VERSION 5.8 ;
BUSBITCHARS "[]" ;
DIVIDERCHAR "/" ;
UNITS
    DATABASE MICRONS 1000 ;
END UNITS

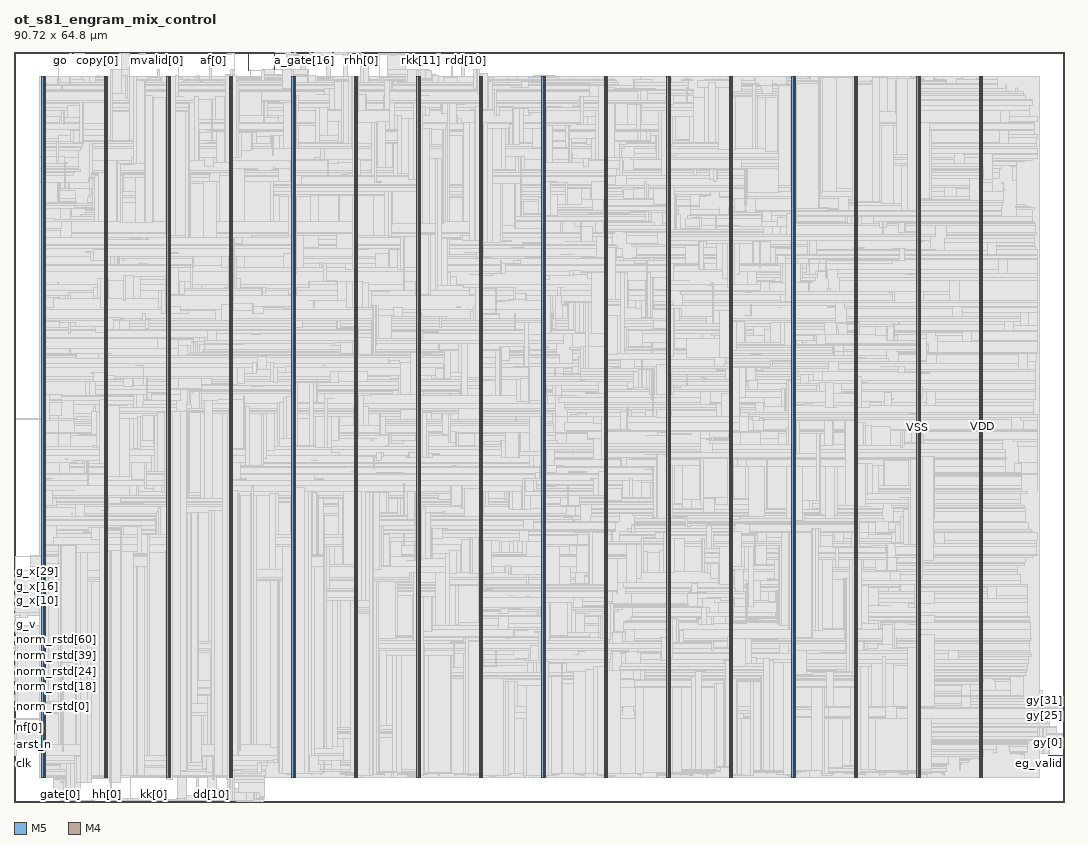
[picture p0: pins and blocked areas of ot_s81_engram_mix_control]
MACRO ot_s81_engram_mix_control
  FOREIGN ot_s81_engram_mix_control 0 0 ;
  CLASS BLOCK ;
  SIZE 90.72 BY 64.8 ;
  PIN a_gate[0]
    DIRECTION OUTPUT ;
    USE SIGNAL ;
    PORT
      LAYER M5 ;
        RECT  23.52 64.716 23.544 64.8 ;
    END
  END a_gate[0]
  PIN a_gate[10]
    DIRECTION OUTPUT ;
    USE SIGNAL ;
    PORT
      LAYER M5 ;
        RECT  24.48 64.716 24.504 64.8 ;
    END
  END a_gate[10]
  PIN a_gate[11]
    DIRECTION OUTPUT ;
    USE SIGNAL ;
    PORT
      LAYER M5 ;
        RECT  24.576 64.716 24.6 64.8 ;
    END
  END a_gate[11]
  PIN a_gate[12]
    DIRECTION OUTPUT ;
    USE SIGNAL ;
    PORT
      LAYER M5 ;
        RECT  24.672 64.716 24.696 64.8 ;
    END
  END a_gate[12]
  PIN a_gate[13]
    DIRECTION OUTPUT ;
    USE SIGNAL ;
    PORT
      LAYER M5 ;
        RECT  24.768 64.716 24.792 64.8 ;
    END
  END a_gate[13]
  PIN a_gate[14]
    DIRECTION OUTPUT ;
    USE SIGNAL ;
    PORT
      LAYER M5 ;
        RECT  24.864 64.716 24.888 64.8 ;
    END
  END a_gate[14]
  PIN a_gate[15]
    DIRECTION OUTPUT ;
    USE SIGNAL ;
    PORT
      LAYER M5 ;
        RECT  24.96 64.716 24.984 64.8 ;
    END
  END a_gate[15]
  PIN a_gate[16]
    DIRECTION OUTPUT ;
    USE SIGNAL ;
    PORT
      LAYER M5 ;
        RECT  25.056 64.716 25.08 64.8 ;
    END
  END a_gate[16]
  PIN a_gate[17]
    DIRECTION OUTPUT ;
    USE SIGNAL ;
    PORT
      LAYER M5 ;
        RECT  25.152 64.716 25.176 64.8 ;
    END
  END a_gate[17]
  PIN a_gate[18]
    DIRECTION OUTPUT ;
    USE SIGNAL ;
    PORT
      LAYER M5 ;
        RECT  25.248 64.716 25.272 64.8 ;
    END
  END a_gate[18]
  PIN a_gate[19]
    DIRECTION OUTPUT ;
    USE SIGNAL ;
    PORT
      LAYER M5 ;
        RECT  25.344 64.716 25.368 64.8 ;
    END
  END a_gate[19]
  PIN a_gate[1]
    DIRECTION OUTPUT ;
    USE SIGNAL ;
    PORT
      LAYER M5 ;
        RECT  23.616 64.716 23.64 64.8 ;
    END
  END a_gate[1]
  PIN a_gate[20]
    DIRECTION OUTPUT ;
    USE SIGNAL ;
    PORT
      LAYER M5 ;
        RECT  25.44 64.716 25.464 64.8 ;
    END
  END a_gate[20]
  PIN a_gate[21]
    DIRECTION OUTPUT ;
    USE SIGNAL ;
    PORT
      LAYER M5 ;
        RECT  25.536 64.716 25.56 64.8 ;
    END
  END a_gate[21]
  PIN a_gate[22]
    DIRECTION OUTPUT ;
    USE SIGNAL ;
    PORT
      LAYER M5 ;
        RECT  25.632 64.716 25.656 64.8 ;
    END
  END a_gate[22]
  PIN a_gate[23]
    DIRECTION OUTPUT ;
    USE SIGNAL ;
    PORT
      LAYER M5 ;
        RECT  25.728 64.716 25.752 64.8 ;
    END
  END a_gate[23]
  PIN a_gate[24]
    DIRECTION OUTPUT ;
    USE SIGNAL ;
    PORT
      LAYER M5 ;
        RECT  25.824 64.716 25.848 64.8 ;
    END
  END a_gate[24]
  PIN a_gate[25]
    DIRECTION OUTPUT ;
    USE SIGNAL ;
    PORT
      LAYER M5 ;
        RECT  25.92 64.716 25.944 64.8 ;
    END
  END a_gate[25]
  PIN a_gate[26]
    DIRECTION OUTPUT ;
    USE SIGNAL ;
    PORT
      LAYER M5 ;
        RECT  26.016 64.716 26.04 64.8 ;
    END
  END a_gate[26]
  PIN a_gate[27]
    DIRECTION OUTPUT ;
    USE SIGNAL ;
    PORT
      LAYER M5 ;
        RECT  26.112 64.716 26.136 64.8 ;
    END
  END a_gate[27]
  PIN a_gate[28]
    DIRECTION OUTPUT ;
    USE SIGNAL ;
    PORT
      LAYER M5 ;
        RECT  26.208 64.716 26.232 64.8 ;
    END
  END a_gate[28]
  PIN a_gate[29]
    DIRECTION OUTPUT ;
    USE SIGNAL ;
    PORT
      LAYER M5 ;
        RECT  26.304 64.716 26.328 64.8 ;
    END
  END a_gate[29]
  PIN a_gate[2]
    DIRECTION OUTPUT ;
    USE SIGNAL ;
    PORT
      LAYER M5 ;
        RECT  23.712 64.716 23.736 64.8 ;
    END
  END a_gate[2]
  PIN a_gate[30]
    DIRECTION OUTPUT ;
    USE SIGNAL ;
    PORT
      LAYER M5 ;
        RECT  26.4 64.716 26.424 64.8 ;
    END
  END a_gate[30]
  PIN a_gate[31]
    DIRECTION OUTPUT ;
    USE SIGNAL ;
    PORT
      LAYER M5 ;
        RECT  26.496 64.716 26.52 64.8 ;
    END
  END a_gate[31]
  PIN a_gate[3]
    DIRECTION OUTPUT ;
    USE SIGNAL ;
    PORT
      LAYER M5 ;
        RECT  23.808 64.716 23.832 64.8 ;
    END
  END a_gate[3]
  PIN a_gate[4]
    DIRECTION OUTPUT ;
    USE SIGNAL ;
    PORT
      LAYER M5 ;
        RECT  23.904 64.716 23.928 64.8 ;
    END
  END a_gate[4]
  PIN a_gate[5]
    DIRECTION OUTPUT ;
    USE SIGNAL ;
    PORT
      LAYER M5 ;
        RECT  24 64.716 24.024 64.8 ;
    END
  END a_gate[5]
  PIN a_gate[6]
    DIRECTION OUTPUT ;
    USE SIGNAL ;
    PORT
      LAYER M5 ;
        RECT  24.096 64.716 24.12 64.8 ;
    END
  END a_gate[6]
  PIN a_gate[7]
    DIRECTION OUTPUT ;
    USE SIGNAL ;
    PORT
      LAYER M5 ;
        RECT  24.192 64.716 24.216 64.8 ;
    END
  END a_gate[7]
  PIN a_gate[8]
    DIRECTION OUTPUT ;
    USE SIGNAL ;
    PORT
      LAYER M5 ;
        RECT  24.288 64.716 24.312 64.8 ;
    END
  END a_gate[8]
  PIN a_gate[9]
    DIRECTION OUTPUT ;
    USE SIGNAL ;
    PORT
      LAYER M5 ;
        RECT  24.384 64.716 24.408 64.8 ;
    END
  END a_gate[9]
  PIN add_copy[0]
    DIRECTION INPUT ;
    USE SIGNAL ;
    PORT
      LAYER M5 ;
        RECT  18.528 64.716 18.552 64.8 ;
    END
  END add_copy[0]
  PIN add_copy[1]
    DIRECTION INPUT ;
    USE SIGNAL ;
    PORT
      LAYER M5 ;
        RECT  18.624 64.716 18.648 64.8 ;
    END
  END add_copy[1]
  PIN add_copy[2]
    DIRECTION INPUT ;
    USE SIGNAL ;
    PORT
      LAYER M5 ;
        RECT  18.72 64.716 18.744 64.8 ;
    END
  END add_copy[2]
  PIN add_copy[3]
    DIRECTION INPUT ;
    USE SIGNAL ;
    PORT
      LAYER M5 ;
        RECT  18.816 64.716 18.84 64.8 ;
    END
  END add_copy[3]
  PIN add_copy[4]
    DIRECTION INPUT ;
    USE SIGNAL ;
    PORT
      LAYER M5 ;
        RECT  18.912 64.716 18.936 64.8 ;
    END
  END add_copy[4]
  PIN add_copy[5]
    DIRECTION INPUT ;
    USE SIGNAL ;
    PORT
      LAYER M5 ;
        RECT  19.008 64.716 19.032 64.8 ;
    END
  END add_copy[5]
  PIN add_copy[6]
    DIRECTION INPUT ;
    USE SIGNAL ;
    PORT
      LAYER M5 ;
        RECT  19.104 64.716 19.128 64.8 ;
    END
  END add_copy[6]
  PIN add_copy[7]
    DIRECTION INPUT ;
    USE SIGNAL ;
    PORT
      LAYER M5 ;
        RECT  19.2 64.716 19.224 64.8 ;
    END
  END add_copy[7]
  PIN af[0]
    DIRECTION INPUT ;
    USE SIGNAL ;
    PORT
      LAYER M5 ;
        RECT  17.184 64.716 17.208 64.8 ;
    END
  END af[0]
  PIN af[1]
    DIRECTION INPUT ;
    USE SIGNAL ;
    PORT
      LAYER M5 ;
        RECT  17.28 64.716 17.304 64.8 ;
    END
  END af[1]
  PIN af[2]
    DIRECTION INPUT ;
    USE SIGNAL ;
    PORT
      LAYER M5 ;
        RECT  17.376 64.716 17.4 64.8 ;
    END
  END af[2]
  PIN af[3]
    DIRECTION INPUT ;
    USE SIGNAL ;
    PORT
      LAYER M5 ;
        RECT  17.472 64.716 17.496 64.8 ;
    END
  END af[3]
  PIN arst_n
    DIRECTION INPUT ;
    USE SIGNAL ;
    PORT
      LAYER M4 ;
        RECT  0 4.992 0.084 5.016 ;
    END
  END arst_n
  PIN avalid[0]
    DIRECTION INPUT ;
    USE SIGNAL ;
    PORT
      LAYER M5 ;
        RECT  15.84 64.716 15.864 64.8 ;
    END
  END avalid[0]
  PIN avalid[1]
    DIRECTION INPUT ;
    USE SIGNAL ;
    PORT
      LAYER M5 ;
        RECT  15.936 64.716 15.96 64.8 ;
    END
  END avalid[1]
  PIN avalid[2]
    DIRECTION INPUT ;
    USE SIGNAL ;
    PORT
      LAYER M5 ;
        RECT  16.032 64.716 16.056 64.8 ;
    END
  END avalid[2]
  PIN avalid[3]
    DIRECTION INPUT ;
    USE SIGNAL ;
    PORT
      LAYER M5 ;
        RECT  16.128 64.716 16.152 64.8 ;
    END
  END avalid[3]
  PIN clk
    DIRECTION INPUT ;
    USE SIGNAL ;
    PORT
      LAYER M4 ;
        RECT  0 4.032 0.084 4.056 ;
    END
  END clk
  PIN copy[0]
    DIRECTION INPUT ;
    USE SIGNAL ;
    PORT
      LAYER M5 ;
        RECT  7.2 64.716 7.224 64.8 ;
    END
  END copy[0]
  PIN copy[1]
    DIRECTION INPUT ;
    USE SIGNAL ;
    PORT
      LAYER M5 ;
        RECT  7.296 64.716 7.32 64.8 ;
    END
  END copy[1]
  PIN dd[0]
    DIRECTION OUTPUT ;
    USE SIGNAL ;
    PORT
      LAYER M5 ;
        RECT  16.128 0 16.152 0.084 ;
    END
  END dd[0]
  PIN dd[10]
    DIRECTION OUTPUT ;
    USE SIGNAL ;
    PORT
      LAYER M5 ;
        RECT  17.088 0 17.112 0.084 ;
    END
  END dd[10]
  PIN dd[11]
    DIRECTION OUTPUT ;
    USE SIGNAL ;
    PORT
      LAYER M5 ;
        RECT  17.184 0 17.208 0.084 ;
    END
  END dd[11]
  PIN dd[12]
    DIRECTION OUTPUT ;
    USE SIGNAL ;
    PORT
      LAYER M5 ;
        RECT  17.28 0 17.304 0.084 ;
    END
  END dd[12]
  PIN dd[13]
    DIRECTION OUTPUT ;
    USE SIGNAL ;
    PORT
      LAYER M5 ;
        RECT  17.376 0 17.4 0.084 ;
    END
  END dd[13]
  PIN dd[14]
    DIRECTION OUTPUT ;
    USE SIGNAL ;
    PORT
      LAYER M5 ;
        RECT  17.472 0 17.496 0.084 ;
    END
  END dd[14]
  PIN dd[15]
    DIRECTION OUTPUT ;
    USE SIGNAL ;
    PORT
      LAYER M5 ;
        RECT  17.568 0 17.592 0.084 ;
    END
  END dd[15]
  PIN dd[16]
    DIRECTION OUTPUT ;
    USE SIGNAL ;
    PORT
      LAYER M5 ;
        RECT  17.664 0 17.688 0.084 ;
    END
  END dd[16]
  PIN dd[17]
    DIRECTION OUTPUT ;
    USE SIGNAL ;
    PORT
      LAYER M5 ;
        RECT  17.76 0 17.784 0.084 ;
    END
  END dd[17]
  PIN dd[18]
    DIRECTION OUTPUT ;
    USE SIGNAL ;
    PORT
      LAYER M5 ;
        RECT  17.856 0 17.88 0.084 ;
    END
  END dd[18]
  PIN dd[19]
    DIRECTION OUTPUT ;
    USE SIGNAL ;
    PORT
      LAYER M5 ;
        RECT  17.952 0 17.976 0.084 ;
    END
  END dd[19]
  PIN dd[1]
    DIRECTION OUTPUT ;
    USE SIGNAL ;
    PORT
      LAYER M5 ;
        RECT  16.224 0 16.248 0.084 ;
    END
  END dd[1]
  PIN dd[20]
    DIRECTION OUTPUT ;
    USE SIGNAL ;
    PORT
      LAYER M5 ;
        RECT  18.048 0 18.072 0.084 ;
    END
  END dd[20]
  PIN dd[21]
    DIRECTION OUTPUT ;
    USE SIGNAL ;
    PORT
      LAYER M5 ;
        RECT  18.144 0 18.168 0.084 ;
    END
  END dd[21]
  PIN dd[22]
    DIRECTION OUTPUT ;
    USE SIGNAL ;
    PORT
      LAYER M5 ;
        RECT  18.24 0 18.264 0.084 ;
    END
  END dd[22]
  PIN dd[23]
    DIRECTION OUTPUT ;
    USE SIGNAL ;
    PORT
      LAYER M5 ;
        RECT  18.336 0 18.36 0.084 ;
    END
  END dd[23]
  PIN dd[24]
    DIRECTION OUTPUT ;
    USE SIGNAL ;
    PORT
      LAYER M5 ;
        RECT  18.432 0 18.456 0.084 ;
    END
  END dd[24]
  PIN dd[25]
    DIRECTION OUTPUT ;
    USE SIGNAL ;
    PORT
      LAYER M5 ;
        RECT  18.528 0 18.552 0.084 ;
    END
  END dd[25]
  PIN dd[26]
    DIRECTION OUTPUT ;
    USE SIGNAL ;
    PORT
      LAYER M5 ;
        RECT  18.624 0 18.648 0.084 ;
    END
  END dd[26]
  PIN dd[27]
    DIRECTION OUTPUT ;
    USE SIGNAL ;
    PORT
      LAYER M5 ;
        RECT  18.72 0 18.744 0.084 ;
    END
  END dd[27]
  PIN dd[28]
    DIRECTION OUTPUT ;
    USE SIGNAL ;
    PORT
      LAYER M5 ;
        RECT  18.816 0 18.84 0.084 ;
    END
  END dd[28]
  PIN dd[29]
    DIRECTION OUTPUT ;
    USE SIGNAL ;
    PORT
      LAYER M5 ;
        RECT  18.912 0 18.936 0.084 ;
    END
  END dd[29]
  PIN dd[2]
    DIRECTION OUTPUT ;
    USE SIGNAL ;
    PORT
      LAYER M5 ;
        RECT  16.32 0 16.344 0.084 ;
    END
  END dd[2]
  PIN dd[30]
    DIRECTION OUTPUT ;
    USE SIGNAL ;
    PORT
      LAYER M5 ;
        RECT  19.008 0 19.032 0.084 ;
    END
  END dd[30]
  PIN dd[31]
    DIRECTION OUTPUT ;
    USE SIGNAL ;
    PORT
      LAYER M5 ;
        RECT  19.104 0 19.128 0.084 ;
    END
  END dd[31]
  PIN dd[3]
    DIRECTION OUTPUT ;
    USE SIGNAL ;
    PORT
      LAYER M5 ;
        RECT  16.416 0 16.44 0.084 ;
    END
  END dd[3]
  PIN dd[4]
    DIRECTION OUTPUT ;
    USE SIGNAL ;
    PORT
      LAYER M5 ;
        RECT  16.512 0 16.536 0.084 ;
    END
  END dd[4]
  PIN dd[5]
    DIRECTION OUTPUT ;
    USE SIGNAL ;
    PORT
      LAYER M5 ;
        RECT  16.608 0 16.632 0.084 ;
    END
  END dd[5]
  PIN dd[6]
    DIRECTION OUTPUT ;
    USE SIGNAL ;
    PORT
      LAYER M5 ;
        RECT  16.704 0 16.728 0.084 ;
    END
  END dd[6]
  PIN dd[7]
    DIRECTION OUTPUT ;
    USE SIGNAL ;
    PORT
      LAYER M5 ;
        RECT  16.8 0 16.824 0.084 ;
    END
  END dd[7]
  PIN dd[8]
    DIRECTION OUTPUT ;
    USE SIGNAL ;
    PORT
      LAYER M5 ;
        RECT  16.896 0 16.92 0.084 ;
    END
  END dd[8]
  PIN dd[9]
    DIRECTION OUTPUT ;
    USE SIGNAL ;
    PORT
      LAYER M5 ;
        RECT  16.992 0 17.016 0.084 ;
    END
  END dd[9]
  PIN eg_valid
    DIRECTION INPUT ;
    USE SIGNAL ;
    PORT
      LAYER M4 ;
        RECT  90.636 4.032 90.72 4.056 ;
    END
    PORT
      LAYER M4 ;
        RECT  89.413 4.032 90.684 4.056 ;
    END
  END eg_valid
  PIN fault
    DIRECTION OUTPUT ;
    USE SIGNAL ;
    PORT
      LAYER M5 ;
        RECT  22.464 64.716 22.488 64.8 ;
    END
    PORT
      LAYER M5 ;
        RECT  22.464 63.301 22.488 64.784 ;
    END
  END fault
  PIN g_fault[0]
    DIRECTION INPUT ;
    USE SIGNAL ;
    PORT
      LAYER M4 ;
        RECT  90.636 9.12 90.72 9.144 ;
    END
  END g_fault[0]
  PIN g_fault[1]
    DIRECTION INPUT ;
    USE SIGNAL ;
    PORT
      LAYER M4 ;
        RECT  90.636 9.216 90.72 9.24 ;
    END
  END g_fault[1]
  PIN g_v
    DIRECTION OUTPUT ;
    USE SIGNAL ;
    PORT
      LAYER M4 ;
        RECT  0 15.36 0.084 15.384 ;
    END
    PORT
      LAYER M4 ;
        RECT  0.06 15.36 0.137 15.384 ;
    END
  END g_v
  PIN g_x[0]
    DIRECTION OUTPUT ;
    USE SIGNAL ;
    PORT
      LAYER M4 ;
        RECT  0 16.416 0.084 16.44 ;
    END
  END g_x[0]
  PIN g_x[10]
    DIRECTION OUTPUT ;
    USE SIGNAL ;
    PORT
      LAYER M4 ;
        RECT  0 17.376 0.084 17.4 ;
    END
  END g_x[10]
  PIN g_x[11]
    DIRECTION OUTPUT ;
    USE SIGNAL ;
    PORT
      LAYER M4 ;
        RECT  0 17.472 0.084 17.496 ;
    END
  END g_x[11]
  PIN g_x[12]
    DIRECTION OUTPUT ;
    USE SIGNAL ;
    PORT
      LAYER M4 ;
        RECT  0 17.568 0.084 17.592 ;
    END
  END g_x[12]
  PIN g_x[13]
    DIRECTION OUTPUT ;
    USE SIGNAL ;
    PORT
      LAYER M4 ;
        RECT  0 17.664 0.084 17.688 ;
    END
  END g_x[13]
  PIN g_x[14]
    DIRECTION OUTPUT ;
    USE SIGNAL ;
    PORT
      LAYER M4 ;
        RECT  0 17.76 0.084 17.784 ;
    END
  END g_x[14]
  PIN g_x[15]
    DIRECTION OUTPUT ;
    USE SIGNAL ;
    PORT
      LAYER M4 ;
        RECT  0 17.856 0.084 17.88 ;
    END
  END g_x[15]
  PIN g_x[16]
    DIRECTION OUTPUT ;
    USE SIGNAL ;
    PORT
      LAYER M4 ;
        RECT  0 17.952 0.084 17.976 ;
    END
  END g_x[16]
  PIN g_x[17]
    DIRECTION OUTPUT ;
    USE SIGNAL ;
    PORT
      LAYER M4 ;
        RECT  0 18.048 0.084 18.072 ;
    END
  END g_x[17]
  PIN g_x[18]
    DIRECTION OUTPUT ;
    USE SIGNAL ;
    PORT
      LAYER M4 ;
        RECT  0 18.144 0.084 18.168 ;
    END
  END g_x[18]
  PIN g_x[19]
    DIRECTION OUTPUT ;
    USE SIGNAL ;
    PORT
      LAYER M4 ;
        RECT  0 18.24 0.084 18.264 ;
    END
  END g_x[19]
  PIN g_x[1]
    DIRECTION OUTPUT ;
    USE SIGNAL ;
    PORT
      LAYER M4 ;
        RECT  0 16.512 0.084 16.536 ;
    END
  END g_x[1]
  PIN g_x[20]
    DIRECTION OUTPUT ;
    USE SIGNAL ;
    PORT
      LAYER M4 ;
        RECT  0 18.336 0.084 18.36 ;
    END
  END g_x[20]
  PIN g_x[21]
    DIRECTION OUTPUT ;
    USE SIGNAL ;
    PORT
      LAYER M4 ;
        RECT  0 18.432 0.084 18.456 ;
    END
  END g_x[21]
  PIN g_x[22]
    DIRECTION OUTPUT ;
    USE SIGNAL ;
    PORT
      LAYER M4 ;
        RECT  0 18.528 0.084 18.552 ;
    END
  END g_x[22]
  PIN g_x[23]
    DIRECTION OUTPUT ;
    USE SIGNAL ;
    PORT
      LAYER M4 ;
        RECT  0 18.624 0.084 18.648 ;
    END
  END g_x[23]
  PIN g_x[24]
    DIRECTION OUTPUT ;
    USE SIGNAL ;
    PORT
      LAYER M4 ;
        RECT  0 18.72 0.084 18.744 ;
    END
  END g_x[24]
  PIN g_x[25]
    DIRECTION OUTPUT ;
    USE SIGNAL ;
    PORT
      LAYER M4 ;
        RECT  0 18.816 0.084 18.84 ;
    END
  END g_x[25]
  PIN g_x[26]
    DIRECTION OUTPUT ;
    USE SIGNAL ;
    PORT
      LAYER M4 ;
        RECT  0 18.912 0.084 18.936 ;
    END
  END g_x[26]
  PIN g_x[27]
    DIRECTION OUTPUT ;
    USE SIGNAL ;
    PORT
      LAYER M4 ;
        RECT  0 19.008 0.084 19.032 ;
    END
  END g_x[27]
  PIN g_x[28]
    DIRECTION OUTPUT ;
    USE SIGNAL ;
    PORT
      LAYER M4 ;
        RECT  0 19.104 0.084 19.128 ;
    END
  END g_x[28]
  PIN g_x[29]
    DIRECTION OUTPUT ;
    USE SIGNAL ;
    PORT
      LAYER M4 ;
        RECT  0 19.2 0.084 19.224 ;
    END
  END g_x[29]
  PIN g_x[2]
    DIRECTION OUTPUT ;
    USE SIGNAL ;
    PORT
      LAYER M4 ;
        RECT  0 16.608 0.084 16.632 ;
    END
  END g_x[2]
  PIN g_x[30]
    DIRECTION OUTPUT ;
    USE SIGNAL ;
    PORT
      LAYER M4 ;
        RECT  0 19.296 0.084 19.32 ;
    END
  END g_x[30]
  PIN g_x[31]
    DIRECTION OUTPUT ;
    USE SIGNAL ;
    PORT
      LAYER M4 ;
        RECT  0 19.392 0.084 19.416 ;
    END
  END g_x[31]
  PIN g_x[3]
    DIRECTION OUTPUT ;
    USE SIGNAL ;
    PORT
      LAYER M4 ;
        RECT  0 16.704 0.084 16.728 ;
    END
  END g_x[3]
  PIN g_x[4]
    DIRECTION OUTPUT ;
    USE SIGNAL ;
    PORT
      LAYER M4 ;
        RECT  0 16.8 0.084 16.824 ;
    END
  END g_x[4]
  PIN g_x[5]
    DIRECTION OUTPUT ;
    USE SIGNAL ;
    PORT
      LAYER M4 ;
        RECT  0 16.896 0.084 16.92 ;
    END
  END g_x[5]
  PIN g_x[6]
    DIRECTION OUTPUT ;
    USE SIGNAL ;
    PORT
      LAYER M4 ;
        RECT  0 16.992 0.084 17.016 ;
    END
  END g_x[6]
  PIN g_x[7]
    DIRECTION OUTPUT ;
    USE SIGNAL ;
    PORT
      LAYER M4 ;
        RECT  0 17.088 0.084 17.112 ;
    END
  END g_x[7]
  PIN g_x[8]
    DIRECTION OUTPUT ;
    USE SIGNAL ;
    PORT
      LAYER M4 ;
        RECT  0 17.184 0.084 17.208 ;
    END
  END g_x[8]
  PIN g_x[9]
    DIRECTION OUTPUT ;
    USE SIGNAL ;
    PORT
      LAYER M4 ;
        RECT  0 17.28 0.084 17.304 ;
    END
  END g_x[9]
  PIN gate[0]
    DIRECTION OUTPUT ;
    USE SIGNAL ;
    PORT
      LAYER M5 ;
        RECT  4.032 0 4.056 0.084 ;
    END
  END gate[0]
  PIN gate[10]
    DIRECTION OUTPUT ;
    USE SIGNAL ;
    PORT
      LAYER M5 ;
        RECT  4.992 0 5.016 0.084 ;
    END
  END gate[10]
  PIN gate[11]
    DIRECTION OUTPUT ;
    USE SIGNAL ;
    PORT
      LAYER M5 ;
        RECT  5.088 0 5.112 0.084 ;
    END
  END gate[11]
  PIN gate[12]
    DIRECTION OUTPUT ;
    USE SIGNAL ;
    PORT
      LAYER M5 ;
        RECT  5.184 0 5.208 0.084 ;
    END
  END gate[12]
  PIN gate[13]
    DIRECTION OUTPUT ;
    USE SIGNAL ;
    PORT
      LAYER M5 ;
        RECT  5.28 0 5.304 0.084 ;
    END
  END gate[13]
  PIN gate[14]
    DIRECTION OUTPUT ;
    USE SIGNAL ;
    PORT
      LAYER M5 ;
        RECT  5.376 0 5.4 0.084 ;
    END
  END gate[14]
  PIN gate[15]
    DIRECTION OUTPUT ;
    USE SIGNAL ;
    PORT
      LAYER M5 ;
        RECT  5.472 0 5.496 0.084 ;
    END
  END gate[15]
  PIN gate[16]
    DIRECTION OUTPUT ;
    USE SIGNAL ;
    PORT
      LAYER M5 ;
        RECT  5.568 0 5.592 0.084 ;
    END
  END gate[16]
  PIN gate[17]
    DIRECTION OUTPUT ;
    USE SIGNAL ;
    PORT
      LAYER M5 ;
        RECT  5.664 0 5.688 0.084 ;
    END
  END gate[17]
  PIN gate[18]
    DIRECTION OUTPUT ;
    USE SIGNAL ;
    PORT
      LAYER M5 ;
        RECT  5.76 0 5.784 0.084 ;
    END
  END gate[18]
  PIN gate[19]
    DIRECTION OUTPUT ;
    USE SIGNAL ;
    PORT
      LAYER M5 ;
        RECT  5.856 0 5.88 0.084 ;
    END
  END gate[19]
  PIN gate[1]
    DIRECTION OUTPUT ;
    USE SIGNAL ;
    PORT
      LAYER M5 ;
        RECT  4.128 0 4.152 0.084 ;
    END
  END gate[1]
  PIN gate[20]
    DIRECTION OUTPUT ;
    USE SIGNAL ;
    PORT
      LAYER M5 ;
        RECT  5.952 0 5.976 0.084 ;
    END
  END gate[20]
  PIN gate[21]
    DIRECTION OUTPUT ;
    USE SIGNAL ;
    PORT
      LAYER M5 ;
        RECT  6.048 0 6.072 0.084 ;
    END
  END gate[21]
  PIN gate[22]
    DIRECTION OUTPUT ;
    USE SIGNAL ;
    PORT
      LAYER M5 ;
        RECT  6.144 0 6.168 0.084 ;
    END
  END gate[22]
  PIN gate[23]
    DIRECTION OUTPUT ;
    USE SIGNAL ;
    PORT
      LAYER M5 ;
        RECT  6.24 0 6.264 0.084 ;
    END
  END gate[23]
  PIN gate[24]
    DIRECTION OUTPUT ;
    USE SIGNAL ;
    PORT
      LAYER M5 ;
        RECT  6.336 0 6.36 0.084 ;
    END
  END gate[24]
  PIN gate[25]
    DIRECTION OUTPUT ;
    USE SIGNAL ;
    PORT
      LAYER M5 ;
        RECT  6.432 0 6.456 0.084 ;
    END
  END gate[25]
  PIN gate[26]
    DIRECTION OUTPUT ;
    USE SIGNAL ;
    PORT
      LAYER M5 ;
        RECT  6.528 0 6.552 0.084 ;
    END
  END gate[26]
  PIN gate[27]
    DIRECTION OUTPUT ;
    USE SIGNAL ;
    PORT
      LAYER M5 ;
        RECT  6.624 0 6.648 0.084 ;
    END
  END gate[27]
  PIN gate[28]
    DIRECTION OUTPUT ;
    USE SIGNAL ;
    PORT
      LAYER M5 ;
        RECT  6.72 0 6.744 0.084 ;
    END
  END gate[28]
  PIN gate[29]
    DIRECTION OUTPUT ;
    USE SIGNAL ;
    PORT
      LAYER M5 ;
        RECT  6.816 0 6.84 0.084 ;
    END
  END gate[29]
  PIN gate[2]
    DIRECTION OUTPUT ;
    USE SIGNAL ;
    PORT
      LAYER M5 ;
        RECT  4.224 0 4.248 0.084 ;
    END
  END gate[2]
  PIN gate[30]
    DIRECTION OUTPUT ;
    USE SIGNAL ;
    PORT
      LAYER M5 ;
        RECT  6.912 0 6.936 0.084 ;
    END
  END gate[30]
  PIN gate[31]
    DIRECTION OUTPUT ;
    USE SIGNAL ;
    PORT
      LAYER M5 ;
        RECT  7.008 0 7.032 0.084 ;
    END
  END gate[31]
  PIN gate[3]
    DIRECTION OUTPUT ;
    USE SIGNAL ;
    PORT
      LAYER M5 ;
        RECT  4.32 0 4.344 0.084 ;
    END
  END gate[3]
  PIN gate[4]
    DIRECTION OUTPUT ;
    USE SIGNAL ;
    PORT
      LAYER M5 ;
        RECT  4.416 0 4.44 0.084 ;
    END
  END gate[4]
  PIN gate[5]
    DIRECTION OUTPUT ;
    USE SIGNAL ;
    PORT
      LAYER M5 ;
        RECT  4.512 0 4.536 0.084 ;
    END
  END gate[5]
  PIN gate[6]
    DIRECTION OUTPUT ;
    USE SIGNAL ;
    PORT
      LAYER M5 ;
        RECT  4.608 0 4.632 0.084 ;
    END
  END gate[6]
  PIN gate[7]
    DIRECTION OUTPUT ;
    USE SIGNAL ;
    PORT
      LAYER M5 ;
        RECT  4.704 0 4.728 0.084 ;
    END
  END gate[7]
  PIN gate[8]
    DIRECTION OUTPUT ;
    USE SIGNAL ;
    PORT
      LAYER M5 ;
        RECT  4.8 0 4.824 0.084 ;
    END
  END gate[8]
  PIN gate[9]
    DIRECTION OUTPUT ;
    USE SIGNAL ;
    PORT
      LAYER M5 ;
        RECT  4.896 0 4.92 0.084 ;
    END
  END gate[9]
  PIN gate_copy[0]
    DIRECTION OUTPUT ;
    USE SIGNAL ;
    PORT
      LAYER M5 ;
        RECT  21.312 64.716 21.336 64.8 ;
    END
  END gate_copy[0]
  PIN gate_copy[1]
    DIRECTION OUTPUT ;
    USE SIGNAL ;
    PORT
      LAYER M5 ;
        RECT  21.408 64.716 21.432 64.8 ;
    END
  END gate_copy[1]
  PIN gate_v
    DIRECTION OUTPUT ;
    USE SIGNAL ;
    PORT
      LAYER M5 ;
        RECT  20.256 64.716 20.28 64.8 ;
    END
    PORT
      LAYER M5 ;
        RECT  20.256 63.205 20.28 64.784 ;
    END
  END gate_v
  PIN go
    DIRECTION INPUT ;
    USE SIGNAL ;
    PORT
      LAYER M5 ;
        RECT  4.032 64.716 4.056 64.8 ;
    END
    PORT
      LAYER M5 ;
        RECT  4.032 64.691 4.056 64.784 ;
    END
  END go
  PIN gy[0]
    DIRECTION INPUT ;
    USE SIGNAL ;
    PORT
      LAYER M4 ;
        RECT  90.636 5.088 90.72 5.112 ;
    END
  END gy[0]
  PIN gy[10]
    DIRECTION INPUT ;
    USE SIGNAL ;
    PORT
      LAYER M4 ;
        RECT  90.636 6.048 90.72 6.072 ;
    END
  END gy[10]
  PIN gy[11]
    DIRECTION INPUT ;
    USE SIGNAL ;
    PORT
      LAYER M4 ;
        RECT  90.636 6.144 90.72 6.168 ;
    END
  END gy[11]
  PIN gy[12]
    DIRECTION INPUT ;
    USE SIGNAL ;
    PORT
      LAYER M4 ;
        RECT  90.636 6.24 90.72 6.264 ;
    END
  END gy[12]
  PIN gy[13]
    DIRECTION INPUT ;
    USE SIGNAL ;
    PORT
      LAYER M4 ;
        RECT  90.636 6.336 90.72 6.36 ;
    END
  END gy[13]
  PIN gy[14]
    DIRECTION INPUT ;
    USE SIGNAL ;
    PORT
      LAYER M4 ;
        RECT  90.636 6.432 90.72 6.456 ;
    END
  END gy[14]
  PIN gy[15]
    DIRECTION INPUT ;
    USE SIGNAL ;
    PORT
      LAYER M4 ;
        RECT  90.636 6.528 90.72 6.552 ;
    END
  END gy[15]
  PIN gy[16]
    DIRECTION INPUT ;
    USE SIGNAL ;
    PORT
      LAYER M4 ;
        RECT  90.636 6.624 90.72 6.648 ;
    END
  END gy[16]
  PIN gy[17]
    DIRECTION INPUT ;
    USE SIGNAL ;
    PORT
      LAYER M4 ;
        RECT  90.636 6.72 90.72 6.744 ;
    END
  END gy[17]
  PIN gy[18]
    DIRECTION INPUT ;
    USE SIGNAL ;
    PORT
      LAYER M4 ;
        RECT  90.636 6.816 90.72 6.84 ;
    END
  END gy[18]
  PIN gy[19]
    DIRECTION INPUT ;
    USE SIGNAL ;
    PORT
      LAYER M4 ;
        RECT  90.636 6.912 90.72 6.936 ;
    END
  END gy[19]
  PIN gy[1]
    DIRECTION INPUT ;
    USE SIGNAL ;
    PORT
      LAYER M4 ;
        RECT  90.636 5.184 90.72 5.208 ;
    END
  END gy[1]
  PIN gy[20]
    DIRECTION INPUT ;
    USE SIGNAL ;
    PORT
      LAYER M4 ;
        RECT  90.636 7.008 90.72 7.032 ;
    END
  END gy[20]
  PIN gy[21]
    DIRECTION INPUT ;
    USE SIGNAL ;
    PORT
      LAYER M4 ;
        RECT  90.636 7.104 90.72 7.128 ;
    END
  END gy[21]
  PIN gy[22]
    DIRECTION INPUT ;
    USE SIGNAL ;
    PORT
      LAYER M4 ;
        RECT  90.636 7.2 90.72 7.224 ;
    END
  END gy[22]
  PIN gy[23]
    DIRECTION INPUT ;
    USE SIGNAL ;
    PORT
      LAYER M4 ;
        RECT  90.636 7.296 90.72 7.32 ;
    END
  END gy[23]
  PIN gy[24]
    DIRECTION INPUT ;
    USE SIGNAL ;
    PORT
      LAYER M4 ;
        RECT  90.636 7.392 90.72 7.416 ;
    END
  END gy[24]
  PIN gy[25]
    DIRECTION INPUT ;
    USE SIGNAL ;
    PORT
      LAYER M4 ;
        RECT  90.636 7.488 90.72 7.512 ;
    END
  END gy[25]
  PIN gy[26]
    DIRECTION INPUT ;
    USE SIGNAL ;
    PORT
      LAYER M4 ;
        RECT  90.636 7.584 90.72 7.608 ;
    END
  END gy[26]
  PIN gy[27]
    DIRECTION INPUT ;
    USE SIGNAL ;
    PORT
      LAYER M4 ;
        RECT  90.636 7.68 90.72 7.704 ;
    END
  END gy[27]
  PIN gy[28]
    DIRECTION INPUT ;
    USE SIGNAL ;
    PORT
      LAYER M4 ;
        RECT  90.636 7.776 90.72 7.8 ;
    END
  END gy[28]
  PIN gy[29]
    DIRECTION INPUT ;
    USE SIGNAL ;
    PORT
      LAYER M4 ;
        RECT  90.636 7.872 90.72 7.896 ;
    END
  END gy[29]
  PIN gy[2]
    DIRECTION INPUT ;
    USE SIGNAL ;
    PORT
      LAYER M4 ;
        RECT  90.636 5.28 90.72 5.304 ;
    END
  END gy[2]
  PIN gy[30]
    DIRECTION INPUT ;
    USE SIGNAL ;
    PORT
      LAYER M4 ;
        RECT  90.636 7.968 90.72 7.992 ;
    END
  END gy[30]
  PIN gy[31]
    DIRECTION INPUT ;
    USE SIGNAL ;
    PORT
      LAYER M4 ;
        RECT  90.636 8.064 90.72 8.088 ;
    END
  END gy[31]
  PIN gy[3]
    DIRECTION INPUT ;
    USE SIGNAL ;
    PORT
      LAYER M4 ;
        RECT  90.636 5.376 90.72 5.4 ;
    END
  END gy[3]
  PIN gy[4]
    DIRECTION INPUT ;
    USE SIGNAL ;
    PORT
      LAYER M4 ;
        RECT  90.636 5.472 90.72 5.496 ;
    END
  END gy[4]
  PIN gy[5]
    DIRECTION INPUT ;
    USE SIGNAL ;
    PORT
      LAYER M4 ;
        RECT  90.636 5.568 90.72 5.592 ;
    END
  END gy[5]
  PIN gy[6]
    DIRECTION INPUT ;
    USE SIGNAL ;
    PORT
      LAYER M4 ;
        RECT  90.636 5.664 90.72 5.688 ;
    END
  END gy[6]
  PIN gy[7]
    DIRECTION INPUT ;
    USE SIGNAL ;
    PORT
      LAYER M4 ;
        RECT  90.636 5.76 90.72 5.784 ;
    END
  END gy[7]
  PIN gy[8]
    DIRECTION INPUT ;
    USE SIGNAL ;
    PORT
      LAYER M4 ;
        RECT  90.636 5.856 90.72 5.88 ;
    END
  END gy[8]
  PIN gy[9]
    DIRECTION INPUT ;
    USE SIGNAL ;
    PORT
      LAYER M4 ;
        RECT  90.636 5.952 90.72 5.976 ;
    END
  END gy[9]
  PIN hh[0]
    DIRECTION OUTPUT ;
    USE SIGNAL ;
    PORT
      LAYER M5 ;
        RECT  8.064 0 8.088 0.084 ;
    END
  END hh[0]
  PIN hh[10]
    DIRECTION OUTPUT ;
    USE SIGNAL ;
    PORT
      LAYER M5 ;
        RECT  9.024 0 9.048 0.084 ;
    END
  END hh[10]
  PIN hh[11]
    DIRECTION OUTPUT ;
    USE SIGNAL ;
    PORT
      LAYER M5 ;
        RECT  9.12 0 9.144 0.084 ;
    END
  END hh[11]
  PIN hh[12]
    DIRECTION OUTPUT ;
    USE SIGNAL ;
    PORT
      LAYER M5 ;
        RECT  9.216 0 9.24 0.084 ;
    END
  END hh[12]
  PIN hh[13]
    DIRECTION OUTPUT ;
    USE SIGNAL ;
    PORT
      LAYER M5 ;
        RECT  9.312 0 9.336 0.084 ;
    END
  END hh[13]
  PIN hh[14]
    DIRECTION OUTPUT ;
    USE SIGNAL ;
    PORT
      LAYER M5 ;
        RECT  9.408 0 9.432 0.084 ;
    END
  END hh[14]
  PIN hh[15]
    DIRECTION OUTPUT ;
    USE SIGNAL ;
    PORT
      LAYER M5 ;
        RECT  9.504 0 9.528 0.084 ;
    END
  END hh[15]
  PIN hh[16]
    DIRECTION OUTPUT ;
    USE SIGNAL ;
    PORT
      LAYER M5 ;
        RECT  9.6 0 9.624 0.084 ;
    END
  END hh[16]
  PIN hh[17]
    DIRECTION OUTPUT ;
    USE SIGNAL ;
    PORT
      LAYER M5 ;
        RECT  9.696 0 9.72 0.084 ;
    END
  END hh[17]
  PIN hh[18]
    DIRECTION OUTPUT ;
    USE SIGNAL ;
    PORT
      LAYER M5 ;
        RECT  9.792 0 9.816 0.084 ;
    END
  END hh[18]
  PIN hh[19]
    DIRECTION OUTPUT ;
    USE SIGNAL ;
    PORT
      LAYER M5 ;
        RECT  9.888 0 9.912 0.084 ;
    END
  END hh[19]
  PIN hh[1]
    DIRECTION OUTPUT ;
    USE SIGNAL ;
    PORT
      LAYER M5 ;
        RECT  8.16 0 8.184 0.084 ;
    END
  END hh[1]
  PIN hh[20]
    DIRECTION OUTPUT ;
    USE SIGNAL ;
    PORT
      LAYER M5 ;
        RECT  9.984 0 10.008 0.084 ;
    END
  END hh[20]
  PIN hh[21]
    DIRECTION OUTPUT ;
    USE SIGNAL ;
    PORT
      LAYER M5 ;
        RECT  10.08 0 10.104 0.084 ;
    END
  END hh[21]
  PIN hh[22]
    DIRECTION OUTPUT ;
    USE SIGNAL ;
    PORT
      LAYER M5 ;
        RECT  10.176 0 10.2 0.084 ;
    END
  END hh[22]
  PIN hh[23]
    DIRECTION OUTPUT ;
    USE SIGNAL ;
    PORT
      LAYER M5 ;
        RECT  10.272 0 10.296 0.084 ;
    END
  END hh[23]
  PIN hh[24]
    DIRECTION OUTPUT ;
    USE SIGNAL ;
    PORT
      LAYER M5 ;
        RECT  10.368 0 10.392 0.084 ;
    END
  END hh[24]
  PIN hh[25]
    DIRECTION OUTPUT ;
    USE SIGNAL ;
    PORT
      LAYER M5 ;
        RECT  10.464 0 10.488 0.084 ;
    END
  END hh[25]
  PIN hh[26]
    DIRECTION OUTPUT ;
    USE SIGNAL ;
    PORT
      LAYER M5 ;
        RECT  10.56 0 10.584 0.084 ;
    END
  END hh[26]
  PIN hh[27]
    DIRECTION OUTPUT ;
    USE SIGNAL ;
    PORT
      LAYER M5 ;
        RECT  10.656 0 10.68 0.084 ;
    END
  END hh[27]
  PIN hh[28]
    DIRECTION OUTPUT ;
    USE SIGNAL ;
    PORT
      LAYER M5 ;
        RECT  10.752 0 10.776 0.084 ;
    END
  END hh[28]
  PIN hh[29]
    DIRECTION OUTPUT ;
    USE SIGNAL ;
    PORT
      LAYER M5 ;
        RECT  10.848 0 10.872 0.084 ;
    END
  END hh[29]
  PIN hh[2]
    DIRECTION OUTPUT ;
    USE SIGNAL ;
    PORT
      LAYER M5 ;
        RECT  8.256 0 8.28 0.084 ;
    END
  END hh[2]
  PIN hh[30]
    DIRECTION OUTPUT ;
    USE SIGNAL ;
    PORT
      LAYER M5 ;
        RECT  10.944 0 10.968 0.084 ;
    END
  END hh[30]
  PIN hh[31]
    DIRECTION OUTPUT ;
    USE SIGNAL ;
    PORT
      LAYER M5 ;
        RECT  11.04 0 11.064 0.084 ;
    END
  END hh[31]
  PIN hh[3]
    DIRECTION OUTPUT ;
    USE SIGNAL ;
    PORT
      LAYER M5 ;
        RECT  8.352 0 8.376 0.084 ;
    END
  END hh[3]
  PIN hh[4]
    DIRECTION OUTPUT ;
    USE SIGNAL ;
    PORT
      LAYER M5 ;
        RECT  8.448 0 8.472 0.084 ;
    END
  END hh[4]
  PIN hh[5]
    DIRECTION OUTPUT ;
    USE SIGNAL ;
    PORT
      LAYER M5 ;
        RECT  8.544 0 8.568 0.084 ;
    END
  END hh[5]
  PIN hh[6]
    DIRECTION OUTPUT ;
    USE SIGNAL ;
    PORT
      LAYER M5 ;
        RECT  8.64 0 8.664 0.084 ;
    END
  END hh[6]
  PIN hh[7]
    DIRECTION OUTPUT ;
    USE SIGNAL ;
    PORT
      LAYER M5 ;
        RECT  8.736 0 8.76 0.084 ;
    END
  END hh[7]
  PIN hh[8]
    DIRECTION OUTPUT ;
    USE SIGNAL ;
    PORT
      LAYER M5 ;
        RECT  8.832 0 8.856 0.084 ;
    END
  END hh[8]
  PIN hh[9]
    DIRECTION OUTPUT ;
    USE SIGNAL ;
    PORT
      LAYER M5 ;
        RECT  8.928 0 8.952 0.084 ;
    END
  END hh[9]
  PIN in_v
    DIRECTION INPUT ;
    USE SIGNAL ;
    PORT
      LAYER M5 ;
        RECT  6.144 64.716 6.168 64.8 ;
    END
    PORT
      LAYER M5 ;
        RECT  6.144 64.691 6.168 64.784 ;
    END
  END in_v
  PIN kk[0]
    DIRECTION OUTPUT ;
    USE SIGNAL ;
    PORT
      LAYER M5 ;
        RECT  12.096 0 12.12 0.084 ;
    END
  END kk[0]
  PIN kk[10]
    DIRECTION OUTPUT ;
    USE SIGNAL ;
    PORT
      LAYER M5 ;
        RECT  13.056 0 13.08 0.084 ;
    END
  END kk[10]
  PIN kk[11]
    DIRECTION OUTPUT ;
    USE SIGNAL ;
    PORT
      LAYER M5 ;
        RECT  13.152 0 13.176 0.084 ;
    END
  END kk[11]
  PIN kk[12]
    DIRECTION OUTPUT ;
    USE SIGNAL ;
    PORT
      LAYER M5 ;
        RECT  13.248 0 13.272 0.084 ;
    END
  END kk[12]
  PIN kk[13]
    DIRECTION OUTPUT ;
    USE SIGNAL ;
    PORT
      LAYER M5 ;
        RECT  13.344 0 13.368 0.084 ;
    END
  END kk[13]
  PIN kk[14]
    DIRECTION OUTPUT ;
    USE SIGNAL ;
    PORT
      LAYER M5 ;
        RECT  13.44 0 13.464 0.084 ;
    END
  END kk[14]
  PIN kk[15]
    DIRECTION OUTPUT ;
    USE SIGNAL ;
    PORT
      LAYER M5 ;
        RECT  13.536 0 13.56 0.084 ;
    END
  END kk[15]
  PIN kk[16]
    DIRECTION OUTPUT ;
    USE SIGNAL ;
    PORT
      LAYER M5 ;
        RECT  13.632 0 13.656 0.084 ;
    END
  END kk[16]
  PIN kk[17]
    DIRECTION OUTPUT ;
    USE SIGNAL ;
    PORT
      LAYER M5 ;
        RECT  13.728 0 13.752 0.084 ;
    END
  END kk[17]
  PIN kk[18]
    DIRECTION OUTPUT ;
    USE SIGNAL ;
    PORT
      LAYER M5 ;
        RECT  13.824 0 13.848 0.084 ;
    END
  END kk[18]
  PIN kk[19]
    DIRECTION OUTPUT ;
    USE SIGNAL ;
    PORT
      LAYER M5 ;
        RECT  13.92 0 13.944 0.084 ;
    END
  END kk[19]
  PIN kk[1]
    DIRECTION OUTPUT ;
    USE SIGNAL ;
    PORT
      LAYER M5 ;
        RECT  12.192 0 12.216 0.084 ;
    END
  END kk[1]
  PIN kk[20]
    DIRECTION OUTPUT ;
    USE SIGNAL ;
    PORT
      LAYER M5 ;
        RECT  14.016 0 14.04 0.084 ;
    END
  END kk[20]
  PIN kk[21]
    DIRECTION OUTPUT ;
    USE SIGNAL ;
    PORT
      LAYER M5 ;
        RECT  14.112 0 14.136 0.084 ;
    END
  END kk[21]
  PIN kk[22]
    DIRECTION OUTPUT ;
    USE SIGNAL ;
    PORT
      LAYER M5 ;
        RECT  14.208 0 14.232 0.084 ;
    END
  END kk[22]
  PIN kk[23]
    DIRECTION OUTPUT ;
    USE SIGNAL ;
    PORT
      LAYER M5 ;
        RECT  14.304 0 14.328 0.084 ;
    END
  END kk[23]
  PIN kk[24]
    DIRECTION OUTPUT ;
    USE SIGNAL ;
    PORT
      LAYER M5 ;
        RECT  14.4 0 14.424 0.084 ;
    END
  END kk[24]
  PIN kk[25]
    DIRECTION OUTPUT ;
    USE SIGNAL ;
    PORT
      LAYER M5 ;
        RECT  14.496 0 14.52 0.084 ;
    END
  END kk[25]
  PIN kk[26]
    DIRECTION OUTPUT ;
    USE SIGNAL ;
    PORT
      LAYER M5 ;
        RECT  14.592 0 14.616 0.084 ;
    END
  END kk[26]
  PIN kk[27]
    DIRECTION OUTPUT ;
    USE SIGNAL ;
    PORT
      LAYER M5 ;
        RECT  14.688 0 14.712 0.084 ;
    END
  END kk[27]
  PIN kk[28]
    DIRECTION OUTPUT ;
    USE SIGNAL ;
    PORT
      LAYER M5 ;
        RECT  14.784 0 14.808 0.084 ;
    END
  END kk[28]
  PIN kk[29]
    DIRECTION OUTPUT ;
    USE SIGNAL ;
    PORT
      LAYER M5 ;
        RECT  14.88 0 14.904 0.084 ;
    END
  END kk[29]
  PIN kk[2]
    DIRECTION OUTPUT ;
    USE SIGNAL ;
    PORT
      LAYER M5 ;
        RECT  12.288 0 12.312 0.084 ;
    END
  END kk[2]
  PIN kk[30]
    DIRECTION OUTPUT ;
    USE SIGNAL ;
    PORT
      LAYER M5 ;
        RECT  14.976 0 15 0.084 ;
    END
  END kk[30]
  PIN kk[31]
    DIRECTION OUTPUT ;
    USE SIGNAL ;
    PORT
      LAYER M5 ;
        RECT  15.072 0 15.096 0.084 ;
    END
  END kk[31]
  PIN kk[3]
    DIRECTION OUTPUT ;
    USE SIGNAL ;
    PORT
      LAYER M5 ;
        RECT  12.384 0 12.408 0.084 ;
    END
  END kk[3]
  PIN kk[4]
    DIRECTION OUTPUT ;
    USE SIGNAL ;
    PORT
      LAYER M5 ;
        RECT  12.48 0 12.504 0.084 ;
    END
  END kk[4]
  PIN kk[5]
    DIRECTION OUTPUT ;
    USE SIGNAL ;
    PORT
      LAYER M5 ;
        RECT  12.576 0 12.6 0.084 ;
    END
  END kk[5]
  PIN kk[6]
    DIRECTION OUTPUT ;
    USE SIGNAL ;
    PORT
      LAYER M5 ;
        RECT  12.672 0 12.696 0.084 ;
    END
  END kk[6]
  PIN kk[7]
    DIRECTION OUTPUT ;
    USE SIGNAL ;
    PORT
      LAYER M5 ;
        RECT  12.768 0 12.792 0.084 ;
    END
  END kk[7]
  PIN kk[8]
    DIRECTION OUTPUT ;
    USE SIGNAL ;
    PORT
      LAYER M5 ;
        RECT  12.864 0 12.888 0.084 ;
    END
  END kk[8]
  PIN kk[9]
    DIRECTION OUTPUT ;
    USE SIGNAL ;
    PORT
      LAYER M5 ;
        RECT  12.96 0 12.984 0.084 ;
    END
  END kk[9]
  PIN mfault[0]
    DIRECTION INPUT ;
    USE SIGNAL ;
    PORT
      LAYER M5 ;
        RECT  14.112 64.716 14.136 64.8 ;
    END
  END mfault[0]
  PIN mfault[1]
    DIRECTION INPUT ;
    USE SIGNAL ;
    PORT
      LAYER M5 ;
        RECT  14.208 64.716 14.232 64.8 ;
    END
  END mfault[1]
  PIN mfault[2]
    DIRECTION INPUT ;
    USE SIGNAL ;
    PORT
      LAYER M5 ;
        RECT  14.304 64.716 14.328 64.8 ;
    END
  END mfault[2]
  PIN mfault[3]
    DIRECTION INPUT ;
    USE SIGNAL ;
    PORT
      LAYER M5 ;
        RECT  14.4 64.716 14.424 64.8 ;
    END
  END mfault[3]
  PIN mfault[4]
    DIRECTION INPUT ;
    USE SIGNAL ;
    PORT
      LAYER M5 ;
        RECT  14.496 64.716 14.52 64.8 ;
    END
  END mfault[4]
  PIN mfault[5]
    DIRECTION INPUT ;
    USE SIGNAL ;
    PORT
      LAYER M5 ;
        RECT  14.592 64.716 14.616 64.8 ;
    END
  END mfault[5]
  PIN mfault[6]
    DIRECTION INPUT ;
    USE SIGNAL ;
    PORT
      LAYER M5 ;
        RECT  14.688 64.716 14.712 64.8 ;
    END
  END mfault[6]
  PIN mfault[7]
    DIRECTION INPUT ;
    USE SIGNAL ;
    PORT
      LAYER M5 ;
        RECT  14.784 64.716 14.808 64.8 ;
    END
  END mfault[7]
  PIN mvalid[0]
    DIRECTION INPUT ;
    USE SIGNAL ;
    PORT
      LAYER M5 ;
        RECT  12.384 64.716 12.408 64.8 ;
    END
  END mvalid[0]
  PIN mvalid[1]
    DIRECTION INPUT ;
    USE SIGNAL ;
    PORT
      LAYER M5 ;
        RECT  12.48 64.716 12.504 64.8 ;
    END
  END mvalid[1]
  PIN mvalid[2]
    DIRECTION INPUT ;
    USE SIGNAL ;
    PORT
      LAYER M5 ;
        RECT  12.576 64.716 12.6 64.8 ;
    END
  END mvalid[2]
  PIN mvalid[3]
    DIRECTION INPUT ;
    USE SIGNAL ;
    PORT
      LAYER M5 ;
        RECT  12.672 64.716 12.696 64.8 ;
    END
  END mvalid[3]
  PIN mvalid[4]
    DIRECTION INPUT ;
    USE SIGNAL ;
    PORT
      LAYER M5 ;
        RECT  12.768 64.716 12.792 64.8 ;
    END
  END mvalid[4]
  PIN mvalid[5]
    DIRECTION INPUT ;
    USE SIGNAL ;
    PORT
      LAYER M5 ;
        RECT  12.864 64.716 12.888 64.8 ;
    END
  END mvalid[5]
  PIN mvalid[6]
    DIRECTION INPUT ;
    USE SIGNAL ;
    PORT
      LAYER M5 ;
        RECT  12.96 64.716 12.984 64.8 ;
    END
  END mvalid[6]
  PIN mvalid[7]
    DIRECTION INPUT ;
    USE SIGNAL ;
    PORT
      LAYER M5 ;
        RECT  13.056 64.716 13.08 64.8 ;
    END
  END mvalid[7]
  PIN nf[0]
    DIRECTION INPUT ;
    USE SIGNAL ;
    PORT
      LAYER M4 ;
        RECT  0 7.104 0.084 7.128 ;
    END
  END nf[0]
  PIN nf[1]
    DIRECTION INPUT ;
    USE SIGNAL ;
    PORT
      LAYER M4 ;
        RECT  0 7.2 0.084 7.224 ;
    END
  END nf[1]
  PIN norm_rstd[0]
    DIRECTION INPUT ;
    USE SIGNAL ;
    PORT
      LAYER M4 ;
        RECT  0 8.256 0.084 8.28 ;
    END
  END norm_rstd[0]
  PIN norm_rstd[10]
    DIRECTION INPUT ;
    USE SIGNAL ;
    PORT
      LAYER M4 ;
        RECT  0 9.216 0.084 9.24 ;
    END
  END norm_rstd[10]
  PIN norm_rstd[11]
    DIRECTION INPUT ;
    USE SIGNAL ;
    PORT
      LAYER M4 ;
        RECT  0 9.312 0.084 9.336 ;
    END
  END norm_rstd[11]
  PIN norm_rstd[12]
    DIRECTION INPUT ;
    USE SIGNAL ;
    PORT
      LAYER M4 ;
        RECT  0 9.408 0.084 9.432 ;
    END
  END norm_rstd[12]
  PIN norm_rstd[13]
    DIRECTION INPUT ;
    USE SIGNAL ;
    PORT
      LAYER M4 ;
        RECT  0 9.504 0.084 9.528 ;
    END
  END norm_rstd[13]
  PIN norm_rstd[14]
    DIRECTION INPUT ;
    USE SIGNAL ;
    PORT
      LAYER M4 ;
        RECT  0 9.6 0.084 9.624 ;
    END
  END norm_rstd[14]
  PIN norm_rstd[15]
    DIRECTION INPUT ;
    USE SIGNAL ;
    PORT
      LAYER M4 ;
        RECT  0 9.696 0.084 9.72 ;
    END
  END norm_rstd[15]
  PIN norm_rstd[16]
    DIRECTION INPUT ;
    USE SIGNAL ;
    PORT
      LAYER M4 ;
        RECT  0 9.792 0.084 9.816 ;
    END
  END norm_rstd[16]
  PIN norm_rstd[17]
    DIRECTION INPUT ;
    USE SIGNAL ;
    PORT
      LAYER M4 ;
        RECT  0 9.888 0.084 9.912 ;
    END
  END norm_rstd[17]
  PIN norm_rstd[18]
    DIRECTION INPUT ;
    USE SIGNAL ;
    PORT
      LAYER M4 ;
        RECT  0 9.984 0.084 10.008 ;
    END
  END norm_rstd[18]
  PIN norm_rstd[19]
    DIRECTION INPUT ;
    USE SIGNAL ;
    PORT
      LAYER M4 ;
        RECT  0 10.08 0.084 10.104 ;
    END
  END norm_rstd[19]
  PIN norm_rstd[1]
    DIRECTION INPUT ;
    USE SIGNAL ;
    PORT
      LAYER M4 ;
        RECT  0 8.352 0.084 8.376 ;
    END
  END norm_rstd[1]
  PIN norm_rstd[20]
    DIRECTION INPUT ;
    USE SIGNAL ;
    PORT
      LAYER M4 ;
        RECT  0 10.176 0.084 10.2 ;
    END
  END norm_rstd[20]
  PIN norm_rstd[21]
    DIRECTION INPUT ;
    USE SIGNAL ;
    PORT
      LAYER M4 ;
        RECT  0 10.272 0.084 10.296 ;
    END
  END norm_rstd[21]
  PIN norm_rstd[22]
    DIRECTION INPUT ;
    USE SIGNAL ;
    PORT
      LAYER M4 ;
        RECT  0 10.368 0.084 10.392 ;
    END
  END norm_rstd[22]
  PIN norm_rstd[23]
    DIRECTION INPUT ;
    USE SIGNAL ;
    PORT
      LAYER M4 ;
        RECT  0 10.464 0.084 10.488 ;
    END
  END norm_rstd[23]
  PIN norm_rstd[24]
    DIRECTION INPUT ;
    USE SIGNAL ;
    PORT
      LAYER M4 ;
        RECT  0 10.56 0.084 10.584 ;
    END
  END norm_rstd[24]
  PIN norm_rstd[25]
    DIRECTION INPUT ;
    USE SIGNAL ;
    PORT
      LAYER M4 ;
        RECT  0 10.656 0.084 10.68 ;
    END
  END norm_rstd[25]
  PIN norm_rstd[26]
    DIRECTION INPUT ;
    USE SIGNAL ;
    PORT
      LAYER M4 ;
        RECT  0 10.752 0.084 10.776 ;
    END
  END norm_rstd[26]
  PIN norm_rstd[27]
    DIRECTION INPUT ;
    USE SIGNAL ;
    PORT
      LAYER M4 ;
        RECT  0 10.848 0.084 10.872 ;
    END
  END norm_rstd[27]
  PIN norm_rstd[28]
    DIRECTION INPUT ;
    USE SIGNAL ;
    PORT
      LAYER M4 ;
        RECT  0 10.944 0.084 10.968 ;
    END
  END norm_rstd[28]
  PIN norm_rstd[29]
    DIRECTION INPUT ;
    USE SIGNAL ;
    PORT
      LAYER M4 ;
        RECT  0 11.04 0.084 11.064 ;
    END
  END norm_rstd[29]
  PIN norm_rstd[2]
    DIRECTION INPUT ;
    USE SIGNAL ;
    PORT
      LAYER M4 ;
        RECT  0 8.448 0.084 8.472 ;
    END
  END norm_rstd[2]
  PIN norm_rstd[30]
    DIRECTION INPUT ;
    USE SIGNAL ;
    PORT
      LAYER M4 ;
        RECT  0 11.136 0.084 11.16 ;
    END
  END norm_rstd[30]
  PIN norm_rstd[31]
    DIRECTION INPUT ;
    USE SIGNAL ;
    PORT
      LAYER M4 ;
        RECT  0 11.232 0.084 11.256 ;
    END
  END norm_rstd[31]
  PIN norm_rstd[32]
    DIRECTION INPUT ;
    USE SIGNAL ;
    PORT
      LAYER M4 ;
        RECT  0 11.328 0.084 11.352 ;
    END
  END norm_rstd[32]
  PIN norm_rstd[33]
    DIRECTION INPUT ;
    USE SIGNAL ;
    PORT
      LAYER M4 ;
        RECT  0 11.424 0.084 11.448 ;
    END
  END norm_rstd[33]
  PIN norm_rstd[34]
    DIRECTION INPUT ;
    USE SIGNAL ;
    PORT
      LAYER M4 ;
        RECT  0 11.52 0.084 11.544 ;
    END
  END norm_rstd[34]
  PIN norm_rstd[35]
    DIRECTION INPUT ;
    USE SIGNAL ;
    PORT
      LAYER M4 ;
        RECT  0 11.616 0.084 11.64 ;
    END
  END norm_rstd[35]
  PIN norm_rstd[36]
    DIRECTION INPUT ;
    USE SIGNAL ;
    PORT
      LAYER M4 ;
        RECT  0 11.712 0.084 11.736 ;
    END
  END norm_rstd[36]
  PIN norm_rstd[37]
    DIRECTION INPUT ;
    USE SIGNAL ;
    PORT
      LAYER M4 ;
        RECT  0 11.808 0.084 11.832 ;
    END
  END norm_rstd[37]
  PIN norm_rstd[38]
    DIRECTION INPUT ;
    USE SIGNAL ;
    PORT
      LAYER M4 ;
        RECT  0 11.904 0.084 11.928 ;
    END
  END norm_rstd[38]
  PIN norm_rstd[39]
    DIRECTION INPUT ;
    USE SIGNAL ;
    PORT
      LAYER M4 ;
        RECT  0 12 0.084 12.024 ;
    END
  END norm_rstd[39]
  PIN norm_rstd[3]
    DIRECTION INPUT ;
    USE SIGNAL ;
    PORT
      LAYER M4 ;
        RECT  0 8.544 0.084 8.568 ;
    END
  END norm_rstd[3]
  PIN norm_rstd[40]
    DIRECTION INPUT ;
    USE SIGNAL ;
    PORT
      LAYER M4 ;
        RECT  0 12.096 0.084 12.12 ;
    END
  END norm_rstd[40]
  PIN norm_rstd[41]
    DIRECTION INPUT ;
    USE SIGNAL ;
    PORT
      LAYER M4 ;
        RECT  0 12.192 0.084 12.216 ;
    END
  END norm_rstd[41]
  PIN norm_rstd[42]
    DIRECTION INPUT ;
    USE SIGNAL ;
    PORT
      LAYER M4 ;
        RECT  0 12.288 0.084 12.312 ;
    END
  END norm_rstd[42]
  PIN norm_rstd[43]
    DIRECTION INPUT ;
    USE SIGNAL ;
    PORT
      LAYER M4 ;
        RECT  0 12.384 0.084 12.408 ;
    END
  END norm_rstd[43]
  PIN norm_rstd[44]
    DIRECTION INPUT ;
    USE SIGNAL ;
    PORT
      LAYER M4 ;
        RECT  0 12.48 0.084 12.504 ;
    END
  END norm_rstd[44]
  PIN norm_rstd[45]
    DIRECTION INPUT ;
    USE SIGNAL ;
    PORT
      LAYER M4 ;
        RECT  0 12.576 0.084 12.6 ;
    END
  END norm_rstd[45]
  PIN norm_rstd[46]
    DIRECTION INPUT ;
    USE SIGNAL ;
    PORT
      LAYER M4 ;
        RECT  0 12.672 0.084 12.696 ;
    END
  END norm_rstd[46]
  PIN norm_rstd[47]
    DIRECTION INPUT ;
    USE SIGNAL ;
    PORT
      LAYER M4 ;
        RECT  0 12.768 0.084 12.792 ;
    END
  END norm_rstd[47]
  PIN norm_rstd[48]
    DIRECTION INPUT ;
    USE SIGNAL ;
    PORT
      LAYER M4 ;
        RECT  0 12.864 0.084 12.888 ;
    END
  END norm_rstd[48]
  PIN norm_rstd[49]
    DIRECTION INPUT ;
    USE SIGNAL ;
    PORT
      LAYER M4 ;
        RECT  0 12.96 0.084 12.984 ;
    END
  END norm_rstd[49]
  PIN norm_rstd[4]
    DIRECTION INPUT ;
    USE SIGNAL ;
    PORT
      LAYER M4 ;
        RECT  0 8.64 0.084 8.664 ;
    END
  END norm_rstd[4]
  PIN norm_rstd[50]
    DIRECTION INPUT ;
    USE SIGNAL ;
    PORT
      LAYER M4 ;
        RECT  0 13.056 0.084 13.08 ;
    END
  END norm_rstd[50]
  PIN norm_rstd[51]
    DIRECTION INPUT ;
    USE SIGNAL ;
    PORT
      LAYER M4 ;
        RECT  0 13.152 0.084 13.176 ;
    END
  END norm_rstd[51]
  PIN norm_rstd[52]
    DIRECTION INPUT ;
    USE SIGNAL ;
    PORT
      LAYER M4 ;
        RECT  0 13.248 0.084 13.272 ;
    END
  END norm_rstd[52]
  PIN norm_rstd[53]
    DIRECTION INPUT ;
    USE SIGNAL ;
    PORT
      LAYER M4 ;
        RECT  0 13.344 0.084 13.368 ;
    END
  END norm_rstd[53]
  PIN norm_rstd[54]
    DIRECTION INPUT ;
    USE SIGNAL ;
    PORT
      LAYER M4 ;
        RECT  0 13.44 0.084 13.464 ;
    END
  END norm_rstd[54]
  PIN norm_rstd[55]
    DIRECTION INPUT ;
    USE SIGNAL ;
    PORT
      LAYER M4 ;
        RECT  0 13.536 0.084 13.56 ;
    END
  END norm_rstd[55]
  PIN norm_rstd[56]
    DIRECTION INPUT ;
    USE SIGNAL ;
    PORT
      LAYER M4 ;
        RECT  0 13.632 0.084 13.656 ;
    END
  END norm_rstd[56]
  PIN norm_rstd[57]
    DIRECTION INPUT ;
    USE SIGNAL ;
    PORT
      LAYER M4 ;
        RECT  0 13.728 0.084 13.752 ;
    END
  END norm_rstd[57]
  PIN norm_rstd[58]
    DIRECTION INPUT ;
    USE SIGNAL ;
    PORT
      LAYER M4 ;
        RECT  0 13.824 0.084 13.848 ;
    END
  END norm_rstd[58]
  PIN norm_rstd[59]
    DIRECTION INPUT ;
    USE SIGNAL ;
    PORT
      LAYER M4 ;
        RECT  0 13.92 0.084 13.944 ;
    END
  END norm_rstd[59]
  PIN norm_rstd[5]
    DIRECTION INPUT ;
    USE SIGNAL ;
    PORT
      LAYER M4 ;
        RECT  0 8.736 0.084 8.76 ;
    END
  END norm_rstd[5]
  PIN norm_rstd[60]
    DIRECTION INPUT ;
    USE SIGNAL ;
    PORT
      LAYER M4 ;
        RECT  0 14.016 0.084 14.04 ;
    END
  END norm_rstd[60]
  PIN norm_rstd[61]
    DIRECTION INPUT ;
    USE SIGNAL ;
    PORT
      LAYER M4 ;
        RECT  0 14.112 0.084 14.136 ;
    END
  END norm_rstd[61]
  PIN norm_rstd[62]
    DIRECTION INPUT ;
    USE SIGNAL ;
    PORT
      LAYER M4 ;
        RECT  0 14.208 0.084 14.232 ;
    END
  END norm_rstd[62]
  PIN norm_rstd[63]
    DIRECTION INPUT ;
    USE SIGNAL ;
    PORT
      LAYER M4 ;
        RECT  0 14.304 0.084 14.328 ;
    END
  END norm_rstd[63]
  PIN norm_rstd[6]
    DIRECTION INPUT ;
    USE SIGNAL ;
    PORT
      LAYER M4 ;
        RECT  0 8.832 0.084 8.856 ;
    END
  END norm_rstd[6]
  PIN norm_rstd[7]
    DIRECTION INPUT ;
    USE SIGNAL ;
    PORT
      LAYER M4 ;
        RECT  0 8.928 0.084 8.952 ;
    END
  END norm_rstd[7]
  PIN norm_rstd[8]
    DIRECTION INPUT ;
    USE SIGNAL ;
    PORT
      LAYER M4 ;
        RECT  0 9.024 0.084 9.048 ;
    END
  END norm_rstd[8]
  PIN norm_rstd[9]
    DIRECTION INPUT ;
    USE SIGNAL ;
    PORT
      LAYER M4 ;
        RECT  0 9.12 0.084 9.144 ;
    END
  END norm_rstd[9]
  PIN nv[0]
    DIRECTION INPUT ;
    USE SIGNAL ;
    PORT
      LAYER M4 ;
        RECT  0 5.952 0.084 5.976 ;
    END
  END nv[0]
  PIN nv[1]
    DIRECTION INPUT ;
    USE SIGNAL ;
    PORT
      LAYER M4 ;
        RECT  0 6.048 0.084 6.072 ;
    END
  END nv[1]
  PIN phase
    DIRECTION INPUT ;
    USE SIGNAL ;
    PORT
      LAYER M5 ;
        RECT  5.088 64.716 5.112 64.8 ;
    END
    PORT
      LAYER M5 ;
        RECT  5.088 64.691 5.112 64.784 ;
    END
  END phase
  PIN rdd[0]
    DIRECTION INPUT ;
    USE SIGNAL ;
    PORT
      LAYER M5 ;
        RECT  38.112 64.716 38.136 64.8 ;
    END
  END rdd[0]
  PIN rdd[10]
    DIRECTION INPUT ;
    USE SIGNAL ;
    PORT
      LAYER M5 ;
        RECT  39.072 64.716 39.096 64.8 ;
    END
  END rdd[10]
  PIN rdd[11]
    DIRECTION INPUT ;
    USE SIGNAL ;
    PORT
      LAYER M5 ;
        RECT  39.168 64.716 39.192 64.8 ;
    END
  END rdd[11]
  PIN rdd[12]
    DIRECTION INPUT ;
    USE SIGNAL ;
    PORT
      LAYER M5 ;
        RECT  39.264 64.716 39.288 64.8 ;
    END
  END rdd[12]
  PIN rdd[13]
    DIRECTION INPUT ;
    USE SIGNAL ;
    PORT
      LAYER M5 ;
        RECT  39.36 64.716 39.384 64.8 ;
    END
  END rdd[13]
  PIN rdd[14]
    DIRECTION INPUT ;
    USE SIGNAL ;
    PORT
      LAYER M5 ;
        RECT  39.456 64.716 39.48 64.8 ;
    END
  END rdd[14]
  PIN rdd[15]
    DIRECTION INPUT ;
    USE SIGNAL ;
    PORT
      LAYER M5 ;
        RECT  39.552 64.716 39.576 64.8 ;
    END
  END rdd[15]
  PIN rdd[16]
    DIRECTION INPUT ;
    USE SIGNAL ;
    PORT
      LAYER M5 ;
        RECT  39.648 64.716 39.672 64.8 ;
    END
  END rdd[16]
  PIN rdd[17]
    DIRECTION INPUT ;
    USE SIGNAL ;
    PORT
      LAYER M5 ;
        RECT  39.744 64.716 39.768 64.8 ;
    END
  END rdd[17]
  PIN rdd[18]
    DIRECTION INPUT ;
    USE SIGNAL ;
    PORT
      LAYER M5 ;
        RECT  39.84 64.716 39.864 64.8 ;
    END
  END rdd[18]
  PIN rdd[19]
    DIRECTION INPUT ;
    USE SIGNAL ;
    PORT
      LAYER M5 ;
        RECT  39.936 64.716 39.96 64.8 ;
    END
  END rdd[19]
  PIN rdd[1]
    DIRECTION INPUT ;
    USE SIGNAL ;
    PORT
      LAYER M5 ;
        RECT  38.208 64.716 38.232 64.8 ;
    END
  END rdd[1]
  PIN rdd[20]
    DIRECTION INPUT ;
    USE SIGNAL ;
    PORT
      LAYER M5 ;
        RECT  40.032 64.716 40.056 64.8 ;
    END
  END rdd[20]
  PIN rdd[21]
    DIRECTION INPUT ;
    USE SIGNAL ;
    PORT
      LAYER M5 ;
        RECT  40.128 64.716 40.152 64.8 ;
    END
  END rdd[21]
  PIN rdd[22]
    DIRECTION INPUT ;
    USE SIGNAL ;
    PORT
      LAYER M5 ;
        RECT  40.224 64.716 40.248 64.8 ;
    END
  END rdd[22]
  PIN rdd[23]
    DIRECTION INPUT ;
    USE SIGNAL ;
    PORT
      LAYER M5 ;
        RECT  40.32 64.716 40.344 64.8 ;
    END
  END rdd[23]
  PIN rdd[24]
    DIRECTION INPUT ;
    USE SIGNAL ;
    PORT
      LAYER M5 ;
        RECT  40.416 64.716 40.44 64.8 ;
    END
  END rdd[24]
  PIN rdd[25]
    DIRECTION INPUT ;
    USE SIGNAL ;
    PORT
      LAYER M5 ;
        RECT  40.512 64.716 40.536 64.8 ;
    END
  END rdd[25]
  PIN rdd[26]
    DIRECTION INPUT ;
    USE SIGNAL ;
    PORT
      LAYER M5 ;
        RECT  40.608 64.716 40.632 64.8 ;
    END
  END rdd[26]
  PIN rdd[27]
    DIRECTION INPUT ;
    USE SIGNAL ;
    PORT
      LAYER M5 ;
        RECT  40.704 64.716 40.728 64.8 ;
    END
  END rdd[27]
  PIN rdd[28]
    DIRECTION INPUT ;
    USE SIGNAL ;
    PORT
      LAYER M5 ;
        RECT  40.8 64.716 40.824 64.8 ;
    END
  END rdd[28]
  PIN rdd[29]
    DIRECTION INPUT ;
    USE SIGNAL ;
    PORT
      LAYER M5 ;
        RECT  40.896 64.716 40.92 64.8 ;
    END
  END rdd[29]
  PIN rdd[2]
    DIRECTION INPUT ;
    USE SIGNAL ;
    PORT
      LAYER M5 ;
        RECT  38.304 64.716 38.328 64.8 ;
    END
  END rdd[2]
  PIN rdd[30]
    DIRECTION INPUT ;
    USE SIGNAL ;
    PORT
      LAYER M5 ;
        RECT  40.992 64.716 41.016 64.8 ;
    END
  END rdd[30]
  PIN rdd[31]
    DIRECTION INPUT ;
    USE SIGNAL ;
    PORT
      LAYER M5 ;
        RECT  41.088 64.716 41.112 64.8 ;
    END
  END rdd[31]
  PIN rdd[3]
    DIRECTION INPUT ;
    USE SIGNAL ;
    PORT
      LAYER M5 ;
        RECT  38.4 64.716 38.424 64.8 ;
    END
  END rdd[3]
  PIN rdd[4]
    DIRECTION INPUT ;
    USE SIGNAL ;
    PORT
      LAYER M5 ;
        RECT  38.496 64.716 38.52 64.8 ;
    END
  END rdd[4]
  PIN rdd[5]
    DIRECTION INPUT ;
    USE SIGNAL ;
    PORT
      LAYER M5 ;
        RECT  38.592 64.716 38.616 64.8 ;
    END
  END rdd[5]
  PIN rdd[6]
    DIRECTION INPUT ;
    USE SIGNAL ;
    PORT
      LAYER M5 ;
        RECT  38.688 64.716 38.712 64.8 ;
    END
  END rdd[6]
  PIN rdd[7]
    DIRECTION INPUT ;
    USE SIGNAL ;
    PORT
      LAYER M5 ;
        RECT  38.784 64.716 38.808 64.8 ;
    END
  END rdd[7]
  PIN rdd[8]
    DIRECTION INPUT ;
    USE SIGNAL ;
    PORT
      LAYER M5 ;
        RECT  38.88 64.716 38.904 64.8 ;
    END
  END rdd[8]
  PIN rdd[9]
    DIRECTION INPUT ;
    USE SIGNAL ;
    PORT
      LAYER M5 ;
        RECT  38.976 64.716 39 64.8 ;
    END
  END rdd[9]
  PIN rf[0]
    DIRECTION INPUT ;
    USE SIGNAL ;
    PORT
      LAYER M5 ;
        RECT  28.8 64.716 28.824 64.8 ;
    END
  END rf[0]
  PIN rf[1]
    DIRECTION INPUT ;
    USE SIGNAL ;
    PORT
      LAYER M5 ;
        RECT  28.896 64.716 28.92 64.8 ;
    END
  END rf[1]
  PIN rf[2]
    DIRECTION INPUT ;
    USE SIGNAL ;
    PORT
      LAYER M5 ;
        RECT  28.992 64.716 29.016 64.8 ;
    END
  END rf[2]
  PIN rhh[0]
    DIRECTION INPUT ;
    USE SIGNAL ;
    PORT
      LAYER M5 ;
        RECT  30.048 64.716 30.072 64.8 ;
    END
  END rhh[0]
  PIN rhh[10]
    DIRECTION INPUT ;
    USE SIGNAL ;
    PORT
      LAYER M5 ;
        RECT  31.008 64.716 31.032 64.8 ;
    END
  END rhh[10]
  PIN rhh[11]
    DIRECTION INPUT ;
    USE SIGNAL ;
    PORT
      LAYER M5 ;
        RECT  31.104 64.716 31.128 64.8 ;
    END
  END rhh[11]
  PIN rhh[12]
    DIRECTION INPUT ;
    USE SIGNAL ;
    PORT
      LAYER M5 ;
        RECT  31.2 64.716 31.224 64.8 ;
    END
  END rhh[12]
  PIN rhh[13]
    DIRECTION INPUT ;
    USE SIGNAL ;
    PORT
      LAYER M5 ;
        RECT  31.296 64.716 31.32 64.8 ;
    END
  END rhh[13]
  PIN rhh[14]
    DIRECTION INPUT ;
    USE SIGNAL ;
    PORT
      LAYER M5 ;
        RECT  31.392 64.716 31.416 64.8 ;
    END
  END rhh[14]
  PIN rhh[15]
    DIRECTION INPUT ;
    USE SIGNAL ;
    PORT
      LAYER M5 ;
        RECT  31.488 64.716 31.512 64.8 ;
    END
  END rhh[15]
  PIN rhh[16]
    DIRECTION INPUT ;
    USE SIGNAL ;
    PORT
      LAYER M5 ;
        RECT  31.584 64.716 31.608 64.8 ;
    END
  END rhh[16]
  PIN rhh[17]
    DIRECTION INPUT ;
    USE SIGNAL ;
    PORT
      LAYER M5 ;
        RECT  31.68 64.716 31.704 64.8 ;
    END
  END rhh[17]
  PIN rhh[18]
    DIRECTION INPUT ;
    USE SIGNAL ;
    PORT
      LAYER M5 ;
        RECT  31.776 64.716 31.8 64.8 ;
    END
  END rhh[18]
  PIN rhh[19]
    DIRECTION INPUT ;
    USE SIGNAL ;
    PORT
      LAYER M5 ;
        RECT  31.872 64.716 31.896 64.8 ;
    END
  END rhh[19]
  PIN rhh[1]
    DIRECTION INPUT ;
    USE SIGNAL ;
    PORT
      LAYER M5 ;
        RECT  30.144 64.716 30.168 64.8 ;
    END
  END rhh[1]
  PIN rhh[20]
    DIRECTION INPUT ;
    USE SIGNAL ;
    PORT
      LAYER M5 ;
        RECT  31.968 64.716 31.992 64.8 ;
    END
  END rhh[20]
  PIN rhh[21]
    DIRECTION INPUT ;
    USE SIGNAL ;
    PORT
      LAYER M5 ;
        RECT  32.064 64.716 32.088 64.8 ;
    END
  END rhh[21]
  PIN rhh[22]
    DIRECTION INPUT ;
    USE SIGNAL ;
    PORT
      LAYER M5 ;
        RECT  32.16 64.716 32.184 64.8 ;
    END
  END rhh[22]
  PIN rhh[23]
    DIRECTION INPUT ;
    USE SIGNAL ;
    PORT
      LAYER M5 ;
        RECT  32.256 64.716 32.28 64.8 ;
    END
  END rhh[23]
  PIN rhh[24]
    DIRECTION INPUT ;
    USE SIGNAL ;
    PORT
      LAYER M5 ;
        RECT  32.352 64.716 32.376 64.8 ;
    END
  END rhh[24]
  PIN rhh[25]
    DIRECTION INPUT ;
    USE SIGNAL ;
    PORT
      LAYER M5 ;
        RECT  32.448 64.716 32.472 64.8 ;
    END
  END rhh[25]
  PIN rhh[26]
    DIRECTION INPUT ;
    USE SIGNAL ;
    PORT
      LAYER M5 ;
        RECT  32.544 64.716 32.568 64.8 ;
    END
  END rhh[26]
  PIN rhh[27]
    DIRECTION INPUT ;
    USE SIGNAL ;
    PORT
      LAYER M5 ;
        RECT  32.64 64.716 32.664 64.8 ;
    END
  END rhh[27]
  PIN rhh[28]
    DIRECTION INPUT ;
    USE SIGNAL ;
    PORT
      LAYER M5 ;
        RECT  32.736 64.716 32.76 64.8 ;
    END
  END rhh[28]
  PIN rhh[29]
    DIRECTION INPUT ;
    USE SIGNAL ;
    PORT
      LAYER M5 ;
        RECT  32.832 64.716 32.856 64.8 ;
    END
  END rhh[29]
  PIN rhh[2]
    DIRECTION INPUT ;
    USE SIGNAL ;
    PORT
      LAYER M5 ;
        RECT  30.24 64.716 30.264 64.8 ;
    END
  END rhh[2]
  PIN rhh[30]
    DIRECTION INPUT ;
    USE SIGNAL ;
    PORT
      LAYER M5 ;
        RECT  32.928 64.716 32.952 64.8 ;
    END
  END rhh[30]
  PIN rhh[31]
    DIRECTION INPUT ;
    USE SIGNAL ;
    PORT
      LAYER M5 ;
        RECT  33.024 64.716 33.048 64.8 ;
    END
  END rhh[31]
  PIN rhh[3]
    DIRECTION INPUT ;
    USE SIGNAL ;
    PORT
      LAYER M5 ;
        RECT  30.336 64.716 30.36 64.8 ;
    END
  END rhh[3]
  PIN rhh[4]
    DIRECTION INPUT ;
    USE SIGNAL ;
    PORT
      LAYER M5 ;
        RECT  30.432 64.716 30.456 64.8 ;
    END
  END rhh[4]
  PIN rhh[5]
    DIRECTION INPUT ;
    USE SIGNAL ;
    PORT
      LAYER M5 ;
        RECT  30.528 64.716 30.552 64.8 ;
    END
  END rhh[5]
  PIN rhh[6]
    DIRECTION INPUT ;
    USE SIGNAL ;
    PORT
      LAYER M5 ;
        RECT  30.624 64.716 30.648 64.8 ;
    END
  END rhh[6]
  PIN rhh[7]
    DIRECTION INPUT ;
    USE SIGNAL ;
    PORT
      LAYER M5 ;
        RECT  30.72 64.716 30.744 64.8 ;
    END
  END rhh[7]
  PIN rhh[8]
    DIRECTION INPUT ;
    USE SIGNAL ;
    PORT
      LAYER M5 ;
        RECT  30.816 64.716 30.84 64.8 ;
    END
  END rhh[8]
  PIN rhh[9]
    DIRECTION INPUT ;
    USE SIGNAL ;
    PORT
      LAYER M5 ;
        RECT  30.912 64.716 30.936 64.8 ;
    END
  END rhh[9]
  PIN rkk[0]
    DIRECTION INPUT ;
    USE SIGNAL ;
    PORT
      LAYER M5 ;
        RECT  34.08 64.716 34.104 64.8 ;
    END
  END rkk[0]
  PIN rkk[10]
    DIRECTION INPUT ;
    USE SIGNAL ;
    PORT
      LAYER M5 ;
        RECT  35.04 64.716 35.064 64.8 ;
    END
  END rkk[10]
  PIN rkk[11]
    DIRECTION INPUT ;
    USE SIGNAL ;
    PORT
      LAYER M5 ;
        RECT  35.136 64.716 35.16 64.8 ;
    END
  END rkk[11]
  PIN rkk[12]
    DIRECTION INPUT ;
    USE SIGNAL ;
    PORT
      LAYER M5 ;
        RECT  35.232 64.716 35.256 64.8 ;
    END
  END rkk[12]
  PIN rkk[13]
    DIRECTION INPUT ;
    USE SIGNAL ;
    PORT
      LAYER M5 ;
        RECT  35.328 64.716 35.352 64.8 ;
    END
  END rkk[13]
  PIN rkk[14]
    DIRECTION INPUT ;
    USE SIGNAL ;
    PORT
      LAYER M5 ;
        RECT  35.424 64.716 35.448 64.8 ;
    END
  END rkk[14]
  PIN rkk[15]
    DIRECTION INPUT ;
    USE SIGNAL ;
    PORT
      LAYER M5 ;
        RECT  35.52 64.716 35.544 64.8 ;
    END
  END rkk[15]
  PIN rkk[16]
    DIRECTION INPUT ;
    USE SIGNAL ;
    PORT
      LAYER M5 ;
        RECT  35.616 64.716 35.64 64.8 ;
    END
  END rkk[16]
  PIN rkk[17]
    DIRECTION INPUT ;
    USE SIGNAL ;
    PORT
      LAYER M5 ;
        RECT  35.712 64.716 35.736 64.8 ;
    END
  END rkk[17]
  PIN rkk[18]
    DIRECTION INPUT ;
    USE SIGNAL ;
    PORT
      LAYER M5 ;
        RECT  35.808 64.716 35.832 64.8 ;
    END
  END rkk[18]
  PIN rkk[19]
    DIRECTION INPUT ;
    USE SIGNAL ;
    PORT
      LAYER M5 ;
        RECT  35.904 64.716 35.928 64.8 ;
    END
  END rkk[19]
  PIN rkk[1]
    DIRECTION INPUT ;
    USE SIGNAL ;
    PORT
      LAYER M5 ;
        RECT  34.176 64.716 34.2 64.8 ;
    END
  END rkk[1]
  PIN rkk[20]
    DIRECTION INPUT ;
    USE SIGNAL ;
    PORT
      LAYER M5 ;
        RECT  36 64.716 36.024 64.8 ;
    END
  END rkk[20]
  PIN rkk[21]
    DIRECTION INPUT ;
    USE SIGNAL ;
    PORT
      LAYER M5 ;
        RECT  36.096 64.716 36.12 64.8 ;
    END
  END rkk[21]
  PIN rkk[22]
    DIRECTION INPUT ;
    USE SIGNAL ;
    PORT
      LAYER M5 ;
        RECT  36.192 64.716 36.216 64.8 ;
    END
  END rkk[22]
  PIN rkk[23]
    DIRECTION INPUT ;
    USE SIGNAL ;
    PORT
      LAYER M5 ;
        RECT  36.288 64.716 36.312 64.8 ;
    END
  END rkk[23]
  PIN rkk[24]
    DIRECTION INPUT ;
    USE SIGNAL ;
    PORT
      LAYER M5 ;
        RECT  36.384 64.716 36.408 64.8 ;
    END
  END rkk[24]
  PIN rkk[25]
    DIRECTION INPUT ;
    USE SIGNAL ;
    PORT
      LAYER M5 ;
        RECT  36.48 64.716 36.504 64.8 ;
    END
  END rkk[25]
  PIN rkk[26]
    DIRECTION INPUT ;
    USE SIGNAL ;
    PORT
      LAYER M5 ;
        RECT  36.576 64.716 36.6 64.8 ;
    END
  END rkk[26]
  PIN rkk[27]
    DIRECTION INPUT ;
    USE SIGNAL ;
    PORT
      LAYER M5 ;
        RECT  36.672 64.716 36.696 64.8 ;
    END
  END rkk[27]
  PIN rkk[28]
    DIRECTION INPUT ;
    USE SIGNAL ;
    PORT
      LAYER M5 ;
        RECT  36.768 64.716 36.792 64.8 ;
    END
  END rkk[28]
  PIN rkk[29]
    DIRECTION INPUT ;
    USE SIGNAL ;
    PORT
      LAYER M5 ;
        RECT  36.864 64.716 36.888 64.8 ;
    END
  END rkk[29]
  PIN rkk[2]
    DIRECTION INPUT ;
    USE SIGNAL ;
    PORT
      LAYER M5 ;
        RECT  34.272 64.716 34.296 64.8 ;
    END
  END rkk[2]
  PIN rkk[30]
    DIRECTION INPUT ;
    USE SIGNAL ;
    PORT
      LAYER M5 ;
        RECT  36.96 64.716 36.984 64.8 ;
    END
  END rkk[30]
  PIN rkk[31]
    DIRECTION INPUT ;
    USE SIGNAL ;
    PORT
      LAYER M5 ;
        RECT  37.056 64.716 37.08 64.8 ;
    END
  END rkk[31]
  PIN rkk[3]
    DIRECTION INPUT ;
    USE SIGNAL ;
    PORT
      LAYER M5 ;
        RECT  34.368 64.716 34.392 64.8 ;
    END
  END rkk[3]
  PIN rkk[4]
    DIRECTION INPUT ;
    USE SIGNAL ;
    PORT
      LAYER M5 ;
        RECT  34.464 64.716 34.488 64.8 ;
    END
  END rkk[4]
  PIN rkk[5]
    DIRECTION INPUT ;
    USE SIGNAL ;
    PORT
      LAYER M5 ;
        RECT  34.56 64.716 34.584 64.8 ;
    END
  END rkk[5]
  PIN rkk[6]
    DIRECTION INPUT ;
    USE SIGNAL ;
    PORT
      LAYER M5 ;
        RECT  34.656 64.716 34.68 64.8 ;
    END
  END rkk[6]
  PIN rkk[7]
    DIRECTION INPUT ;
    USE SIGNAL ;
    PORT
      LAYER M5 ;
        RECT  34.752 64.716 34.776 64.8 ;
    END
  END rkk[7]
  PIN rkk[8]
    DIRECTION INPUT ;
    USE SIGNAL ;
    PORT
      LAYER M5 ;
        RECT  34.848 64.716 34.872 64.8 ;
    END
  END rkk[8]
  PIN rkk[9]
    DIRECTION INPUT ;
    USE SIGNAL ;
    PORT
      LAYER M5 ;
        RECT  34.944 64.716 34.968 64.8 ;
    END
  END rkk[9]
  PIN rv[0]
    DIRECTION INPUT ;
    USE SIGNAL ;
    PORT
      LAYER M5 ;
        RECT  27.552 64.716 27.576 64.8 ;
    END
  END rv[0]
  PIN rv[1]
    DIRECTION INPUT ;
    USE SIGNAL ;
    PORT
      LAYER M5 ;
        RECT  27.648 64.716 27.672 64.8 ;
    END
  END rv[1]
  PIN rv[2]
    DIRECTION INPUT ;
    USE SIGNAL ;
    PORT
      LAYER M5 ;
        RECT  27.744 64.716 27.768 64.8 ;
    END
  END rv[2]
  PIN scale[0]
    DIRECTION INPUT ;
    USE SIGNAL ;
    PORT
      LAYER M5 ;
        RECT  8.352 64.716 8.376 64.8 ;
    END
  END scale[0]
  PIN scale[10]
    DIRECTION INPUT ;
    USE SIGNAL ;
    PORT
      LAYER M5 ;
        RECT  9.312 64.716 9.336 64.8 ;
    END
  END scale[10]
  PIN scale[11]
    DIRECTION INPUT ;
    USE SIGNAL ;
    PORT
      LAYER M5 ;
        RECT  9.408 64.716 9.432 64.8 ;
    END
  END scale[11]
  PIN scale[12]
    DIRECTION INPUT ;
    USE SIGNAL ;
    PORT
      LAYER M5 ;
        RECT  9.504 64.716 9.528 64.8 ;
    END
  END scale[12]
  PIN scale[13]
    DIRECTION INPUT ;
    USE SIGNAL ;
    PORT
      LAYER M5 ;
        RECT  9.6 64.716 9.624 64.8 ;
    END
  END scale[13]
  PIN scale[14]
    DIRECTION INPUT ;
    USE SIGNAL ;
    PORT
      LAYER M5 ;
        RECT  9.696 64.716 9.72 64.8 ;
    END
  END scale[14]
  PIN scale[15]
    DIRECTION INPUT ;
    USE SIGNAL ;
    PORT
      LAYER M5 ;
        RECT  9.792 64.716 9.816 64.8 ;
    END
  END scale[15]
  PIN scale[16]
    DIRECTION INPUT ;
    USE SIGNAL ;
    PORT
      LAYER M5 ;
        RECT  9.888 64.716 9.912 64.8 ;
    END
  END scale[16]
  PIN scale[17]
    DIRECTION INPUT ;
    USE SIGNAL ;
    PORT
      LAYER M5 ;
        RECT  9.984 64.716 10.008 64.8 ;
    END
  END scale[17]
  PIN scale[18]
    DIRECTION INPUT ;
    USE SIGNAL ;
    PORT
      LAYER M5 ;
        RECT  10.08 64.716 10.104 64.8 ;
    END
  END scale[18]
  PIN scale[19]
    DIRECTION INPUT ;
    USE SIGNAL ;
    PORT
      LAYER M5 ;
        RECT  10.176 64.716 10.2 64.8 ;
    END
  END scale[19]
  PIN scale[1]
    DIRECTION INPUT ;
    USE SIGNAL ;
    PORT
      LAYER M5 ;
        RECT  8.448 64.716 8.472 64.8 ;
    END
  END scale[1]
  PIN scale[20]
    DIRECTION INPUT ;
    USE SIGNAL ;
    PORT
      LAYER M5 ;
        RECT  10.272 64.716 10.296 64.8 ;
    END
  END scale[20]
  PIN scale[21]
    DIRECTION INPUT ;
    USE SIGNAL ;
    PORT
      LAYER M5 ;
        RECT  10.368 64.716 10.392 64.8 ;
    END
  END scale[21]
  PIN scale[22]
    DIRECTION INPUT ;
    USE SIGNAL ;
    PORT
      LAYER M5 ;
        RECT  10.464 64.716 10.488 64.8 ;
    END
  END scale[22]
  PIN scale[23]
    DIRECTION INPUT ;
    USE SIGNAL ;
    PORT
      LAYER M5 ;
        RECT  10.56 64.716 10.584 64.8 ;
    END
  END scale[23]
  PIN scale[24]
    DIRECTION INPUT ;
    USE SIGNAL ;
    PORT
      LAYER M5 ;
        RECT  10.656 64.716 10.68 64.8 ;
    END
  END scale[24]
  PIN scale[25]
    DIRECTION INPUT ;
    USE SIGNAL ;
    PORT
      LAYER M5 ;
        RECT  10.752 64.716 10.776 64.8 ;
    END
  END scale[25]
  PIN scale[26]
    DIRECTION INPUT ;
    USE SIGNAL ;
    PORT
      LAYER M5 ;
        RECT  10.848 64.716 10.872 64.8 ;
    END
  END scale[26]
  PIN scale[27]
    DIRECTION INPUT ;
    USE SIGNAL ;
    PORT
      LAYER M5 ;
        RECT  10.944 64.716 10.968 64.8 ;
    END
  END scale[27]
  PIN scale[28]
    DIRECTION INPUT ;
    USE SIGNAL ;
    PORT
      LAYER M5 ;
        RECT  11.04 64.716 11.064 64.8 ;
    END
  END scale[28]
  PIN scale[29]
    DIRECTION INPUT ;
    USE SIGNAL ;
    PORT
      LAYER M5 ;
        RECT  11.136 64.716 11.16 64.8 ;
    END
  END scale[29]
  PIN scale[2]
    DIRECTION INPUT ;
    USE SIGNAL ;
    PORT
      LAYER M5 ;
        RECT  8.544 64.716 8.568 64.8 ;
    END
  END scale[2]
  PIN scale[30]
    DIRECTION INPUT ;
    USE SIGNAL ;
    PORT
      LAYER M5 ;
        RECT  11.232 64.716 11.256 64.8 ;
    END
  END scale[30]
  PIN scale[31]
    DIRECTION INPUT ;
    USE SIGNAL ;
    PORT
      LAYER M5 ;
        RECT  11.328 64.716 11.352 64.8 ;
    END
  END scale[31]
  PIN scale[3]
    DIRECTION INPUT ;
    USE SIGNAL ;
    PORT
      LAYER M5 ;
        RECT  8.64 64.716 8.664 64.8 ;
    END
  END scale[3]
  PIN scale[4]
    DIRECTION INPUT ;
    USE SIGNAL ;
    PORT
      LAYER M5 ;
        RECT  8.736 64.716 8.76 64.8 ;
    END
  END scale[4]
  PIN scale[5]
    DIRECTION INPUT ;
    USE SIGNAL ;
    PORT
      LAYER M5 ;
        RECT  8.832 64.716 8.856 64.8 ;
    END
  END scale[5]
  PIN scale[6]
    DIRECTION INPUT ;
    USE SIGNAL ;
    PORT
      LAYER M5 ;
        RECT  8.928 64.716 8.952 64.8 ;
    END
  END scale[6]
  PIN scale[7]
    DIRECTION INPUT ;
    USE SIGNAL ;
    PORT
      LAYER M5 ;
        RECT  9.024 64.716 9.048 64.8 ;
    END
  END scale[7]
  PIN scale[8]
    DIRECTION INPUT ;
    USE SIGNAL ;
    PORT
      LAYER M5 ;
        RECT  9.12 64.716 9.144 64.8 ;
    END
  END scale[8]
  PIN scale[9]
    DIRECTION INPUT ;
    USE SIGNAL ;
    PORT
      LAYER M5 ;
        RECT  9.216 64.716 9.24 64.8 ;
    END
  END scale[9]
  PIN VDD
    DIRECTION INOUT ;
    USE POWER ;
    PORT
      LAYER M5 ;
        RECT  83.592 2.151 83.712 62.649 ;
        RECT  78.192 2.151 78.312 62.649 ;
        RECT  72.792 2.151 72.912 62.649 ;
        RECT  67.392 2.151 67.512 62.649 ;
        RECT  61.992 2.151 62.112 62.649 ;
        RECT  56.592 2.151 56.712 62.649 ;
        RECT  51.192 2.151 51.312 62.649 ;
        RECT  45.792 2.151 45.912 62.649 ;
        RECT  40.392 2.151 40.512 62.649 ;
        RECT  34.992 2.151 35.112 62.649 ;
        RECT  29.592 2.151 29.712 62.649 ;
        RECT  24.192 2.151 24.312 62.649 ;
        RECT  18.792 2.151 18.912 62.649 ;
        RECT  13.392 2.151 13.512 62.649 ;
        RECT  7.992 2.151 8.112 62.649 ;
        RECT  2.592 2.151 2.712 62.649 ;
    END
  END VDD
  PIN VSS
    DIRECTION INOUT ;
    USE GROUND ;
    PORT
      LAYER M5 ;
        RECT  83.4 2.137 83.52 62.663 ;
        RECT  78 2.137 78.12 62.663 ;
        RECT  72.6 2.137 72.72 62.663 ;
        RECT  67.2 2.137 67.32 62.663 ;
        RECT  61.8 2.137 61.92 62.663 ;
        RECT  56.4 2.137 56.52 62.663 ;
        RECT  51 2.137 51.12 62.663 ;
        RECT  45.6 2.137 45.72 62.663 ;
        RECT  40.2 2.137 40.32 62.663 ;
        RECT  34.8 2.137 34.92 62.663 ;
        RECT  29.4 2.137 29.52 62.663 ;
        RECT  24 2.137 24.12 62.663 ;
        RECT  18.6 2.137 18.72 62.663 ;
        RECT  13.2 2.137 13.32 62.663 ;
        RECT  7.8 2.137 7.92 62.663 ;
        RECT  2.4 2.137 2.52 62.663 ;
    END
  END VSS
  # OT_OBS_CLOSED layer=M5 d_um=1.536 added=391
  OBS
    LAYER RVTN ;
     RECT  2.16 2.16 88.56 2.295 ;
     RECT  2.16 2.565 88.56 2.835 ;
     RECT  2.16 3.105 88.56 3.375 ;
     RECT  2.16 3.645 88.56 3.915 ;
     RECT  2.16 4.185 88.56 4.455 ;
     RECT  2.16 4.725 88.56 4.995 ;
     RECT  2.16 5.265 88.56 5.535 ;
     RECT  2.16 5.805 88.56 6.075 ;
     RECT  2.16 6.345 88.56 6.615 ;
     RECT  2.16 6.885 88.56 7.155 ;
     RECT  2.16 7.425 88.56 7.695 ;
     RECT  2.16 7.965 88.56 8.235 ;
     RECT  2.16 8.505 88.56 8.775 ;
     RECT  2.16 9.045 88.56 9.315 ;
     RECT  2.16 9.585 88.56 9.855 ;
     RECT  2.16 10.125 88.56 10.395 ;
     RECT  2.16 10.665 88.56 10.935 ;
     RECT  2.16 11.205 88.56 11.475 ;
     RECT  2.16 11.745 88.56 12.015 ;
     RECT  2.16 12.285 88.56 12.555 ;
     RECT  2.16 12.825 88.56 13.095 ;
     RECT  2.16 13.365 88.56 13.635 ;
     RECT  2.16 13.905 88.56 14.175 ;
     RECT  2.16 14.445 88.56 14.715 ;
     RECT  2.16 14.985 88.56 15.255 ;
     RECT  2.16 15.525 88.56 15.795 ;
     RECT  2.16 16.065 88.56 16.335 ;
     RECT  2.16 16.605 88.56 16.875 ;
     RECT  2.16 17.145 88.56 17.415 ;
     RECT  2.16 17.685 88.56 17.955 ;
     RECT  2.16 18.225 88.56 18.495 ;
     RECT  2.16 18.765 88.56 19.035 ;
     RECT  2.16 19.305 88.56 19.575 ;
     RECT  2.16 19.845 88.56 20.115 ;
     RECT  2.16 20.385 88.56 20.655 ;
     RECT  2.16 20.925 88.56 21.195 ;
     RECT  2.16 21.465 88.56 21.735 ;
     RECT  2.16 22.005 88.56 22.275 ;
     RECT  2.16 22.545 88.56 22.815 ;
     RECT  2.16 23.085 88.56 23.355 ;
     RECT  2.16 23.625 88.56 23.895 ;
     RECT  2.16 24.165 88.56 24.435 ;
     RECT  2.16 24.705 88.56 24.975 ;
     RECT  2.16 25.245 88.56 25.515 ;
     RECT  2.16 25.785 88.56 26.055 ;
     RECT  2.16 26.325 88.56 26.595 ;
     RECT  2.16 26.865 88.56 27.135 ;
     RECT  2.16 27.405 88.56 27.675 ;
     RECT  2.16 27.945 88.56 28.215 ;
     RECT  2.16 28.485 88.56 28.755 ;
     RECT  2.16 29.025 88.56 29.295 ;
     RECT  2.16 29.565 88.56 29.835 ;
     RECT  2.16 30.105 88.56 30.375 ;
     RECT  2.16 30.645 88.56 30.915 ;
     RECT  2.16 31.185 88.56 31.455 ;
     RECT  2.16 31.725 88.56 31.995 ;
     RECT  2.16 32.265 88.56 32.535 ;
     RECT  2.16 32.805 88.56 33.075 ;
     RECT  2.16 33.345 88.56 33.615 ;
     RECT  2.16 33.885 88.56 34.155 ;
     RECT  2.16 34.425 88.56 34.695 ;
     RECT  2.16 34.965 88.56 35.235 ;
     RECT  2.16 35.505 88.56 35.775 ;
     RECT  2.16 36.045 88.56 36.315 ;
     RECT  2.16 36.585 88.56 36.855 ;
     RECT  2.16 37.125 88.56 37.395 ;
     RECT  2.16 37.665 88.56 37.935 ;
     RECT  2.16 38.205 88.56 38.475 ;
     RECT  2.16 38.745 88.56 39.015 ;
     RECT  2.16 39.285 88.56 39.555 ;
     RECT  2.16 39.825 88.56 40.095 ;
     RECT  2.16 40.365 88.56 40.635 ;
     RECT  2.16 40.905 88.56 41.175 ;
     RECT  2.16 41.445 88.56 41.715 ;
     RECT  2.16 41.985 88.56 42.255 ;
     RECT  2.16 42.525 88.56 42.795 ;
     RECT  2.16 43.065 88.56 43.335 ;
     RECT  2.16 43.605 88.56 43.875 ;
     RECT  2.16 44.145 88.56 44.415 ;
     RECT  2.16 44.685 88.56 44.955 ;
     RECT  2.16 45.225 88.56 45.495 ;
     RECT  2.16 45.765 88.56 46.035 ;
     RECT  2.16 46.305 88.56 46.575 ;
     RECT  2.16 46.845 88.56 47.115 ;
     RECT  2.16 47.385 88.56 47.655 ;
     RECT  2.16 47.925 88.56 48.195 ;
     RECT  2.16 48.465 88.56 48.735 ;
     RECT  2.16 49.005 88.56 49.275 ;
     RECT  2.16 49.545 88.56 49.815 ;
     RECT  2.16 50.085 88.56 50.355 ;
     RECT  2.16 50.625 88.56 50.895 ;
     RECT  2.16 51.165 88.56 51.435 ;
     RECT  2.16 51.705 88.56 51.975 ;
     RECT  2.16 52.245 88.56 52.515 ;
     RECT  2.16 52.785 88.56 53.055 ;
     RECT  2.16 53.325 88.56 53.595 ;
     RECT  2.16 53.865 88.56 54.135 ;
     RECT  2.16 54.405 88.56 54.675 ;
     RECT  2.16 54.945 88.56 55.215 ;
     RECT  2.16 55.485 88.56 55.755 ;
     RECT  2.16 56.025 88.56 56.295 ;
     RECT  2.16 56.565 88.56 56.835 ;
     RECT  2.16 57.105 88.56 57.375 ;
     RECT  2.16 57.645 88.56 57.915 ;
     RECT  2.16 58.185 88.56 58.455 ;
     RECT  2.16 58.725 88.56 58.995 ;
     RECT  2.16 59.265 88.56 59.535 ;
     RECT  2.16 59.805 88.56 60.075 ;
     RECT  2.16 60.345 88.56 60.615 ;
     RECT  2.16 60.885 88.56 61.155 ;
     RECT  2.16 61.425 88.56 61.695 ;
     RECT  2.16 61.965 88.56 62.235 ;
     RECT  2.16 62.505 88.56 62.64 ;
    LAYER RVTP ;
     RECT  2.16 2.295 88.56 2.565 ;
     RECT  2.16 2.835 88.56 3.105 ;
     RECT  2.16 3.375 88.56 3.645 ;
     RECT  2.16 3.915 88.56 4.185 ;
     RECT  2.16 4.455 88.56 4.725 ;
     RECT  2.16 4.995 88.56 5.265 ;
     RECT  2.16 5.535 88.56 5.805 ;
     RECT  2.16 6.075 88.56 6.345 ;
     RECT  2.16 6.615 88.56 6.885 ;
     RECT  2.16 7.155 88.56 7.425 ;
     RECT  2.16 7.695 88.56 7.965 ;
     RECT  2.16 8.235 88.56 8.505 ;
     RECT  2.16 8.775 88.56 9.045 ;
     RECT  2.16 9.315 88.56 9.585 ;
     RECT  2.16 9.855 88.56 10.125 ;
     RECT  2.16 10.395 88.56 10.665 ;
     RECT  2.16 10.935 88.56 11.205 ;
     RECT  2.16 11.475 88.56 11.745 ;
     RECT  2.16 12.015 88.56 12.285 ;
     RECT  2.16 12.555 88.56 12.825 ;
     RECT  2.16 13.095 88.56 13.365 ;
     RECT  2.16 13.635 88.56 13.905 ;
     RECT  2.16 14.175 88.56 14.445 ;
     RECT  2.16 14.715 88.56 14.985 ;
     RECT  2.16 15.255 88.56 15.525 ;
     RECT  2.16 15.795 88.56 16.065 ;
     RECT  2.16 16.335 88.56 16.605 ;
     RECT  2.16 16.875 88.56 17.145 ;
     RECT  2.16 17.415 88.56 17.685 ;
     RECT  2.16 17.955 88.56 18.225 ;
     RECT  2.16 18.495 88.56 18.765 ;
     RECT  2.16 19.035 88.56 19.305 ;
     RECT  2.16 19.575 88.56 19.845 ;
     RECT  2.16 20.115 88.56 20.385 ;
     RECT  2.16 20.655 88.56 20.925 ;
     RECT  2.16 21.195 88.56 21.465 ;
     RECT  2.16 21.735 88.56 22.005 ;
     RECT  2.16 22.275 88.56 22.545 ;
     RECT  2.16 22.815 88.56 23.085 ;
     RECT  2.16 23.355 88.56 23.625 ;
     RECT  2.16 23.895 88.56 24.165 ;
     RECT  2.16 24.435 88.56 24.705 ;
     RECT  2.16 24.975 88.56 25.245 ;
     RECT  2.16 25.515 88.56 25.785 ;
     RECT  2.16 26.055 88.56 26.325 ;
     RECT  2.16 26.595 88.56 26.865 ;
     RECT  2.16 27.135 88.56 27.405 ;
     RECT  2.16 27.675 88.56 27.945 ;
     RECT  2.16 28.215 88.56 28.485 ;
     RECT  2.16 28.755 88.56 29.025 ;
     RECT  2.16 29.295 88.56 29.565 ;
     RECT  2.16 29.835 88.56 30.105 ;
     RECT  2.16 30.375 88.56 30.645 ;
     RECT  2.16 30.915 88.56 31.185 ;
     RECT  2.16 31.455 88.56 31.725 ;
     RECT  2.16 31.995 88.56 32.265 ;
     RECT  2.16 32.535 88.56 32.805 ;
     RECT  2.16 33.075 88.56 33.345 ;
     RECT  2.16 33.615 88.56 33.885 ;
     RECT  2.16 34.155 88.56 34.425 ;
     RECT  2.16 34.695 88.56 34.965 ;
     RECT  2.16 35.235 88.56 35.505 ;
     RECT  2.16 35.775 88.56 36.045 ;
     RECT  2.16 36.315 88.56 36.585 ;
     RECT  2.16 36.855 88.56 37.125 ;
     RECT  2.16 37.395 88.56 37.665 ;
     RECT  2.16 37.935 88.56 38.205 ;
     RECT  2.16 38.475 88.56 38.745 ;
     RECT  2.16 39.015 88.56 39.285 ;
     RECT  2.16 39.555 88.56 39.825 ;
     RECT  2.16 40.095 88.56 40.365 ;
     RECT  2.16 40.635 88.56 40.905 ;
     RECT  2.16 41.175 88.56 41.445 ;
     RECT  2.16 41.715 88.56 41.985 ;
     RECT  2.16 42.255 88.56 42.525 ;
     RECT  2.16 42.795 88.56 43.065 ;
     RECT  2.16 43.335 88.56 43.605 ;
     RECT  2.16 43.875 88.56 44.145 ;
     RECT  2.16 44.415 88.56 44.685 ;
     RECT  2.16 44.955 88.56 45.225 ;
     RECT  2.16 45.495 88.56 45.765 ;
     RECT  2.16 46.035 88.56 46.305 ;
     RECT  2.16 46.575 88.56 46.845 ;
     RECT  2.16 47.115 88.56 47.385 ;
     RECT  2.16 47.655 88.56 47.925 ;
     RECT  2.16 48.195 88.56 48.465 ;
     RECT  2.16 48.735 88.56 49.005 ;
     RECT  2.16 49.275 88.56 49.545 ;
     RECT  2.16 49.815 88.56 50.085 ;
     RECT  2.16 50.355 88.56 50.625 ;
     RECT  2.16 50.895 88.56 51.165 ;
     RECT  2.16 51.435 88.56 51.705 ;
     RECT  2.16 51.975 88.56 52.245 ;
     RECT  2.16 52.515 88.56 52.785 ;
     RECT  2.16 53.055 88.56 53.325 ;
     RECT  2.16 53.595 88.56 53.865 ;
     RECT  2.16 54.135 88.56 54.405 ;
     RECT  2.16 54.675 88.56 54.945 ;
     RECT  2.16 55.215 88.56 55.485 ;
     RECT  2.16 55.755 88.56 56.025 ;
     RECT  2.16 56.295 88.56 56.565 ;
     RECT  2.16 56.835 88.56 57.105 ;
     RECT  2.16 57.375 88.56 57.645 ;
     RECT  2.16 57.915 88.56 58.185 ;
     RECT  2.16 58.455 88.56 58.725 ;
     RECT  2.16 58.995 88.56 59.265 ;
     RECT  2.16 59.535 88.56 59.805 ;
     RECT  2.16 60.075 88.56 60.345 ;
     RECT  2.16 60.615 88.56 60.885 ;
     RECT  2.16 61.155 88.56 61.425 ;
     RECT  2.16 61.695 88.56 61.965 ;
     RECT  2.16 62.235 88.56 62.505 ;
    LAYER M1 ;
     RECT  2.16 2.151 88.56 62.649 ;
    LAYER M2 ;
     RECT  0.031 14.724 0.103 14.742 ;
     RECT  0.031 16.884 0.103 16.902 ;
     RECT  0.103 16.776 0.131 16.902 ;
     RECT  0.103 11.646 0.175 11.664 ;
     RECT  0.103 10.476 0.211 10.494 ;
     RECT  0.131 16.776 0.239 16.794 ;
     RECT  0.211 9.9 0.275 10.494 ;
     RECT  0.175 11.448 0.275 11.664 ;
     RECT  0.103 14.526 0.283 14.742 ;
     RECT  0.275 11.448 0.347 11.619 ;
     RECT  0.283 14.148 0.383 14.742 ;
     RECT  0.103 15.966 0.499 15.984 ;
     RECT  0.499 15.966 1.147 16.362 ;
     RECT  1.147 15.966 1.175 16.902 ;
     RECT  0.103 21.204 1.399 21.222 ;
     RECT  0.535 13.644 1.723 13.662 ;
     RECT  0.383 14.526 1.723 14.742 ;
     RECT  1.399 21.204 1.723 21.258 ;
     RECT  1.723 21.204 1.759 21.294 ;
     RECT  0.535 12.528 2.155 12.546 ;
     RECT  0.175 19.971 2.155 19.989 ;
     RECT  0.103 7.902 2.16 9.072 ;
     RECT  0.275 9.9 2.16 9.918 ;
     RECT  2.155 12.528 2.16 12.618 ;
     RECT  1.723 13.644 2.16 14.742 ;
     RECT  1.175 16.074 2.16 16.902 ;
     RECT  2.155 19.854 2.16 19.989 ;
     RECT  1.759 20.736 2.16 21.294 ;
     RECT  2.16 2.151 3.739 62.649 ;
     RECT  3.739 2.106 3.811 62.649 ;
     RECT  3.811 1.881 6.539 62.649 ;
     RECT  6.539 1.998 7.043 62.649 ;
     RECT  7.043 2.034 7.727 62.649 ;
     RECT  7.727 2.106 8.699 62.649 ;
     RECT  8.699 2.151 8.959 62.649 ;
     RECT  8.959 2.151 9.059 62.694 ;
     RECT  9.059 2.151 10.543 62.649 ;
     RECT  10.543 2.106 12.155 62.649 ;
     RECT  12.155 2.151 14.971 62.649 ;
     RECT  14.971 2.106 16.007 62.649 ;
     RECT  16.007 2.151 18.355 62.649 ;
     RECT  18.247 0.036 18.535 0.054 ;
     RECT  16.735 1.152 18.535 1.17 ;
     RECT  18.535 0.036 19.715 1.17 ;
     RECT  18.355 1.962 20.011 62.649 ;
     RECT  20.011 1.962 21.119 62.694 ;
     RECT  19.715 0.036 21.299 0.549 ;
     RECT  21.299 0.036 21.551 0.054 ;
     RECT  21.119 2.151 24.359 62.694 ;
     RECT  24.359 2.151 29.911 62.649 ;
     RECT  29.911 2.151 30.155 62.694 ;
     RECT  30.155 2.151 32.647 62.649 ;
     RECT  32.647 2.151 32.747 62.694 ;
     RECT  32.747 2.151 34.519 62.649 ;
     RECT  34.519 2.106 41.063 62.649 ;
     RECT  41.063 2.151 42.691 62.649 ;
     RECT  42.691 2.151 44.923 62.694 ;
     RECT  44.923 2.151 46.823 62.766 ;
     RECT  46.823 2.151 50.899 62.649 ;
     RECT  50.899 2.151 51.727 62.694 ;
     RECT  51.727 2.106 54.131 62.694 ;
     RECT  54.131 2.151 68.755 62.649 ;
     RECT  68.755 2.151 83.579 62.694 ;
     RECT  83.579 2.151 88.56 62.649 ;
     RECT  88.56 4.158 88.871 9.648 ;
     RECT  88.871 4.158 88.907 9.306 ;
     RECT  88.907 4.158 89.339 8.838 ;
     RECT  89.339 4.158 89.411 8.532 ;
     RECT  89.411 4.158 89.447 7.416 ;
     RECT  89.447 4.77 89.483 7.254 ;
     RECT  89.411 8.208 89.483 8.532 ;
     RECT  89.483 4.77 90.023 6.444 ;
     RECT  90.023 5.004 90.059 6.444 ;
     RECT  90.059 5.04 90.095 6.444 ;
     RECT  89.483 8.316 90.095 8.532 ;
     RECT  90.095 5.04 90.563 5.868 ;
     RECT  90.563 5.04 90.635 5.058 ;
     RECT  90.563 5.85 90.635 5.868 ;
     RECT  89.483 7.236 90.635 7.254 ;
     RECT  90.095 8.316 90.635 8.334 ;
    LAYER M3 ;
     RECT  4.536 0.091 4.554 0.139 ;
     RECT  14.904 0.091 14.922 0.139 ;
     RECT  15.768 0.091 15.786 0.139 ;
     RECT  16.812 0.091 17.514 0.139 ;
     RECT  18.252 0.031 18.27 0.139 ;
     RECT  20.016 0.091 20.034 0.139 ;
     RECT  20.016 0.139 20.682 0.187 ;
     RECT  20.016 0.187 20.754 0.235 ;
     RECT  21.528 0.031 21.546 0.235 ;
     RECT  6.84 0.091 6.858 0.269 ;
     RECT  16.812 0.139 18.27 0.283 ;
     RECT  16.812 0.283 18.846 0.317 ;
     RECT  4.068 0.139 4.554 0.331 ;
     RECT  18.54 0.317 18.846 0.331 ;
     RECT  20.016 0.235 21.546 0.331 ;
     RECT  18.54 0.331 21.654 0.509 ;
     RECT  18.54 0.509 18.558 0.557 ;
     RECT  3.42 0.331 4.554 0.571 ;
     RECT  5.688 0.091 5.706 0.571 ;
     RECT  16.812 0.317 17.694 1.147 ;
     RECT  16.74 1.147 17.694 1.175 ;
     RECT  8.352 1.099 8.37 1.723 ;
     RECT  18.576 1.675 18.594 1.723 ;
     RECT  19.404 0.509 21.654 1.723 ;
     RECT  6.696 1.723 6.714 1.876 ;
     RECT  3.42 0.571 5.706 1.957 ;
     RECT  6.516 1.876 6.714 1.957 ;
     RECT  18.468 1.723 21.654 1.957 ;
     RECT  3.42 1.957 6.714 1.993 ;
     RECT  3.42 1.993 7.038 2.029 ;
     RECT  8.28 1.723 8.37 2.029 ;
     RECT  3.42 2.029 8.37 2.101 ;
     RECT  10.08 0.091 10.098 2.101 ;
     RECT  14.148 0.139 14.922 2.101 ;
     RECT  15.768 0.139 15.966 2.101 ;
     RECT  13.356 2.011 13.374 2.143 ;
     RECT  34.524 2.101 34.542 2.143 ;
     RECT  51.732 2.101 51.75 2.143 ;
     RECT  2.415 2.143 2.505 2.191 ;
     RECT  3.42 2.101 8.694 2.191 ;
     RECT  10.08 2.101 10.566 2.191 ;
     RECT  12.132 2.101 12.15 2.191 ;
     RECT  13.215 2.143 13.374 2.191 ;
     RECT  14.148 2.101 14.994 2.191 ;
     RECT  15.768 2.101 16.002 2.191 ;
     RECT  16.74 1.175 17.514 2.191 ;
     RECT  18.36 1.957 21.654 2.191 ;
     RECT  34.524 2.143 34.905 2.191 ;
     RECT  41.04 2.101 41.058 2.191 ;
     RECT  51.015 2.143 51.75 2.191 ;
     RECT  67.215 2.143 67.305 2.191 ;
     RECT  45.615 2.143 45.705 2.227 ;
     RECT  78.015 2.143 78.105 2.227 ;
     RECT  2.415 2.191 8.694 2.251 ;
     RECT  10.08 2.191 21.69 2.251 ;
     RECT  49.284 2.227 49.302 2.263 ;
     RECT  51.015 2.191 51.894 2.263 ;
     RECT  33.984 2.191 34.905 2.293 ;
     RECT  44.136 2.191 44.154 2.293 ;
     RECT  28.656 2.191 28.674 2.299 ;
     RECT  29.415 2.143 29.505 2.299 ;
     RECT  30.96 2.293 30.978 2.299 ;
     RECT  39.204 2.191 39.222 2.299 ;
     RECT  40.215 2.143 40.305 2.299 ;
     RECT  42.696 2.191 42.714 2.299 ;
     RECT  44.064 2.293 44.154 2.299 ;
     RECT  45.615 2.227 46.134 2.299 ;
     RECT  55.548 2.191 55.566 2.299 ;
     RECT  56.415 2.143 56.505 2.299 ;
     RECT  58.356 2.263 58.446 2.299 ;
     RECT  59.868 2.227 59.886 2.299 ;
     RECT  61.815 2.143 61.905 2.299 ;
     RECT  62.892 2.293 62.91 2.299 ;
     RECT  66.924 2.191 67.305 2.299 ;
     RECT  70.164 2.263 70.182 2.299 ;
     RECT  28.656 2.299 29.505 2.335 ;
     RECT  33.156 2.299 33.174 2.335 ;
     RECT  33.984 2.293 35.37 2.335 ;
     RECT  38.088 2.299 38.106 2.335 ;
     RECT  39.204 2.299 40.305 2.335 ;
     RECT  42.408 2.299 42.75 2.335 ;
     RECT  48.924 2.263 49.302 2.335 ;
     RECT  54.108 2.101 54.126 2.335 ;
     RECT  55.548 2.299 56.505 2.335 ;
     RECT  57.6 2.299 57.618 2.335 ;
     RECT  58.356 2.299 58.662 2.335 ;
     RECT  59.868 2.299 59.994 2.335 ;
     RECT  66.744 2.299 67.305 2.335 ;
     RECT  72.615 2.143 72.705 2.335 ;
     RECT  73.548 2.299 73.566 2.335 ;
     RECT  77.22 2.299 77.238 2.335 ;
     RECT  77.976 2.227 78.105 2.335 ;
     RECT  78.948 2.191 78.966 2.335 ;
     RECT  65.844 2.335 65.862 2.347 ;
     RECT  66.744 2.335 67.662 2.347 ;
     RECT  48.564 2.335 49.302 2.363 ;
     RECT  24.015 2.143 24.105 2.371 ;
     RECT  26.496 2.335 26.514 2.371 ;
     RECT  30.42 2.299 30.978 2.371 ;
     RECT  33.156 2.335 35.37 2.371 ;
     RECT  45.615 2.299 46.854 2.371 ;
     RECT  48.564 2.363 49.266 2.371 ;
     RECT  53.892 2.335 54.126 2.371 ;
     RECT  59.544 2.335 59.994 2.371 ;
     RECT  74.736 2.299 74.754 2.371 ;
     RECT  80.388 2.263 80.406 2.371 ;
     RECT  28.224 2.335 29.505 2.395 ;
     RECT  30.42 2.371 31.266 2.395 ;
     RECT  32.004 2.299 32.022 2.395 ;
     RECT  23.58 2.371 24.105 2.413 ;
     RECT  38.088 2.335 40.305 2.413 ;
     RECT  41.04 2.191 41.598 2.413 ;
     RECT  83.415 2.143 83.505 2.413 ;
     RECT  23.58 2.413 24.297 2.461 ;
     RECT  28.224 2.395 32.022 2.461 ;
     RECT  36.684 2.299 36.774 2.461 ;
     RECT  38.088 2.413 41.598 2.461 ;
     RECT  42.408 2.335 43.002 2.461 ;
     RECT  44.064 2.299 44.514 2.461 ;
     RECT  45.432 2.371 47.106 2.461 ;
     RECT  48.528 2.371 49.266 2.461 ;
     RECT  50.4 2.263 51.894 2.461 ;
     RECT  59.472 2.371 59.994 2.461 ;
     RECT  72.615 2.335 73.566 2.461 ;
     RECT  76.608 2.335 77.238 2.461 ;
     RECT  77.976 2.335 78.966 2.461 ;
     RECT  80.208 2.371 80.406 2.461 ;
     RECT  25.74 2.371 25.758 2.491 ;
     RECT  26.496 2.371 26.55 2.491 ;
     RECT  36.684 2.461 37.062 2.491 ;
     RECT  38.088 2.461 43.002 2.491 ;
     RECT  44.064 2.461 44.622 2.491 ;
     RECT  48.456 2.461 49.266 2.491 ;
     RECT  50.112 2.461 51.894 2.491 ;
     RECT  53.892 2.371 54.198 2.491 ;
     RECT  33.156 2.371 35.838 2.497 ;
     RECT  36.684 2.491 44.622 2.497 ;
     RECT  45.432 2.461 47.466 2.497 ;
     RECT  48.348 2.491 49.266 2.497 ;
     RECT  53.892 2.491 54.414 2.497 ;
     RECT  55.548 2.335 58.698 2.497 ;
     RECT  59.472 2.461 60.318 2.497 ;
     RECT  69.732 2.299 70.758 2.497 ;
     RECT  76.536 2.461 78.966 2.497 ;
     RECT  45.432 2.497 49.266 2.533 ;
     RECT  50.076 2.491 51.894 2.533 ;
     RECT  52.632 2.335 52.758 2.533 ;
     RECT  53.604 2.497 54.414 2.533 ;
     RECT  55.476 2.497 60.534 2.533 ;
     RECT  65.052 2.461 65.07 2.533 ;
     RECT  65.844 2.347 67.662 2.533 ;
     RECT  74.736 2.371 75.258 2.533 ;
     RECT  76.536 2.497 79.254 2.533 ;
     RECT  55.368 2.533 60.534 2.539 ;
     RECT  25.56 2.491 25.758 2.569 ;
     RECT  28.224 2.461 32.13 2.569 ;
     RECT  33.156 2.497 44.622 2.569 ;
     RECT  50.076 2.533 52.758 2.569 ;
     RECT  53.532 2.533 54.414 2.569 ;
     RECT  61.815 2.299 63.846 2.569 ;
     RECT  65.052 2.533 67.95 2.569 ;
     RECT  69.732 2.497 70.866 2.569 ;
     RECT  71.784 2.461 73.566 2.569 ;
     RECT  74.736 2.533 75.51 2.569 ;
     RECT  76.356 2.533 79.254 2.569 ;
     RECT  80.136 2.461 80.406 2.569 ;
     RECT  26.496 2.491 26.658 2.587 ;
     RECT  28.224 2.569 44.622 2.587 ;
     RECT  45.36 2.533 49.266 2.587 ;
     RECT  55.296 2.539 60.534 2.587 ;
     RECT  23.04 2.461 24.297 2.605 ;
     RECT  55.224 2.587 60.534 2.605 ;
     RECT  2.415 2.251 21.69 2.641 ;
     RECT  26.496 2.587 26.838 2.641 ;
     RECT  28.224 2.587 49.266 2.641 ;
     RECT  61.815 2.569 68.022 2.641 ;
     RECT  69.732 2.569 80.406 2.641 ;
     RECT  25.02 2.569 25.758 2.669 ;
     RECT  22.86 2.605 24.297 2.731 ;
     RECT  25.02 2.669 25.506 2.731 ;
     RECT  50.076 2.569 54.414 2.731 ;
     RECT  55.224 2.605 61.002 2.731 ;
     RECT  61.815 2.641 68.454 2.767 ;
     RECT  26.496 2.641 49.266 2.795 ;
     RECT  2.415 2.641 21.726 2.803 ;
     RECT  69.732 2.641 80.586 2.911 ;
     RECT  50.076 2.731 61.002 3.001 ;
     RECT  61.812 2.767 68.454 3.001 ;
     RECT  50.076 3.001 68.454 3.019 ;
     RECT  50.076 3.019 68.49 3.1 ;
     RECT  22.86 2.731 25.506 3.109 ;
     RECT  50.04 3.1 68.49 3.109 ;
     RECT  69.624 2.911 80.586 3.109 ;
     RECT  28.224 2.795 49.266 3.163 ;
     RECT  50.04 3.109 80.586 3.163 ;
     RECT  2.415 2.803 21.798 3.181 ;
     RECT  28.224 3.163 80.586 3.209 ;
     RECT  26.496 2.795 27.45 3.271 ;
     RECT  65.196 3.209 80.586 3.271 ;
     RECT  81.72 2.731 81.738 3.271 ;
     RECT  65.196 3.271 80.73 3.299 ;
     RECT  81.684 3.271 81.882 3.343 ;
     RECT  28.224 3.209 64.422 3.371 ;
     RECT  22.824 3.109 25.506 3.379 ;
     RECT  22.752 3.379 25.506 3.415 ;
     RECT  22.752 3.415 25.542 3.451 ;
     RECT  81.648 3.343 81.882 3.451 ;
     RECT  81.648 3.451 82.494 3.577 ;
     RECT  2.415 3.181 21.906 3.613 ;
     RECT  22.716 3.451 25.542 3.613 ;
     RECT  26.28 3.271 27.45 3.613 ;
     RECT  28.224 3.371 47.718 3.613 ;
     RECT  81.648 3.577 82.566 3.649 ;
     RECT  81.648 3.649 82.602 3.721 ;
     RECT  83.415 2.413 83.697 3.721 ;
     RECT  48.456 3.371 64.422 3.955 ;
     RECT  65.232 3.299 80.73 3.955 ;
     RECT  81.648 3.721 83.697 3.955 ;
     RECT  2.415 3.613 25.542 3.979 ;
     RECT  26.28 3.613 47.718 3.979 ;
     RECT  2.415 3.979 47.718 3.983 ;
     RECT  87.264 3.547 87.282 4.117 ;
     RECT  65.232 3.955 83.79 4.145 ;
     RECT  25.236 3.983 47.718 4.153 ;
     RECT  48.456 3.955 64.494 4.153 ;
     RECT  86.076 4.081 86.094 4.153 ;
     RECT  86.868 4.117 87.282 4.153 ;
     RECT  89.424 4.027 89.442 4.181 ;
     RECT  25.236 4.153 64.494 4.189 ;
     RECT  65.232 4.145 68.346 4.189 ;
     RECT  84.852 4.219 84.87 4.261 ;
     RECT  86.076 4.153 87.282 4.261 ;
     RECT  86.076 4.261 87.606 4.351 ;
     RECT  69.192 4.145 83.79 4.379 ;
     RECT  69.228 4.379 83.79 4.495 ;
     RECT  84.6 4.261 84.87 4.495 ;
     RECT  85.968 4.351 87.606 4.801 ;
     RECT  69.228 4.495 84.87 4.987 ;
     RECT  85.896 4.801 87.606 4.987 ;
     RECT  90 4.765 90.018 4.999 ;
     RECT  90 4.999 90.054 5.035 ;
     RECT  69.228 4.987 87.606 5.071 ;
     RECT  90 5.035 90.63 5.117 ;
     RECT  2.415 3.983 24.498 5.161 ;
     RECT  25.236 4.189 68.346 5.161 ;
     RECT  69.228 5.071 87.678 5.161 ;
     RECT  2.415 5.161 87.678 5.261 ;
     RECT  88.92 4.963 88.938 5.269 ;
     RECT  88.884 5.269 88.938 5.305 ;
     RECT  70.344 5.261 87.678 5.341 ;
     RECT  88.884 5.305 88.974 5.341 ;
     RECT  70.344 5.341 88.974 5.371 ;
     RECT  90 5.117 90.558 5.371 ;
     RECT  70.344 5.371 90.558 5.693 ;
     RECT  89.244 5.693 90.558 5.845 ;
     RECT  89.244 5.845 90.63 5.885 ;
     RECT  2.415 5.261 69.498 5.947 ;
     RECT  2.304 5.947 69.498 6.035 ;
     RECT  2.34 6.035 69.498 6.043 ;
     RECT  70.344 5.693 88.434 6.043 ;
     RECT  2.34 6.043 88.434 6.107 ;
     RECT  2.34 6.107 64.638 6.305 ;
     RECT  65.628 6.107 88.434 6.413 ;
     RECT  76.176 6.413 88.434 6.427 ;
     RECT  89.244 5.885 90.09 6.427 ;
     RECT  76.176 6.427 90.09 6.557 ;
     RECT  2.376 6.305 64.638 6.683 ;
     RECT  2.376 6.683 62.298 6.719 ;
     RECT  76.176 6.557 89.478 6.749 ;
     RECT  52.776 6.719 62.298 6.809 ;
     RECT  76.176 6.749 88.434 6.809 ;
     RECT  65.628 6.413 75.438 6.893 ;
     RECT  63.036 6.683 64.638 6.907 ;
     RECT  2.376 6.719 51.894 6.989 ;
     RECT  2.376 6.989 48.978 7.087 ;
     RECT  52.956 6.809 62.298 7.151 ;
     RECT  76.176 6.809 88.146 7.187 ;
     RECT  2.34 7.087 48.978 7.195 ;
     RECT  65.628 6.893 75.402 7.223 ;
     RECT  63.036 6.907 64.782 7.321 ;
     RECT  65.628 7.223 75.258 7.321 ;
     RECT  63.036 7.321 75.258 7.421 ;
     RECT  64.656 7.421 75.258 7.427 ;
     RECT  89.28 6.749 89.478 7.483 ;
     RECT  90.612 7.003 90.63 7.483 ;
     RECT  89.28 7.483 90.63 7.579 ;
     RECT  49.752 6.989 51.894 7.591 ;
     RECT  53.64 7.151 62.298 7.663 ;
     RECT  63.036 7.421 63.81 7.663 ;
     RECT  2.304 7.195 48.978 7.763 ;
     RECT  45.504 7.763 48.978 7.897 ;
     RECT  49.752 7.591 52.542 7.897 ;
     RECT  53.64 7.663 63.81 7.897 ;
     RECT  64.656 7.427 69.606 7.997 ;
     RECT  76.212 7.187 88.146 8.107 ;
     RECT  88.884 7.579 90.63 8.107 ;
     RECT  76.212 8.107 90.63 8.159 ;
     RECT  64.836 7.997 69.606 8.167 ;
     RECT  70.344 7.427 75.258 8.167 ;
     RECT  76.212 8.159 88.146 8.195 ;
     RECT  0.108 7.897 0.126 8.203 ;
     RECT  45.504 7.897 52.542 8.203 ;
     RECT  53.532 7.897 63.81 8.303 ;
     RECT  88.884 8.159 90.63 8.303 ;
     RECT  64.836 8.167 75.258 8.311 ;
     RECT  76.212 8.195 81.846 8.311 ;
     RECT  53.532 8.303 57.978 8.339 ;
     RECT  64.836 8.311 81.846 8.339 ;
     RECT  89.316 8.303 90.63 8.339 ;
     RECT  53.532 8.339 57.906 8.401 ;
     RECT  82.62 8.195 88.146 8.429 ;
     RECT  53.46 8.401 57.906 8.465 ;
     RECT  58.86 8.303 63.81 8.465 ;
     RECT  73.836 8.339 81.846 8.477 ;
     RECT  2.304 7.763 44.766 8.491 ;
     RECT  45.504 8.203 52.65 8.491 ;
     RECT  89.316 8.339 90.09 8.501 ;
     RECT  0.108 8.203 0.162 8.509 ;
     RECT  64.836 8.339 73.026 8.537 ;
     RECT  90.072 8.501 90.09 8.537 ;
     RECT  2.304 8.491 52.65 8.635 ;
     RECT  82.62 8.429 87.822 8.699 ;
     RECT  72.216 8.537 73.026 8.771 ;
     RECT  89.316 8.501 89.334 8.843 ;
     RECT  61.344 8.465 63.81 8.851 ;
     RECT  82.62 8.699 87.354 8.969 ;
     RECT  61.344 8.851 63.954 8.977 ;
     RECT  0.108 8.509 0.522 9.013 ;
     RECT  57.816 8.465 57.906 9.085 ;
     RECT  73.872 8.477 81.846 9.121 ;
     RECT  82.62 8.969 87.246 9.121 ;
     RECT  58.86 8.465 60.57 9.211 ;
     RECT  61.344 8.977 64.35 9.211 ;
     RECT  72.396 8.771 73.026 9.211 ;
     RECT  73.872 9.121 87.246 9.211 ;
     RECT  88.884 9.115 88.902 9.211 ;
     RECT  72.396 9.211 87.246 9.239 ;
     RECT  2.268 8.635 52.65 9.298 ;
     RECT  65.196 8.537 71.154 9.307 ;
     RECT  53.46 8.465 56.934 9.311 ;
     RECT  88.848 9.211 88.902 9.311 ;
     RECT  57.816 9.085 57.978 9.319 ;
     RECT  58.86 9.211 64.35 9.319 ;
     RECT  65.196 9.307 71.19 9.319 ;
     RECT  57.816 9.319 64.35 9.346 ;
     RECT  72.396 9.239 81.846 9.383 ;
     RECT  53.532 9.311 56.934 9.391 ;
     RECT  57.816 9.346 64.386 9.391 ;
     RECT  65.196 9.319 71.442 9.391 ;
     RECT  53.532 9.391 71.442 9.419 ;
     RECT  0.108 9.013 0.558 9.437 ;
     RECT  77.544 9.383 81.846 9.509 ;
     RECT  53.64 9.419 71.442 9.553 ;
     RECT  82.656 9.239 86.094 9.653 ;
     RECT  88.848 9.311 88.866 9.653 ;
     RECT  72.396 9.383 76.698 9.661 ;
     RECT  2.268 9.298 52.614 9.779 ;
     RECT  2.268 9.779 52.398 9.887 ;
     RECT  53.64 9.553 71.514 10.021 ;
     RECT  72.36 9.661 76.698 10.021 ;
     RECT  77.58 9.509 81.846 10.057 ;
     RECT  77.58 10.057 81.918 10.165 ;
     RECT  82.656 9.653 83.697 10.165 ;
     RECT  0.108 9.437 0.234 10.267 ;
     RECT  0.108 10.267 0.342 10.397 ;
     RECT  84.816 9.653 86.094 10.399 ;
     RECT  77.58 10.165 83.697 10.435 ;
     RECT  53.64 10.021 76.698 10.471 ;
     RECT  77.58 10.435 83.754 10.471 ;
     RECT  2.304 9.887 52.398 10.561 ;
     RECT  53.64 10.471 83.754 10.561 ;
     RECT  84.744 10.399 86.094 10.561 ;
     RECT  2.304 10.561 83.79 10.625 ;
     RECT  54.504 10.625 83.79 10.633 ;
     RECT  84.564 10.561 86.094 10.633 ;
     RECT  0.108 10.397 0.27 10.685 ;
     RECT  2.304 10.625 53.514 10.697 ;
     RECT  54.504 10.633 86.094 10.831 ;
     RECT  87.228 9.239 87.246 10.831 ;
     RECT  2.304 10.697 51.426 10.843 ;
     RECT  54.504 10.831 87.246 10.903 ;
     RECT  2.268 10.843 51.426 10.931 ;
     RECT  2.304 10.931 51.426 11.201 ;
     RECT  54.504 10.903 87.354 11.209 ;
     RECT  52.272 10.697 53.514 11.371 ;
     RECT  54.504 11.209 87.462 11.371 ;
     RECT  0.216 10.685 0.234 11.419 ;
     RECT  0.18 11.419 0.234 11.443 ;
     RECT  52.272 11.371 87.462 11.479 ;
     RECT  0.18 11.443 0.342 11.611 ;
     RECT  0.108 11.611 0.342 11.669 ;
     RECT  52.272 11.479 87.57 11.669 ;
     RECT  0.252 11.669 0.342 11.789 ;
     RECT  2.304 11.201 44.37 11.803 ;
     RECT  52.524 11.669 87.57 11.939 ;
     RECT  54.108 11.939 87.57 11.947 ;
     RECT  0.324 11.789 0.342 11.981 ;
     RECT  1.728 11.803 44.37 12.019 ;
     RECT  45.108 11.201 51.426 12.019 ;
     RECT  54.108 11.947 87.678 12.317 ;
     RECT  1.728 12.019 51.426 12.325 ;
     RECT  81.576 12.317 87.678 12.595 ;
     RECT  0.54 12.523 0.558 12.701 ;
     RECT  81.576 12.595 87.894 12.749 ;
     RECT  54.108 12.317 80.73 12.821 ;
     RECT  52.524 11.939 52.866 12.865 ;
     RECT  81.576 12.749 87.822 12.893 ;
     RECT  52.38 12.865 52.866 12.901 ;
     RECT  54.108 12.821 66.114 12.901 ;
     RECT  1.728 12.325 51.57 13.063 ;
     RECT  52.38 12.901 53.118 13.063 ;
     RECT  66.888 12.821 80.73 13.099 ;
     RECT  81.576 12.893 87.75 13.099 ;
     RECT  1.728 13.063 53.118 13.261 ;
     RECT  53.892 12.901 66.114 13.261 ;
     RECT  0.144 12.811 0.234 13.639 ;
     RECT  1.728 13.261 66.114 13.703 ;
     RECT  52.56 13.703 66.114 13.711 ;
     RECT  66.888 13.099 87.75 13.711 ;
     RECT  0.144 13.639 0.558 13.757 ;
     RECT  52.56 13.711 87.75 13.829 ;
     RECT  1.728 13.703 51.462 13.937 ;
     RECT  53.604 13.829 87.75 13.981 ;
     RECT  53.604 13.981 87.894 14.135 ;
     RECT  0.144 13.757 0.378 14.237 ;
     RECT  2.268 13.937 51.462 14.243 ;
     RECT  2.268 14.243 49.734 14.279 ;
     RECT  50.472 14.243 51.462 14.611 ;
     RECT  52.56 13.829 52.866 14.611 ;
     RECT  50.472 14.611 52.866 14.717 ;
     RECT  0.108 14.521 0.126 14.719 ;
     RECT  1.152 14.299 1.17 14.765 ;
     RECT  52.668 14.717 52.866 14.881 ;
     RECT  53.604 14.135 87.822 14.881 ;
     RECT  2.304 14.279 49.734 14.909 ;
     RECT  52.668 14.881 87.822 14.945 ;
     RECT  42.624 14.909 49.734 15.089 ;
     RECT  2.304 14.909 41.85 15.215 ;
     RECT  42.696 15.089 49.734 15.421 ;
     RECT  50.472 14.717 51.858 15.421 ;
     RECT  52.668 14.945 87.786 15.521 ;
     RECT  52.668 15.521 87.75 15.593 ;
     RECT  52.92 15.593 87.75 15.719 ;
     RECT  2.34 15.215 41.85 15.871 ;
     RECT  53.28 15.719 87.75 15.899 ;
     RECT  2.34 15.871 41.886 15.997 ;
     RECT  42.696 15.421 51.858 15.997 ;
     RECT  53.316 15.899 87.75 16.025 ;
     RECT  2.34 15.997 51.858 16.075 ;
     RECT  1.152 15.961 1.17 16.097 ;
     RECT  0.036 14.719 0.126 16.141 ;
     RECT  53.424 16.025 87.606 16.331 ;
     RECT  53.424 16.331 87.57 16.403 ;
     RECT  2.232 16.075 51.858 16.501 ;
     RECT  2.232 16.501 52.218 16.645 ;
     RECT  2.232 16.645 52.542 16.835 ;
     RECT  53.424 16.403 60.102 16.835 ;
     RECT  49.14 16.835 52.542 16.843 ;
     RECT  53.424 16.835 59.526 16.843 ;
     RECT  49.14 16.843 59.526 16.871 ;
     RECT  0.036 16.141 0.558 16.879 ;
     RECT  0.036 16.879 1.17 16.907 ;
     RECT  49.14 16.871 58.302 16.943 ;
     RECT  52.776 16.943 58.302 17.069 ;
     RECT  0.108 16.907 1.17 17.117 ;
     RECT  52.776 17.069 58.23 17.117 ;
     RECT  60.876 16.403 87.57 17.221 ;
     RECT  49.14 16.943 51.642 17.339 ;
     RECT  0.108 17.117 0.558 17.405 ;
     RECT  0.108 17.405 0.522 17.501 ;
     RECT  59.04 16.871 59.526 17.581 ;
     RECT  60.552 17.221 87.57 17.581 ;
     RECT  59.04 17.581 87.57 17.609 ;
     RECT  2.232 16.835 48.33 17.653 ;
     RECT  49.14 17.339 51.297 17.653 ;
     RECT  84.852 17.609 87.57 17.879 ;
     RECT  53.316 17.117 58.23 18.031 ;
     RECT  59.04 17.609 84.078 18.031 ;
     RECT  52.848 18.031 84.078 18.149 ;
     RECT  2.232 17.653 51.297 18.157 ;
     RECT  52.092 17.995 52.11 18.157 ;
     RECT  2.232 18.157 52.11 18.269 ;
     RECT  2.232 18.269 51.678 18.419 ;
     RECT  52.848 18.149 62.298 18.455 ;
     RECT  52.848 18.455 62.226 18.499 ;
     RECT  2.232 18.419 51.318 18.523 ;
     RECT  63.036 18.149 84.078 18.571 ;
     RECT  63.036 18.571 84.114 18.661 ;
     RECT  84.924 17.879 87.57 18.661 ;
     RECT  2.16 18.523 51.318 18.725 ;
     RECT  63.036 18.661 87.606 18.797 ;
     RECT  1.404 18.619 1.422 18.811 ;
     RECT  2.16 18.725 48.51 18.811 ;
     RECT  0.108 17.501 0.198 18.907 ;
     RECT  52.668 18.499 62.226 18.959 ;
     RECT  52.74 18.959 62.226 18.995 ;
     RECT  0.108 18.907 0.342 19.099 ;
     RECT  63.036 18.797 86.994 19.103 ;
     RECT  1.404 18.811 48.51 19.243 ;
     RECT  0.108 19.099 0.378 19.325 ;
     RECT  1.152 19.243 48.51 19.373 ;
     RECT  49.284 18.725 51.318 19.483 ;
     RECT  49.284 19.483 51.894 19.571 ;
     RECT  76.608 19.103 86.994 19.643 ;
     RECT  49.5 19.571 51.894 19.921 ;
     RECT  52.812 18.995 62.226 19.921 ;
     RECT  63.036 19.103 75.69 19.921 ;
     RECT  76.608 19.643 86.706 19.921 ;
     RECT  0.108 19.325 0.198 19.994 ;
     RECT  49.5 19.921 62.226 20.039 ;
     RECT  55.728 20.039 62.226 20.047 ;
     RECT  63.036 19.921 86.706 20.047 ;
     RECT  1.404 19.373 48.51 20.317 ;
     RECT  49.5 20.039 54.954 20.317 ;
     RECT  55.728 20.047 86.706 20.461 ;
     RECT  55.728 20.461 87.282 20.579 ;
     RECT  58.212 20.579 87.282 20.731 ;
     RECT  58.212 20.731 87.354 21.119 ;
     RECT  76.176 21.119 87.354 21.127 ;
     RECT  1.404 20.317 54.954 21.199 ;
     RECT  55.728 20.579 57.438 21.199 ;
     RECT  0.108 19.994 0.126 21.227 ;
     RECT  1.404 21.199 57.438 21.263 ;
     RECT  76.176 21.127 88.002 21.271 ;
     RECT  1.728 21.263 57.438 21.299 ;
     RECT  2.415 21.299 57.438 21.389 ;
     RECT  76.176 21.271 88.434 21.389 ;
     RECT  58.212 21.119 75.438 21.469 ;
     RECT  57.924 21.469 75.438 21.581 ;
     RECT  57.924 21.581 75.33 22.073 ;
     RECT  76.176 21.389 88.362 22.081 ;
     RECT  2.415 21.389 56.97 22.205 ;
     RECT  3.42 22.205 56.97 22.235 ;
     RECT  76.104 22.081 88.362 22.307 ;
     RECT  49.608 22.235 56.97 22.351 ;
     RECT  57.924 22.073 68.526 22.351 ;
     RECT  69.372 22.073 75.33 22.351 ;
     RECT  76.104 22.307 79.614 22.351 ;
     RECT  49.608 22.351 68.526 22.469 ;
     RECT  69.372 22.351 79.614 22.469 ;
     RECT  49.608 22.469 64.206 22.505 ;
     RECT  80.352 22.307 88.362 22.621 ;
     RECT  71.676 22.469 79.542 22.775 ;
     RECT  64.98 22.469 68.526 22.843 ;
     RECT  69.372 22.469 70.902 22.843 ;
     RECT  3.42 22.235 43.65 22.847 ;
     RECT  52.344 22.505 64.206 23.009 ;
     RECT  44.46 22.235 48.69 23.017 ;
     RECT  52.344 23.009 62.694 23.069 ;
     RECT  73.8 22.775 79.542 23.081 ;
     RECT  44.424 23.017 48.69 23.089 ;
     RECT  49.608 22.505 51.606 23.089 ;
     RECT  3.672 22.847 43.65 23.161 ;
     RECT  63.468 23.009 64.206 23.189 ;
     RECT  75.276 23.081 79.542 23.279 ;
     RECT  80.352 22.621 88.434 23.279 ;
     RECT  63.576 23.189 64.206 23.287 ;
     RECT  64.98 22.843 70.902 23.287 ;
     RECT  75.564 23.279 79.542 23.323 ;
     RECT  80.352 23.279 88.038 23.323 ;
     RECT  52.344 23.069 62.262 23.351 ;
     RECT  63.576 23.287 70.902 23.359 ;
     RECT  71.676 22.775 72.99 23.359 ;
     RECT  75.564 23.323 88.038 23.387 ;
     RECT  44.424 23.089 51.606 23.395 ;
     RECT  3.672 23.161 43.686 23.431 ;
     RECT  44.424 23.395 52.002 23.431 ;
     RECT  75.564 23.387 87.93 23.549 ;
     RECT  3.672 23.431 52.002 23.585 ;
     RECT  53.028 23.351 62.262 23.657 ;
     RECT  2.415 22.205 2.697 23.827 ;
     RECT  2.376 23.827 2.697 23.863 ;
     RECT  53.388 23.657 62.262 23.863 ;
     RECT  2.376 23.863 2.826 23.899 ;
     RECT  3.672 23.585 44.046 23.899 ;
     RECT  53.388 23.863 62.334 23.933 ;
     RECT  53.604 23.933 62.334 23.971 ;
     RECT  63.576 23.359 72.99 23.971 ;
     RECT  53.604 23.971 62.37 24.061 ;
     RECT  63.144 23.971 72.99 24.061 ;
     RECT  53.604 24.061 72.99 24.091 ;
     RECT  44.892 23.585 52.002 24.133 ;
     RECT  53.604 24.091 73.062 24.133 ;
     RECT  73.8 23.081 74.466 24.133 ;
     RECT  75.564 23.549 87.642 24.161 ;
     RECT  44.892 24.133 52.182 24.205 ;
     RECT  53.604 24.133 74.466 24.205 ;
     RECT  75.564 24.161 87.426 24.205 ;
     RECT  44.892 24.205 52.326 24.233 ;
     RECT  53.604 24.205 87.426 24.269 ;
     RECT  2.376 23.899 44.046 24.359 ;
     RECT  2.415 24.359 44.046 24.403 ;
     RECT  44.892 24.233 48.906 24.403 ;
     RECT  53.604 24.269 75.114 24.503 ;
     RECT  2.415 24.403 48.906 24.629 ;
     RECT  49.788 24.233 52.326 24.629 ;
     RECT  6.084 24.629 48.906 24.773 ;
     RECT  53.604 24.503 75.078 24.781 ;
     RECT  6.084 24.773 47.718 24.899 ;
     RECT  49.86 24.629 52.326 24.943 ;
     RECT  53.424 24.781 75.078 24.943 ;
     RECT  49.86 24.943 75.078 25.043 ;
     RECT  75.96 24.269 87.426 25.079 ;
     RECT  60.48 25.043 75.078 25.277 ;
     RECT  49.86 25.043 59.598 25.313 ;
     RECT  68.976 25.277 75.078 25.321 ;
     RECT  49.86 25.313 59.562 25.349 ;
     RECT  75.96 25.079 87.354 25.349 ;
     RECT  2.415 24.629 5.31 25.411 ;
     RECT  2.34 25.411 5.31 25.439 ;
     RECT  75.96 25.349 87.282 25.447 ;
     RECT  6.12 24.899 47.718 25.519 ;
     RECT  48.492 24.773 48.906 25.519 ;
     RECT  75.852 25.447 87.282 25.619 ;
     RECT  6.12 25.519 48.906 25.681 ;
     RECT  49.86 25.349 57.726 25.681 ;
     RECT  3.636 25.439 5.31 25.717 ;
     RECT  6.12 25.681 57.726 25.717 ;
     RECT  60.48 25.277 68.094 25.745 ;
     RECT  68.976 25.321 75.114 25.825 ;
     RECT  75.852 25.619 86.922 25.825 ;
     RECT  3.636 25.717 57.726 25.859 ;
     RECT  3.636 25.859 57.69 25.979 ;
     RECT  68.976 25.825 86.922 26.093 ;
     RECT  61.668 25.745 68.094 26.095 ;
     RECT  58.572 25.349 59.562 26.123 ;
     RECT  61.668 26.095 68.202 26.131 ;
     RECT  68.976 26.093 69.57 26.131 ;
     RECT  2.34 25.439 2.898 26.221 ;
     RECT  3.636 25.979 57.618 26.221 ;
     RECT  58.608 26.123 59.562 26.221 ;
     RECT  60.48 25.745 60.57 26.221 ;
     RECT  2.34 26.221 57.618 26.285 ;
     RECT  2.34 26.285 53.838 26.519 ;
     RECT  58.608 26.221 60.57 26.635 ;
     RECT  61.668 26.131 69.57 26.635 ;
     RECT  70.308 26.093 86.922 26.671 ;
     RECT  10.764 26.519 53.838 26.789 ;
     RECT  70.308 26.671 87.57 26.789 ;
     RECT  70.308 26.789 87.426 26.861 ;
     RECT  58.608 26.635 69.57 26.869 ;
     RECT  70.308 26.861 87.066 26.869 ;
     RECT  54.648 26.285 57.618 26.875 ;
     RECT  45 26.789 53.838 26.933 ;
     RECT  54.648 26.875 57.87 27.019 ;
     RECT  58.608 26.869 87.066 27.019 ;
     RECT  45.18 26.933 53.838 27.067 ;
     RECT  54.648 27.019 87.066 27.067 ;
     RECT  2.34 26.519 9.954 27.329 ;
     RECT  45.18 27.067 87.066 27.341 ;
     RECT  2.415 27.329 9.954 27.373 ;
     RECT  10.764 26.789 44.19 27.373 ;
     RECT  45.18 27.341 73.854 27.401 ;
     RECT  2.415 27.373 44.19 27.751 ;
     RECT  45.18 27.401 73.674 27.751 ;
     RECT  74.844 27.341 87.066 28.147 ;
     RECT  74.808 28.147 87.066 28.171 ;
     RECT  74.7 28.171 87.066 28.247 ;
     RECT  2.415 27.751 73.674 28.291 ;
     RECT  74.7 28.247 76.446 28.291 ;
     RECT  77.256 28.247 87.066 28.291 ;
     RECT  88.416 26.941 88.434 28.291 ;
     RECT  2.415 28.291 76.446 28.409 ;
     RECT  77.256 28.291 88.434 28.409 ;
     RECT  77.256 28.409 87.066 28.481 ;
     RECT  77.256 28.481 85.698 28.493 ;
     RECT  4.824 28.409 76.446 28.877 ;
     RECT  4.824 28.877 62.514 28.949 ;
     RECT  45.396 28.949 62.514 28.985 ;
     RECT  63.252 28.877 76.446 28.993 ;
     RECT  77.256 28.493 85.662 28.993 ;
     RECT  45.396 28.985 45.99 29.069 ;
     RECT  86.472 28.481 87.066 29.219 ;
     RECT  4.824 28.949 44.55 29.263 ;
     RECT  2.415 28.409 3.906 29.335 ;
     RECT  4.752 29.263 44.55 29.335 ;
     RECT  86.796 29.219 87.066 29.371 ;
     RECT  88.416 28.409 88.434 29.371 ;
     RECT  46.728 28.985 62.514 29.605 ;
     RECT  63.252 28.993 85.662 29.605 ;
     RECT  46.728 29.605 85.662 29.641 ;
     RECT  46.728 29.641 85.77 29.759 ;
     RECT  2.415 29.335 44.55 29.911 ;
     RECT  45.54 29.069 45.99 29.911 ;
     RECT  46.728 29.759 85.698 30.173 ;
     RECT  46.728 30.173 59.418 30.299 ;
     RECT  2.415 29.911 45.99 30.451 ;
     RECT  46.728 30.299 59.31 30.451 ;
     RECT  60.372 30.173 85.698 30.461 ;
     RECT  86.796 29.371 88.434 30.685 ;
     RECT  2.415 30.451 59.31 30.749 ;
     RECT  60.372 30.461 85.446 30.955 ;
     RECT  45.576 30.749 59.31 30.983 ;
     RECT  86.724 30.685 88.434 31.153 ;
     RECT  45.576 30.983 46.962 31.217 ;
     RECT  60.12 30.955 85.446 31.261 ;
     RECT  60.12 31.261 85.482 31.351 ;
     RECT  86.364 31.153 88.434 31.351 ;
     RECT  4.86 30.749 44.838 31.693 ;
     RECT  45.576 31.217 46.782 31.693 ;
     RECT  2.415 30.749 3.834 31.801 ;
     RECT  4.86 31.693 46.782 31.801 ;
     RECT  2.415 31.801 46.782 31.829 ;
     RECT  2.415 31.829 46.638 31.919 ;
     RECT  5.04 31.919 46.638 31.955 ;
     RECT  60.12 31.351 88.434 31.991 ;
     RECT  47.736 30.983 59.31 32.035 ;
     RECT  60.12 31.991 62.658 32.035 ;
     RECT  63.432 31.991 88.434 32.063 ;
     RECT  47.736 32.035 62.658 32.071 ;
     RECT  64.728 32.063 88.434 32.225 ;
     RECT  5.22 31.955 46.638 32.495 ;
     RECT  5.22 32.495 46.602 32.729 ;
     RECT  47.592 32.071 62.658 32.765 ;
     RECT  5.22 32.729 46.53 32.845 ;
     RECT  87.228 32.225 88.434 32.971 ;
     RECT  63.432 32.063 63.918 33.043 ;
     RECT  64.728 32.225 86.166 33.043 ;
     RECT  63.432 33.043 86.166 33.241 ;
     RECT  86.976 32.971 88.434 33.241 ;
     RECT  2.415 31.919 3.87 33.421 ;
     RECT  63.432 33.241 88.434 33.449 ;
     RECT  5.148 32.845 46.53 33.539 ;
     RECT  7.632 33.539 46.53 33.583 ;
     RECT  47.844 32.765 62.658 33.643 ;
     RECT  63.432 33.449 88.074 33.643 ;
     RECT  47.844 33.643 88.074 33.683 ;
     RECT  7.632 33.583 46.818 33.719 ;
     RECT  14.832 33.719 46.818 33.809 ;
     RECT  47.844 33.683 64.026 33.889 ;
     RECT  14.94 33.809 46.818 33.989 ;
     RECT  47.664 33.889 64.026 34.051 ;
     RECT  7.632 33.719 14.058 34.079 ;
     RECT  64.764 33.683 88.074 34.223 ;
     RECT  5.148 33.539 6.858 34.315 ;
     RECT  7.632 34.079 10.314 34.315 ;
     RECT  14.94 33.989 15.354 34.349 ;
     RECT  47.592 34.051 64.026 34.349 ;
     RECT  11.124 34.079 14.058 34.385 ;
     RECT  60.084 34.349 64.026 34.421 ;
     RECT  16.2 33.989 46.818 34.457 ;
     RECT  2.415 33.421 4.122 34.501 ;
     RECT  47.592 34.349 59.31 34.501 ;
     RECT  60.192 34.421 64.026 34.501 ;
     RECT  64.764 34.223 78.858 34.501 ;
     RECT  79.596 34.223 88.074 34.501 ;
     RECT  14.94 34.349 15.21 34.529 ;
     RECT  15.12 34.529 15.21 34.619 ;
     RECT  2.415 34.501 4.158 34.663 ;
     RECT  5.148 34.315 10.314 34.663 ;
     RECT  11.16 34.385 14.058 34.663 ;
     RECT  79.596 34.501 88.11 34.735 ;
     RECT  47.052 34.501 59.31 34.925 ;
     RECT  2.415 34.663 10.314 35.005 ;
     RECT  2.415 35.005 10.35 35.159 ;
     RECT  7.02 35.159 10.35 35.203 ;
     RECT  11.16 34.663 14.346 35.203 ;
     RECT  15.156 34.619 15.21 35.311 ;
     RECT  16.2 34.457 46.062 35.311 ;
     RECT  47.304 34.925 59.31 35.437 ;
     RECT  60.192 34.501 78.858 35.437 ;
     RECT  79.596 34.735 88.29 35.437 ;
     RECT  15.156 35.311 15.426 35.473 ;
     RECT  16.2 35.311 46.494 35.473 ;
     RECT  15.156 35.473 46.494 35.545 ;
     RECT  47.304 35.437 88.29 35.609 ;
     RECT  7.02 35.203 14.346 35.671 ;
     RECT  15.084 35.545 46.494 35.671 ;
     RECT  7.02 35.671 46.494 36.013 ;
     RECT  47.304 35.609 63.486 36.013 ;
     RECT  64.224 35.609 88.29 36.149 ;
     RECT  2.415 35.159 6.138 36.331 ;
     RECT  7.02 36.013 63.486 36.331 ;
     RECT  68.652 36.149 88.29 36.383 ;
     RECT  2.415 36.331 63.486 36.517 ;
     RECT  64.224 36.149 67.914 36.517 ;
     RECT  2.415 36.517 67.914 36.779 ;
     RECT  47.484 36.779 67.914 36.895 ;
     RECT  68.652 36.383 69.102 36.895 ;
     RECT  47.484 36.895 69.102 37.201 ;
     RECT  69.84 36.383 88.29 37.201 ;
     RECT  47.484 37.201 88.29 37.229 ;
     RECT  71.244 37.229 88.29 37.355 ;
     RECT  47.484 37.229 70.398 37.427 ;
     RECT  2.415 36.779 46.71 37.561 ;
     RECT  47.484 37.427 52.398 37.561 ;
     RECT  53.604 37.427 70.398 37.625 ;
     RECT  61.416 37.625 70.398 37.859 ;
     RECT  2.415 37.561 52.398 37.895 ;
     RECT  71.244 37.355 86.814 37.895 ;
     RECT  71.244 37.895 78.858 38.039 ;
     RECT  61.452 37.859 70.398 38.101 ;
     RECT  71.244 38.039 75.546 38.101 ;
     RECT  87.552 37.355 88.29 38.101 ;
     RECT  48.24 37.895 52.398 38.173 ;
     RECT  48.24 38.173 52.434 38.245 ;
     RECT  53.604 37.625 60.498 38.245 ;
     RECT  61.452 38.101 75.546 38.309 ;
     RECT  2.415 37.895 47.142 38.435 ;
     RECT  61.452 38.309 75.366 38.543 ;
     RECT  2.415 38.435 47.106 38.579 ;
     RECT  79.668 37.895 86.814 38.632 ;
     RECT  76.392 38.039 78.858 38.641 ;
     RECT  79.596 38.632 86.814 38.641 ;
     RECT  15.012 38.579 47.106 38.669 ;
     RECT  15.228 38.669 47.034 38.705 ;
     RECT  87.552 38.101 88.326 38.713 ;
     RECT  61.452 38.543 70.902 38.717 ;
     RECT  48.24 38.245 60.498 38.749 ;
     RECT  61.452 38.717 70.758 38.749 ;
     RECT  76.392 38.641 86.814 38.749 ;
     RECT  87.552 38.713 88.434 38.749 ;
     RECT  15.228 38.705 46.854 38.813 ;
     RECT  76.392 38.749 88.434 38.849 ;
     RECT  16.308 38.813 46.854 38.939 ;
     RECT  76.392 38.849 79.002 38.947 ;
     RECT  48.24 38.749 70.758 39.011 ;
     RECT  48.24 39.011 59.562 39.019 ;
     RECT  48.204 39.019 59.562 39.055 ;
     RECT  16.38 38.939 46.854 39.083 ;
     RECT  48.132 39.055 59.562 39.091 ;
     RECT  71.64 38.543 75.366 39.091 ;
     RECT  76.284 38.947 79.002 39.091 ;
     RECT  2.415 38.579 14.238 39.209 ;
     RECT  48.024 39.091 59.562 39.245 ;
     RECT  48.24 39.245 59.49 39.281 ;
     RECT  60.336 39.011 70.758 39.281 ;
     RECT  14.22 39.209 14.238 39.451 ;
     RECT  15.228 38.813 15.534 39.451 ;
     RECT  60.516 39.281 70.758 39.451 ;
     RECT  71.64 39.091 79.002 39.451 ;
     RECT  60.516 39.451 79.002 39.551 ;
     RECT  16.452 39.083 46.854 39.595 ;
     RECT  70.128 39.551 79.002 39.623 ;
     RECT  79.776 38.849 88.434 39.821 ;
     RECT  60.516 39.551 69.354 39.857 ;
     RECT  16.452 39.595 47.502 39.893 ;
     RECT  82.728 39.821 88.434 39.893 ;
     RECT  13.14 39.209 13.497 39.991 ;
     RECT  14.22 39.451 15.534 39.991 ;
     RECT  2.415 39.209 12.402 40.063 ;
     RECT  13.14 39.991 15.534 40.063 ;
     RECT  2.415 40.063 15.534 40.135 ;
     RECT  16.452 39.893 16.722 40.135 ;
     RECT  79.776 39.821 81.954 40.267 ;
     RECT  60.516 39.857 63.918 40.297 ;
     RECT  64.728 39.857 69.354 40.325 ;
     RECT  64.8 40.325 69.354 40.369 ;
     RECT  70.128 39.623 78.858 40.369 ;
     RECT  64.8 40.369 78.858 40.433 ;
     RECT  17.46 39.893 47.502 40.441 ;
     RECT  48.24 39.281 59.454 40.441 ;
     RECT  60.228 40.297 63.918 40.441 ;
     RECT  72 40.433 78.858 40.531 ;
     RECT  79.632 40.267 81.954 40.531 ;
     RECT  72 40.531 81.954 40.675 ;
     RECT  82.764 39.893 88.434 40.675 ;
     RECT  72 40.675 88.434 40.703 ;
     RECT  2.415 40.135 16.722 40.711 ;
     RECT  17.46 40.441 63.918 40.711 ;
     RECT  2.415 40.711 63.918 40.829 ;
     RECT  64.8 40.433 71.226 40.829 ;
     RECT  9.972 40.829 63.918 41.071 ;
     RECT  64.8 40.829 71.118 41.071 ;
     RECT  9.972 41.071 71.118 41.099 ;
     RECT  86.328 40.703 88.434 41.171 ;
     RECT  72 40.703 85.59 41.251 ;
     RECT  9.972 41.099 71.082 41.369 ;
     RECT  71.964 41.251 85.59 41.521 ;
     RECT  86.328 41.171 86.922 41.521 ;
     RECT  2.415 40.829 9.09 41.611 ;
     RECT  9.972 41.369 71.01 41.611 ;
     RECT  71.964 41.521 86.922 41.755 ;
     RECT  2.415 41.611 71.01 41.789 ;
     RECT  71.892 41.755 86.922 41.945 ;
     RECT  81.936 41.945 86.922 42.331 ;
     RECT  87.66 41.171 88.434 42.331 ;
     RECT  2.415 41.789 46.602 42.557 ;
     RECT  71.892 41.945 81.09 42.601 ;
     RECT  81.936 42.331 88.434 42.691 ;
     RECT  71.748 42.601 81.09 42.835 ;
     RECT  81.828 42.691 88.434 42.835 ;
     RECT  47.376 41.789 71.01 42.899 ;
     RECT  47.376 42.899 57.006 42.997 ;
     RECT  57.744 42.899 71.01 43.141 ;
     RECT  71.748 42.835 88.434 43.141 ;
     RECT  47.34 42.997 57.006 43.259 ;
     RECT  57.744 43.141 88.434 43.295 ;
     RECT  81.54 43.295 88.434 43.331 ;
     RECT  2.415 42.557 46.53 43.771 ;
     RECT  47.34 43.259 56.754 43.771 ;
     RECT  57.744 43.295 80.802 43.843 ;
     RECT  57.6 43.843 80.802 44.069 ;
     RECT  57.6 44.069 70.506 44.105 ;
     RECT  57.6 44.105 64.494 44.113 ;
     RECT  69.588 44.105 70.506 44.141 ;
     RECT  2.415 43.771 56.754 44.221 ;
     RECT  57.492 44.113 64.494 44.221 ;
     RECT  70.308 44.141 70.506 44.339 ;
     RECT  70.308 44.339 70.398 44.375 ;
     RECT  2.415 44.221 64.494 44.717 ;
     RECT  65.304 44.105 68.67 44.887 ;
     RECT  64.116 44.717 64.494 44.995 ;
     RECT  65.304 44.887 68.958 44.995 ;
     RECT  71.28 44.069 80.802 45.019 ;
     RECT  81.648 43.331 88.434 45.019 ;
     RECT  64.116 44.995 68.958 45.031 ;
     RECT  70.38 44.375 70.398 45.149 ;
     RECT  64.116 45.031 69.21 45.301 ;
     RECT  71.28 45.019 88.434 45.301 ;
     RECT  64.116 45.301 69.39 45.599 ;
     RECT  71.172 45.301 88.434 45.689 ;
     RECT  64.116 45.599 68.454 45.725 ;
     RECT  2.415 44.717 63.378 45.841 ;
     RECT  64.116 45.725 67.662 45.841 ;
     RECT  69.264 45.599 69.39 45.841 ;
     RECT  70.236 45.265 70.254 45.841 ;
     RECT  69.264 45.841 70.254 45.869 ;
     RECT  69.552 45.869 70.254 46.003 ;
     RECT  71.172 45.689 85.086 46.003 ;
     RECT  68.436 45.725 68.454 46.157 ;
     RECT  2.415 45.841 67.662 46.373 ;
     RECT  2.415 46.373 65.934 46.409 ;
     RECT  68.616 46.381 68.634 46.885 ;
     RECT  69.552 46.003 85.086 46.885 ;
     RECT  85.824 45.689 88.434 46.885 ;
     RECT  66.672 46.373 67.662 46.921 ;
     RECT  68.616 46.885 88.434 46.921 ;
     RECT  9.144 46.409 65.934 46.949 ;
     RECT  53.424 46.949 65.934 47.075 ;
     RECT  2.415 46.409 8.298 47.155 ;
     RECT  9.144 46.949 52.614 47.155 ;
     RECT  53.784 47.075 65.934 47.191 ;
     RECT  66.672 46.921 88.434 47.191 ;
     RECT  53.784 47.191 88.434 47.309 ;
     RECT  69.3 47.309 88.434 47.345 ;
     RECT  69.3 47.345 84.15 47.687 ;
     RECT  69.3 47.687 79.614 47.759 ;
     RECT  84.924 47.345 88.434 47.759 ;
     RECT  2.415 47.155 52.614 47.849 ;
     RECT  84.924 47.759 88.218 47.957 ;
     RECT  53.784 47.309 68.562 48.001 ;
     RECT  84.924 47.957 88.146 48.091 ;
     RECT  2.415 47.849 52.146 48.119 ;
     RECT  2.415 48.119 52.002 48.155 ;
     RECT  53.352 48.001 68.562 48.191 ;
     RECT  53.352 48.191 55.602 48.271 ;
     RECT  80.388 47.687 84.15 48.361 ;
     RECT  84.888 48.091 88.146 48.361 ;
     RECT  56.415 48.191 68.562 48.541 ;
     RECT  69.3 47.759 79.218 48.541 ;
     RECT  80.388 48.361 88.146 48.695 ;
     RECT  2.415 48.155 51.714 48.803 ;
     RECT  56.415 48.541 79.218 48.901 ;
     RECT  80.568 48.695 88.146 48.965 ;
     RECT  52.92 48.271 55.602 48.973 ;
     RECT  56.415 48.901 79.578 49.001 ;
     RECT  80.604 48.965 88.146 49.009 ;
     RECT  65.556 49.001 79.578 49.037 ;
     RECT  4.932 48.803 51.714 49.081 ;
     RECT  52.884 48.973 55.602 49.171 ;
     RECT  56.415 49.001 64.782 49.171 ;
     RECT  80.604 49.009 88.362 49.199 ;
     RECT  4.932 49.081 51.894 49.235 ;
     RECT  52.884 49.171 64.782 49.243 ;
     RECT  51.015 49.235 51.894 49.315 ;
     RECT  52.632 49.243 64.782 49.315 ;
     RECT  2.415 48.803 4.014 49.351 ;
     RECT  51.015 49.315 64.782 49.469 ;
     RECT  57.852 49.469 64.782 49.505 ;
     RECT  2.376 49.351 4.014 49.577 ;
     RECT  2.415 49.577 4.014 49.585 ;
     RECT  58.032 49.505 64.782 49.739 ;
     RECT  65.556 49.037 66.258 49.757 ;
     RECT  51.015 49.469 57.042 49.775 ;
     RECT  67.104 49.037 79.578 49.783 ;
     RECT  80.604 49.199 88.218 49.783 ;
     RECT  65.556 49.757 66.186 49.891 ;
     RECT  65.52 49.891 66.186 49.981 ;
     RECT  56.052 49.775 57.042 50.009 ;
     RECT  67.104 49.783 88.218 50.009 ;
     RECT  67.104 50.009 88.146 50.045 ;
     RECT  51.015 49.775 55.314 50.081 ;
     RECT  67.104 50.045 88.11 50.117 ;
     RECT  2.415 49.585 4.122 50.125 ;
     RECT  4.932 49.235 50.274 50.125 ;
     RECT  67.104 50.117 88.038 50.125 ;
     RECT  2.415 50.125 50.274 50.161 ;
     RECT  51.015 50.081 55.098 50.161 ;
     RECT  67.032 50.125 88.038 50.161 ;
     RECT  2.415 50.161 55.098 50.279 ;
     RECT  58.032 49.739 64.638 50.423 ;
     RECT  4.896 50.279 55.098 50.585 ;
     RECT  66.96 50.161 88.038 50.621 ;
     RECT  58.176 50.423 64.638 50.657 ;
     RECT  65.412 49.981 66.186 50.701 ;
     RECT  66.96 50.621 85.302 50.701 ;
     RECT  5.724 50.585 55.098 50.729 ;
     RECT  58.428 50.657 64.638 50.729 ;
     RECT  61.704 50.729 64.638 50.963 ;
     RECT  56.052 50.009 56.697 50.965 ;
     RECT  57.42 50.731 57.438 50.965 ;
     RECT  6.156 50.729 55.098 50.971 ;
     RECT  56.052 50.965 57.438 50.971 ;
     RECT  61.704 50.963 63.27 50.999 ;
     RECT  64.044 50.963 64.638 51.061 ;
     RECT  65.412 50.701 85.302 51.061 ;
     RECT  6.156 50.971 57.438 51.089 ;
     RECT  63.036 50.999 63.27 51.089 ;
     RECT  64.044 51.061 85.302 51.089 ;
     RECT  58.428 50.729 60.966 51.161 ;
     RECT  6.156 51.089 50.058 51.197 ;
     RECT  86.58 50.621 88.038 51.205 ;
     RECT  59.976 51.161 60.966 51.233 ;
     RECT  2.415 50.279 4.05 51.241 ;
     RECT  4.896 50.585 4.986 51.241 ;
     RECT  59.976 51.233 59.994 51.269 ;
     RECT  2.415 51.241 4.986 51.307 ;
     RECT  6.156 51.197 49.986 51.359 ;
     RECT  60.948 51.233 60.966 51.359 ;
     RECT  61.704 50.999 62.262 51.359 ;
     RECT  86.58 51.205 88.146 51.359 ;
     RECT  86.58 51.359 88.038 51.367 ;
     RECT  86.544 51.367 88.038 51.395 ;
     RECT  58.428 51.161 59.238 51.431 ;
     RECT  86.544 51.395 87.786 51.467 ;
     RECT  50.94 51.089 57.438 51.475 ;
     RECT  58.428 51.431 59.202 51.475 ;
     RECT  50.94 51.475 59.202 51.503 ;
     RECT  2.415 51.307 5.238 51.511 ;
     RECT  6.156 51.359 15.462 51.511 ;
     RECT  72.072 51.089 85.302 51.511 ;
     RECT  63.216 51.089 63.234 51.533 ;
     RECT  86.58 51.467 87.354 51.629 ;
     RECT  86.58 51.629 87.138 51.665 ;
     RECT  2.415 51.511 15.462 51.737 ;
     RECT  6.336 51.737 15.462 51.773 ;
     RECT  72.072 51.511 85.374 51.781 ;
     RECT  2.415 51.737 5.418 51.809 ;
     RECT  3.888 51.809 5.418 51.899 ;
     RECT  15.264 51.773 15.462 51.917 ;
     RECT  72.072 51.781 85.518 52.007 ;
     RECT  16.2 51.359 49.986 52.015 ;
     RECT  50.94 51.503 58.41 52.015 ;
     RECT  72.072 52.007 82.638 52.043 ;
     RECT  64.044 51.089 71.262 52.141 ;
     RECT  3.888 51.899 5.346 52.169 ;
     RECT  6.336 51.773 14.526 52.205 ;
     RECT  61.776 51.359 62.262 52.213 ;
     RECT  63.324 52.141 71.262 52.285 ;
     RECT  72.072 52.043 82.566 52.285 ;
     RECT  63.324 52.285 82.566 52.301 ;
     RECT  81.324 52.301 82.566 52.313 ;
     RECT  15.444 51.917 15.462 52.321 ;
     RECT  16.2 52.015 58.41 52.321 ;
     RECT  59.184 51.503 59.202 52.321 ;
     RECT  60.948 52.213 62.262 52.321 ;
     RECT  63.324 52.301 80.406 52.321 ;
     RECT  81.432 52.313 82.566 52.349 ;
     RECT  59.184 52.321 59.814 52.411 ;
     RECT  6.408 52.205 14.526 52.439 ;
     RECT  15.444 52.321 58.41 52.483 ;
     RECT  59.184 52.411 60.138 52.483 ;
     RECT  83.415 52.007 85.518 52.709 ;
     RECT  83.415 52.709 84.618 52.745 ;
     RECT  6.66 52.439 14.526 52.753 ;
     RECT  15.444 52.483 60.138 52.753 ;
     RECT  60.948 52.321 80.406 52.753 ;
     RECT  3.888 52.169 5.31 52.817 ;
     RECT  85.5 52.709 85.518 52.861 ;
     RECT  3.888 52.817 4.734 52.979 ;
     RECT  81.468 52.349 82.566 52.979 ;
     RECT  85.5 52.861 85.554 52.979 ;
     RECT  3.888 52.979 4.41 53.024 ;
     RECT  6.66 52.753 80.406 53.131 ;
     RECT  81.468 52.979 82.53 53.131 ;
     RECT  6.66 53.131 82.53 53.285 ;
     RECT  6.66 53.285 51.93 53.357 ;
     RECT  6.66 53.357 16.902 53.401 ;
     RECT  85.5 52.979 85.518 53.467 ;
     RECT  2.415 51.809 2.697 53.491 ;
     RECT  2.415 53.491 2.97 53.515 ;
     RECT  85.32 53.467 85.518 53.519 ;
     RECT  3.888 53.024 3.978 53.527 ;
     RECT  5.76 53.365 5.778 53.549 ;
     RECT  2.376 53.515 2.97 53.557 ;
     RECT  83.415 52.745 84.546 53.563 ;
     RECT  2.304 53.557 2.97 53.597 ;
     RECT  2.415 53.597 2.97 53.599 ;
     RECT  3.816 53.527 3.978 53.599 ;
     RECT  6.588 53.401 16.902 53.599 ;
     RECT  86.58 51.665 86.598 53.671 ;
     RECT  83.376 53.563 84.546 53.789 ;
     RECT  52.956 53.285 82.53 53.851 ;
     RECT  83.376 53.789 83.754 53.851 ;
     RECT  84.528 53.789 84.546 53.905 ;
     RECT  6.408 53.599 16.902 53.933 ;
     RECT  2.415 53.599 3.978 53.941 ;
     RECT  17.712 53.357 51.93 54.031 ;
     RECT  2.415 53.941 4.41 54.103 ;
     RECT  17.712 54.031 52.002 54.139 ;
     RECT  52.956 53.851 83.754 54.139 ;
     RECT  6.732 53.933 16.902 54.211 ;
     RECT  6.732 54.211 16.938 54.329 ;
     RECT  2.415 54.103 5.13 54.373 ;
     RECT  6.768 54.329 16.938 54.373 ;
     RECT  17.712 54.139 83.754 54.373 ;
     RECT  84.528 53.905 85.122 54.409 ;
     RECT  2.415 54.373 5.202 54.481 ;
     RECT  6.768 54.373 83.754 54.599 ;
     RECT  53.532 54.599 83.754 54.643 ;
     RECT  2.415 54.481 5.706 54.671 ;
     RECT  2.415 54.671 5.598 54.715 ;
     RECT  84.528 54.409 85.158 54.715 ;
     RECT  53.532 54.643 83.79 54.743 ;
     RECT  62.82 54.743 83.79 54.869 ;
     RECT  2.34 54.715 5.598 54.905 ;
     RECT  86.256 53.671 86.598 54.913 ;
     RECT  84.528 54.715 85.338 55.021 ;
     RECT  86.076 54.913 86.598 55.021 ;
     RECT  62.82 54.869 83.697 55.175 ;
     RECT  84.528 55.021 86.598 55.381 ;
     RECT  84.528 55.381 87.318 55.417 ;
     RECT  6.768 54.599 52.686 55.445 ;
     RECT  53.532 54.743 62.097 55.525 ;
     RECT  62.82 55.175 81.234 55.525 ;
     RECT  84.528 55.417 88.002 55.561 ;
     RECT  82.152 55.175 83.697 55.651 ;
     RECT  53.244 55.525 81.234 55.679 ;
     RECT  53.388 55.679 81.234 55.715 ;
     RECT  2.415 54.905 5.598 55.717 ;
     RECT  84.528 55.561 88.434 55.921 ;
     RECT  82.152 55.651 83.718 55.957 ;
     RECT  82.044 55.957 83.718 55.993 ;
     RECT  84.456 55.921 88.434 55.993 ;
     RECT  53.604 55.715 81.234 56.065 ;
     RECT  82.044 55.993 88.434 56.065 ;
     RECT  2.34 55.717 5.598 56.263 ;
     RECT  2.34 56.263 5.742 56.291 ;
     RECT  6.768 55.445 52.47 56.461 ;
     RECT  53.604 56.065 88.434 56.489 ;
     RECT  2.415 56.291 5.742 56.533 ;
     RECT  2.415 56.533 5.85 56.641 ;
     RECT  6.768 56.461 52.758 56.641 ;
     RECT  53.604 56.489 88.362 56.641 ;
     RECT  6.768 56.641 88.362 56.867 ;
     RECT  2.415 56.641 5.958 56.869 ;
     RECT  16.596 56.867 88.362 56.903 ;
     RECT  16.596 56.903 85.122 56.939 ;
     RECT  17.136 56.939 85.122 57.005 ;
     RECT  2.415 56.869 5.994 57.037 ;
     RECT  6.768 56.867 15.858 57.037 ;
     RECT  17.136 57.005 59.706 57.173 ;
     RECT  2.415 57.037 15.858 57.341 ;
     RECT  85.896 56.903 88.362 57.451 ;
     RECT  85.896 57.451 88.398 57.641 ;
     RECT  17.136 57.173 53.874 57.919 ;
     RECT  54.648 57.173 55.026 57.919 ;
     RECT  55.764 57.173 59.706 57.919 ;
     RECT  17.136 57.919 59.706 57.955 ;
     RECT  17.1 57.955 59.706 57.991 ;
     RECT  60.48 57.005 85.122 57.991 ;
     RECT  85.896 57.641 88.182 57.991 ;
     RECT  16.596 57.991 88.182 58.117 ;
     RECT  2.415 57.341 15.714 58.123 ;
     RECT  16.452 58.117 88.182 58.123 ;
     RECT  2.415 58.123 88.182 58.657 ;
     RECT  2.376 58.657 88.182 58.691 ;
     RECT  86.04 58.691 88.182 58.801 ;
     RECT  86.04 58.801 88.434 59.189 ;
     RECT  86.04 59.189 88.362 59.225 ;
     RECT  2.376 58.691 85.194 59.729 ;
     RECT  2.415 59.729 85.194 59.737 ;
     RECT  86.04 59.225 87.75 59.737 ;
     RECT  2.415 59.737 87.75 59.741 ;
     RECT  2.415 59.741 59.706 59.999 ;
     RECT  60.516 59.741 87.75 60.151 ;
     RECT  2.415 59.999 58.806 60.377 ;
     RECT  2.415 60.377 58.698 60.461 ;
     RECT  59.58 59.999 59.706 60.583 ;
     RECT  60.516 60.151 88.002 60.583 ;
     RECT  2.415 60.461 58.374 60.647 ;
     RECT  59.58 60.583 88.002 60.683 ;
     RECT  59.58 60.683 87.39 60.719 ;
     RECT  59.652 60.719 87.39 61.079 ;
     RECT  59.652 61.079 87.246 61.187 ;
     RECT  54.72 60.647 58.374 61.231 ;
     RECT  59.652 61.187 64.674 61.349 ;
     RECT  65.556 61.187 87.246 61.349 ;
     RECT  86.544 61.349 86.886 61.385 ;
     RECT  2.415 60.647 53.838 61.429 ;
     RECT  2.376 61.429 53.874 61.501 ;
     RECT  54.72 61.231 58.734 61.501 ;
     RECT  2.376 61.501 58.734 61.529 ;
     RECT  62.856 61.349 64.674 61.529 ;
     RECT  86.544 61.385 86.706 61.619 ;
     RECT  65.556 61.349 85.77 61.655 ;
     RECT  86.688 61.619 86.706 61.691 ;
     RECT  59.652 61.349 62.097 61.699 ;
     RECT  62.856 61.529 64.458 61.799 ;
     RECT  2.376 61.529 58.302 61.889 ;
     RECT  62.892 61.799 64.458 61.889 ;
     RECT  85.68 61.655 85.77 61.889 ;
     RECT  53.352 61.889 58.302 61.925 ;
     RECT  2.415 61.889 52.254 61.961 ;
     RECT  62.892 61.889 64.422 62.033 ;
     RECT  65.556 61.655 84.942 62.033 ;
     RECT  85.752 61.889 85.77 62.033 ;
     RECT  62.892 62.033 64.314 62.045 ;
     RECT  2.415 61.961 2.862 62.069 ;
     RECT  62.892 62.045 64.242 62.069 ;
     RECT  65.556 62.033 65.898 62.069 ;
     RECT  66.708 62.033 84.942 62.069 ;
     RECT  3.816 61.961 52.254 62.159 ;
     RECT  53.568 61.925 58.302 62.159 ;
     RECT  7.056 62.159 52.11 62.195 ;
     RECT  53.568 62.159 55.314 62.195 ;
     RECT  56.124 62.159 58.302 62.195 ;
     RECT  66.708 62.069 80.586 62.231 ;
     RECT  71.172 62.231 80.586 62.267 ;
     RECT  7.056 62.195 52.038 62.303 ;
     RECT  59.04 61.699 62.097 62.303 ;
     RECT  66.708 62.231 70.398 62.303 ;
     RECT  74.016 62.267 75.438 62.303 ;
     RECT  77.148 62.267 80.586 62.303 ;
     RECT  57.636 62.195 58.302 62.311 ;
     RECT  62.892 62.069 64.026 62.339 ;
     RECT  65.556 62.069 65.574 62.339 ;
     RECT  74.124 62.303 75.438 62.339 ;
     RECT  76.284 62.267 76.374 62.339 ;
     RECT  77.472 62.303 80.586 62.339 ;
     RECT  2.415 62.069 2.697 62.387 ;
     RECT  59.688 62.303 62.097 62.387 ;
     RECT  71.172 62.267 72.897 62.387 ;
     RECT  3.816 62.159 3.978 62.429 ;
     RECT  4.824 62.159 6.102 62.429 ;
     RECT  7.056 62.303 51.966 62.429 ;
     RECT  53.568 62.195 55.17 62.429 ;
     RECT  57.636 62.311 58.59 62.429 ;
     RECT  62.892 62.339 62.982 62.429 ;
     RECT  77.472 62.339 78.642 62.429 ;
     RECT  79.416 62.339 80.586 62.429 ;
     RECT  81.396 62.069 84.942 62.429 ;
     RECT  53.568 62.429 54.306 62.435 ;
     RECT  4.824 62.429 5.922 62.465 ;
     RECT  42.696 62.429 43.506 62.465 ;
     RECT  47.952 62.429 48.078 62.465 ;
     RECT  49.104 62.429 51.786 62.465 ;
     RECT  54.108 62.435 54.306 62.465 ;
     RECT  55.08 62.429 55.098 62.465 ;
     RECT  58.104 62.429 58.41 62.465 ;
     RECT  59.688 62.387 61.905 62.465 ;
     RECT  62.964 62.429 62.982 62.465 ;
     RECT  81.396 62.429 82.386 62.465 ;
     RECT  84.42 62.429 84.942 62.465 ;
     RECT  81.396 62.465 81.99 62.477 ;
     RECT  83.124 62.429 83.574 62.477 ;
     RECT  18.288 62.429 27.378 62.501 ;
     RECT  47.952 62.465 47.97 62.501 ;
     RECT  50.148 62.465 50.166 62.501 ;
     RECT  56.415 62.195 56.79 62.501 ;
     RECT  58.104 62.465 58.266 62.501 ;
     RECT  79.416 62.429 79.722 62.501 ;
     RECT  60.984 62.465 61.002 62.537 ;
     RECT  64.008 62.339 64.026 62.537 ;
     RECT  66.708 62.303 68.778 62.537 ;
     RECT  71.172 62.387 72.81 62.537 ;
     RECT  77.472 62.429 78.57 62.537 ;
     RECT  84.924 62.465 84.942 62.537 ;
     RECT  7.056 62.429 10.602 62.573 ;
     RECT  18.288 62.501 26.01 62.573 ;
     RECT  44.424 62.429 47.07 62.573 ;
     RECT  58.104 62.501 58.122 62.573 ;
     RECT  68.544 62.537 68.778 62.573 ;
     RECT  69.516 62.303 70.398 62.573 ;
     RECT  71.784 62.537 72.81 62.573 ;
     RECT  74.16 62.339 75.438 62.573 ;
     RECT  72.615 62.573 72.81 62.579 ;
     RECT  74.16 62.573 74.286 62.579 ;
     RECT  75.42 62.573 75.438 62.579 ;
     RECT  7.056 62.573 10.53 62.609 ;
     RECT  11.52 62.429 14.526 62.609 ;
     RECT  18.288 62.573 20.43 62.609 ;
     RECT  31.536 62.429 41.418 62.609 ;
     RECT  43.488 62.465 43.506 62.609 ;
     RECT  44.424 62.573 46.818 62.609 ;
     RECT  66.708 62.537 67.305 62.609 ;
     RECT  69.624 62.573 70.074 62.609 ;
     RECT  71.784 62.573 71.802 62.609 ;
     RECT  74.268 62.579 74.286 62.609 ;
     RECT  76.356 62.339 76.374 62.609 ;
     RECT  77.472 62.537 78.354 62.609 ;
     RECT  79.416 62.501 79.434 62.609 ;
     RECT  4.824 62.465 4.842 62.621 ;
     RECT  5.904 62.465 5.922 62.621 ;
     RECT  31.536 62.609 40.95 62.621 ;
     RECT  2.415 62.387 2.505 62.657 ;
     RECT  7.056 62.609 9.99 62.657 ;
     RECT  12.024 62.609 14.238 62.657 ;
     RECT  28.44 62.429 30.726 62.657 ;
     RECT  44.928 62.609 46.818 62.657 ;
     RECT  50.904 62.465 51.105 62.657 ;
     RECT  56.415 62.501 56.505 62.657 ;
     RECT  61.815 62.465 61.905 62.657 ;
     RECT  67.215 62.609 67.305 62.657 ;
     RECT  72.615 62.579 72.705 62.657 ;
     RECT  77.472 62.609 78.105 62.657 ;
     RECT  83.415 62.477 83.574 62.657 ;
     RECT  7.056 62.657 7.29 62.669 ;
     RECT  8.244 62.657 9.99 62.669 ;
     RECT  12.024 62.657 12.978 62.669 ;
     RECT  13.752 62.657 14.238 62.669 ;
     RECT  15.588 62.429 15.93 62.669 ;
     RECT  26.784 62.501 27.378 62.669 ;
     RECT  28.44 62.657 28.89 62.669 ;
     RECT  29.844 62.657 30.726 62.669 ;
     RECT  20.016 62.609 20.43 62.699 ;
     RECT  42.696 62.465 42.714 62.699 ;
     RECT  44.928 62.657 45.018 62.699 ;
     RECT  46.332 62.657 46.818 62.699 ;
     RECT  50.904 62.657 50.922 62.699 ;
     RECT  54.108 62.465 54.126 62.699 ;
     RECT  68.76 62.573 68.778 62.699 ;
     RECT  77.472 62.657 77.562 62.699 ;
     RECT  81.972 62.477 81.99 62.699 ;
     RECT  83.556 62.657 83.574 62.699 ;
     RECT  32.292 62.621 40.95 62.717 ;
     RECT  7.272 62.669 7.29 62.765 ;
     RECT  13.968 62.669 14.238 62.765 ;
     RECT  15.912 62.669 15.93 62.765 ;
     RECT  18.288 62.609 19.17 62.765 ;
     RECT  21.492 62.573 26.01 62.765 ;
     RECT  29.916 62.669 30.294 62.765 ;
     RECT  40.572 62.717 40.914 62.765 ;
     RECT  44.928 62.699 44.946 62.771 ;
     RECT  46.8 62.699 46.818 62.771 ;
     RECT  18.288 62.765 19.062 62.813 ;
     RECT  21.492 62.765 25.47 62.813 ;
     RECT  29.916 62.765 30.222 62.813 ;
     RECT  32.292 62.717 36.378 62.813 ;
     RECT  32.292 62.813 35.91 62.861 ;
     RECT  34.74 62.861 35.91 62.909 ;
     RECT  40.896 62.765 40.914 62.909 ;
     RECT  20.412 62.699 20.43 63.245 ;
     RECT  21.492 62.813 22.518 63.245 ;
     RECT  23.544 62.813 25.47 63.245 ;
     RECT  35.28 62.909 35.91 63.245 ;
     RECT  8.388 62.669 9.99 63.293 ;
     RECT  12.384 62.669 12.402 63.293 ;
     RECT  18.756 62.813 19.062 63.293 ;
     RECT  21.672 63.245 22.518 63.293 ;
     RECT  32.292 62.861 34.002 63.293 ;
     RECT  35.28 63.245 35.298 63.293 ;
     RECT  39.708 62.717 39.726 63.293 ;
     RECT  22.356 63.293 22.518 63.341 ;
     RECT  37.836 62.717 37.854 63.821 ;
     RECT  3.816 62.429 3.834 63.869 ;
     RECT  14.22 62.765 14.238 63.869 ;
     RECT  16.92 62.429 17.046 63.869 ;
     RECT  24.732 63.245 25.146 63.869 ;
     RECT  26.964 62.669 27.306 63.869 ;
     RECT  29.916 62.813 30.186 63.869 ;
     RECT  31.536 62.621 31.554 63.869 ;
     RECT  17.028 63.869 17.046 63.917 ;
     RECT  23.544 63.245 23.958 64.411 ;
     RECT  23.544 64.411 24.498 64.541 ;
     RECT  26.964 63.869 27.198 64.541 ;
     RECT  28.44 62.669 28.782 64.589 ;
     RECT  32.292 63.293 33.822 64.637 ;
     RECT  38.628 62.717 38.898 64.637 ;
     RECT  9.288 63.293 9.99 64.685 ;
     RECT  11.124 64.555 11.142 64.685 ;
     RECT  19.044 63.293 19.062 64.685 ;
     RECT  23.544 64.541 24.282 64.685 ;
     RECT  27.18 64.541 27.198 64.685 ;
     RECT  32.508 64.637 33.174 64.685 ;
     RECT  38.628 64.637 38.646 64.685 ;
     RECT  25.56 64.603 25.578 64.733 ;
     RECT  28.44 64.589 28.458 64.733 ;
     RECT  22.5 63.341 22.518 64.781 ;
     RECT  24.264 64.685 24.282 64.781 ;
     RECT  30.168 63.869 30.186 64.781 ;
    LAYER M4 ;
     RECT  0.06 16.416 0.133 19.416 ;
     RECT  0.06 8.256 0.137 14.328 ;
     RECT  0.06 4.032 0.227 6.072 ;
     RECT  0.137 8.352 0.277 14.328 ;
     RECT  0.277 8.352 2.221 15.288 ;
     RECT  0.133 16.416 2.221 19.56 ;
     RECT  2.252 53.568 2.365 53.592 ;
     RECT  0.227 4.992 2.408 6.072 ;
     RECT  0.06 7.104 2.408 7.224 ;
     RECT  2.221 8.352 2.408 19.56 ;
     RECT  2.365 23.856 2.408 23.88 ;
     RECT  0.181 33.072 2.408 33.096 ;
     RECT  2.365 53.52 2.408 53.592 ;
     RECT  2.285 54.72 2.408 54.744 ;
     RECT  2.329 55.728 2.408 55.752 ;
     RECT  2.365 59.232 2.408 59.256 ;
     RECT  2.408 2.148 2.512 62.652 ;
     RECT  2.512 2.256 2.704 62.382 ;
     RECT  2.704 39.744 2.819 39.768 ;
     RECT  2.704 8.688 2.945 19.56 ;
     RECT  2.704 27.888 2.945 27.96 ;
     RECT  2.704 2.256 3.025 2.28 ;
     RECT  2.704 32.976 3.089 35.208 ;
     RECT  3.089 34.128 3.107 35.208 ;
     RECT  2.704 25.584 3.347 26.904 ;
     RECT  2.945 27.936 3.349 27.96 ;
     RECT  2.704 42.768 3.377 43.56 ;
     RECT  3.409 0.336 3.481 0.36 ;
     RECT  2.704 50.16 3.521 50.424 ;
     RECT  3.347 25.584 3.665 25.608 ;
     RECT  2.704 55.2 3.697 55.752 ;
     RECT  2.704 57.072 3.697 57.096 ;
     RECT  3.74 44.832 3.827 44.856 ;
     RECT  2.704 20.592 3.841 20.616 ;
     RECT  2.704 21.648 3.841 22.2 ;
     RECT  3.697 55.2 3.841 57.096 ;
     RECT  2.704 4.944 3.877 7.608 ;
     RECT  2.945 8.688 3.877 19.368 ;
     RECT  3.841 55.2 3.881 57.576 ;
     RECT  3.377 43.536 3.925 43.56 ;
     RECT  2.704 40.992 3.971 41.544 ;
     RECT  2.704 58.704 3.973 59.256 ;
     RECT  3.877 4.944 3.985 19.368 ;
     RECT  3.841 20.592 3.985 22.2 ;
     RECT  3.481 0.336 4.057 0.504 ;
     RECT  2.704 3.264 4.057 3.288 ;
     RECT  3.107 34.752 4.061 35.208 ;
     RECT  3.805 63.84 4.067 63.864 ;
     RECT  3.985 4.944 4.097 22.2 ;
     RECT  2.704 61.872 4.117 61.896 ;
     RECT  3.973 58.656 4.129 59.256 ;
     RECT  4.057 0.144 4.165 0.504 ;
     RECT  4.061 35.184 4.169 35.208 ;
     RECT  4.097 4.944 4.172 11.448 ;
     RECT  4.117 61.392 4.204 61.896 ;
     RECT  4.172 4.368 4.259 11.448 ;
     RECT  4.129 58.656 4.268 59.784 ;
     RECT  4.165 0.144 4.273 0.552 ;
     RECT  3.985 1.728 4.273 1.752 ;
     RECT  3.881 55.2 4.355 55.752 ;
     RECT  4.268 58.56 4.355 59.784 ;
     RECT  2.704 53.52 4.381 54.168 ;
     RECT  4.355 55.2 4.396 55.272 ;
     RECT  4.381 52.992 4.405 54.168 ;
     RECT  4.396 55.2 4.405 55.224 ;
     RECT  3.925 43.536 4.453 43.752 ;
     RECT  4.273 0.144 4.481 1.752 ;
     RECT  4.405 52.992 4.492 55.224 ;
     RECT  4.481 0.096 4.556 1.752 ;
     RECT  4.057 2.832 4.556 3.288 ;
     RECT  4.556 0.096 4.565 3.288 ;
     RECT  4.355 59.184 4.597 59.784 ;
     RECT  4.453 29.616 4.601 29.64 ;
     RECT  4.492 55.2 4.601 55.224 ;
     RECT  3.971 40.992 4.669 41.4 ;
     RECT  4.453 43.488 4.669 43.752 ;
     RECT  4.492 52.992 4.693 53.544 ;
     RECT  4.693 52.944 4.78 53.544 ;
     RECT  4.204 61.872 4.796 61.896 ;
     RECT  2.704 38.688 4.837 38.712 ;
     RECT  4.565 0.144 4.849 3.288 ;
     RECT  3.881 57.072 4.849 57.576 ;
     RECT  4.669 43.488 4.853 43.992 ;
     RECT  4.669 40.464 4.883 41.4 ;
     RECT  4.796 61.872 4.883 62.616 ;
     RECT  4.525 30.72 4.889 30.744 ;
     RECT  4.837 38.688 4.924 39.096 ;
     RECT  2.704 31.872 5.069 31.896 ;
     RECT  4.988 24.864 5.075 24.888 ;
     RECT  4.849 57.072 5.101 58.008 ;
     RECT  3.089 32.976 5.177 33.096 ;
     RECT  4.883 61.872 5.177 61.896 ;
     RECT  4.849 0.144 5.209 3.336 ;
     RECT  4.381 51.792 5.209 51.816 ;
     RECT  5.209 0.144 5.219 3.912 ;
     RECT  3.347 26.88 5.249 26.904 ;
     RECT  5.209 51.312 5.249 51.816 ;
     RECT  4.924 38.688 5.281 38.712 ;
     RECT  2.704 23.856 5.285 23.88 ;
     RECT  4.883 41.088 5.285 41.4 ;
     RECT  5.219 0.144 5.315 0.504 ;
     RECT  4.259 4.944 5.317 11.448 ;
     RECT  4.097 12.48 5.317 22.2 ;
     RECT  5.219 1.728 5.389 3.912 ;
     RECT  4.957 29.52 5.389 29.544 ;
     RECT  5.281 38.448 5.389 38.712 ;
     RECT  5.177 33.072 5.425 33.096 ;
     RECT  5.317 4.944 5.429 22.2 ;
     RECT  5.315 0.144 5.507 0.456 ;
     RECT  5.507 0.144 5.633 0.168 ;
     RECT  5.101 56.976 5.641 58.008 ;
     RECT  4.597 59.184 5.641 60.168 ;
     RECT  5.633 0.096 5.717 0.168 ;
     RECT  5.389 1.728 5.749 3.96 ;
     RECT  5.429 4.944 5.749 21.528 ;
     RECT  5.389 29.28 5.897 29.544 ;
     RECT  5.852 62.592 5.939 62.616 ;
     RECT  5.641 56.976 5.941 60.456 ;
     RECT  5.941 56.88 5.987 60.456 ;
     RECT  5.987 56.88 6.028 57.624 ;
     RECT  5.897 29.28 6.073 29.496 ;
     RECT  4.837 64.656 6.179 64.68 ;
     RECT  6.073 28.416 6.253 29.496 ;
     RECT  6.253 28.272 6.361 29.496 ;
     RECT  5.749 1.728 6.373 21.528 ;
     RECT  5.965 23.328 6.469 23.352 ;
     RECT  6.361 27.312 6.473 29.496 ;
     RECT  4.78 52.992 6.541 53.544 ;
     RECT  6.181 47.52 6.613 47.544 ;
     RECT  5.425 33.072 6.685 33.288 ;
     RECT  5.717 0.144 6.709 0.168 ;
     RECT  5.533 31.776 6.716 31.8 ;
     RECT  6.685 33.072 6.716 33.768 ;
     RECT  6.469 23.328 6.721 23.688 ;
     RECT  6.373 1.728 6.725 19.032 ;
     RECT  5.249 51.312 6.757 51.336 ;
     RECT  6.709 0.144 6.785 0.216 ;
     RECT  6.757 51.312 6.793 51.384 ;
     RECT  6.541 52.992 6.793 53.832 ;
     RECT  6.785 0.096 6.829 0.216 ;
     RECT  6.685 37.056 6.829 37.08 ;
     RECT  4.853 43.536 6.829 43.992 ;
     RECT  6.613 46.752 6.829 47.544 ;
     RECT  6.829 0.096 6.889 0.264 ;
     RECT  6.793 30.768 6.893 30.792 ;
     RECT  3.521 50.16 6.937 50.328 ;
     RECT  6.793 51.312 6.937 53.832 ;
     RECT  6.937 50.16 6.973 53.832 ;
     RECT  6.889 0.144 6.995 0.264 ;
     RECT  6.995 0.192 6.997 0.264 ;
     RECT  5.285 41.088 7.009 41.112 ;
     RECT  6.997 0.192 7.091 0.312 ;
     RECT  6.893 30.672 7.117 30.792 ;
     RECT  6.716 31.776 7.117 33.768 ;
     RECT  6.829 43.536 7.189 44.472 ;
     RECT  7.045 62.64 7.234 62.664 ;
     RECT  6.973 50.16 7.261 54.168 ;
     RECT  5.389 38.304 7.297 38.712 ;
     RECT  7.234 62.64 7.331 62.76 ;
     RECT  6.373 20.016 7.369 21.528 ;
     RECT  6.721 22.704 7.369 23.688 ;
     RECT  6.473 29.28 7.369 29.496 ;
     RECT  7.117 30.672 7.369 33.768 ;
     RECT  6.725 2.256 7.405 19.032 ;
     RECT  7.369 20.016 7.405 23.688 ;
     RECT  7.369 29.28 7.429 34.344 ;
     RECT  7.189 43.536 7.477 45.192 ;
     RECT  7.405 2.256 7.808 23.688 ;
     RECT  7.585 25.2 7.808 25.224 ;
     RECT  7.261 26.256 7.808 26.28 ;
     RECT  6.473 27.312 7.808 28.296 ;
     RECT  7.429 29.28 7.808 34.776 ;
     RECT  6.829 36.336 7.808 37.08 ;
     RECT  7.297 38.304 7.808 38.76 ;
     RECT  7.009 40.56 7.808 41.112 ;
     RECT  7.477 42.72 7.808 45.192 ;
     RECT  6.829 46.752 7.808 47.736 ;
     RECT  7.261 50.16 7.808 54.408 ;
     RECT  6.028 57.168 7.808 57.624 ;
     RECT  5.987 58.656 7.808 60.456 ;
     RECT  7.331 62.64 7.808 62.664 ;
     RECT  7.091 0.288 8.053 0.312 ;
     RECT  7.808 2.148 8.104 62.664 ;
     RECT  8.104 25.2 8.129 26.28 ;
     RECT  8.053 0.144 8.197 0.312 ;
     RECT  8.104 43.536 8.201 45.192 ;
     RECT  8.104 2.148 8.225 21.72 ;
     RECT  8.104 38.64 8.273 38.76 ;
     RECT  8.197 0.144 8.3 0.36 ;
     RECT  8.225 1.728 8.3 21.72 ;
     RECT  8.104 57.168 8.377 62.664 ;
     RECT  8.3 0.144 8.387 21.72 ;
     RECT  8.273 38.736 8.417 38.76 ;
     RECT  8.377 57.168 8.525 63.288 ;
     RECT  8.387 0.144 8.579 0.36 ;
     RECT  8.104 40.848 8.633 41.832 ;
     RECT  8.104 36.528 8.705 36.84 ;
     RECT  8.579 0.144 8.723 0.312 ;
     RECT  8.104 50.16 8.813 55.464 ;
     RECT  8.813 50.16 8.921 55.32 ;
     RECT  8.104 28.128 9.137 34.248 ;
     RECT  8.104 23.664 9.169 23.688 ;
     RECT  8.633 41.664 9.173 41.832 ;
     RECT  8.921 50.16 9.173 55.176 ;
     RECT  8.387 1.728 9.203 21.72 ;
     RECT  9.169 23.664 9.205 23.88 ;
     RECT  8.129 25.824 9.209 26.28 ;
     RECT  9.203 2.256 9.212 21.72 ;
     RECT  9.205 23.088 9.212 23.88 ;
     RECT  9.173 50.16 9.241 54.12 ;
     RECT  8.525 61.2 9.251 63.288 ;
     RECT  9.212 2.256 9.299 23.88 ;
     RECT  9.241 50.112 9.353 54.12 ;
     RECT  9.173 41.664 9.389 41.784 ;
     RECT  8.705 36.528 9.421 36.552 ;
     RECT  9.349 46.848 9.421 46.872 ;
     RECT  9.389 41.664 9.425 41.688 ;
     RECT  8.201 43.536 9.445 45.048 ;
     RECT  9.299 23.088 9.461 23.88 ;
     RECT  9.421 46.752 9.461 46.872 ;
     RECT  9.353 52.752 9.461 54.12 ;
     RECT  9.461 46.752 9.533 46.776 ;
     RECT  9.445 43.296 9.605 45.528 ;
     RECT  9.251 61.2 9.637 62.76 ;
     RECT  9.137 34.224 9.713 34.248 ;
     RECT  8.723 0.144 9.781 0.264 ;
     RECT  9.637 60.816 9.827 62.76 ;
     RECT  8.104 48.576 9.961 48.6 ;
     RECT  9.137 28.128 9.965 33.096 ;
     RECT  9.109 64.656 10.001 64.68 ;
     RECT  8.525 57.168 10.021 59.64 ;
     RECT  9.827 60.816 10.021 62.664 ;
     RECT  9.965 28.128 10.177 29.304 ;
     RECT  9.961 48.576 10.177 48.648 ;
     RECT  9.173 55.104 10.177 55.176 ;
     RECT  9.421 35.856 10.249 36.552 ;
     RECT  9.781 0.096 10.261 0.264 ;
     RECT  10.177 55.104 10.285 55.752 ;
     RECT  10.021 57.168 10.285 62.664 ;
     RECT  9.605 43.536 10.289 45.528 ;
     RECT  10.249 35.856 10.325 36.6 ;
     RECT  10.285 55.104 10.325 62.664 ;
     RECT  9.299 2.256 10.361 21.672 ;
     RECT  9.965 30.432 10.361 33.096 ;
     RECT  9.353 50.112 10.501 51.768 ;
     RECT  9.461 52.752 10.501 53.976 ;
     RECT  10.325 55.152 10.547 62.664 ;
     RECT  10.177 48.576 10.577 48.696 ;
     RECT  10.361 2.256 10.597 20.376 ;
     RECT  10.547 55.152 10.613 62.568 ;
     RECT  10.361 21.456 10.645 21.672 ;
     RECT  9.461 23.088 10.645 23.832 ;
     RECT  10.361 30.528 10.681 33.096 ;
     RECT  10.597 2.208 10.685 20.376 ;
     RECT  10.261 0.096 10.837 0.312 ;
     RECT  10.177 41.616 10.897 41.64 ;
     RECT  10.289 43.536 10.901 45.432 ;
     RECT  10.837 0.096 10.933 0.408 ;
     RECT  10.681 30.528 10.937 33.288 ;
     RECT  10.645 21.456 10.973 23.832 ;
     RECT  10.577 48.624 11.005 48.696 ;
     RECT  10.885 64.608 11.074 64.632 ;
     RECT  10.933 0.096 11.075 1.272 ;
     RECT  10.937 31.2 11.077 33.288 ;
     RECT  10.897 41.616 11.113 41.688 ;
     RECT  10.325 35.952 11.149 36.6 ;
     RECT  10.501 37.68 11.149 37.704 ;
     RECT  9.209 25.824 11.153 25.848 ;
     RECT  11.149 35.952 11.153 37.704 ;
     RECT  11.075 0.096 11.219 1.176 ;
     RECT  10.177 27.888 11.293 29.304 ;
     RECT  10.501 50.112 11.293 53.976 ;
     RECT  10.613 55.152 11.293 62.376 ;
     RECT  10.685 2.256 11.315 20.376 ;
     RECT  11.074 64.56 11.315 64.68 ;
     RECT  11.293 50.112 11.333 62.376 ;
     RECT  11.315 64.656 11.363 64.68 ;
     RECT  11.113 41.616 11.365 42.168 ;
     RECT  11.365 40.944 11.369 42.168 ;
     RECT  10.789 46.464 11.405 46.488 ;
     RECT  11.293 27.072 11.411 29.304 ;
     RECT  11.153 35.952 11.413 36.792 ;
     RECT  11.149 34.752 11.437 34.776 ;
     RECT  11.413 35.856 11.437 36.792 ;
     RECT  11.005 48.624 11.441 48.792 ;
     RECT  11.333 62.16 11.441 62.376 ;
     RECT  11.437 34.752 11.5 36.792 ;
     RECT  11.315 3.984 11.545 20.376 ;
     RECT  10.973 21.456 11.545 23.112 ;
     RECT  11.369 40.944 11.585 41.688 ;
     RECT  11.441 48.624 11.585 48.648 ;
     RECT  11.585 41.616 11.693 41.688 ;
     RECT  11.545 3.984 11.729 23.112 ;
     RECT  11.693 41.664 11.765 41.688 ;
     RECT  11.5 34.752 11.843 35.352 ;
     RECT  11.411 28.56 11.869 29.304 ;
     RECT  11.333 50.112 11.945 61.08 ;
     RECT  11.411 27.072 12.013 27.336 ;
     RECT  11.945 50.112 12.017 60.84 ;
     RECT  11.077 31.2 12.037 33.384 ;
     RECT  11.219 0.096 12.083 0.216 ;
     RECT  11.869 28.56 12.157 29.976 ;
     RECT  12.037 30.96 12.157 33.384 ;
     RECT  11.729 23.088 12.229 23.112 ;
     RECT  12.229 23.088 12.265 23.352 ;
     RECT  12.085 24.48 12.265 24.504 ;
     RECT  12.265 23.088 12.301 24.504 ;
     RECT  12.013 62.592 12.373 62.664 ;
     RECT  12.157 28.56 12.409 33.384 ;
     RECT  12.083 0.096 12.419 0.168 ;
     RECT  12.301 23.088 12.445 25.08 ;
     RECT  10.901 43.536 12.481 44.184 ;
     RECT  12.445 23.088 12.517 25.416 ;
     RECT  12.373 62.592 12.611 63.288 ;
     RECT  12.517 23.088 12.625 25.464 ;
     RECT  12.611 62.592 12.661 62.664 ;
     RECT  12.565 1.152 12.707 1.176 ;
     RECT  12.013 26.832 12.733 27.336 ;
     RECT  12.661 62.304 12.757 62.664 ;
     RECT  12.481 42.768 12.769 44.184 ;
     RECT  12.733 26.736 13.021 27.336 ;
     RECT  12.409 28.56 13.021 33.624 ;
     RECT  12.419 0.144 13.093 0.168 ;
     RECT  11.729 3.984 13.093 21.576 ;
     RECT  12.769 42.192 13.093 44.184 ;
     RECT  10.901 45.168 13.093 45.432 ;
     RECT  12.985 49.056 13.093 49.08 ;
     RECT  12.017 50.16 13.093 60.84 ;
     RECT  11.315 2.256 13.141 3 ;
     RECT  12.625 23.088 13.165 25.512 ;
     RECT  13.141 1.968 13.208 3 ;
     RECT  13.093 3.984 13.208 21.72 ;
     RECT  13.165 23.088 13.208 25.56 ;
     RECT  13.021 26.736 13.208 33.624 ;
     RECT  11.843 35.328 13.208 35.352 ;
     RECT  11.5 36.528 13.208 36.792 ;
     RECT  13.093 42.192 13.208 45.576 ;
     RECT  13.093 49.056 13.208 60.84 ;
     RECT  12.757 62.16 13.208 62.664 ;
     RECT  13.093 0.144 13.429 0.216 ;
     RECT  13.208 1.968 13.504 62.664 ;
     RECT  13.504 1.968 13.715 33.768 ;
     RECT  13.504 48.96 13.925 62.664 ;
     RECT  13.925 60.96 13.957 62.664 ;
     RECT  13.429 0.096 14.005 0.216 ;
     RECT  13.504 47.424 14.195 47.448 ;
     RECT  14.005 0.096 14.197 0.264 ;
     RECT  13.504 35.712 14.243 36.6 ;
     RECT  13.504 43.824 14.243 46.2 ;
     RECT  13.957 60.96 14.243 62.76 ;
     RECT  14.243 60.96 14.249 62.424 ;
     RECT  14.243 43.824 14.284 45 ;
     RECT  14.209 63.84 14.339 63.864 ;
     RECT  13.715 2.256 14.387 33.768 ;
     RECT  13.504 42.192 14.393 42.792 ;
     RECT  14.249 60.96 14.645 60.984 ;
     RECT  14.249 62.16 14.681 62.424 ;
     RECT  14.284 43.824 14.753 44.952 ;
     RECT  14.681 62.208 14.753 62.424 ;
     RECT  14.197 0.096 14.773 0.312 ;
     RECT  14.243 46.176 14.821 46.2 ;
     RECT  13.925 48.96 14.821 59.64 ;
     RECT  14.753 62.4 14.825 62.424 ;
     RECT  14.773 0.096 14.869 0.36 ;
     RECT  14.387 2.736 14.897 33.768 ;
     RECT  14.897 2.736 14.915 25.032 ;
     RECT  14.915 2.832 14.963 25.032 ;
     RECT  14.963 3.312 14.969 25.032 ;
     RECT  14.897 26.304 14.969 33.768 ;
     RECT  14.821 48.768 15.037 59.64 ;
     RECT  14.393 42.192 15.041 42.456 ;
     RECT  14.969 26.4 15.113 33.768 ;
     RECT  15.113 26.736 15.185 33.768 ;
     RECT  15.037 48.768 15.185 60.456 ;
     RECT  14.969 3.408 15.257 25.032 ;
     RECT  15.185 48.768 15.257 54.408 ;
     RECT  14.753 44.352 15.289 44.952 ;
     RECT  14.821 46.176 15.289 46.344 ;
     RECT  15.257 3.408 15.329 24.984 ;
     RECT  15.289 44.352 15.433 46.344 ;
     RECT  15.433 44.352 15.443 46.728 ;
     RECT  15.443 46.224 15.445 46.728 ;
     RECT  15.445 46.224 15.484 47.112 ;
     RECT  15.185 55.44 15.613 60.456 ;
     RECT  14.869 0.096 15.635 0.6 ;
     RECT  15.361 39.744 15.721 39.768 ;
     RECT  15.635 0.096 15.731 0.216 ;
     RECT  15.257 54.384 15.761 54.408 ;
     RECT  15.329 8.496 15.833 24.984 ;
     RECT  15.721 38.784 15.833 39.768 ;
     RECT  15.577 62.64 15.874 62.664 ;
     RECT  15.041 42.432 15.901 42.456 ;
     RECT  15.613 55.44 15.941 60.984 ;
     RECT  15.833 10.464 15.971 24.984 ;
     RECT  15.874 62.64 15.971 62.76 ;
     RECT  15.941 55.44 16.013 57.864 ;
     RECT  16.021 62.16 16.108 62.232 ;
     RECT  15.185 26.736 16.153 33.672 ;
     RECT  14.243 35.712 16.157 36.552 ;
     RECT  15.443 44.352 16.163 44.712 ;
     RECT  15.329 3.408 16.201 7.512 ;
     RECT  16.108 62.208 16.265 62.232 ;
     RECT  16.201 3.408 16.309 3.912 ;
     RECT  15.257 48.768 16.333 53.4 ;
     RECT  16.201 4.944 16.337 7.512 ;
     RECT  16.153 26.208 16.441 33.672 ;
     RECT  16.189 34.704 16.441 34.728 ;
     RECT  16.013 55.44 16.441 55.704 ;
     RECT  15.833 39.504 16.481 39.768 ;
     RECT  16.309 2.88 16.621 3.912 ;
     RECT  16.337 4.992 16.729 7.512 ;
     RECT  15.833 8.496 16.729 9.192 ;
     RECT  15.971 13.872 16.765 24.984 ;
     RECT  15.731 0.096 16.789 0.168 ;
     RECT  16.729 4.992 16.981 9.192 ;
     RECT  15.971 10.464 16.981 12.888 ;
     RECT  16.909 63.84 17.017 63.864 ;
     RECT  16.013 57.168 17.029 57.864 ;
     RECT  15.941 58.992 17.029 60.696 ;
     RECT  16.981 4.992 17.053 12.888 ;
     RECT  16.765 13.872 17.053 25.224 ;
     RECT  16.157 36.096 17.075 36.552 ;
     RECT  16.441 26.208 17.121 34.728 ;
     RECT  17.029 57.168 17.129 60.696 ;
     RECT  16.621 2.592 17.173 3.912 ;
     RECT  17.017 63.84 17.219 63.912 ;
     RECT  16.789 0.096 17.221 0.6 ;
     RECT  17.173 1.968 17.233 3.912 ;
     RECT  16.441 54.912 17.237 55.704 ;
     RECT  17.233 1.968 17.315 3.96 ;
     RECT  17.219 63.888 17.315 63.912 ;
     RECT  17.315 2.256 17.317 3.96 ;
     RECT  17.317 2.256 17.365 4.008 ;
     RECT  17.053 4.992 17.365 25.224 ;
     RECT  15.901 42.432 17.377 42.552 ;
     RECT  17.129 58.992 17.377 60.696 ;
     RECT  16.333 48.768 17.453 53.592 ;
     RECT  17.324 62.16 17.461 62.184 ;
     RECT  17.237 55.248 17.521 55.704 ;
     RECT  17.129 57.168 17.521 57.96 ;
     RECT  17.121 34.704 17.561 34.728 ;
     RECT  17.453 50.16 17.737 53.592 ;
     RECT  15.484 46.32 17.893 47.112 ;
     RECT  17.377 41.568 17.953 42.552 ;
     RECT  17.365 2.256 17.989 25.224 ;
     RECT  17.121 26.208 17.989 33.528 ;
     RECT  17.521 55.248 18.169 57.96 ;
     RECT  17.377 58.992 18.169 60.936 ;
     RECT  16.163 44.352 18.181 44.376 ;
     RECT  18.169 55.248 18.277 60.936 ;
     RECT  17.461 62.16 18.277 62.328 ;
     RECT  17.221 0.096 18.413 0.84 ;
     RECT  17.989 2.256 18.413 33.528 ;
     RECT  18.421 64.656 18.469 64.68 ;
     RECT  18.181 44.352 18.529 44.424 ;
     RECT  17.893 46.224 18.529 47.112 ;
     RECT  17.453 48.768 18.601 48.792 ;
     RECT  18.413 0.096 18.608 33.528 ;
     RECT  17.629 34.752 18.608 34.776 ;
     RECT  17.075 36.096 18.608 36.12 ;
     RECT  16.481 39.504 18.608 39.528 ;
     RECT  17.953 41.568 18.608 42.984 ;
     RECT  18.529 44.352 18.608 47.112 ;
     RECT  18.601 48.24 18.608 48.792 ;
     RECT  17.737 50.16 18.608 54.168 ;
     RECT  18.277 55.248 18.608 62.808 ;
     RECT  18.608 0.096 18.745 62.808 ;
     RECT  18.469 64.56 18.755 64.68 ;
     RECT  18.745 0.096 18.851 63.288 ;
     RECT  18.851 0.096 18.904 62.76 ;
     RECT  18.904 42.432 18.965 48.792 ;
     RECT  18.965 44.4 19.043 48.792 ;
     RECT  18.904 0.096 19.073 2.76 ;
     RECT  18.755 64.656 19.073 64.68 ;
     RECT  19.043 44.4 19.181 47.16 ;
     RECT  18.904 55.68 19.181 62.76 ;
     RECT  18.904 3.984 19.325 26.904 ;
     RECT  18.904 36.096 19.325 37.56 ;
     RECT  19.181 55.68 19.361 62.232 ;
     RECT  19.325 3.984 19.397 26.664 ;
     RECT  19.361 58.896 19.397 62.232 ;
     RECT  19.397 4.464 19.469 26.664 ;
     RECT  19.397 58.896 19.469 61.416 ;
     RECT  19.469 58.992 19.505 61.416 ;
     RECT  19.469 4.464 19.541 26.52 ;
     RECT  18.904 27.888 19.541 29.304 ;
     RECT  19.181 44.4 19.577 45.192 ;
     RECT  19.073 2.496 19.649 2.76 ;
     RECT  19.361 55.68 19.667 57.864 ;
     RECT  19.043 48.24 19.721 48.792 ;
     RECT  18.904 39.504 19.811 39.528 ;
     RECT  18.904 30.528 19.868 34.776 ;
     RECT  19.181 46.224 19.937 47.16 ;
     RECT  18.904 50.16 19.937 54.696 ;
     RECT  19.868 30.528 19.955 35.112 ;
     RECT  19.325 36.192 19.955 37.56 ;
     RECT  19.541 29.04 19.969 29.304 ;
     RECT  19.955 30.528 19.969 34.2 ;
     RECT  19.073 0.096 20.045 0.84 ;
     RECT  19.541 27.888 20.045 27.912 ;
     RECT  19.969 29.04 20.369 34.2 ;
     RECT  19.541 4.992 20.437 26.52 ;
     RECT  20.437 4.992 20.509 26.616 ;
     RECT  19.667 56.304 20.513 57.864 ;
     RECT  19.721 48.768 20.545 48.792 ;
     RECT  20.513 56.4 20.579 57.864 ;
     RECT  20.545 48.768 20.585 48.984 ;
     RECT  19.955 37.008 20.617 37.56 ;
     RECT  18.965 42.432 20.639 43.032 ;
     RECT  20.045 0.144 20.693 0.84 ;
     RECT  20.639 42.192 20.723 43.032 ;
     RECT  20.509 4.992 20.729 27.24 ;
     RECT  20.693 0.192 20.765 0.84 ;
     RECT  20.729 4.992 20.909 26.52 ;
     RECT  20.579 56.88 20.909 57.864 ;
     RECT  20.765 0.24 20.981 0.84 ;
     RECT  20.617 37.008 20.981 37.992 ;
     RECT  19.649 2.496 21.049 2.664 ;
     RECT  20.981 37.344 21.049 37.992 ;
     RECT  19.937 54.672 21.053 54.696 ;
     RECT  20.981 0.336 21.233 0.84 ;
     RECT  20.485 40.416 21.269 40.44 ;
     RECT  19.505 59.328 21.341 61.416 ;
     RECT  20.369 29.04 21.373 33.576 ;
     RECT  20.585 48.912 21.377 48.984 ;
     RECT  20.245 63.216 21.397 63.24 ;
     RECT  19.577 44.4 21.404 44.424 ;
     RECT  21.049 2.496 21.413 3.432 ;
     RECT  20.545 35.856 21.449 35.88 ;
     RECT  21.404 43.776 21.491 44.424 ;
     RECT  21.373 28.992 21.521 33.576 ;
     RECT  21.341 59.328 21.541 60.504 ;
     RECT  20.723 42.192 21.557 42.792 ;
     RECT  21.541 58.656 21.628 60.504 ;
     RECT  21.397 62.352 21.661 63.24 ;
     RECT  21.233 0.336 21.665 0.36 ;
     RECT  21.661 62.352 21.665 63.288 ;
     RECT  21.491 44.064 21.701 44.424 ;
     RECT  21.049 37.344 21.773 38.52 ;
     RECT  21.701 44.352 21.809 44.424 ;
     RECT  21.521 29.664 21.845 33.576 ;
     RECT  21.628 59.136 21.917 60.504 ;
     RECT  20.909 20.112 22.057 26.52 ;
     RECT  20.909 56.88 22.129 57.48 ;
     RECT  20.909 4.992 22.165 19.128 ;
     RECT  21.517 36.336 22.165 36.36 ;
     RECT  21.773 37.344 22.165 37.992 ;
     RECT  19.937 50.16 22.165 53.592 ;
     RECT  22.129 56.88 22.273 57.576 ;
     RECT  22.273 56.448 22.317 57.576 ;
     RECT  21.665 63.264 22.345 63.288 ;
     RECT  22.317 56.448 22.357 57.624 ;
     RECT  21.413 3.408 22.381 3.432 ;
     RECT  22.165 36.336 22.385 37.992 ;
     RECT  22.213 54.624 22.412 54.648 ;
     RECT  22.385 36.336 22.417 37.512 ;
     RECT  22.165 50.16 22.421 53.64 ;
     RECT  22.357 55.824 22.457 57.624 ;
     RECT  21.845 30.336 22.493 33.576 ;
     RECT  22.412 54.624 22.499 54.84 ;
     RECT  22.345 63.264 22.499 63.336 ;
     RECT  22.057 20.112 22.565 26.664 ;
     RECT  22.493 30.72 22.741 33.576 ;
     RECT  22.417 36.288 22.781 37.512 ;
     RECT  22.381 3.408 22.789 3.672 ;
     RECT  22.165 4.704 22.789 19.128 ;
     RECT  22.421 53.616 22.813 53.64 ;
     RECT  22.499 54.624 22.813 54.744 ;
     RECT  22.789 3.408 22.844 19.128 ;
     RECT  21.917 59.136 22.849 59.304 ;
     RECT  22.565 23.088 22.853 26.664 ;
     RECT  22.741 30.72 22.925 34.488 ;
     RECT  22.421 50.16 22.925 52.44 ;
     RECT  21.917 60.48 22.925 60.504 ;
     RECT  22.457 56.448 22.961 57.624 ;
     RECT  22.844 2.64 22.981 19.128 ;
     RECT  22.981 2.496 23.173 19.128 ;
     RECT  22.565 20.112 23.173 22.104 ;
     RECT  22.885 61.872 23.173 61.896 ;
     RECT  22.499 63.264 23.173 63.288 ;
     RECT  22.925 31.392 23.317 34.488 ;
     RECT  19.937 46.224 23.317 47.112 ;
     RECT  22.961 56.496 23.317 57.624 ;
     RECT  22.849 58.704 23.317 59.304 ;
     RECT  22.981 60.432 23.317 60.456 ;
     RECT  21.557 42.768 23.353 42.792 ;
     RECT  22.489 64.752 23.489 64.776 ;
     RECT  22.781 37.104 23.497 37.512 ;
     RECT  23.317 31.392 23.533 34.968 ;
     RECT  23.489 64.656 23.572 64.776 ;
     RECT  21.809 44.352 23.677 44.376 ;
     RECT  21.377 48.96 23.749 48.984 ;
     RECT  22.925 50.16 23.749 52.296 ;
     RECT  22.853 23.088 23.893 25.848 ;
     RECT  22.813 53.616 23.929 54.744 ;
     RECT  23.677 43.872 23.965 44.376 ;
     RECT  23.173 2.496 24.008 22.104 ;
     RECT  23.893 23.088 24.008 26.28 ;
     RECT  23.533 31.392 24.008 35.016 ;
     RECT  23.497 37.104 24.008 37.608 ;
     RECT  23.353 42.672 24.008 42.792 ;
     RECT  23.965 43.872 24.008 44.472 ;
     RECT  23.317 46.224 24.008 47.352 ;
     RECT  23.749 48.96 24.008 52.296 ;
     RECT  23.929 53.616 24.008 55.512 ;
     RECT  23.317 56.496 24.008 60.456 ;
     RECT  23.173 61.68 24.008 63.288 ;
     RECT  24.008 2.148 24.112 63.288 ;
     RECT  23.572 64.608 24.181 64.776 ;
     RECT  24.112 2.418 24.185 63.288 ;
     RECT  24.181 64.512 24.293 64.776 ;
     RECT  24.185 2.418 24.304 62.664 ;
     RECT  24.293 64.512 24.337 64.68 ;
     RECT  24.304 43.872 24.419 44.472 ;
     RECT  24.304 45.696 24.419 52.344 ;
     RECT  24.304 56.496 24.419 61.032 ;
     RECT  24.337 64.512 24.419 64.632 ;
     RECT  24.419 64.512 24.421 64.536 ;
     RECT  24.304 30.816 24.509 36.216 ;
     RECT  24.419 59.712 24.581 61.032 ;
     RECT  24.419 56.496 24.611 58.44 ;
     RECT  24.581 61.008 24.611 61.032 ;
     RECT  24.421 64.416 24.661 64.536 ;
     RECT  24.304 28.32 24.761 28.344 ;
     RECT  24.304 53.376 24.833 54.168 ;
     RECT  24.304 40.992 24.905 41.64 ;
     RECT  24.419 46.224 25.013 48.984 ;
     RECT  24.304 37.536 25.049 37.56 ;
     RECT  24.304 2.496 25.121 27.144 ;
     RECT  24.905 41.616 25.157 41.64 ;
     RECT  24.661 63.792 25.187 64.536 ;
     RECT  24.304 62.16 25.397 62.664 ;
     RECT  25.121 2.496 25.437 26.808 ;
     RECT  25.437 2.496 25.445 2.952 ;
     RECT  24.419 44.448 25.477 44.472 ;
     RECT  25.397 62.16 25.481 63.24 ;
     RECT  25.477 44.448 25.517 45 ;
     RECT  24.509 30.816 25.549 33.096 ;
     RECT  24.509 34.512 25.549 36.216 ;
     RECT  25.505 64.608 25.549 64.632 ;
     RECT  24.419 50.16 25.585 52.344 ;
     RECT  25.437 3.984 25.667 26.808 ;
     RECT  25.667 21.36 25.805 26.808 ;
     RECT  25.405 43.296 25.861 43.32 ;
     RECT  25.549 30.816 25.877 36.216 ;
     RECT  25.916 28.272 25.957 28.296 ;
     RECT  24.304 55.488 25.981 55.512 ;
     RECT  25.667 3.984 25.985 20.376 ;
     RECT  25.957 27.888 26.003 28.296 ;
     RECT  25.861 42.768 26.003 43.32 ;
     RECT  24.611 57.024 26.017 58.44 ;
     RECT  25.481 62.16 26.051 62.76 ;
     RECT  25.877 30.816 26.089 33.336 ;
     RECT  26.017 57.024 26.089 58.68 ;
     RECT  24.581 59.712 26.089 60.024 ;
     RECT  25.805 21.36 26.129 26.712 ;
     RECT  25.877 34.512 26.149 36.216 ;
     RECT  26.149 34.512 26.195 36.504 ;
     RECT  26.129 21.36 26.201 26.664 ;
     RECT  26.195 36.288 26.236 36.504 ;
     RECT  26.051 62.16 26.237 62.664 ;
     RECT  25.693 29.52 26.243 29.544 ;
     RECT  25.013 47.952 26.273 48.984 ;
     RECT  25.585 50.16 26.341 52.392 ;
     RECT  26.201 21.36 26.345 26.376 ;
     RECT  25.549 64.608 26.389 64.728 ;
     RECT  25.013 46.224 26.413 46.536 ;
     RECT  26.089 57.024 26.417 60.024 ;
     RECT  26.389 64.56 26.485 64.728 ;
     RECT  25.981 55.488 26.521 55.704 ;
     RECT  26.485 64.512 26.581 64.728 ;
     RECT  26.413 46.224 26.597 46.584 ;
     RECT  25.445 2.496 26.669 2.616 ;
     RECT  26.345 21.36 26.705 26.232 ;
     RECT  26.669 2.592 26.737 2.616 ;
     RECT  25.517 44.976 26.737 45 ;
     RECT  26.597 46.224 26.737 46.536 ;
     RECT  26.003 27.888 26.741 27.912 ;
     RECT  25.985 4.608 26.773 20.376 ;
     RECT  26.705 21.36 26.773 24.792 ;
     RECT  26.521 55.488 26.813 56.424 ;
     RECT  26.773 4.608 26.819 24.792 ;
     RECT  26.089 30.672 26.845 33.336 ;
     RECT  26.195 34.512 26.845 35.256 ;
     RECT  26.101 61.104 26.845 61.128 ;
     RECT  26.737 2.592 26.849 3.576 ;
     RECT  26.845 30.672 26.849 35.256 ;
     RECT  26.665 37.728 26.885 37.752 ;
     RECT  26.819 4.608 26.957 22.104 ;
     RECT  26.737 44.976 27.029 46.536 ;
     RECT  26.417 57.6 27.065 60.024 ;
     RECT  24.833 54.144 27.089 54.168 ;
     RECT  26.813 55.488 27.089 55.512 ;
     RECT  26.849 30.672 27.101 34.872 ;
     RECT  27.089 54.144 27.173 55.512 ;
     RECT  27.065 59.808 27.241 60.024 ;
     RECT  26.845 61.104 27.241 61.656 ;
     RECT  26.581 64.512 27.277 64.776 ;
     RECT  26.957 18.48 27.289 22.104 ;
     RECT  26.236 36.288 27.313 36.312 ;
     RECT  27.101 30.672 27.421 33.336 ;
     RECT  27.421 30.192 27.461 33.336 ;
     RECT  26.957 4.608 27.497 17.448 ;
     RECT  27.277 63.84 27.587 64.776 ;
     RECT  27.101 34.848 27.641 34.872 ;
     RECT  27.289 20.496 27.677 22.104 ;
     RECT  26.237 62.64 27.683 62.664 ;
     RECT  27.313 39.408 27.709 39.432 ;
     RECT  27.241 59.808 27.733 61.656 ;
     RECT  27.029 44.976 27.817 45.096 ;
     RECT  27.817 44.928 27.857 45.096 ;
     RECT  27.205 41.568 27.884 41.592 ;
     RECT  26.273 48.624 27.889 48.984 ;
     RECT  26.003 43.296 27.925 43.32 ;
     RECT  27.857 44.928 27.925 44.952 ;
     RECT  27.497 4.8 27.965 17.448 ;
     RECT  27.884 40.704 27.971 41.592 ;
     RECT  26.819 23.088 27.997 24.792 ;
     RECT  26.705 25.824 27.997 26.232 ;
     RECT  27.313 36.288 28.001 37.224 ;
     RECT  26.341 50.16 28.028 52.44 ;
     RECT  27.065 57.6 28.033 58.824 ;
     RECT  27.173 55.2 28.037 55.512 ;
     RECT  28.033 57.36 28.069 58.824 ;
     RECT  27.461 31.2 28.073 33.336 ;
     RECT  27.461 30.192 28.105 30.216 ;
     RECT  28.028 50.16 28.115 52.488 ;
     RECT  28.105 29.904 28.145 30.216 ;
     RECT  28.073 31.392 28.145 33.336 ;
     RECT  27.965 6.48 28.181 17.448 ;
     RECT  27.971 40.944 28.181 41.592 ;
     RECT  27.709 39.408 28.249 39.672 ;
     RECT  27.173 54.144 28.321 54.168 ;
     RECT  28.069 57.024 28.321 58.824 ;
     RECT  27.733 59.808 28.321 62.28 ;
     RECT  27.677 20.544 28.393 22.104 ;
     RECT  27.997 23.088 28.393 26.232 ;
     RECT  28.393 20.544 28.429 26.232 ;
     RECT  28.321 57.024 28.429 62.28 ;
     RECT  26.849 3.552 28.501 3.576 ;
     RECT  27.965 4.8 28.501 5.496 ;
     RECT  27.029 46.224 28.681 46.536 ;
     RECT  27.925 43.296 28.717 44.952 ;
     RECT  28.321 54.144 28.717 54.216 ;
     RECT  27.587 64.56 28.793 64.776 ;
     RECT  28.429 56.88 28.861 62.28 ;
     RECT  28.501 3.552 29.041 5.496 ;
     RECT  28.181 6.48 29.041 17.4 ;
     RECT  29.041 2.784 29.077 17.4 ;
     RECT  28.861 56.88 29.173 62.664 ;
     RECT  28.681 45.984 29.228 46.536 ;
     RECT  29.185 28.56 29.257 28.584 ;
     RECT  28.249 38.784 29.257 39.672 ;
     RECT  27.889 47.856 29.257 49.08 ;
     RECT  28.115 50.16 29.257 52.44 ;
     RECT  28.717 42.768 29.269 44.952 ;
     RECT  29.228 45.984 29.269 46.68 ;
     RECT  29.257 47.856 29.269 52.44 ;
     RECT  28.717 54.144 29.269 54.264 ;
     RECT  28.037 55.248 29.269 55.512 ;
     RECT  29.173 56.496 29.269 62.664 ;
     RECT  28.145 32.496 29.329 33.336 ;
     RECT  29.257 38.784 29.401 39.768 ;
     RECT  28.181 40.944 29.401 40.968 ;
     RECT  29.077 2.592 29.408 17.4 ;
     RECT  27.289 18.48 29.408 19.128 ;
     RECT  28.429 20.544 29.408 26.856 ;
     RECT  29.257 28.272 29.408 28.584 ;
     RECT  28.145 29.904 29.408 29.928 ;
     RECT  28.145 31.392 29.408 31.416 ;
     RECT  29.329 32.496 29.408 34.152 ;
     RECT  28.001 36.336 29.408 37.224 ;
     RECT  29.401 38.784 29.408 40.968 ;
     RECT  29.269 42.768 29.408 45 ;
     RECT  29.269 45.984 29.408 52.44 ;
     RECT  29.269 54.144 29.408 62.664 ;
     RECT  29.408 2.148 29.512 62.664 ;
     RECT  29.512 2.304 29.704 62.664 ;
     RECT  29.704 31.392 29.765 35.16 ;
     RECT  29.704 38.688 29.765 40.968 ;
     RECT  29.704 59.712 29.765 62.664 ;
     RECT  28.793 64.752 29.905 64.776 ;
     RECT  29.704 54.144 29.909 55.512 ;
     RECT  29.765 62.16 29.941 62.664 ;
     RECT  29.905 63.84 29.941 64.776 ;
     RECT  29.704 28.272 29.945 28.296 ;
     RECT  29.704 17.376 30.017 26.856 ;
     RECT  29.704 42.72 30.125 44.952 ;
     RECT  29.941 62.16 30.197 64.776 ;
     RECT  29.765 32.496 30.233 35.16 ;
     RECT  30.017 17.376 30.341 26.808 ;
     RECT  29.765 59.712 30.377 61.128 ;
     RECT  30.377 59.808 30.413 61.128 ;
     RECT  29.704 36.336 30.515 37.176 ;
     RECT  30.515 36.816 30.521 37.176 ;
     RECT  30.233 32.496 30.629 34.152 ;
     RECT  30.125 42.72 30.659 44.904 ;
     RECT  30.197 62.16 30.659 63.864 ;
     RECT  29.704 47.712 30.665 47.736 ;
     RECT  29.704 2.304 30.733 16.296 ;
     RECT  30.341 17.376 30.733 26.76 ;
     RECT  30.659 62.16 30.755 62.664 ;
     RECT  30.233 35.136 30.841 35.16 ;
     RECT  29.765 31.392 30.877 31.416 ;
     RECT  29.909 55.488 30.877 55.512 ;
     RECT  29.704 56.88 30.877 58.728 ;
     RECT  30.841 35.136 30.881 35.256 ;
     RECT  29.909 54.144 30.888 54.408 ;
     RECT  30.877 55.488 30.888 58.728 ;
     RECT  30.659 42.72 30.899 44.184 ;
     RECT  30.697 41.616 30.901 41.64 ;
     RECT  29.765 38.688 30.908 40.152 ;
     RECT  30.901 41.136 30.908 41.64 ;
     RECT  30.908 38.688 30.949 41.64 ;
     RECT  30.899 42.72 30.949 42.888 ;
     RECT  30.733 2.304 30.989 26.76 ;
     RECT  30.989 2.4 31.025 26.76 ;
     RECT  30.877 31.2 31.091 31.416 ;
     RECT  31.045 28.8 31.093 28.824 ;
     RECT  29.704 29.856 31.093 29.88 ;
     RECT  30.949 38.688 31.093 42.888 ;
     RECT  29.704 48.912 31.097 52.44 ;
     RECT  31.093 28.8 31.132 29.88 ;
     RECT  30.888 54.144 31.141 58.728 ;
     RECT  31.093 38.592 31.235 42.888 ;
     RECT  29.704 46.224 31.273 46.536 ;
     RECT  31.091 31.392 31.277 31.416 ;
     RECT  31.235 39.456 31.277 42.888 ;
     RECT  31.141 53.568 31.277 58.728 ;
     RECT  31.132 29.52 31.309 29.88 ;
     RECT  31.025 2.4 31.349 19.08 ;
     RECT  31.277 54.864 31.417 58.728 ;
     RECT  31.277 40.032 31.457 42.888 ;
     RECT  31.349 2.64 31.475 19.08 ;
     RECT  30.659 63.84 31.477 63.864 ;
     RECT  31.457 40.032 31.493 42.792 ;
     RECT  31.475 2.64 31.564 13.08 ;
     RECT  30.629 32.496 31.597 33.528 ;
     RECT  31.025 20.112 31.601 26.76 ;
     RECT  31.477 63.84 31.619 64.68 ;
     RECT  31.597 31.776 31.673 33.528 ;
     RECT  31.277 53.568 31.745 53.592 ;
     RECT  30.755 62.16 31.765 62.376 ;
     RECT  31.601 20.112 31.781 23.928 ;
     RECT  31.309 29.52 31.781 30.216 ;
     RECT  31.781 29.856 31.925 30.216 ;
     RECT  31.765 62.16 31.925 62.616 ;
     RECT  30.413 59.808 31.957 60.312 ;
     RECT  31.781 20.448 31.961 23.928 ;
     RECT  31.097 48.96 31.993 52.44 ;
     RECT  31.957 59.808 32.053 61.032 ;
     RECT  31.925 62.16 32.053 62.328 ;
     RECT  31.673 31.776 32.105 33.336 ;
     RECT  31.417 54.864 32.105 58.776 ;
     RECT  31.601 25.008 32.141 26.76 ;
     RECT  31.564 6.576 32.195 13.08 ;
     RECT  31.993 48.96 32.317 52.728 ;
     RECT  32.065 30.768 32.353 30.792 ;
     RECT  32.105 31.776 32.353 31.944 ;
     RECT  31.273 46.224 32.353 47.352 ;
     RECT  32.141 25.008 32.357 26.712 ;
     RECT  32.353 30.768 32.357 31.944 ;
     RECT  32.317 37.968 32.396 37.992 ;
     RECT  32.396 37.968 32.425 38.232 ;
     RECT  32.353 46.224 32.425 47.688 ;
     RECT  31.961 20.448 32.429 23.112 ;
     RECT  32.357 30.96 32.429 31.896 ;
     RECT  32.105 58.128 32.461 58.776 ;
     RECT  32.053 59.808 32.461 62.328 ;
     RECT  30.899 44.112 32.465 44.184 ;
     RECT  32.425 37.92 32.483 38.232 ;
     RECT  32.461 58.128 32.483 62.328 ;
     RECT  32.429 20.448 32.537 22.536 ;
     RECT  30.521 36.816 32.569 36.84 ;
     RECT  32.429 30.96 32.573 31.8 ;
     RECT  32.317 48.864 32.573 52.728 ;
     RECT  31.619 64.56 32.581 64.68 ;
     RECT  31.493 40.032 32.609 42.072 ;
     RECT  32.483 61.488 32.627 62.328 ;
     RECT  32.105 54.864 32.677 56.856 ;
     RECT  32.573 49.872 32.681 52.728 ;
     RECT  32.627 61.488 32.681 62.28 ;
     RECT  31.564 2.64 32.713 5.592 ;
     RECT  32.195 6.576 32.713 12.648 ;
     RECT  30.881 35.232 32.713 35.256 ;
     RECT  32.581 64.512 32.753 64.68 ;
     RECT  32.609 41.952 32.785 42.072 ;
     RECT  32.677 54.816 32.785 56.856 ;
     RECT  32.681 61.968 32.812 62.28 ;
     RECT  32.483 58.128 32.861 60.456 ;
     RECT  31.475 14.16 32.933 19.08 ;
     RECT  32.713 2.64 33.073 12.648 ;
     RECT  32.785 54.096 33.107 56.856 ;
     RECT  32.933 14.4 33.113 19.08 ;
     RECT  32.812 61.968 33.113 62.232 ;
     RECT  33.107 54.336 33.116 56.856 ;
     RECT  32.861 58.128 33.116 59.304 ;
     RECT  32.357 25.008 33.145 26.232 ;
     RECT  32.425 46.224 33.145 47.736 ;
     RECT  32.713 35.232 33.181 35.544 ;
     RECT  32.753 64.56 33.185 64.68 ;
     RECT  32.861 60.336 33.221 60.456 ;
     RECT  33.181 35.232 33.253 35.64 ;
     RECT  32.569 36.624 33.253 36.84 ;
     RECT  32.483 37.92 33.329 38.184 ;
     RECT  33.145 24.768 33.356 26.232 ;
     RECT  32.105 33.072 33.397 33.336 ;
     RECT  33.253 35.232 33.397 36.84 ;
     RECT  33.329 37.92 33.397 37.992 ;
     RECT  33.145 46.032 33.397 47.736 ;
     RECT  32.573 48.864 33.397 48.888 ;
     RECT  33.073 2.592 33.473 12.648 ;
     RECT  32.537 21.216 33.509 22.536 ;
     RECT  33.116 54.336 33.509 59.304 ;
     RECT  32.785 41.952 33.581 42.744 ;
     RECT  33.509 22.176 33.613 22.536 ;
     RECT  32.573 30.96 33.617 31.224 ;
     RECT  33.397 46.032 33.637 48.888 ;
     RECT  33.356 24.72 33.649 26.232 ;
     RECT  33.637 27.456 33.649 27.48 ;
     RECT  33.637 45.984 33.649 48.888 ;
     RECT  31.309 28.464 33.683 28.488 ;
     RECT  32.465 44.16 33.685 44.184 ;
     RECT  33.649 45.648 33.685 48.888 ;
     RECT  33.613 22.176 33.697 23.112 ;
     RECT  33.649 24.72 33.724 27.48 ;
     RECT  33.185 64.56 33.725 64.632 ;
     RECT  33.685 44.16 33.733 48.888 ;
     RECT  33.113 62.16 33.829 62.232 ;
     RECT  33.725 64.608 33.833 64.632 ;
     RECT  33.724 24.72 33.973 26.808 ;
     RECT  33.829 62.16 33.973 62.712 ;
     RECT  33.509 54.336 34.069 59.064 ;
     RECT  33.937 29.808 34.081 29.832 ;
     RECT  33.113 18.96 34.153 19.08 ;
     RECT  34.081 29.808 34.189 30.168 ;
     RECT  33.397 35.232 34.297 37.992 ;
     RECT  34.153 18.96 34.333 19.8 ;
     RECT  33.113 14.4 34.441 17.88 ;
     RECT  34.069 53.76 34.513 59.064 ;
     RECT  33.221 60.432 34.513 60.456 ;
     RECT  34.441 13.92 34.556 17.88 ;
     RECT  34.333 18.96 34.556 19.848 ;
     RECT  33.973 24.432 34.585 26.808 ;
     RECT  33.901 20.88 34.597 20.904 ;
     RECT  33.697 22.176 34.597 22.536 ;
     RECT  33.733 44.16 34.657 44.952 ;
     RECT  34.597 20.88 34.693 22.536 ;
     RECT  34.585 23.856 34.693 26.808 ;
     RECT  33.617 31.2 34.729 31.224 ;
     RECT  33.473 2.832 34.765 12.648 ;
     RECT  34.556 13.92 34.765 19.848 ;
     RECT  34.765 2.304 34.808 19.848 ;
     RECT  34.693 20.88 34.808 26.808 ;
     RECT  34.189 29.76 34.808 30.168 ;
     RECT  34.729 31.2 34.808 31.8 ;
     RECT  33.397 33.072 34.808 33.912 ;
     RECT  34.297 35.232 34.808 38.808 ;
     RECT  32.609 40.032 34.808 40.632 ;
     RECT  33.581 41.952 34.808 42.264 ;
     RECT  34.657 43.824 34.808 44.952 ;
     RECT  33.733 46.176 34.808 48.888 ;
     RECT  32.681 50.016 34.808 52.728 ;
     RECT  34.513 53.76 34.808 60.456 ;
     RECT  33.973 62.16 34.808 63.288 ;
     RECT  34.808 2.148 34.912 63.288 ;
     RECT  34.912 2.304 35.104 63.288 ;
     RECT  35.104 41.952 35.165 42.264 ;
     RECT  35.104 20.88 35.237 25.368 ;
     RECT  35.104 29.76 35.273 33.912 ;
     RECT  35.104 38.448 35.273 38.808 ;
     RECT  35.104 50.016 35.273 60.072 ;
     RECT  35.104 40.032 35.309 40.632 ;
     RECT  35.104 2.304 35.381 17.736 ;
     RECT  35.381 2.592 35.417 17.736 ;
     RECT  35.104 35.136 35.417 35.496 ;
     RECT  35.417 2.592 35.489 13.512 ;
     RECT  35.237 21.072 35.555 25.368 ;
     RECT  35.104 62.544 35.555 63.288 ;
     RECT  35.273 59.28 35.569 60.072 ;
     RECT  35.273 29.76 35.651 33.624 ;
     RECT  35.651 29.76 35.813 32.04 ;
     RECT  35.104 43.824 35.843 49.032 ;
     RECT  35.489 2.592 35.849 12.696 ;
     RECT  35.813 31.2 35.849 32.04 ;
     RECT  35.273 50.016 35.884 58.152 ;
     RECT  35.569 59.28 35.885 60.024 ;
     RECT  35.104 61.056 35.885 61.08 ;
     RECT  35.884 50.016 35.921 55.704 ;
     RECT  35.555 21.072 35.957 25.032 ;
     RECT  35.843 43.872 35.957 49.032 ;
     RECT  35.957 21.072 35.993 23.88 ;
     RECT  35.993 21.072 36.029 23.688 ;
     RECT  35.651 33.072 36.029 33.624 ;
     RECT  35.104 36.528 36.029 36.84 ;
     RECT  35.555 62.544 36.035 63.24 ;
     RECT  35.273 38.784 36.065 38.808 ;
     RECT  35.884 56.832 36.065 58.152 ;
     RECT  35.417 14.736 36.101 17.736 ;
     RECT  36.029 21.072 36.131 23.592 ;
     RECT  35.813 29.76 36.137 30.072 ;
     RECT  36.131 22.464 36.172 23.592 ;
     RECT  36.101 14.784 36.173 17.736 ;
     RECT  36.035 62.544 36.181 62.808 ;
     RECT  36.173 15.264 36.385 17.736 ;
     RECT  35.104 26.64 36.389 26.808 ;
     RECT  36.385 15.264 36.421 17.784 ;
     RECT  35.104 18.96 36.421 19.848 ;
     RECT  36.029 36.624 36.421 36.84 ;
     RECT  35.957 44.16 36.457 49.032 ;
     RECT  35.921 50.016 36.457 55.608 ;
     RECT  36.457 44.16 36.605 55.608 ;
     RECT  36.389 26.64 36.637 26.664 ;
     RECT  35.309 40.608 36.707 40.632 ;
     RECT  36.181 62.16 36.707 62.808 ;
     RECT  36.661 38.976 36.748 39.624 ;
     RECT  35.165 41.952 36.781 41.976 ;
     RECT  36.137 30.048 36.785 30.072 ;
     RECT  36.469 64.608 36.851 64.632 ;
     RECT  35.885 59.808 36.853 60.024 ;
     RECT  36.029 33.072 36.929 33.576 ;
     RECT  36.781 40.992 36.929 41.976 ;
     RECT  36.853 59.808 36.956 60.312 ;
     RECT  36.956 59.808 36.961 60.456 ;
     RECT  36.605 44.592 36.965 55.608 ;
     RECT  35.849 32.016 36.997 32.04 ;
     RECT  36.929 33.072 36.997 33.528 ;
     RECT  36.965 50.016 36.997 55.608 ;
     RECT  36.065 56.832 36.997 58.104 ;
     RECT  36.172 22.8 37.037 23.592 ;
     RECT  36.961 59.52 37.043 60.456 ;
     RECT  35.957 25.008 37.045 25.032 ;
     RECT  36.421 36.624 37.093 37.416 ;
     RECT  36.997 50.016 37.109 58.104 ;
     RECT  36.707 62.16 37.145 62.712 ;
     RECT  37.093 36.624 37.177 37.848 ;
     RECT  36.748 38.976 37.177 39 ;
     RECT  37.045 25.008 37.217 25.08 ;
     RECT  36.421 15.264 37.285 19.848 ;
     RECT  36.131 21.072 37.285 21.48 ;
     RECT  37.109 50.16 37.321 58.104 ;
     RECT  37.321 50.16 37.429 58.44 ;
     RECT  37.043 59.52 37.429 60.312 ;
     RECT  36.929 41.952 37.433 41.976 ;
     RECT  36.965 44.592 37.433 48.648 ;
     RECT  37.037 23.568 37.469 23.592 ;
     RECT  36.997 31.776 37.537 33.528 ;
     RECT  35.417 35.136 37.609 35.16 ;
     RECT  37.285 15.264 37.621 21.48 ;
     RECT  37.433 47.28 37.649 48.648 ;
     RECT  37.429 50.16 37.649 60.312 ;
     RECT  37.621 15.264 37.667 21.768 ;
     RECT  37.609 35.088 37.681 35.208 ;
     RECT  37.537 31.056 37.685 33.528 ;
     RECT  37.177 36.624 37.685 39 ;
     RECT  37.433 44.592 37.685 45.768 ;
     RECT  36.637 26.112 37.717 26.664 ;
     RECT  35.849 2.592 37.753 12.648 ;
     RECT  37.717 25.632 37.753 26.664 ;
     RECT  37.753 2.496 37.757 12.648 ;
     RECT  37.681 35.088 37.757 35.256 ;
     RECT  37.753 25.632 37.837 27.384 ;
     RECT  37.757 11.664 37.957 12.648 ;
     RECT  37.753 13.824 37.957 13.848 ;
     RECT  37.957 11.664 38.045 13.848 ;
     RECT  37.667 15.264 38.117 18.744 ;
     RECT  37.685 31.056 38.149 32.04 ;
     RECT  37.649 58.656 38.189 60.312 ;
     RECT  37.667 19.776 38.195 21.768 ;
     RECT  38.149 30.72 38.195 32.04 ;
     RECT  38.108 40.032 38.195 40.056 ;
     RECT  37.685 44.592 38.195 45.432 ;
     RECT  37.825 63.792 38.243 63.816 ;
     RECT  37.825 29.088 38.261 29.112 ;
     RECT  37.145 62.16 38.293 62.616 ;
     RECT  38.189 58.656 38.297 59.304 ;
     RECT  37.685 33.072 38.401 33.528 ;
     RECT  37.685 37.152 38.401 39 ;
     RECT  38.117 15.36 38.441 18.744 ;
     RECT  38.195 30.72 38.441 31.8 ;
     RECT  37.757 35.136 38.509 35.256 ;
     RECT  38.221 42.768 38.549 42.792 ;
     RECT  38.509 35.136 38.581 35.496 ;
     RECT  37.649 48.624 38.581 48.648 ;
     RECT  38.195 19.824 38.588 21.768 ;
     RECT  38.297 58.656 38.621 59.064 ;
     RECT  38.588 19.824 38.629 22.2 ;
     RECT  37.837 25.632 38.653 27.336 ;
     RECT  38.581 35.136 38.653 36.168 ;
     RECT  38.401 37.152 38.653 39.624 ;
     RECT  38.573 64.608 38.657 64.68 ;
     RECT  38.581 48.624 38.761 48.984 ;
     RECT  37.649 50.16 38.761 52.2 ;
     RECT  37.649 53.376 38.761 57.576 ;
     RECT  38.653 25.344 38.765 27.336 ;
     RECT  37.757 2.496 38.797 10.632 ;
     RECT  38.045 11.664 38.797 12.792 ;
     RECT  38.045 13.776 38.797 13.848 ;
     RECT  38.195 44.592 38.833 44.616 ;
     RECT  38.761 50.16 38.841 57.576 ;
     RECT  38.621 58.656 38.841 58.68 ;
     RECT  38.833 44.448 38.873 44.616 ;
     RECT  38.189 60.288 38.909 60.312 ;
     RECT  38.657 64.608 38.909 64.632 ;
     RECT  38.765 25.344 38.941 27.096 ;
     RECT  37.649 47.28 38.941 47.304 ;
     RECT  38.797 2.496 39.013 12.792 ;
     RECT  38.797 13.776 39.013 14.232 ;
     RECT  38.761 41.76 39.013 41.784 ;
     RECT  38.653 35.136 39.196 39.624 ;
     RECT  39.013 2.496 39.233 14.232 ;
     RECT  38.629 19.824 39.337 22.68 ;
     RECT  38.761 48.48 39.337 48.984 ;
     RECT  38.841 50.16 39.337 58.68 ;
     RECT  38.873 44.448 39.397 44.472 ;
     RECT  39.013 41.616 39.445 41.784 ;
     RECT  39.337 19.824 39.481 22.776 ;
     RECT  39.481 19.776 39.625 22.776 ;
     RECT  39.445 41.616 39.661 42.36 ;
     RECT  38.293 62.16 39.697 62.712 ;
     RECT  39.697 62.16 39.733 63.288 ;
     RECT  38.441 30.768 39.781 31.8 ;
     RECT  39.337 48.48 39.829 58.68 ;
     RECT  39.337 59.808 39.829 59.832 ;
     RECT  39.661 41.616 39.877 42.792 ;
     RECT  39.397 43.824 39.877 44.472 ;
     RECT  39.829 48.48 39.877 59.832 ;
     RECT  38.941 47.28 39.949 47.496 ;
     RECT  39.733 61.536 39.973 63.288 ;
     RECT  39.973 61.44 40.069 63.288 ;
     RECT  39.973 64.608 40.069 64.632 ;
     RECT  38.441 15.552 40.129 18.744 ;
     RECT  39.625 19.776 40.129 22.824 ;
     RECT  40.069 64.512 40.163 64.632 ;
     RECT  39.233 2.496 40.208 13.848 ;
     RECT  40.129 15.552 40.208 22.824 ;
     RECT  38.941 24.672 40.208 27.096 ;
     RECT  39.781 30.72 40.208 31.8 ;
     RECT  38.401 33.072 40.208 34.008 ;
     RECT  39.196 35.136 40.208 35.736 ;
     RECT  39.196 36.72 40.208 39.624 ;
     RECT  39.877 41.616 40.208 44.472 ;
     RECT  39.356 45.552 40.208 45.576 ;
     RECT  39.949 47.04 40.208 47.496 ;
     RECT  39.877 48.48 40.208 60.072 ;
     RECT  40.069 61.2 40.208 63.288 ;
     RECT  40.208 2.148 40.259 63.288 ;
     RECT  40.259 2.148 40.312 62.904 ;
     RECT  40.163 64.512 40.355 64.536 ;
     RECT  40.312 2.304 40.504 62.904 ;
     RECT  40.504 18.384 40.565 22.584 ;
     RECT  40.504 24.672 40.565 26.856 ;
     RECT  40.504 30.864 40.565 31.176 ;
     RECT  40.504 11.712 40.601 13.08 ;
     RECT  40.504 47.04 40.601 58.68 ;
     RECT  40.565 25.536 40.709 26.856 ;
     RECT  40.565 18.384 40.817 18.552 ;
     RECT  40.601 48.384 40.925 58.68 ;
     RECT  40.504 59.808 40.925 62.904 ;
     RECT  40.925 59.808 40.961 62.712 ;
     RECT  40.709 25.536 40.997 26.808 ;
     RECT  40.961 59.808 41.033 62.568 ;
     RECT  40.565 19.776 41.249 22.584 ;
     RECT  41.249 19.776 41.285 20.376 ;
     RECT  40.817 18.384 41.321 18.408 ;
     RECT  40.504 45.504 41.321 45.672 ;
     RECT  40.601 47.04 41.321 47.064 ;
     RECT  40.925 48.384 41.321 58.152 ;
     RECT  41.033 59.808 41.357 62.28 ;
     RECT  41.285 19.776 41.429 20.328 ;
     RECT  41.357 59.808 41.497 61.56 ;
     RECT  40.601 11.712 41.564 11.736 ;
     RECT  40.601 12.768 41.564 13.08 ;
     RECT  40.504 35.136 41.605 36.408 ;
     RECT  40.504 38.4 41.605 39 ;
     RECT  40.504 42.144 41.605 42.168 ;
     RECT  40.504 44.4 41.605 44.472 ;
     RECT  41.497 59.28 41.645 61.56 ;
     RECT  41.564 11.712 41.651 13.08 ;
     RECT  41.605 42.144 41.689 44.472 ;
     RECT  41.689 43.248 41.692 44.472 ;
     RECT  41.651 11.712 41.789 11.736 ;
     RECT  40.504 16.56 41.893 16.584 ;
     RECT  41.645 61.536 41.897 61.56 ;
     RECT  41.689 42.144 41.929 42.168 ;
     RECT  41.249 21.552 41.933 22.584 ;
     RECT  41.605 35.136 41.957 39 ;
     RECT  41.929 41.616 41.969 42.168 ;
     RECT  41.645 59.28 41.969 60.072 ;
     RECT  41.893 16.32 42.001 16.584 ;
     RECT  41.321 48.384 42.005 53.4 ;
     RECT  40.565 30.864 42.037 31.128 ;
     RECT  41.321 45.648 42.037 45.672 ;
     RECT  41.957 35.136 42.041 39.384 ;
     RECT  42.041 35.136 42.077 39.336 ;
     RECT  41.933 21.552 42.113 22.536 ;
     RECT  42.037 45.648 42.121 46.776 ;
     RECT  42.037 30.864 42.145 31.272 ;
     RECT  41.321 54.624 42.148 58.152 ;
     RECT  42.005 48.432 42.221 53.4 ;
     RECT  40.504 2.304 42.253 10.632 ;
     RECT  41.429 19.824 42.361 20.328 ;
     RECT  40.997 26.208 42.361 26.808 ;
     RECT  42.361 26.112 42.421 26.808 ;
     RECT  42.361 19.824 42.433 20.376 ;
     RECT  42.145 29.76 42.433 31.272 ;
     RECT  42.121 45.648 42.437 46.536 ;
     RECT  42.253 2.304 42.473 10.68 ;
     RECT  41.692 43.248 42.473 43.368 ;
     RECT  42.148 54.624 42.473 58.2 ;
     RECT  42.421 26.112 42.509 26.856 ;
     RECT  42.001 16.32 42.689 16.68 ;
     RECT  42.473 56.784 42.721 58.2 ;
     RECT  42.433 19.824 42.757 20.424 ;
     RECT  42.509 26.112 42.757 26.808 ;
     RECT  42.473 43.344 42.757 43.368 ;
     RECT  42.473 2.304 42.761 10.44 ;
     RECT  42.757 25.392 42.793 26.808 ;
     RECT  42.721 56.784 42.793 58.296 ;
     RECT  42.113 21.552 42.833 22.488 ;
     RECT  42.077 38.16 42.833 39.336 ;
     RECT  42.757 19.632 42.869 20.424 ;
     RECT  42.577 14.16 42.905 14.184 ;
     RECT  42.829 11.76 42.941 11.784 ;
     RECT  42.869 19.632 42.977 20.328 ;
     RECT  42.221 48.432 42.977 48.504 ;
     RECT  42.793 56.784 43.045 58.536 ;
     RECT  41.969 60.048 43.045 60.072 ;
     RECT  42.793 25.248 43.049 26.808 ;
     RECT  42.793 17.856 43.085 17.88 ;
     RECT  42.757 43.344 43.117 43.416 ;
     RECT  41.692 44.448 43.117 44.472 ;
     RECT  42.437 46.512 43.117 46.536 ;
     RECT  43.141 14.352 43.153 14.376 ;
     RECT  42.833 21.6 43.153 22.488 ;
     RECT  43.117 43.344 43.157 44.472 ;
     RECT  43.045 56.784 43.157 60.072 ;
     RECT  41.651 12.768 43.187 13.08 ;
     RECT  43.153 14.352 43.189 14.76 ;
     RECT  43.189 14.352 43.228 14.856 ;
     RECT  42.761 2.496 43.229 10.44 ;
     RECT  43.228 14.736 43.237 14.856 ;
     RECT  41.969 41.616 43.237 41.64 ;
     RECT  43.237 40.8 43.244 41.64 ;
     RECT  42.221 49.776 43.285 53.4 ;
     RECT  43.244 40.8 43.331 42.168 ;
     RECT  43.157 43.392 43.331 44.472 ;
     RECT  43.285 49.536 43.337 53.4 ;
     RECT  40.504 33.072 43.34 33.336 ;
     RECT  42.473 54.624 43.369 55.752 ;
     RECT  42.077 35.136 43.381 36.504 ;
     RECT  43.34 32.928 43.427 33.336 ;
     RECT  43.229 8.256 43.481 10.44 ;
     RECT  43.153 21.6 43.481 22.584 ;
     RECT  43.369 54.384 43.585 55.752 ;
     RECT  43.369 23.904 43.589 23.928 ;
     RECT  42.433 29.76 43.589 31.896 ;
     RECT  43.157 56.784 43.697 59.88 ;
     RECT  43.589 29.808 43.708 31.896 ;
     RECT  43.337 50.592 43.724 53.4 ;
     RECT  43.585 54.384 43.724 55.8 ;
     RECT  42.689 16.656 43.733 16.68 ;
     RECT  43.117 46.512 43.769 46.776 ;
     RECT  43.708 30.288 43.801 31.896 ;
     RECT  43.381 34.56 43.801 36.504 ;
     RECT  43.724 50.592 43.841 55.8 ;
     RECT  43.049 25.296 43.848 26.808 ;
     RECT  42.901 61.728 43.873 61.752 ;
     RECT  43.841 52.896 43.877 55.8 ;
     RECT  43.481 21.6 43.909 22.488 ;
     RECT  43.848 25.296 43.909 27.336 ;
     RECT  43.877 52.896 43.913 52.92 ;
     RECT  43.004 47.856 43.945 47.88 ;
     RECT  43.945 47.856 43.985 48.312 ;
     RECT  43.697 57.024 44.021 59.88 ;
     RECT  43.229 2.496 44.053 7.224 ;
     RECT  43.285 37.584 44.053 37.608 ;
     RECT  42.833 38.976 44.053 39.336 ;
     RECT  43.841 50.592 44.057 51.912 ;
     RECT  44.053 37.584 44.089 39.336 ;
     RECT  43.331 40.8 44.089 41.4 ;
     RECT  43.909 25.296 44.129 27.96 ;
     RECT  43.877 54.624 44.129 55.8 ;
     RECT  43.331 43.392 44.197 43.896 ;
     RECT  43.297 12.288 44.233 12.408 ;
     RECT  44.197 43.296 44.237 43.896 ;
     RECT  44.053 2.304 44.305 7.224 ;
     RECT  43.481 8.256 44.305 10.056 ;
     RECT  42.977 19.632 44.305 19.656 ;
     RECT  43.909 21.408 44.305 22.488 ;
     RECT  43.237 14.832 44.345 14.856 ;
     RECT  44.233 12.192 44.413 12.408 ;
     RECT  43.873 61.728 44.417 62.28 ;
     RECT  43.801 34.56 44.444 36.6 ;
     RECT  44.305 18.768 44.453 19.656 ;
     RECT  44.089 37.584 44.483 41.4 ;
     RECT  44.444 34.512 44.485 36.6 ;
     RECT  44.483 37.584 44.485 37.608 ;
     RECT  44.021 59.328 44.489 59.88 ;
     RECT  44.483 38.64 44.497 39.384 ;
     RECT  44.485 34.512 44.531 37.608 ;
     RECT  43.801 30.288 44.557 31.944 ;
     RECT  43.427 33.072 44.557 33.336 ;
     RECT  44.197 17.712 44.561 17.736 ;
     RECT  44.489 59.328 44.597 59.592 ;
     RECT  44.129 25.296 44.633 26.52 ;
     RECT  44.413 12.192 44.665 12.84 ;
     RECT  44.021 57.024 44.809 58.152 ;
     RECT  44.129 27.936 45.061 27.96 ;
     RECT  45.025 16.272 45.241 16.296 ;
     RECT  44.057 50.88 45.277 51.912 ;
     RECT  44.665 12.192 45.308 13.512 ;
     RECT  44.989 14.688 45.308 14.712 ;
     RECT  45.241 16.08 45.313 16.296 ;
     RECT  45.313 16.08 45.349 16.584 ;
     RECT  45.061 27.936 45.385 28.488 ;
     RECT  45.308 12.192 45.457 14.712 ;
     RECT  45.349 16.08 45.493 16.632 ;
     RECT  45.385 27.936 45.493 29.064 ;
     RECT  44.557 30.288 45.493 33.336 ;
     RECT  45.493 15.984 45.529 16.632 ;
     RECT  44.453 19.632 45.565 19.656 ;
     RECT  44.237 43.296 45.565 43.32 ;
     RECT  44.305 2.304 45.608 10.056 ;
     RECT  45.457 11.232 45.608 14.712 ;
     RECT  45.529 15.984 45.608 16.92 ;
     RECT  45.565 18.816 45.608 19.656 ;
     RECT  44.305 21.216 45.608 22.488 ;
     RECT  44.633 25.392 45.608 26.52 ;
     RECT  45.493 27.936 45.608 33.336 ;
     RECT  44.531 34.704 45.608 37.608 ;
     RECT  44.497 38.64 45.608 39 ;
     RECT  44.483 40.416 45.608 41.4 ;
     RECT  45.565 43.104 45.608 43.32 ;
     RECT  44.161 47.04 45.608 47.064 ;
     RECT  43.985 48.288 45.608 48.312 ;
     RECT  43.337 49.536 45.608 49.56 ;
     RECT  45.277 50.88 45.608 52.2 ;
     RECT  44.129 54.624 45.608 55.512 ;
     RECT  44.809 56.544 45.608 58.152 ;
     RECT  44.597 59.568 45.608 59.592 ;
     RECT  44.417 62.256 45.608 62.28 ;
     RECT  45.608 2.148 45.712 62.652 ;
     RECT  45.712 2.304 45.904 62.382 ;
     RECT  45.904 28.464 46.019 29.88 ;
     RECT  45.904 35.136 46.019 36.024 ;
     RECT  45.904 55.296 46.019 60.12 ;
     RECT  45.904 2.304 46.181 12.12 ;
     RECT  45.904 39.312 46.211 39.336 ;
     RECT  45.904 45.12 46.253 45.48 ;
     RECT  46.181 11.952 46.289 12.12 ;
     RECT  45.904 13.92 46.289 17.256 ;
     RECT  46.289 14.112 46.325 17.256 ;
     RECT  45.904 40.464 46.396 43.8 ;
     RECT  45.904 50.688 46.396 53.64 ;
     RECT  46.396 40.464 46.397 42.168 ;
     RECT  46.181 2.304 46.433 10.824 ;
     RECT  46.019 35.136 46.505 35.352 ;
     RECT  46.397 40.944 46.505 42.168 ;
     RECT  46.019 55.296 46.505 58.488 ;
     RECT  46.505 56.592 46.541 58.488 ;
     RECT  45.904 31.68 46.793 31.896 ;
     RECT  46.505 40.944 46.793 41.784 ;
     RECT  45.904 27.264 46.829 27.288 ;
     RECT  46.019 28.464 46.829 29.064 ;
     RECT  46.396 53.52 46.865 53.64 ;
     RECT  46.396 50.688 46.937 52.488 ;
     RECT  46.396 43.776 46.969 43.8 ;
     RECT  45.904 18.816 47.117 22.056 ;
     RECT  45.904 25.776 47.185 26.28 ;
     RECT  46.969 43.776 47.189 44.472 ;
     RECT  45.904 49.2 47.257 49.224 ;
     RECT  46.019 60.096 47.297 60.12 ;
     RECT  46.433 2.496 47.324 10.824 ;
     RECT  46.289 11.952 47.324 11.976 ;
     RECT  47.324 2.496 47.369 11.976 ;
     RECT  47.257 49.2 47.369 50.184 ;
     RECT  46.829 29.04 47.441 29.064 ;
     RECT  47.189 44.448 47.513 44.472 ;
     RECT  46.541 56.592 47.653 57.096 ;
     RECT  46.541 58.128 47.653 58.488 ;
     RECT  46.937 51.6 47.689 52.488 ;
     RECT  46.865 53.52 47.689 53.544 ;
     RECT  47.369 11.232 47.693 11.976 ;
     RECT  46.325 14.4 47.801 17.256 ;
     RECT  47.689 51.6 47.801 53.544 ;
     RECT  46.793 41.76 47.833 41.784 ;
     RECT  47.545 43.104 47.833 43.128 ;
     RECT  47.185 25.632 47.845 26.28 ;
     RECT  47.581 27.36 47.845 27.384 ;
     RECT  47.845 25.632 47.891 27.384 ;
     RECT  46.505 55.296 47.893 55.512 ;
     RECT  47.653 56.592 47.893 58.488 ;
     RECT  47.833 41.76 47.941 43.128 ;
     RECT  47.117 21.408 47.977 22.056 ;
     RECT  47.893 55.296 47.981 58.488 ;
     RECT  46.253 45.456 48.013 45.48 ;
     RECT  47.981 58.416 48.053 58.488 ;
     RECT  47.117 18.816 48.089 20.376 ;
     RECT  45.904 33.312 48.121 33.336 ;
     RECT  47.801 14.688 48.125 17.256 ;
     RECT  47.981 55.296 48.125 57.336 ;
     RECT  48.053 58.464 48.125 58.488 ;
     RECT  47.509 24.624 48.229 24.648 ;
     RECT  45.904 37.008 48.229 37.032 ;
     RECT  48.125 55.296 48.233 56.04 ;
     RECT  48.229 24.336 48.269 24.648 ;
     RECT  47.941 40.848 48.301 43.128 ;
     RECT  47.185 47.28 48.305 47.304 ;
     RECT  48.277 30 48.364 30.024 ;
     RECT  47.369 2.496 48.373 10.2 ;
     RECT  47.693 11.232 48.373 11.256 ;
     RECT  48.265 60.096 48.373 60.12 ;
     RECT  48.013 45.456 48.377 45.96 ;
     RECT  47.369 50.16 48.445 50.184 ;
     RECT  48.269 24.336 48.467 24.36 ;
     RECT  48.301 40.8 48.481 43.128 ;
     RECT  48.125 14.688 48.521 16.584 ;
     RECT  48.089 19.824 48.589 20.376 ;
     RECT  47.977 21.408 48.589 22.2 ;
     RECT  46.505 35.136 48.593 35.16 ;
     RECT  48.373 60.096 48.661 60.36 ;
     RECT  48.121 33.312 48.709 33.48 ;
     RECT  48.409 12.72 48.769 12.744 ;
     RECT  48.769 12.72 48.773 13.032 ;
     RECT  48.229 37.008 48.805 37.608 ;
     RECT  48.481 40.608 48.841 43.128 ;
     RECT  48.661 60.096 48.841 60.408 ;
     RECT  47.891 25.632 48.881 26.52 ;
     RECT  48.805 37.008 48.913 38.472 ;
     RECT  47.653 48.432 48.949 48.456 ;
     RECT  48.445 49.728 48.949 50.184 ;
     RECT  48.589 58.56 48.949 58.584 ;
     RECT  48.841 60.096 48.949 60.984 ;
     RECT  48.913 36.432 48.953 38.472 ;
     RECT  48.953 37.44 48.985 38.472 ;
     RECT  48.377 45.6 48.995 45.96 ;
     RECT  48.949 48.432 48.995 50.184 ;
     RECT  47.801 51.6 49.061 53.016 ;
     RECT  48.841 40.608 49.165 43.176 ;
     RECT  48.949 58.56 49.169 60.984 ;
     RECT  48.985 37.44 49.201 39.336 ;
     RECT  49.169 60.384 49.205 60.984 ;
     RECT  48.233 55.296 49.237 55.56 ;
     RECT  48.521 14.688 49.313 16.296 ;
     RECT  48.953 36.432 49.313 36.456 ;
     RECT  48.373 2.496 49.345 11.256 ;
     RECT  48.773 13.008 49.349 13.032 ;
     RECT  49.201 37.44 49.417 39.384 ;
     RECT  49.165 40.56 49.417 43.176 ;
     RECT  47.869 28.512 49.421 28.536 ;
     RECT  48.709 33.312 49.421 33.576 ;
     RECT  48.125 57.024 49.489 57.336 ;
     RECT  46.793 31.872 49.525 31.896 ;
     RECT  48.995 45.6 49.561 45.72 ;
     RECT  49.169 58.56 49.561 59.256 ;
     RECT  49.525 31.344 49.571 31.896 ;
     RECT  48.089 18.816 49.597 18.84 ;
     RECT  48.589 19.824 49.597 22.2 ;
     RECT  49.237 54.912 49.637 55.56 ;
     RECT  48.421 23.28 49.669 23.304 ;
     RECT  49.417 37.44 49.673 43.176 ;
     RECT  49.597 18.816 49.741 22.2 ;
     RECT  49.669 23.28 49.741 23.352 ;
     RECT  49.205 60.96 49.741 60.984 ;
     RECT  45.904 62.112 49.741 62.136 ;
     RECT  49.313 16.272 49.745 16.296 ;
     RECT  49.741 60.96 49.745 62.136 ;
     RECT  49.061 52.032 49.781 53.016 ;
     RECT  49.673 40.512 49.885 43.176 ;
     RECT  49.885 40.512 49.921 43.848 ;
     RECT  49.561 45.216 49.921 45.72 ;
     RECT  49.781 52.08 49.921 53.016 ;
     RECT  49.637 55.536 49.921 55.56 ;
     RECT  49.489 56.784 49.921 57.336 ;
     RECT  49.741 18.816 49.961 23.352 ;
     RECT  48.995 48.432 49.997 49.752 ;
     RECT  49.421 33.312 50.029 33.336 ;
     RECT  48.881 26.496 50.101 26.52 ;
     RECT  49.777 27.888 50.101 27.912 ;
     RECT  49.813 29.616 50.101 29.64 ;
     RECT  49.571 31.344 50.101 31.368 ;
     RECT  49.345 2.496 50.108 11.448 ;
     RECT  49.921 55.536 50.209 57.336 ;
     RECT  49.561 58.512 50.209 59.256 ;
     RECT  50.209 55.536 50.245 59.256 ;
     RECT  49.021 47.04 50.353 47.064 ;
     RECT  49.997 48.432 50.353 48.84 ;
     RECT  50.108 2.496 50.425 11.688 ;
     RECT  49.313 14.688 50.461 15.24 ;
     RECT  50.245 55.536 50.461 59.784 ;
     RECT  49.745 60.96 50.461 61.896 ;
     RECT  50.101 26.496 50.533 27.912 ;
     RECT  49.345 35.328 50.54 35.352 ;
     RECT  50.101 36.336 50.54 36.36 ;
     RECT  50.461 14.688 50.677 16.056 ;
     RECT  50.101 29.616 50.749 31.368 ;
     RECT  50.029 32.736 50.749 33.336 ;
     RECT  50.677 14.112 50.821 16.056 ;
     RECT  50.425 2.352 51.008 11.688 ;
     RECT  50.821 14.112 51.008 16.296 ;
     RECT  49.961 18.816 51.008 23.304 ;
     RECT  50.533 26.496 51.008 28.536 ;
     RECT  50.749 29.616 51.008 33.336 ;
     RECT  50.54 35.328 51.008 36.36 ;
     RECT  49.673 37.44 51.008 39.384 ;
     RECT  49.921 40.512 51.008 45.72 ;
     RECT  50.353 47.04 51.008 48.84 ;
     RECT  49.561 50.832 51.008 50.856 ;
     RECT  49.921 52.08 51.008 53.592 ;
     RECT  50.461 55.536 51.008 61.896 ;
     RECT  51.008 2.148 51.112 62.652 ;
     RECT  51.112 2.418 51.304 62.382 ;
     RECT  51.304 14.064 51.539 17.112 ;
     RECT  51.304 24.96 51.545 24.984 ;
     RECT  51.304 12.864 51.587 13.08 ;
     RECT  51.304 37.44 51.725 37.656 ;
     RECT  51.539 14.688 51.779 17.112 ;
     RECT  51.779 14.688 51.797 15.864 ;
     RECT  51.797 15.84 51.82 15.864 ;
     RECT  51.304 61.584 51.905 61.752 ;
     RECT  51.304 55.68 51.923 60.36 ;
     RECT  51.923 58.128 51.941 60.36 ;
     RECT  51.304 30.72 51.977 30.744 ;
     RECT  51.304 43.392 51.977 47.88 ;
     RECT  51.941 58.512 51.977 60.36 ;
     RECT  51.797 14.688 52.013 14.712 ;
     RECT  51.977 46.752 52.013 47.88 ;
     RECT  51.304 54.096 52.057 54.696 ;
     RECT  51.304 18.24 52.121 21 ;
     RECT  51.304 38.64 52.157 42.024 ;
     RECT  52.057 54.144 52.297 54.696 ;
     RECT  51.923 55.68 52.297 57.048 ;
     RECT  52.297 54.144 52.3 57.048 ;
     RECT  51.304 2.496 52.373 11.4 ;
     RECT  51.725 37.632 52.373 37.656 ;
     RECT  51.304 29.568 52.405 29.592 ;
     RECT  52.157 38.736 52.405 42.024 ;
     RECT  51.977 43.392 52.405 45.768 ;
     RECT  51.304 32.16 52.441 33.336 ;
     RECT  52.373 8.256 52.444 11.4 ;
     RECT  51.304 26.064 52.445 27.096 ;
     RECT  52.405 28.992 52.477 29.592 ;
     RECT  51.304 52.992 52.499 53.016 ;
     RECT  52.3 54.144 52.553 55.704 ;
     RECT  52.445 26.352 52.585 27.096 ;
     RECT  52.553 55.296 52.589 55.704 ;
     RECT  52.549 52.608 52.621 52.92 ;
     RECT  52.013 46.752 52.625 47.064 ;
     RECT  52.405 38.736 52.733 45.768 ;
     RECT  52.297 49.776 52.733 49.8 ;
     RECT  52.733 39.312 52.769 45.768 ;
     RECT  52.477 28.992 52.877 29.784 ;
     RECT  52.121 18.96 52.909 21 ;
     RECT  52.657 22.224 52.909 22.248 ;
     RECT  52.769 39.312 52.913 40.968 ;
     RECT  52.625 46.752 52.913 46.824 ;
     RECT  52.3 56.784 52.913 57.048 ;
     RECT  52.441 32.16 52.933 33.768 ;
     RECT  52.933 32.16 52.979 34.104 ;
     RECT  52.979 33.312 52.981 34.104 ;
     RECT  51.304 36.336 52.981 36.36 ;
     RECT  51.587 13.008 52.985 13.08 ;
     RECT  52.769 42.72 52.985 45.768 ;
     RECT  51.779 17.088 53.017 17.112 ;
     RECT  51.977 58.512 53.021 60.312 ;
     RECT  53.017 16.992 53.057 17.112 ;
     RECT  52.553 54.144 53.057 54.168 ;
     RECT  52.981 33.312 53.065 34.2 ;
     RECT  52.913 39.312 53.093 40.728 ;
     RECT  52.985 42.72 53.129 45.048 ;
     RECT  52.585 26.352 53.221 27.816 ;
     RECT  51.304 50.832 53.233 50.856 ;
     RECT  52.877 29.568 53.267 29.784 ;
     RECT  52.979 32.16 53.267 32.184 ;
     RECT  53.233 50.832 53.273 51 ;
     RECT  53.065 33.312 53.315 33.864 ;
     RECT  53.161 23.328 53.377 23.352 ;
     RECT  53.221 26.352 53.417 27.912 ;
     RECT  52.589 55.68 53.417 55.704 ;
     RECT  53.417 26.352 53.461 27.816 ;
     RECT  53.267 29.76 53.507 29.784 ;
     RECT  51.905 61.584 53.516 61.608 ;
     RECT  52.621 52.176 53.521 52.92 ;
     RECT  52.444 11.376 53.525 11.4 ;
     RECT  52.981 35.712 53.557 36.36 ;
     RECT  53.557 35.712 53.561 37.176 ;
     RECT  53.516 61.584 53.603 62.424 ;
     RECT  52.913 46.752 53.629 46.776 ;
     RECT  53.377 23.328 53.633 23.928 ;
     RECT  53.633 23.328 53.669 23.352 ;
     RECT  52.373 2.496 53.701 7.224 ;
     RECT  52.444 8.256 53.701 9.912 ;
     RECT  53.129 42.72 53.737 43.32 ;
     RECT  53.021 58.512 53.773 60.264 ;
     RECT  52.909 18.96 53.777 22.248 ;
     RECT  53.057 16.992 53.885 17.016 ;
     RECT  53.561 35.808 53.989 37.176 ;
     RECT  53.773 58.08 54.137 60.264 ;
     RECT  53.777 19.344 54.173 22.248 ;
     RECT  53.461 26.304 54.173 27.816 ;
     RECT  54.137 58.56 54.173 60.264 ;
     RECT  54.173 19.824 54.205 22.248 ;
     RECT  53.737 42.672 54.205 43.32 ;
     RECT  54.173 58.56 54.209 60.12 ;
     RECT  53.989 35.808 54.229 37.368 ;
     RECT  53.093 39.36 54.316 40.728 ;
     RECT  54.229 35.808 54.317 38.136 ;
     RECT  54.316 40.704 54.317 40.728 ;
     RECT  54.205 19.824 54.389 22.824 ;
     RECT  53.701 2.496 54.425 9.912 ;
     RECT  53.521 52.176 54.457 53.016 ;
     RECT  53.315 33.312 54.524 33.336 ;
     RECT  54.205 41.856 54.529 43.32 ;
     RECT  53.129 44.304 54.529 45.048 ;
     RECT  53.273 50.976 54.565 51 ;
     RECT  54.317 35.808 54.668 37.368 ;
     RECT  54.529 41.856 54.673 45.048 ;
     RECT  53.629 46.512 54.673 46.776 ;
     RECT  54.457 52.176 54.677 53.592 ;
     RECT  54.389 19.824 54.749 21.624 ;
     RECT  54.673 41.856 54.749 46.776 ;
     RECT  54.565 50.16 54.785 51 ;
     RECT  54.677 52.176 54.785 53.352 ;
     RECT  54.668 35.712 54.925 37.368 ;
     RECT  54.749 46.752 54.925 46.776 ;
     RECT  54.173 26.304 54.961 27.624 ;
     RECT  54.749 41.856 54.965 45.768 ;
     RECT  52.913 57.024 54.997 57.048 ;
     RECT  54.565 28.704 55.103 28.728 ;
     RECT  54.925 35.184 55.105 37.368 ;
     RECT  54.316 39.36 55.105 39.672 ;
     RECT  54.785 50.16 55.109 50.184 ;
     RECT  54.961 26.208 55.141 27.624 ;
     RECT  55.103 28.704 55.141 28.968 ;
     RECT  54.524 33.312 55.141 33.816 ;
     RECT  55.105 34.8 55.141 37.368 ;
     RECT  54.965 41.856 55.181 45.336 ;
     RECT  55.105 38.784 55.189 39.672 ;
     RECT  55.141 24.624 55.213 24.648 ;
     RECT  55.141 33.312 55.217 37.368 ;
     RECT  54.925 46.752 55.235 47.016 ;
     RECT  55.213 24.624 55.285 25.032 ;
     RECT  55.141 26.208 55.285 28.968 ;
     RECT  54.785 52.176 55.285 53.016 ;
     RECT  55.181 42.576 55.289 45.336 ;
     RECT  55.289 42.576 55.325 42.84 ;
     RECT  55.217 35.184 55.333 37.368 ;
     RECT  54.997 56.976 55.393 57.576 ;
     RECT  53.603 61.584 55.397 61.608 ;
     RECT  54.389 22.8 55.465 22.824 ;
     RECT  55.285 24.624 55.477 28.968 ;
     RECT  54.524 30 55.477 30.024 ;
     RECT  55.217 33.312 55.477 33.912 ;
     RECT  55.333 35.184 55.537 37.608 ;
     RECT  55.393 56.304 55.537 57.576 ;
     RECT  55.477 24.624 55.573 30.024 ;
     RECT  54.524 31.632 55.628 31.656 ;
     RECT  55.537 55.488 55.717 57.576 ;
     RECT  54.209 58.56 55.717 59.736 ;
     RECT  54.749 19.824 55.753 21.528 ;
     RECT  52.985 13.008 55.897 13.032 ;
     RECT  55.897 12.528 55.909 13.032 ;
     RECT  55.861 14.208 55.909 14.232 ;
     RECT  55.753 54.096 55.925 54.12 ;
     RECT  55.717 55.488 55.925 59.736 ;
     RECT  55.909 12.528 55.933 14.232 ;
     RECT  55.753 19.824 56.149 21.72 ;
     RECT  55.465 22.8 56.149 23.256 ;
     RECT  55.285 51.648 56.365 53.016 ;
     RECT  54.425 2.544 56.408 9.912 ;
     RECT  55.933 12.24 56.408 14.232 ;
     RECT  56.401 18.768 56.408 18.792 ;
     RECT  56.149 19.824 56.408 23.256 ;
     RECT  55.573 24.528 56.408 30.024 ;
     RECT  55.628 31.632 56.408 31.896 ;
     RECT  55.477 33.216 56.408 33.912 ;
     RECT  55.537 35.184 56.408 37.8 ;
     RECT  55.189 39.216 56.408 39.672 ;
     RECT  55.249 40.896 56.408 41.592 ;
     RECT  55.325 42.576 56.408 42.6 ;
     RECT  55.289 44.304 56.408 45.336 ;
     RECT  55.235 46.752 56.408 46.776 ;
     RECT  56.365 51.456 56.408 53.016 ;
     RECT  55.925 54.096 56.408 59.736 ;
     RECT  56.293 60.816 56.408 60.936 ;
     RECT  56.408 2.148 56.512 62.652 ;
     RECT  56.512 2.418 56.704 62.382 ;
     RECT  56.704 33.312 56.801 33.912 ;
     RECT  56.704 35.184 56.819 37.032 ;
     RECT  56.819 37.008 56.867 37.032 ;
     RECT  56.704 2.544 56.873 9.912 ;
     RECT  56.704 11.232 56.873 11.256 ;
     RECT  56.704 12.528 56.873 15.816 ;
     RECT  56.704 24.624 56.909 29.064 ;
     RECT  56.704 56.832 56.915 59.208 ;
     RECT  56.819 35.184 56.945 36.024 ;
     RECT  56.704 60.288 56.981 61.032 ;
     RECT  56.704 38.496 57.011 42.6 ;
     RECT  57.011 38.688 57.017 42.6 ;
     RECT  56.704 45.024 57.017 46.536 ;
     RECT  56.704 19.824 57.053 22.776 ;
     RECT  57.017 39.216 57.059 42.6 ;
     RECT  56.704 49.488 57.059 53.064 ;
     RECT  56.909 25.728 57.089 29.064 ;
     RECT  57.017 46.128 57.107 46.536 ;
     RECT  57.059 49.488 57.125 52.584 ;
     RECT  56.915 57.12 57.155 59.208 ;
     RECT  57.125 49.488 57.197 52.488 ;
     RECT  56.873 13.776 57.233 15.816 ;
     RECT  56.704 55.824 57.233 55.848 ;
     RECT  57.233 13.776 57.413 15.768 ;
     RECT  57.413 13.776 57.521 14.808 ;
     RECT  57.059 41.616 57.521 42.6 ;
     RECT  57.197 49.488 57.587 50.76 ;
     RECT  56.945 35.808 57.593 36.024 ;
     RECT  57.521 41.952 57.629 42.6 ;
     RECT  56.873 2.592 57.665 9.912 ;
     RECT  57.089 25.824 57.737 29.064 ;
     RECT  57.521 13.824 57.881 14.808 ;
     RECT  57.053 19.92 57.953 22.728 ;
     RECT  56.909 24.624 57.985 24.648 ;
     RECT  57.107 46.512 58.021 46.536 ;
     RECT  56.704 47.904 58.021 48.12 ;
     RECT  57.197 52.464 58.025 52.488 ;
     RECT  57.593 36 58.076 36.024 ;
     RECT  57.059 39.216 58.117 40.056 ;
     RECT  56.981 60.432 58.117 61.032 ;
     RECT  57.985 23.808 58.163 24.648 ;
     RECT  58.076 36 58.163 36.84 ;
     RECT  58.117 60.432 58.204 61.752 ;
     RECT  56.704 54.672 58.309 54.696 ;
     RECT  58.309 54.528 58.349 54.696 ;
     RECT  57.155 57.264 58.381 59.208 ;
     RECT  57.017 45.024 58.385 45.048 ;
     RECT  58.163 23.808 58.421 24.072 ;
     RECT  58.309 18.144 58.46 18.168 ;
     RECT  56.704 31.776 58.493 31.8 ;
     RECT  58.163 36 58.493 36.024 ;
     RECT  57.665 2.832 58.561 9.912 ;
     RECT  58.46 18.144 58.561 18.552 ;
     RECT  58.204 60.432 58.691 61.032 ;
     RECT  58.349 54.528 58.741 54.648 ;
     RECT  58.381 56.976 58.741 59.208 ;
     RECT  58.691 60.432 58.741 60.888 ;
     RECT  58.561 2.832 58.921 10.872 ;
     RECT  58.597 50.496 58.957 50.52 ;
     RECT  58.741 54.096 58.997 54.648 ;
     RECT  58.561 18.144 59.033 18.84 ;
     RECT  58.993 15.792 59.101 15.816 ;
     RECT  58.021 46.512 59.101 48.12 ;
     RECT  59.101 15.36 59.137 15.816 ;
     RECT  59.101 46.512 59.137 48.408 ;
     RECT  58.957 50.496 59.141 50.712 ;
     RECT  59.137 46.128 59.221 48.408 ;
     RECT  57.587 49.488 59.245 49.512 ;
     RECT  59.141 50.496 59.245 50.52 ;
     RECT  57.737 26.112 59.269 29.064 ;
     RECT  59.269 26.112 59.353 29.64 ;
     RECT  59.245 49.488 59.357 50.52 ;
     RECT  58.921 2.832 59.389 11.304 ;
     RECT  59.137 15.36 59.389 15.864 ;
     RECT  57.953 19.92 59.389 22.104 ;
     RECT  59.389 2.832 59.429 11.448 ;
     RECT  59.429 11.28 59.473 11.448 ;
     RECT  59.389 19.92 59.497 22.776 ;
     RECT  59.353 36.72 59.533 36.744 ;
     RECT  59.353 25.584 59.573 29.64 ;
     RECT  59.221 45.984 59.609 48.408 ;
     RECT  59.497 19.824 59.645 22.776 ;
     RECT  59.533 36.528 59.645 36.744 ;
     RECT  59.609 45.984 59.651 46.584 ;
     RECT  58.741 56.976 59.677 60.888 ;
     RECT  59.473 11.28 59.753 11.304 ;
     RECT  59.609 47.952 59.789 48.408 ;
     RECT  59.245 31.392 59.797 31.416 ;
     RECT  57.629 41.952 59.821 41.976 ;
     RECT  58.421 23.904 59.825 24.072 ;
     RECT  59.389 15.36 59.843 16.776 ;
     RECT  59.645 21.936 59.857 22.776 ;
     RECT  59.825 23.904 59.857 23.928 ;
     RECT  59.033 18.144 59.861 18.168 ;
     RECT  59.645 36.528 59.897 36.552 ;
     RECT  59.645 19.824 59.929 20.616 ;
     RECT  59.677 56.976 60.001 61.704 ;
     RECT  58.997 54.624 60.073 54.648 ;
     RECT  59.929 19.776 60.145 20.616 ;
     RECT  57.881 13.824 60.253 13.848 ;
     RECT  59.843 15.36 60.253 16.008 ;
     RECT  59.797 31.344 60.253 31.416 ;
     RECT  59.857 21.936 60.257 23.928 ;
     RECT  60.037 44.592 60.289 44.616 ;
     RECT  59.821 41.376 60.373 41.976 ;
     RECT  57.949 43.296 60.373 43.32 ;
     RECT  60.289 44.592 60.373 44.904 ;
     RECT  60.073 53.808 60.397 54.648 ;
     RECT  60.253 15.312 60.401 16.008 ;
     RECT  60.253 31.248 60.401 31.464 ;
     RECT  60.373 41.376 60.419 44.904 ;
     RECT  60.419 43.776 60.437 44.904 ;
     RECT  60.257 21.936 60.467 23.352 ;
     RECT  60.253 13.104 60.473 13.848 ;
     RECT  59.429 2.832 60.505 9.912 ;
     RECT  60.437 43.776 60.509 43.8 ;
     RECT  60.001 56.976 60.581 62.184 ;
     RECT  59.357 49.488 60.649 49.848 ;
     RECT  60.505 2.832 60.653 10.2 ;
     RECT  60.467 21.936 60.653 22.2 ;
     RECT  59.651 45.984 60.661 46.536 ;
     RECT  59.789 47.952 60.661 48.216 ;
     RECT  56.801 33.312 60.685 33.816 ;
     RECT  60.397 53.616 60.689 54.648 ;
     RECT  60.649 49.488 60.707 50.76 ;
     RECT  60.685 37.248 60.721 37.272 ;
     RECT  60.707 49.824 60.733 50.76 ;
     RECT  60.689 53.808 60.761 54.648 ;
     RECT  60.761 53.904 60.797 54.648 ;
     RECT  60.581 56.976 60.86 61.704 ;
     RECT  60.145 19.296 60.901 20.616 ;
     RECT  60.901 18.864 60.937 20.616 ;
     RECT  60.937 18.768 60.973 20.616 ;
     RECT  60.653 21.936 60.973 22.104 ;
     RECT  58.117 38.448 60.997 40.056 ;
     RECT  60.419 41.376 60.997 42.504 ;
     RECT  59.929 17.616 61.045 17.64 ;
     RECT  60.685 33.312 61.117 34.44 ;
     RECT  60.661 45.984 61.189 48.216 ;
     RECT  60.653 3.072 61.261 10.2 ;
     RECT  61.189 11.952 61.333 11.976 ;
     RECT  61.261 3.072 61.405 10.344 ;
     RECT  60.401 15.456 61.441 16.008 ;
     RECT  60.721 37.248 61.441 37.368 ;
     RECT  61.405 3.072 61.477 10.632 ;
     RECT  61.333 11.952 61.477 12.216 ;
     RECT  60.473 13.344 61.669 13.848 ;
     RECT  59.573 26.304 61.669 29.64 ;
     RECT  61.189 45.264 61.669 48.216 ;
     RECT  60.401 31.44 61.729 31.464 ;
     RECT  61.477 3.072 61.808 12.216 ;
     RECT  61.669 13.344 61.808 14.28 ;
     RECT  61.441 15.408 61.808 16.008 ;
     RECT  61.045 17.424 61.808 17.64 ;
     RECT  60.973 18.768 61.808 22.104 ;
     RECT  60.467 23.328 61.808 23.352 ;
     RECT  61.669 25.584 61.808 29.64 ;
     RECT  61.729 31.44 61.808 31.752 ;
     RECT  61.117 33.312 61.808 35.304 ;
     RECT  61.441 36.528 61.808 37.416 ;
     RECT  60.997 38.448 61.808 42.504 ;
     RECT  61.669 44.448 61.808 48.216 ;
     RECT  60.733 49.824 61.808 49.848 ;
     RECT  60.797 54.576 61.808 54.648 ;
     RECT  60.86 56.4 61.808 61.704 ;
     RECT  61.808 2.148 61.912 62.652 ;
     RECT  61.912 2.418 62.104 62.382 ;
     RECT  62.104 15.456 62.165 17.688 ;
     RECT  62.104 26.256 62.201 29.64 ;
     RECT  62.104 19.248 62.237 19.272 ;
     RECT  62.165 16.896 62.243 17.688 ;
     RECT  62.104 44.736 62.243 48.216 ;
     RECT  62.104 56.352 62.309 60.936 ;
     RECT  62.104 39.024 62.381 41.496 ;
     RECT  62.104 2.418 62.417 10.632 ;
     RECT  62.417 2.418 62.489 10.392 ;
     RECT  62.243 45.552 62.669 48.216 ;
     RECT  62.104 49.728 62.669 49.848 ;
     RECT  62.104 24.384 62.705 24.696 ;
     RECT  62.669 46.272 62.705 48.216 ;
     RECT  62.104 33.312 62.723 37.56 ;
     RECT  62.723 33.312 62.764 33.96 ;
     RECT  62.705 24.528 62.771 24.696 ;
     RECT  62.104 30.864 62.771 31.944 ;
     RECT  62.764 33.312 62.785 33.672 ;
     RECT  62.104 20.352 62.867 23.352 ;
     RECT  62.489 2.418 62.881 7.224 ;
     RECT  62.867 20.352 63.097 22.104 ;
     RECT  62.104 52.176 63.097 53.016 ;
     RECT  62.104 54.144 63.097 54.648 ;
     RECT  62.381 39.744 63.101 41.496 ;
     RECT  63.097 52.176 63.157 54.648 ;
     RECT  62.104 11.712 63.173 14.088 ;
     RECT  63.101 39.744 63.203 41.016 ;
     RECT  62.243 16.896 63.205 17.544 ;
     RECT  62.723 34.944 63.209 37.56 ;
     RECT  62.165 15.456 63.241 15.528 ;
     RECT  63.205 16.896 63.241 18.168 ;
     RECT  62.201 26.256 63.241 28.968 ;
     RECT  63.157 51.504 63.241 54.648 ;
     RECT  63.209 35.952 63.245 37.56 ;
     RECT  63.241 51.504 63.245 54.696 ;
     RECT  63.241 15.456 63.277 18.168 ;
     RECT  63.277 15.456 63.281 18.984 ;
     RECT  63.281 15.744 63.347 18.984 ;
     RECT  63.245 52.176 63.353 54.696 ;
     RECT  62.771 24.672 63.421 24.696 ;
     RECT  63.241 26.256 63.421 29.016 ;
     RECT  63.347 16.896 63.457 18.984 ;
     RECT  63.097 20.064 63.457 22.104 ;
     RECT  62.881 2.304 63.601 7.224 ;
     RECT  62.489 8.256 63.601 10.392 ;
     RECT  63.157 42 63.644 42.024 ;
     RECT  63.644 42 63.731 42.984 ;
     RECT  63.205 44.064 63.731 44.088 ;
     RECT  63.173 11.952 63.749 14.088 ;
     RECT  62.785 33.312 63.781 33.336 ;
     RECT  62.309 56.496 63.781 60.936 ;
     RECT  63.601 61.968 63.781 61.992 ;
     RECT  62.705 46.512 63.836 48.216 ;
     RECT  63.601 2.304 63.857 10.392 ;
     RECT  63.457 16.896 63.893 22.104 ;
     RECT  63.836 46.512 63.923 48.504 ;
     RECT  63.893 20.544 63.961 22.104 ;
     RECT  62.867 23.088 63.961 23.208 ;
     RECT  63.961 20.544 64.037 23.208 ;
     RECT  63.245 36.384 64.067 37.56 ;
     RECT  63.601 38.64 64.069 38.664 ;
     RECT  63.781 56.496 64.073 61.992 ;
     RECT  64.067 37.248 64.109 37.56 ;
     RECT  64.069 38.64 64.153 38.76 ;
     RECT  63.749 11.952 64.181 12.504 ;
     RECT  64.073 61.92 64.213 61.992 ;
     RECT  64.037 23.184 64.217 23.208 ;
     RECT  64.073 56.496 64.217 60.936 ;
     RECT  63.347 15.744 64.285 15.864 ;
     RECT  64.213 61.92 64.325 62.04 ;
     RECT  63.923 46.512 64.393 48.408 ;
     RECT  64.325 61.92 64.433 61.992 ;
     RECT  63.781 32.976 64.451 33.336 ;
     RECT  63.893 17.424 64.469 19.128 ;
     RECT  62.771 30.864 64.469 31.896 ;
     RECT  64.393 46.176 64.477 48.408 ;
     RECT  63.857 2.736 64.537 10.392 ;
     RECT  64.537 2.736 64.573 10.824 ;
     RECT  64.109 37.296 64.573 37.56 ;
     RECT  62.669 49.728 64.573 49.752 ;
     RECT  64.177 50.736 64.573 50.76 ;
     RECT  64.285 15.696 64.613 15.864 ;
     RECT  64.153 38.64 64.613 38.664 ;
     RECT  64.573 49.728 64.613 50.76 ;
     RECT  64.573 2.736 64.717 10.968 ;
     RECT  64.181 11.952 64.717 12.36 ;
     RECT  64.573 37.296 64.721 37.656 ;
     RECT  64.451 32.976 64.739 33.096 ;
     RECT  63.209 34.944 64.825 34.968 ;
     RECT  63.203 39.744 64.825 40.344 ;
     RECT  63.421 24.672 64.865 29.016 ;
     RECT  64.217 56.496 64.933 60.888 ;
     RECT  64.739 32.976 64.937 33 ;
     RECT  64.037 20.544 65.009 22.2 ;
     RECT  64.865 25.392 65.036 29.016 ;
     RECT  65.036 25.392 65.123 29.784 ;
     RECT  64.469 17.424 65.221 18.168 ;
     RECT  64.717 2.736 65.297 12.36 ;
     RECT  64.721 37.536 65.297 37.656 ;
     RECT  64.477 46.512 65.333 48.408 ;
     RECT  64.825 39.744 65.365 40.824 ;
     RECT  65.297 37.632 65.401 37.656 ;
     RECT  65.401 37.632 65.549 38.184 ;
     RECT  64.213 45.072 65.617 45.096 ;
     RECT  65.297 2.736 65.657 12.216 ;
     RECT  65.077 19.248 65.689 19.272 ;
     RECT  65.009 20.544 65.689 20.952 ;
     RECT  65.617 44.976 65.725 45.096 ;
     RECT  64.613 15.84 65.761 15.864 ;
     RECT  65.333 46.512 65.765 47.88 ;
     RECT  65.221 17.328 65.833 18.168 ;
     RECT  65.761 15.84 65.905 16.248 ;
     RECT  65.833 17.328 65.905 18.264 ;
     RECT  64.933 56.208 65.941 60.888 ;
     RECT  65.905 15.84 65.977 18.264 ;
     RECT  64.613 49.728 65.977 50.184 ;
     RECT  63.749 14.064 65.981 14.088 ;
     RECT  65.689 19.248 66.013 20.952 ;
     RECT  65.009 21.936 66.013 22.2 ;
     RECT  65.941 56.064 66.013 60.888 ;
     RECT  64.433 61.92 66.013 61.944 ;
     RECT  64.469 30.864 66.049 31.416 ;
     RECT  63.353 52.704 66.049 54.696 ;
     RECT  66.013 56.064 66.049 61.944 ;
     RECT  66.049 52.704 66.053 61.944 ;
     RECT  65.977 15.36 66.085 18.264 ;
     RECT  66.013 19.248 66.085 22.2 ;
     RECT  66.085 15.36 66.157 22.2 ;
     RECT  65.365 39.744 66.193 41.4 ;
     RECT  66.133 42.72 66.22 42.744 ;
     RECT  65.725 44.976 66.229 45.288 ;
     RECT  65.765 46.512 66.229 46.536 ;
     RECT  66.133 43.824 66.265 43.848 ;
     RECT  66.157 15.216 66.301 22.2 ;
     RECT  66.229 23.28 66.301 23.304 ;
     RECT  64.825 34.176 66.332 34.968 ;
     RECT  66.229 44.976 66.409 46.536 ;
     RECT  65.657 2.736 66.445 12.024 ;
     RECT  66.332 34.176 66.589 35.688 ;
     RECT  66.193 39.552 66.613 41.4 ;
     RECT  66.265 43.2 66.62 43.848 ;
     RECT  66.409 44.832 66.62 46.536 ;
     RECT  66.589 33.792 66.661 35.688 ;
     RECT  65.123 25.392 66.709 29.016 ;
     RECT  65.977 49.728 66.709 50.472 ;
     RECT  66.661 33.792 66.716 35.736 ;
     RECT  66.049 30.864 66.733 31.8 ;
     RECT  66.733 30.864 66.877 32.328 ;
     RECT  66.716 33.792 66.877 36.456 ;
     RECT  66.301 15.216 66.913 23.304 ;
     RECT  66.913 15.024 66.985 23.304 ;
     RECT  66.053 53.232 67.093 61.944 ;
     RECT  66.445 2.352 67.208 12.024 ;
     RECT  66.985 14.976 67.208 23.304 ;
     RECT  66.709 24.528 67.208 29.016 ;
     RECT  66.877 30.864 67.208 36.456 ;
     RECT  65.549 38.112 67.208 38.184 ;
     RECT  66.613 39.456 67.208 41.4 ;
     RECT  66.62 43.2 67.208 46.536 ;
     RECT  65.765 47.856 67.208 47.88 ;
     RECT  66.709 49.008 67.208 50.856 ;
     RECT  67.093 52.8 67.208 61.944 ;
     RECT  67.208 2.148 67.312 62.652 ;
     RECT  67.312 2.352 67.313 62.382 ;
     RECT  67.313 2.418 67.504 62.382 ;
     RECT  67.504 39.504 67.565 39.912 ;
     RECT  67.504 50.064 67.601 62.04 ;
     RECT  67.504 30.048 67.637 33 ;
     RECT  67.504 37.104 67.673 37.464 ;
     RECT  67.637 30.144 67.853 33 ;
     RECT  67.673 37.44 67.889 37.464 ;
     RECT  67.504 44.88 67.961 46.536 ;
     RECT  67.565 39.552 68.105 39.912 ;
     RECT  67.961 45.264 68.105 46.536 ;
     RECT  67.504 24.336 68.14 29.016 ;
     RECT  68.14 24.336 68.284 24.888 ;
     RECT  67.504 34.368 68.387 34.488 ;
     RECT  67.504 10.992 68.429 13.128 ;
     RECT  68.105 46.128 68.465 46.536 ;
     RECT  68.429 10.992 68.501 11.4 ;
     RECT  68.105 39.744 68.501 39.912 ;
     RECT  68.429 13.104 68.789 13.128 ;
     RECT  67.504 2.736 68.893 7.272 ;
     RECT  67.504 8.256 68.893 9.912 ;
     RECT  67.504 14.256 68.929 23.304 ;
     RECT  68.501 10.992 68.969 11.304 ;
     RECT  68.929 14.256 69.005 23.64 ;
     RECT  68.387 34.464 69.005 34.488 ;
     RECT  68.501 39.888 69.109 39.912 ;
     RECT  69.109 39.888 69.155 40.392 ;
     RECT  69.005 14.784 69.221 23.64 ;
     RECT  68.857 43.344 69.221 43.368 ;
     RECT  68.14 26.064 69.361 29.016 ;
     RECT  67.853 30.144 69.361 31.8 ;
     RECT  67.504 35.664 69.361 36.024 ;
     RECT  67.601 50.064 69.433 50.088 ;
     RECT  69.433 49.968 69.473 50.088 ;
     RECT  67.601 51.264 69.505 62.04 ;
     RECT  69.221 14.832 69.509 23.64 ;
     RECT  68.465 46.512 69.541 46.536 ;
     RECT  68.284 24.864 69.577 24.888 ;
     RECT  69.361 26.064 69.577 31.8 ;
     RECT  69.361 35.472 69.577 36.024 ;
     RECT  69.505 51.264 69.617 62.568 ;
     RECT  69.509 22.08 69.653 23.64 ;
     RECT  69.577 24.864 69.653 31.8 ;
     RECT  69.617 52.416 69.689 62.568 ;
     RECT  68.893 2.736 69.865 9.912 ;
     RECT  69.509 14.832 69.869 20.952 ;
     RECT  69.689 52.704 69.875 62.568 ;
     RECT  69.155 40.368 70.009 40.392 ;
     RECT  67.504 41.376 70.009 41.4 ;
     RECT  69.653 30.816 70.045 31.8 ;
     RECT  67.853 32.976 70.045 33 ;
     RECT  69.865 2.496 70.049 9.912 ;
     RECT  69.653 24.864 70.081 29.016 ;
     RECT  69.577 35.472 70.117 36.264 ;
     RECT  69.541 45.936 70.117 46.536 ;
     RECT  70.081 24.816 70.153 29.016 ;
     RECT  70.117 45.312 70.163 46.824 ;
     RECT  70.049 8.256 70.225 9.912 ;
     RECT  68.969 11.28 70.225 11.304 ;
     RECT  70.163 45.312 70.265 45.336 ;
     RECT  69.617 51.264 70.297 51.336 ;
     RECT  70.297 51.216 70.337 51.336 ;
     RECT  70.049 2.496 70.409 7.224 ;
     RECT  69.473 49.968 70.657 49.992 ;
     RECT  69.653 22.08 70.693 23.016 ;
     RECT  69.869 14.976 70.733 20.952 ;
     RECT  70.693 21.984 70.733 23.304 ;
     RECT  70.045 30.816 70.733 33 ;
     RECT  70.225 8.256 70.769 11.304 ;
     RECT  70.733 30.912 70.769 33 ;
     RECT  70.117 34.08 70.769 36.264 ;
     RECT  70.769 35.328 70.833 36.264 ;
     RECT  70.333 39.264 70.837 39.288 ;
     RECT  70.153 24.48 70.877 29.016 ;
     RECT  70.297 42.768 70.877 42.792 ;
     RECT  70.837 38.688 70.883 39.288 ;
     RECT  70.883 38.688 70.924 38.904 ;
     RECT  70.733 20.304 70.945 20.952 ;
     RECT  70.733 21.984 70.945 22.008 ;
     RECT  70.657 49.968 70.949 50.088 ;
     RECT  70.769 34.08 71.057 34.104 ;
     RECT  70.769 11.28 71.089 11.304 ;
     RECT  70.009 40.368 71.093 41.4 ;
     RECT  69.875 52.752 71.093 62.568 ;
     RECT  70.877 24.816 71.129 29.016 ;
     RECT  70.337 51.216 71.237 51.24 ;
     RECT  70.945 20.304 71.273 22.008 ;
     RECT  70.833 35.328 71.453 36.168 ;
     RECT  70.409 3.024 71.561 7.224 ;
     RECT  70.733 14.976 71.701 19.224 ;
     RECT  69.721 12.912 71.737 12.936 ;
     RECT  71.701 14.976 71.737 19.272 ;
     RECT  70.769 30.912 71.773 31.944 ;
     RECT  70.769 32.976 71.773 33 ;
     RECT  71.737 12.912 71.809 13.08 ;
     RECT  71.737 14.112 71.809 19.272 ;
     RECT  71.129 25.632 71.809 29.016 ;
     RECT  70.949 50.064 71.809 50.088 ;
     RECT  71.809 25.632 71.845 29.064 ;
     RECT  71.773 30.336 71.845 33 ;
     RECT  71.089 11.28 71.953 11.448 ;
     RECT  71.809 12.912 71.953 19.272 ;
     RECT  71.809 50.064 71.989 50.568 ;
     RECT  71.953 11.28 72.229 19.272 ;
     RECT  71.273 20.304 72.229 20.952 ;
     RECT  71.561 3.168 72.277 7.224 ;
     RECT  70.769 8.256 72.277 9.912 ;
     RECT  71.989 50.016 72.349 50.568 ;
     RECT  71.273 21.984 72.385 22.008 ;
     RECT  70.733 23.28 72.385 23.304 ;
     RECT  72.061 51.744 72.449 51.768 ;
     RECT  71.093 53.04 72.449 62.568 ;
     RECT  72.229 11.28 72.469 20.952 ;
     RECT  72.277 3.168 72.608 9.912 ;
     RECT  72.469 10.896 72.608 20.952 ;
     RECT  72.385 21.984 72.608 23.304 ;
     RECT  71.845 25.632 72.608 33 ;
     RECT  71.453 35.328 72.608 35.352 ;
     RECT  72.277 36.432 72.608 36.456 ;
     RECT  70.924 38.88 72.608 38.904 ;
     RECT  71.093 40.368 72.608 40.392 ;
     RECT  71.093 41.376 72.608 41.4 ;
     RECT  70.163 46.512 72.608 46.824 ;
     RECT  72.529 47.856 72.608 47.88 ;
     RECT  72.349 50.016 72.608 50.616 ;
     RECT  72.449 51.744 72.608 62.568 ;
     RECT  72.608 2.148 72.712 62.652 ;
     RECT  72.712 2.418 72.821 62.568 ;
     RECT  72.821 2.418 72.904 62.382 ;
     RECT  72.904 49.776 73.001 50.616 ;
     RECT  72.904 21.984 73.043 24.504 ;
     RECT  72.904 40.368 73.043 41.4 ;
     RECT  73.043 23.28 73.084 24.504 ;
     RECT  72.904 2.496 73.109 11.736 ;
     RECT  72.904 14.976 73.181 20.952 ;
     RECT  73.181 14.976 73.217 18.744 ;
     RECT  72.904 34.128 73.235 36.792 ;
     RECT  73.001 49.776 73.253 50.568 ;
     RECT  73.235 34.128 73.261 36.264 ;
     RECT  72.904 30.768 73.361 32.76 ;
     RECT  72.904 47.856 73.397 47.928 ;
     RECT  72.904 13.056 73.433 13.896 ;
     RECT  73.181 20.064 73.433 20.952 ;
     RECT  73.397 47.904 73.469 47.928 ;
     RECT  73.433 13.152 73.523 13.896 ;
     RECT  72.904 25.536 73.577 29.256 ;
     RECT  73.361 30.816 73.577 32.76 ;
     RECT  72.904 38.4 73.577 38.424 ;
     RECT  73.577 26.592 73.721 29.256 ;
     RECT  73.261 36.24 73.721 36.264 ;
     RECT  73.523 13.152 73.757 13.656 ;
     RECT  73.109 2.784 73.793 11.736 ;
     RECT  73.217 15.408 73.829 18.744 ;
     RECT  73.829 16.944 73.865 18.744 ;
     RECT  73.261 34.128 73.9 34.584 ;
     RECT  73.793 8.256 74.077 11.736 ;
     RECT  73.043 21.984 74.077 22.008 ;
     RECT  73.577 30.816 74.099 32.52 ;
     RECT  72.904 51.888 74.149 61.992 ;
     RECT  73.577 25.536 74.153 25.56 ;
     RECT  73.721 26.64 74.153 29.256 ;
     RECT  73.084 24.48 74.297 24.504 ;
     RECT  73.253 50.016 74.297 50.568 ;
     RECT  73.793 2.784 74.437 7.224 ;
     RECT  73.043 40.368 74.437 41.112 ;
     RECT  73.433 20.304 74.472 20.952 ;
     RECT  73.084 23.28 74.581 23.304 ;
     RECT  73.757 13.296 74.621 13.656 ;
     RECT  73.829 15.408 74.653 15.72 ;
     RECT  73.865 16.944 74.657 18.552 ;
     RECT  74.653 15.312 74.725 15.72 ;
     RECT  74.153 26.64 74.729 29.064 ;
     RECT  74.297 50.016 74.797 50.184 ;
     RECT  74.657 16.944 74.801 17.064 ;
     RECT  74.149 51.888 74.801 62.568 ;
     RECT  74.725 14.976 74.873 15.72 ;
     RECT  74.725 33.456 74.873 33.48 ;
     RECT  73.9 34.56 74.941 34.584 ;
     RECT  74.801 51.888 74.941 58.44 ;
     RECT  74.077 8.256 75.013 11.976 ;
     RECT  74.621 13.632 75.013 13.656 ;
     RECT  74.873 14.976 75.013 15.336 ;
     RECT  74.797 49.68 75.049 50.184 ;
     RECT  75.049 49.008 75.053 50.184 ;
     RECT  74.729 27.312 75.121 29.064 ;
     RECT  75.053 49.008 75.161 50.136 ;
     RECT  75.121 27.312 75.193 29.496 ;
     RECT  74.941 34.224 75.253 34.584 ;
     RECT  75.013 8.256 75.305 12.552 ;
     RECT  75.161 49.68 75.377 50.136 ;
     RECT  74.472 20.016 75.397 20.952 ;
     RECT  74.077 21.984 75.397 22.2 ;
     RECT  74.437 40.32 75.404 41.112 ;
     RECT  74.801 59.664 75.449 62.568 ;
     RECT  75.397 20.016 75.484 22.2 ;
     RECT  75.404 39.84 75.491 41.112 ;
     RECT  75.377 50.064 75.521 50.136 ;
     RECT  74.657 18.192 75.557 18.552 ;
     RECT  74.801 16.944 75.665 16.968 ;
     RECT  74.099 30.816 75.701 32.472 ;
     RECT  75.253 34.224 75.773 35.352 ;
     RECT  74.581 23.232 75.841 23.304 ;
     RECT  75.773 34.224 75.845 34.824 ;
     RECT  75.013 13.632 75.877 15.336 ;
     RECT  75.517 44.064 75.877 44.088 ;
     RECT  72.904 46.512 75.923 46.824 ;
     RECT  75.305 8.256 75.953 11.976 ;
     RECT  75.845 34.8 75.953 34.824 ;
     RECT  75.491 39.888 75.985 41.112 ;
     RECT  74.941 51.744 76.025 58.44 ;
     RECT  75.877 13.296 76.061 15.528 ;
     RECT  75.877 43.296 76.069 44.088 ;
     RECT  75.985 39.888 76.115 41.304 ;
     RECT  75.841 22.416 76.201 23.304 ;
     RECT  75.449 59.664 76.201 62.472 ;
     RECT  75.484 20.016 76.205 21.096 ;
     RECT  76.061 13.296 76.259 14.184 ;
     RECT  76.025 55.968 76.273 58.44 ;
     RECT  76.201 59.472 76.273 62.472 ;
     RECT  76.115 39.888 76.349 40.344 ;
     RECT  75.521 50.064 76.381 50.088 ;
     RECT  76.205 20.016 76.385 20.04 ;
     RECT  76.205 21.072 76.429 21.096 ;
     RECT  74.905 37.584 76.453 37.608 ;
     RECT  75.923 46.752 76.489 46.824 ;
     RECT  75.913 47.808 76.489 47.832 ;
     RECT  75.557 18.192 76.525 18.216 ;
     RECT  76.417 41.376 76.54 41.544 ;
     RECT  76.201 22.416 76.561 23.976 ;
     RECT  76.525 18.192 76.597 18.744 ;
     RECT  75.701 30.816 76.633 32.088 ;
     RECT  76.025 51.744 76.669 54.984 ;
     RECT  76.633 30.624 76.739 32.088 ;
     RECT  76.561 22.416 76.813 24.696 ;
     RECT  76.813 22.416 76.885 25.272 ;
     RECT  76.453 37.104 76.931 37.608 ;
     RECT  76.381 49.2 76.931 50.088 ;
     RECT  76.739 30.816 76.961 32.088 ;
     RECT  76.489 46.752 76.961 47.832 ;
     RECT  76.961 46.752 76.997 46.776 ;
     RECT  76.931 49.248 76.997 50.088 ;
     RECT  76.961 47.808 77.033 47.832 ;
     RECT  74.437 2.736 77.173 7.224 ;
     RECT  75.953 8.256 77.173 11.784 ;
     RECT  77.173 2.736 77.209 11.784 ;
     RECT  76.259 13.296 77.209 13.32 ;
     RECT  76.061 15.504 77.209 15.528 ;
     RECT  76.669 51.12 77.209 54.984 ;
     RECT  76.273 55.968 77.209 62.472 ;
     RECT  75.193 27.312 77.281 29.544 ;
     RECT  77.245 16.848 77.317 16.872 ;
     RECT  76.885 22.272 77.317 25.272 ;
     RECT  76.525 26.304 77.317 26.328 ;
     RECT  77.317 22.272 77.425 26.328 ;
     RECT  77.281 27.312 77.425 29.592 ;
     RECT  76.961 31.104 77.569 32.088 ;
     RECT  77.317 16.848 77.785 17.112 ;
     RECT  76.597 18.192 77.785 18.792 ;
     RECT  77.209 2.736 78.008 13.32 ;
     RECT  77.209 15.36 78.008 15.528 ;
     RECT  77.785 16.848 78.008 18.792 ;
     RECT  77.425 22.272 78.008 29.592 ;
     RECT  77.569 31.104 78.008 32.328 ;
     RECT  77.281 33.552 78.008 33.576 ;
     RECT  76.931 37.104 78.008 37.128 ;
     RECT  77.965 38.688 78.008 38.712 ;
     RECT  76.349 39.888 78.008 39.912 ;
     RECT  76.54 41.52 78.008 41.544 ;
     RECT  76.069 43.152 78.008 44.088 ;
     RECT  77.125 45.6 78.008 45.624 ;
     RECT  76.997 49.248 78.008 49.272 ;
     RECT  77.209 51.12 78.008 62.472 ;
     RECT  78.008 2.148 78.112 62.652 ;
     RECT  78.112 2.418 78.304 62.472 ;
     RECT  78.304 31.104 78.437 32.328 ;
     RECT  78.304 48.384 78.437 48.456 ;
     RECT  78.304 19.344 78.48 29.832 ;
     RECT  78.304 34.992 78.509 35.88 ;
     RECT  78.509 35.856 78.515 35.88 ;
     RECT  78.437 31.104 78.581 31.752 ;
     RECT  78.437 48.432 78.581 48.456 ;
     RECT  78.304 43.296 78.617 44.088 ;
     RECT  78.304 51.12 78.617 51.144 ;
     RECT  78.304 38.16 78.797 40.056 ;
     RECT  78.304 37.056 79.085 37.128 ;
     RECT  78.304 52.176 79.085 58.68 ;
     RECT  79.085 52.176 79.265 58.008 ;
     RECT  78.304 2.784 79.301 7.224 ;
     RECT  78.304 50.112 79.337 50.136 ;
     RECT  78.48 20.832 79.481 29.832 ;
     RECT  78.304 15.504 79.513 16.104 ;
     RECT  78.304 17.136 79.513 18.216 ;
     RECT  79.481 24.48 79.517 29.832 ;
     RECT  78.304 8.256 79.549 14.472 ;
     RECT  79.513 15.504 79.549 18.216 ;
     RECT  78.617 43.296 79.549 43.32 ;
     RECT  78.797 38.4 79.573 40.056 ;
     RECT  79.517 24.912 79.583 29.832 ;
     RECT  78.581 31.104 79.583 31.704 ;
     RECT  79.573 38.4 79.661 40.296 ;
     RECT  79.621 32.736 79.801 32.76 ;
     RECT  79.085 37.104 79.801 37.128 ;
     RECT  79.661 38.4 79.801 40.056 ;
     RECT  79.265 55.968 79.805 58.008 ;
     RECT  79.583 24.912 79.811 31.704 ;
     RECT  79.549 42.72 79.909 43.32 ;
     RECT  79.549 8.256 80.021 18.216 ;
     RECT  78.48 19.344 80.021 19.368 ;
     RECT  79.481 20.832 80.021 23.352 ;
     RECT  79.801 37.104 80.053 40.056 ;
     RECT  80.021 20.832 80.057 21.192 ;
     RECT  79.801 51.072 80.089 51.096 ;
     RECT  79.265 52.176 80.089 54.936 ;
     RECT  79.805 56.016 80.129 58.008 ;
     RECT  79.811 31.104 80.197 31.704 ;
     RECT  79.801 32.736 80.197 33.048 ;
     RECT  79.909 42.672 80.197 43.32 ;
     RECT  80.089 51.072 80.273 54.936 ;
     RECT  79.811 24.912 80.309 29.832 ;
     RECT  78.304 60 80.309 62.472 ;
     RECT  80.197 42.48 80.381 43.32 ;
     RECT  80.053 37.056 80.387 40.056 ;
     RECT  80.197 31.104 80.389 33.048 ;
     RECT  79.621 34.128 80.417 34.152 ;
     RECT  80.387 37.248 80.417 40.056 ;
     RECT  80.129 56.016 80.417 56.808 ;
     RECT  80.417 38.352 80.435 40.056 ;
     RECT  80.057 21.12 80.489 21.192 ;
     RECT  80.273 51.12 80.489 54.936 ;
     RECT  80.129 57.84 80.521 58.008 ;
     RECT  80.021 15.792 80.533 18.216 ;
     RECT  80.489 21.168 80.561 21.192 ;
     RECT  80.557 48.864 80.629 48.888 ;
     RECT  80.489 51.12 80.633 52.296 ;
     RECT  80.521 57.84 80.665 58.824 ;
     RECT  80.533 15.792 80.741 18.792 ;
     RECT  80.435 38.352 80.777 39.288 ;
     RECT  80.381 42.672 80.777 43.32 ;
     RECT  79.301 3.552 80.881 7.224 ;
     RECT  80.021 8.256 80.881 14.808 ;
     RECT  80.389 31.104 80.885 32.088 ;
     RECT  80.629 48.816 80.953 48.888 ;
     RECT  80.881 3.552 80.957 14.808 ;
     RECT  80.417 56.256 80.957 56.808 ;
     RECT  80.309 60 81.029 61.368 ;
     RECT  80.161 45.024 81.097 45.048 ;
     RECT  81.097 45.024 81.137 45.624 ;
     RECT  80.309 24.96 81.169 29.832 ;
     RECT  80.953 48.816 81.313 49.512 ;
     RECT  80.417 37.248 81.389 37.272 ;
     RECT  80.021 22.56 81.421 23.352 ;
     RECT  81.169 24.96 81.421 30.12 ;
     RECT  80.777 38.352 81.422 38.712 ;
     RECT  81.313 48.288 81.457 49.512 ;
     RECT  80.957 3.552 81.461 14.424 ;
     RECT  81.397 46.752 81.484 46.776 ;
     RECT  80.633 51.12 81.565 52.2 ;
     RECT  81.457 48.192 81.601 49.512 ;
     RECT  81.422 38.4 81.605 38.712 ;
     RECT  81.565 51.072 81.637 52.2 ;
     RECT  80.489 53.328 81.637 54.936 ;
     RECT  80.741 17.616 81.641 18.792 ;
     RECT  81.641 18.768 81.673 18.792 ;
     RECT  79.765 35.952 81.709 35.976 ;
     RECT  81.673 18.768 81.713 19.368 ;
     RECT  81.137 45.6 81.713 45.624 ;
     RECT  80.665 57.84 81.745 58.92 ;
     RECT  81.029 60.384 81.745 61.368 ;
     RECT  81.601 48.192 81.785 49.8 ;
     RECT  80.885 31.104 81.853 31.704 ;
     RECT  81.853 31.104 81.961 31.752 ;
     RECT  81.421 22.56 81.965 30.12 ;
     RECT  81.965 22.56 82.021 24.648 ;
     RECT  81.745 60.384 82.037 61.464 ;
     RECT  81.713 18.912 82.067 19.368 ;
     RECT  80.741 15.792 82.069 16.392 ;
     RECT  81.641 17.616 82.069 17.64 ;
     RECT  81.961 31.104 82.069 31.8 ;
     RECT  80.557 33.648 82.069 33.672 ;
     RECT  81.637 51.072 82.097 54.936 ;
     RECT  82.097 51.072 82.124 55.32 ;
     RECT  80.957 56.304 82.124 56.808 ;
     RECT  82.124 51.072 82.141 56.808 ;
     RECT  81.745 57.84 82.141 59.064 ;
     RECT  82.021 22.032 82.145 24.648 ;
     RECT  81.965 25.68 82.145 30.12 ;
     RECT  82.141 51.072 82.165 59.064 ;
     RECT  82.165 51.072 82.177 59.304 ;
     RECT  82.177 50.832 82.181 59.304 ;
     RECT  82.037 60.624 82.217 61.464 ;
     RECT  81.785 48.288 82.249 49.8 ;
     RECT  82.181 50.832 82.249 51.384 ;
     RECT  82.217 60.624 82.289 60.648 ;
     RECT  81.461 11.952 82.393 14.424 ;
     RECT  82.069 15.792 82.501 17.64 ;
     RECT  82.069 31.104 82.609 33.672 ;
     RECT  82.364 34.752 82.609 34.776 ;
     RECT  81.461 3.552 82.645 10.872 ;
     RECT  82.249 48.288 83.005 51.384 ;
     RECT  82.501 20.592 83.041 20.616 ;
     RECT  82.145 22.032 83.221 24.024 ;
     RECT  82.145 25.68 83.221 29.64 ;
     RECT  80.777 43.296 83.221 43.32 ;
     RECT  83.221 21.984 83.249 24.024 ;
     RECT  83.221 25.104 83.249 29.64 ;
     RECT  83.249 21.984 83.329 29.64 ;
     RECT  82.645 3.552 83.408 10.968 ;
     RECT  82.393 11.952 83.408 14.472 ;
     RECT  82.501 15.552 83.408 17.64 ;
     RECT  82.067 18.912 83.408 18.936 ;
     RECT  83.041 20.112 83.408 20.616 ;
     RECT  83.329 21.984 83.408 30.072 ;
     RECT  82.609 31.104 83.408 34.776 ;
     RECT  81.709 35.904 83.408 35.976 ;
     RECT  81.605 38.4 83.408 38.424 ;
     RECT  83.185 41.424 83.408 41.448 ;
     RECT  83.221 43.296 83.408 43.896 ;
     RECT  83.005 46.896 83.408 46.92 ;
     RECT  83.005 48.144 83.408 51.384 ;
     RECT  82.181 52.56 83.408 54.696 ;
     RECT  82.181 55.68 83.408 59.304 ;
     RECT  80.309 62.448 83.408 62.472 ;
     RECT  83.408 2.148 83.512 62.652 ;
     RECT  83.512 2.418 83.704 62.472 ;
     RECT  83.704 57.312 83.765 59.304 ;
     RECT  83.704 41.424 83.837 41.448 ;
     RECT  83.704 20.016 83.873 34.968 ;
     RECT  83.873 23.952 83.909 34.968 ;
     RECT  83.704 48.144 83.909 51.24 ;
     RECT  83.765 57.984 83.909 59.304 ;
     RECT  83.909 32.304 83.939 34.968 ;
     RECT  83.704 3.552 83.945 9.336 ;
     RECT  83.909 23.952 83.981 30.984 ;
     RECT  83.909 48.96 83.981 51.24 ;
     RECT  83.981 25.488 83.987 30.984 ;
     RECT  83.939 32.304 83.987 34.152 ;
     RECT  83.873 20.016 84.089 22.824 ;
     RECT  83.987 25.488 84.125 29.592 ;
     RECT  83.987 30.72 84.233 30.744 ;
     RECT  83.704 52.464 84.233 53.352 ;
     RECT  83.987 33.312 84.305 34.152 ;
     RECT  83.704 60.72 84.371 61.416 ;
     RECT  83.704 62.448 84.371 62.472 ;
     RECT  83.704 43.296 84.413 43.896 ;
     RECT  83.981 48.96 84.413 50.04 ;
     RECT  84.371 61.008 84.413 61.416 ;
     RECT  83.704 10.896 84.449 14.424 ;
     RECT  84.449 12.096 84.485 14.424 ;
     RECT  83.981 23.952 84.485 24.216 ;
     RECT  83.704 36.48 84.485 36.504 ;
     RECT  83.981 51.216 84.521 51.24 ;
     RECT  83.704 15.504 84.557 18.984 ;
     RECT  84.125 25.488 84.629 29.112 ;
     RECT  84.233 52.464 84.629 52.584 ;
     RECT  84.629 25.488 84.673 28.536 ;
     RECT  84.485 12.096 84.737 14.376 ;
     RECT  84.485 23.952 84.737 23.976 ;
     RECT  84.557 16.272 84.773 18.984 ;
     RECT  84.413 49.104 84.773 50.04 ;
     RECT  83.704 46.896 84.913 46.92 ;
     RECT  84.805 10.656 84.953 10.68 ;
     RECT  84.305 33.312 84.953 33.816 ;
     RECT  84.913 46.752 84.997 46.92 ;
     RECT  84.773 49.728 85.025 50.04 ;
     RECT  85.025 49.728 85.061 49.896 ;
     RECT  84.089 20.016 85.205 20.136 ;
     RECT  83.704 55.68 85.265 55.704 ;
     RECT  85.205 20.112 85.277 20.136 ;
     RECT  84.089 21.12 85.277 22.824 ;
     RECT  85.277 21.12 85.345 21.48 ;
     RECT  85.265 54.72 85.349 55.704 ;
     RECT  85.285 53.472 85.372 53.496 ;
     RECT  84.737 12.096 85.601 13.32 ;
     RECT  83.909 58.08 85.605 58.152 ;
     RECT  83.909 59.28 85.605 59.304 ;
     RECT  83.945 3.552 85.673 9.048 ;
     RECT  84.413 43.296 85.697 43.416 ;
     RECT  84.997 46.896 85.705 46.92 ;
     RECT  84.673 25.488 85.709 28.488 ;
     RECT  85.605 58.08 85.717 59.304 ;
     RECT  85.601 12.096 85.745 12.12 ;
     RECT  85.061 49.728 85.745 49.752 ;
     RECT  85.717 57.456 85.763 59.304 ;
     RECT  85.277 22.8 85.777 22.824 ;
     RECT  85.489 24 85.777 24.024 ;
     RECT  85.345 20.352 85.781 21.48 ;
     RECT  83.704 45.6 85.889 45.624 ;
     RECT  84.773 16.272 85.925 18.6 ;
     RECT  85.705 46.896 85.957 47.256 ;
     RECT  85.709 25.488 85.961 28.392 ;
     RECT  85.916 49.68 86.003 49.704 ;
     RECT  84.629 52.464 86.003 52.488 ;
     RECT  85.781 20.352 86.033 20.712 ;
     RECT  85.673 3.552 86.069 8.808 ;
     RECT  86.033 20.592 86.069 20.712 ;
     RECT  85.763 57.456 86.105 58.152 ;
     RECT  85.763 59.28 86.105 59.304 ;
     RECT  84.413 61.008 86.105 61.032 ;
     RECT  85.717 35.424 86.141 35.448 ;
     RECT  85.961 25.536 86.213 28.392 ;
     RECT  85.957 46.896 86.357 47.88 ;
     RECT  85.601 13.296 86.393 13.32 ;
     RECT  85.697 43.296 86.396 43.944 ;
     RECT  86.357 46.896 86.429 46.92 ;
     RECT  86.396 42.72 86.483 44.088 ;
     RECT  86.213 25.728 86.537 28.392 ;
     RECT  86.537 25.728 86.573 27.192 ;
     RECT  86.069 5.712 86.609 8.808 ;
     RECT  86.069 20.592 86.609 20.616 ;
     RECT  85.777 22.8 86.677 24.024 ;
     RECT  85.957 37.008 86.681 37.032 ;
     RECT  86.069 3.552 86.717 4.44 ;
     RECT  86.573 25.728 86.717 26.856 ;
     RECT  86.483 43.68 86.717 43.704 ;
     RECT  86.677 22.752 86.789 24.024 ;
     RECT  86.717 26.64 86.789 26.856 ;
     RECT  84.737 14.352 86.825 14.376 ;
     RECT  85.925 16.272 86.825 17.64 ;
     RECT  86.537 28.368 86.825 28.392 ;
     RECT  85.669 30.432 86.825 30.456 ;
     RECT  86.641 51.072 86.857 51.096 ;
     RECT  86.789 23.04 86.861 24.024 ;
     RECT  86.893 34.8 86.977 34.824 ;
     RECT  87.001 18.72 87.107 18.744 ;
     RECT  87.061 21.36 87.149 21.384 ;
     RECT  85.349 55.68 87.149 55.704 ;
     RECT  86.105 57.456 87.149 57.48 ;
     RECT  86.861 23.04 87.185 23.064 ;
     RECT  86.717 3.552 87.293 3.576 ;
     RECT  86.857 50.352 87.293 51.096 ;
     RECT  86.609 5.712 87.329 8.52 ;
     RECT  86.825 17.616 87.365 17.64 ;
     RECT  86.965 40.8 87.365 40.824 ;
     RECT  86.789 26.832 87.437 26.856 ;
     RECT  86.825 16.272 87.509 16.296 ;
     RECT  84.953 33.792 87.509 33.816 ;
     RECT  87.329 5.712 87.617 8.424 ;
     RECT  87.617 5.904 87.689 8.424 ;
     RECT  87.689 6.816 87.833 8.424 ;
     RECT  87.293 50.352 87.977 50.376 ;
     RECT  88.261 38.736 88.373 38.76 ;
     RECT  87.833 8.112 88.445 8.136 ;
     RECT  87.833 6.816 88.837 6.84 ;
     RECT  88.837 6.72 88.873 6.84 ;
     RECT  88.837 9.216 88.873 9.24 ;
     RECT  88.873 5.28 88.909 5.304 ;
     RECT  88.873 6.432 88.909 8.088 ;
     RECT  88.909 5.28 90.025 8.088 ;
     RECT  90.025 5.184 90.601 8.088 ;
     RECT  90.601 5.088 90.684 8.088 ;
     RECT  88.873 9.12 90.684 9.24 ;
    LAYER M5 ;
     RECT  8.064 0.016 11.064 0.085 ;
     RECT  12.096 0.016 15.096 0.085 ;
     RECT  4.032 0.016 7.032 0.181 ;
     RECT  8.064 0.085 15.096 0.181 ;
     RECT  16.128 0.016 19.128 0.181 ;
     RECT  4.032 0.181 7.08 0.277 ;
     RECT  8.064 0.181 19.128 0.277 ;
     RECT  4.032 0.277 19.128 0.565 ;
     RECT  4.032 0.565 19.368 1.763 ;
     RECT  2.4 2.137 2.52 2.151 ;
     RECT  24 2.137 24.12 2.151 ;
     RECT  29.4 2.137 29.52 2.151 ;
     RECT  34.8 2.137 34.92 2.151 ;
     RECT  40.2 2.137 40.32 2.151 ;
     RECT  45.6 2.137 45.72 2.151 ;
     RECT  51 2.137 51.12 2.151 ;
     RECT  56.4 2.137 56.52 2.151 ;
     RECT  61.8 2.137 61.92 2.151 ;
     RECT  67.2 2.137 67.32 2.151 ;
     RECT  72.6 2.137 72.72 2.151 ;
     RECT  78 2.137 78.12 2.151 ;
     RECT  83.4 2.137 83.52 2.151 ;
     RECT  2.4 2.151 2.712 2.245 ;
     RECT  4.224 1.763 19.368 2.291 ;
     RECT  45.6 2.151 45.912 2.485 ;
     RECT  22.992 2.485 23.016 2.581 ;
     RECT  24 2.151 24.312 2.581 ;
     RECT  22.992 2.581 24.312 2.629 ;
     RECT  61.8 2.151 62.112 2.725 ;
     RECT  4.224 2.291 4.248 2.867 ;
     RECT  45.6 2.485 46.488 2.867 ;
     RECT  54.96 3.061 54.984 3.395 ;
     RECT  22.896 2.629 24.312 3.397 ;
     RECT  43.776 3.301 43.8 3.443 ;
     RECT  61.8 2.725 62.232 3.539 ;
     RECT  25.392 2.485 25.416 3.731 ;
     RECT  70.128 2.725 70.152 3.827 ;
     RECT  5.76 2.291 19.368 3.925 ;
     RECT  22.8 3.397 24.312 4.019 ;
     RECT  5.472 3.925 19.368 4.453 ;
     RECT  83.4 2.151 83.712 4.501 ;
     RECT  5.472 4.453 19.416 4.835 ;
     RECT  4.224 4.357 4.248 4.981 ;
     RECT  5.472 4.835 5.496 4.981 ;
     RECT  83.4 4.501 84.216 4.981 ;
     RECT  27.792 4.837 27.816 5.077 ;
     RECT  42.432 2.677 42.456 5.125 ;
     RECT  45.6 2.867 45.912 5.125 ;
     RECT  47.712 3.925 47.736 5.125 ;
     RECT  22.848 4.019 24.312 5.171 ;
     RECT  74.064 4.501 74.088 5.171 ;
     RECT  34.8 2.151 35.112 5.173 ;
     RECT  6.768 4.835 19.416 5.219 ;
     RECT  33.6 5.077 33.624 5.269 ;
     RECT  42.144 5.125 42.456 5.269 ;
     RECT  38.256 5.125 38.28 5.315 ;
     RECT  47.568 5.125 47.736 5.363 ;
     RECT  33.072 5.269 33.624 5.509 ;
     RECT  34.8 5.173 35.208 5.509 ;
     RECT  2.4 2.245 3 5.557 ;
     RECT  4.224 4.981 5.496 5.557 ;
     RECT  31.392 4.501 31.416 5.557 ;
     RECT  41.712 5.269 42.456 5.603 ;
     RECT  72.6 2.151 72.912 5.605 ;
     RECT  7.44 5.219 19.416 5.747 ;
     RECT  26.976 5.077 27.816 5.747 ;
     RECT  48.768 3.061 48.792 5.747 ;
     RECT  83.28 4.981 84.216 5.747 ;
     RECT  85.392 5.077 85.416 5.747 ;
     RECT  7.536 5.747 19.416 5.795 ;
     RECT  7.8 5.795 19.416 5.891 ;
     RECT  45.312 5.125 45.912 6.037 ;
     RECT  31.392 5.557 31.944 6.085 ;
     RECT  51 2.151 51.312 6.085 ;
     RECT  47.712 5.363 47.736 6.275 ;
     RECT  71.664 5.605 72.912 6.275 ;
     RECT  2.4 5.557 5.496 6.277 ;
     RECT  7.8 5.891 14.952 6.323 ;
     RECT  15.936 5.891 19.416 6.323 ;
     RECT  21.264 5.605 21.288 6.323 ;
     RECT  7.8 6.323 9.384 6.371 ;
     RECT  42.144 5.603 42.456 6.563 ;
     RECT  2.4 6.277 5.784 6.709 ;
     RECT  51 6.085 51.576 6.709 ;
     RECT  11.664 6.323 14.952 6.853 ;
     RECT  10.464 6.323 10.68 6.899 ;
     RECT  11.664 6.853 15 6.899 ;
     RECT  33.072 5.509 35.208 6.947 ;
     RECT  13.104 6.899 15 7.139 ;
     RECT  80.928 6.901 80.952 7.139 ;
     RECT  33.072 6.947 35.112 7.187 ;
     RECT  36.672 5.653 36.696 7.187 ;
     RECT  16.704 6.323 19.416 7.189 ;
     RECT  22.992 5.171 24.312 7.285 ;
     RECT  2.4 6.709 6.648 7.379 ;
     RECT  83.4 5.747 84.216 7.381 ;
     RECT  42.432 6.563 42.456 7.427 ;
     RECT  13.2 7.139 15 7.475 ;
     RECT  16.704 7.189 19.8 7.475 ;
     RECT  16.752 7.475 19.8 7.571 ;
     RECT  2.4 7.379 5.496 7.619 ;
     RECT  33.072 7.187 33.384 7.619 ;
     RECT  54.672 5.077 54.696 7.619 ;
     RECT  26.976 5.747 27 7.669 ;
     RECT  28.08 6.709 28.104 7.669 ;
     RECT  67.2 2.151 67.512 7.765 ;
     RECT  10.656 6.899 10.68 7.957 ;
     RECT  83.4 7.381 84.696 7.957 ;
     RECT  14.88 7.475 15 8.003 ;
     RECT  17.28 7.571 19.8 8.003 ;
     RECT  83.184 7.957 84.696 8.003 ;
     RECT  7.8 6.371 8.424 8.005 ;
     RECT  14.976 8.003 15 8.147 ;
     RECT  13.2 7.475 13.512 8.197 ;
     RECT  13.056 8.197 13.512 8.339 ;
     RECT  83.184 8.003 84.216 8.435 ;
     RECT  61.8 3.539 62.112 8.485 ;
     RECT  83.184 8.435 84.168 8.485 ;
     RECT  72.432 6.275 72.912 8.579 ;
     RECT  86.016 7.909 86.04 8.579 ;
     RECT  33.36 7.619 33.384 8.629 ;
     RECT  2.4 7.619 2.712 8.677 ;
     RECT  6.624 7.379 6.648 8.773 ;
     RECT  7.8 8.005 9.144 8.773 ;
     RECT  26.976 7.669 28.104 8.821 ;
     RECT  2.4 8.677 2.856 8.869 ;
     RECT  3.888 7.619 5.496 8.869 ;
     RECT  46.944 7.381 46.968 8.963 ;
     RECT  31.008 6.085 31.944 8.965 ;
     RECT  33.072 8.629 33.384 8.965 ;
     RECT  82.8 8.485 84.168 9.011 ;
     RECT  0.192 4.021 0.216 9.061 ;
     RECT  22.896 7.285 24.312 9.443 ;
     RECT  2.4 8.869 5.496 9.541 ;
     RECT  6.624 8.773 9.144 9.541 ;
     RECT  26.976 8.821 28.248 9.731 ;
     RECT  13.2 8.339 13.512 9.733 ;
     RECT  10.368 7.957 10.68 9.779 ;
     RECT  26.976 9.731 27.96 9.827 ;
     RECT  2.4 9.541 9.144 9.875 ;
     RECT  17.904 8.003 19.8 9.875 ;
     RECT  22.992 9.443 24.312 9.877 ;
     RECT  44.928 6.037 45.912 10.067 ;
     RECT  12.144 9.877 12.168 10.165 ;
     RECT  22.992 9.877 24.648 10.211 ;
     RECT  50.208 6.709 51.576 10.357 ;
     RECT  66.336 7.765 67.512 10.549 ;
     RECT  65.472 10.549 67.512 10.595 ;
     RECT  7.68 9.875 9.144 10.597 ;
     RECT  10.368 9.779 10.392 10.597 ;
     RECT  50.16 10.357 51.576 10.837 ;
     RECT  13.2 9.733 13.608 10.931 ;
     RECT  83.4 9.011 84.168 10.979 ;
     RECT  25.824 10.213 25.848 10.981 ;
     RECT  25.728 10.981 25.848 11.027 ;
     RECT  7.68 10.597 10.392 11.077 ;
     RECT  2.4 9.875 6.648 11.221 ;
     RECT  7.68 11.077 10.92 11.221 ;
     RECT  47.328 9.781 47.352 11.269 ;
     RECT  2.4 11.221 10.92 11.365 ;
     RECT  12.048 10.165 12.168 11.365 ;
     RECT  13.2 10.931 13.512 11.365 ;
     RECT  50.16 10.837 52.392 11.411 ;
     RECT  0.192 9.061 0.312 11.459 ;
     RECT  18.6 9.875 19.8 11.459 ;
     RECT  21.072 10.117 21.096 11.459 ;
     RECT  27.216 9.827 27.96 11.459 ;
     RECT  59.424 7.909 59.448 11.459 ;
     RECT  65.472 10.595 65.496 11.459 ;
     RECT  2.4 11.365 13.512 11.507 ;
     RECT  50.16 11.411 51.576 11.699 ;
     RECT  11.616 11.507 13.512 11.941 ;
     RECT  29.4 2.151 29.712 11.941 ;
     RECT  45.6 10.067 45.912 11.941 ;
     RECT  47.328 11.269 47.4 11.987 ;
     RECT  2.4 11.507 9.96 12.035 ;
     RECT  25.728 11.027 25.752 12.035 ;
     RECT  31.008 8.965 33.384 12.035 ;
     RECT  37.008 10.645 37.032 12.037 ;
     RECT  45.504 11.941 45.912 12.181 ;
     RECT  15.6 9.349 15.624 12.275 ;
     RECT  22.992 10.211 24.312 12.325 ;
     RECT  27.216 11.459 27.912 12.421 ;
     RECT  29.04 11.941 29.712 12.421 ;
     RECT  11.616 11.941 14.424 12.805 ;
     RECT  11.616 12.805 14.568 12.851 ;
     RECT  51 11.699 51.576 12.899 ;
     RECT  7.8 12.035 9.144 12.995 ;
     RECT  56.4 2.151 56.712 12.997 ;
     RECT  39.024 11.797 39.048 13.091 ;
     RECT  41.616 11.941 41.64 13.091 ;
     RECT  45.024 12.181 45.912 13.523 ;
     RECT  72.48 8.579 72.912 13.525 ;
     RECT  18.6 11.459 18.912 13.573 ;
     RECT  12.336 12.851 14.568 13.619 ;
     RECT  12.528 13.619 14.568 13.667 ;
     RECT  20.016 12.997 20.04 13.667 ;
     RECT  12.528 13.667 13.656 13.715 ;
     RECT  61.8 8.485 62.424 13.715 ;
     RECT  72.48 13.525 73.512 13.907 ;
     RECT  51 12.899 51.528 14.099 ;
     RECT  0.192 11.459 0.216 14.101 ;
     RECT  7.8 12.995 8.52 14.195 ;
     RECT  2.4 12.035 6.744 14.197 ;
     RECT  7.8 14.195 8.232 14.197 ;
     RECT  18.048 13.573 18.912 14.197 ;
     RECT  27.216 12.421 29.712 14.197 ;
     RECT  55.92 12.997 56.712 14.197 ;
     RECT  61.8 13.715 62.232 14.245 ;
     RECT  31.008 12.035 32.184 14.291 ;
     RECT  12.528 13.715 13.512 14.387 ;
     RECT  43.152 13.045 43.176 14.387 ;
     RECT  2.4 14.197 8.232 14.435 ;
     RECT  43.2 14.725 43.224 14.867 ;
     RECT  27.216 14.197 29.832 15.301 ;
     RECT  31.008 14.291 31.8 15.301 ;
     RECT  47.376 11.987 47.4 15.301 ;
     RECT  37.008 12.037 37.992 15.349 ;
     RECT  2.4 14.435 8.112 15.397 ;
     RECT  47.376 15.301 47.496 15.443 ;
     RECT  61.68 14.245 62.232 15.443 ;
     RECT  18.048 14.197 19.656 15.445 ;
     RECT  76.224 14.149 76.248 15.539 ;
     RECT  17.664 15.445 19.656 15.587 ;
     RECT  10.608 15.445 10.632 15.637 ;
     RECT  10.608 15.637 11.496 15.779 ;
     RECT  27.216 15.301 31.8 15.827 ;
     RECT  51 14.099 51.432 15.829 ;
     RECT  20.976 15.637 21 15.875 ;
     RECT  33.36 12.035 33.384 15.925 ;
     RECT  34.464 7.187 35.112 15.925 ;
     RECT  2.4 15.397 8.616 16.067 ;
     RECT  12.768 14.387 13.512 16.069 ;
     RECT  37.008 15.349 38.184 16.211 ;
     RECT  2.4 16.067 8.112 16.307 ;
     RECT  27.216 15.827 29.832 16.307 ;
     RECT  37.008 16.211 38.088 16.307 ;
     RECT  22.8 12.325 24.312 16.355 ;
     RECT  7.344 16.307 8.112 16.403 ;
     RECT  71.184 15.973 71.208 16.405 ;
     RECT  72.48 13.907 72.912 16.405 ;
     RECT  37.008 16.307 37.032 16.453 ;
     RECT  31.008 15.827 31.8 16.501 ;
     RECT  0.192 14.101 0.408 16.547 ;
     RECT  17.664 15.587 19.032 16.547 ;
     RECT  2.4 16.307 6.36 16.595 ;
     RECT  10.608 15.779 10.632 16.595 ;
     RECT  45.36 13.523 45.912 16.643 ;
     RECT  0.192 16.547 0.36 16.691 ;
     RECT  17.664 16.547 18.912 16.691 ;
     RECT  59.808 15.349 59.832 16.787 ;
     RECT  0.192 16.691 0.312 16.931 ;
     RECT  10.512 16.837 10.536 17.075 ;
     RECT  83.4 10.979 83.712 17.077 ;
     RECT  9.12 16.981 9.144 17.123 ;
     RECT  27.216 16.307 29.712 17.123 ;
     RECT  31.008 16.501 31.896 17.123 ;
     RECT  51 15.829 51.768 17.123 ;
     RECT  2.4 16.595 5.016 17.171 ;
     RECT  15.936 12.613 15.96 17.171 ;
     RECT  71.184 16.405 72.912 17.171 ;
     RECT  82.608 17.077 83.712 17.555 ;
     RECT  72.144 17.171 72.912 17.651 ;
     RECT  61.8 15.443 62.232 17.699 ;
     RECT  63.312 15.925 63.336 17.699 ;
     RECT  33.36 15.925 35.112 17.891 ;
     RECT  36.816 16.453 37.032 17.893 ;
     RECT  38.064 16.307 38.088 17.893 ;
     RECT  36.816 17.893 38.088 18.037 ;
     RECT  31.008 17.123 31.032 18.133 ;
     RECT  36.816 18.037 38.184 18.179 ;
     RECT  51 17.123 51.312 18.229 ;
     RECT  74.592 11.365 74.616 18.517 ;
     RECT  80.544 18.181 80.568 18.803 ;
     RECT  3.792 17.171 5.016 18.851 ;
     RECT  72.24 17.651 72.912 19.379 ;
     RECT  4.128 18.851 5.016 19.381 ;
     RECT  66.096 18.709 66.12 19.427 ;
     RECT  51 18.229 51.912 19.523 ;
     RECT  4.128 19.381 5.112 20.003 ;
     RECT  6.336 16.595 6.36 20.003 ;
     RECT  27.216 17.123 28.104 20.003 ;
     RECT  12.768 16.069 13.944 20.005 ;
     RECT  16.992 19.333 17.016 20.051 ;
     RECT  74.544 18.517 74.616 20.051 ;
     RECT  78 2.151 78.312 20.149 ;
     RECT  5.088 20.003 5.112 20.291 ;
     RECT  12.768 20.005 14.088 20.389 ;
     RECT  37.008 18.179 38.184 20.533 ;
     RECT  31.008 18.133 31.848 20.579 ;
     RECT  55.872 14.197 56.712 20.771 ;
     RECT  56.112 20.771 56.712 20.965 ;
     RECT  58.512 18.517 58.536 20.965 ;
     RECT  29.4 17.123 29.712 21.013 ;
     RECT  31.008 20.579 31.032 21.013 ;
     RECT  37.008 20.533 38.664 21.061 ;
     RECT  64.704 20.533 64.728 21.061 ;
     RECT  9.36 20.965 9.384 21.107 ;
     RECT  87.072 18.709 87.096 21.395 ;
     RECT  25.632 19.909 25.656 21.443 ;
     RECT  56.112 20.965 58.536 21.539 ;
     RECT  74.592 20.051 74.616 21.541 ;
     RECT  76.368 21.061 76.392 21.541 ;
     RECT  67.2 10.595 67.512 21.637 ;
     RECT  5.28 20.677 5.304 21.683 ;
     RECT  36.096 21.061 38.664 21.683 ;
     RECT  63.936 21.061 64.728 21.683 ;
     RECT  36.096 21.683 37.656 21.779 ;
     RECT  78 20.149 78.408 21.971 ;
     RECT  83.4 17.555 83.712 22.021 ;
     RECT  33.36 17.891 33.384 22.165 ;
     RECT  34.464 17.891 35.112 22.165 ;
     RECT  26.784 20.869 26.808 22.211 ;
     RECT  56.112 21.539 58.152 22.259 ;
     RECT  11.376 21.637 11.4 22.451 ;
     RECT  74.592 21.541 76.392 22.451 ;
     RECT  33.36 22.165 35.112 22.453 ;
     RECT  36.096 21.779 37.032 22.453 ;
     RECT  38.64 21.683 38.664 22.691 ;
     RECT  7.8 16.403 8.112 22.741 ;
     RECT  66.672 21.637 67.512 22.741 ;
     RECT  72.6 19.379 72.912 22.837 ;
     RECT  66.672 22.741 68.232 22.883 ;
     RECT  61.8 17.699 62.112 23.029 ;
     RECT  33.36 22.453 37.032 23.123 ;
     RECT  9.264 22.165 9.288 23.171 ;
     RECT  74.592 22.451 75.432 23.267 ;
     RECT  72.6 22.837 73.032 23.269 ;
     RECT  75.408 23.267 75.432 23.315 ;
     RECT  82.032 19.333 82.056 23.315 ;
     RECT  83.4 22.021 84.648 23.317 ;
     RECT  60.432 22.165 60.456 23.363 ;
     RECT  61.8 23.029 62.856 23.363 ;
     RECT  7.44 22.741 8.112 23.699 ;
     RECT  22.992 16.355 24.312 23.941 ;
     RECT  28.08 20.003 28.104 24.085 ;
     RECT  29.4 21.013 31.032 24.085 ;
     RECT  21.12 23.941 21.144 24.131 ;
     RECT  22.992 23.941 24.456 24.131 ;
     RECT  28.08 24.085 31.032 24.131 ;
     RECT  72.144 23.269 73.032 24.131 ;
     RECT  28.464 24.131 31.032 24.323 ;
     RECT  48.432 23.269 48.456 24.371 ;
     RECT  56.112 22.259 56.712 24.563 ;
     RECT  61.8 23.363 62.76 24.563 ;
     RECT  66.72 22.883 68.232 24.563 ;
     RECT  58.128 22.259 58.152 24.659 ;
     RECT  40.2 2.151 40.512 24.661 ;
     RECT  33.36 23.123 33.384 24.709 ;
     RECT  5.04 23.845 5.064 24.899 ;
     RECT  67.2 24.563 68.232 24.899 ;
     RECT  78 21.971 78.312 24.901 ;
     RECT  34.464 23.123 37.032 25.045 ;
     RECT  83.232 23.317 84.648 25.139 ;
     RECT  28.464 24.323 29.928 25.235 ;
     RECT  2.4 17.171 2.712 25.573 ;
     RECT  61.8 24.563 62.112 25.573 ;
     RECT  34.464 25.045 37.08 25.621 ;
     RECT  55.152 24.613 55.176 25.621 ;
     RECT  83.28 25.139 84.648 25.715 ;
     RECT  83.4 25.715 84.648 26.005 ;
     RECT  67.2 24.899 68.088 26.099 ;
     RECT  78 24.901 78.696 26.101 ;
     RECT  31.008 24.323 31.032 26.197 ;
     RECT  32.208 25.285 32.232 26.197 ;
     RECT  45.6 16.643 45.912 26.245 ;
     RECT  61.68 25.573 62.112 26.387 ;
     RECT  2.4 25.573 3.192 26.437 ;
     RECT  39.36 24.661 40.512 26.579 ;
     RECT  80.928 26.581 80.952 26.723 ;
     RECT  31.008 26.197 32.232 26.771 ;
     RECT  58.128 26.197 58.152 26.771 ;
     RECT  12.768 20.389 14.136 26.819 ;
     RECT  42.432 26.101 42.456 26.867 ;
     RECT  51 19.523 51.312 27.061 ;
     RECT  13.104 26.819 14.136 27.107 ;
     RECT  39.936 26.579 40.512 27.107 ;
     RECT  61.8 26.387 62.112 27.157 ;
     RECT  45.6 26.245 46.584 27.299 ;
     RECT  43.92 25.621 43.944 27.347 ;
     RECT  34.464 25.621 37.8 27.395 ;
     RECT  47.856 26.485 47.88 27.395 ;
     RECT  72.144 24.131 72.912 27.395 ;
     RECT  83.4 26.005 85.512 27.395 ;
     RECT  33.36 24.709 33.432 27.445 ;
     RECT  34.464 27.395 37.032 27.445 ;
     RECT  13.104 27.107 13.512 27.635 ;
     RECT  64.704 21.683 64.728 27.781 ;
     RECT  26.064 24.373 26.088 27.877 ;
     RECT  53.472 26.293 53.496 27.877 ;
     RECT  2.4 26.437 3.336 27.971 ;
     RECT  68.928 27.301 68.952 27.971 ;
     RECT  6.432 23.317 6.456 28.117 ;
     RECT  7.8 23.699 8.112 28.117 ;
     RECT  6.432 28.117 8.112 28.163 ;
     RECT  11.376 27.301 11.4 28.163 ;
     RECT  78 26.101 78.792 28.163 ;
     RECT  82.272 27.973 82.296 28.211 ;
     RECT  86.592 26.821 86.616 28.403 ;
     RECT  45.6 27.299 45.912 28.453 ;
     RECT  72.384 27.395 72.912 28.453 ;
     RECT  33.36 27.445 37.032 28.499 ;
     RECT  83.4 27.395 84.648 28.547 ;
     RECT  55.152 25.621 55.32 28.693 ;
     RECT  31.008 26.771 31.032 28.789 ;
     RECT  64.416 27.781 64.728 28.837 ;
     RECT  64.416 28.837 65.112 28.883 ;
     RECT  61.8 27.157 62.472 28.931 ;
     RECT  45.6 28.453 46.776 29.029 ;
     RECT  54.576 28.693 55.32 29.029 ;
     RECT  56.4 24.563 56.712 29.029 ;
     RECT  45.504 29.029 46.776 29.075 ;
     RECT  25.968 27.877 26.088 29.509 ;
     RECT  25.968 29.509 26.232 29.555 ;
     RECT  59.28 28.789 59.304 29.605 ;
     RECT  59.28 29.605 59.832 29.651 ;
     RECT  16.56 27.061 16.584 29.699 ;
     RECT  45.504 29.075 46.008 29.795 ;
     RECT  53.232 27.877 53.496 29.795 ;
     RECT  64.704 28.883 65.112 29.795 ;
     RECT  72.384 28.453 73.8 29.795 ;
     RECT  78 28.163 78.312 29.797 ;
     RECT  31.008 28.789 31.08 29.845 ;
     RECT  45.6 29.795 46.008 29.891 ;
     RECT  48.288 28.501 48.312 30.035 ;
     RECT  83.4 28.547 83.712 30.037 ;
     RECT  79.776 29.029 79.8 30.229 ;
     RECT  79.632 30.229 79.8 30.275 ;
     RECT  21.312 29.653 21.336 30.323 ;
     RECT  7.2 28.163 8.112 30.661 ;
     RECT  22.992 24.131 24.312 30.709 ;
     RECT  40.2 27.107 40.512 30.709 ;
     RECT  43.632 29.797 43.656 30.709 ;
     RECT  50.112 27.061 51.312 30.709 ;
     RECT  6.912 30.661 8.112 30.803 ;
     RECT  26.064 29.555 26.232 30.851 ;
     RECT  43.392 30.709 43.656 30.853 ;
     RECT  61.8 28.931 62.112 30.853 ;
     RECT  39.792 30.709 40.512 30.899 ;
     RECT  76.704 30.613 76.728 31.139 ;
     RECT  30.96 29.845 31.08 31.331 ;
     RECT  75.216 28.309 75.24 31.331 ;
     RECT  16.608 29.941 16.632 31.333 ;
     RECT  50.112 30.709 51.96 31.333 ;
     RECT  22.8 30.709 24.312 31.379 ;
     RECT  59.808 29.651 59.832 31.379 ;
     RECT  7.2 30.803 8.112 31.381 ;
     RECT  29.4 25.235 29.928 31.427 ;
     RECT  34.464 28.499 37.032 31.429 ;
     RECT  38.16 30.709 38.184 31.429 ;
     RECT  79.632 30.275 79.656 31.621 ;
     RECT  43.392 30.853 44.52 31.667 ;
     RECT  16.608 31.333 17.544 31.669 ;
     RECT  76.464 31.237 76.488 31.715 ;
     RECT  72.6 29.795 73.8 31.717 ;
     RECT  72.6 31.717 74.088 31.763 ;
     RECT  16.368 31.669 17.544 31.811 ;
     RECT  69.072 31.285 69.096 31.811 ;
     RECT  71.472 31.477 71.496 31.811 ;
     RECT  12.048 30.949 12.072 31.907 ;
     RECT  49.536 31.333 51.96 31.907 ;
     RECT  34.464 31.429 38.184 32.051 ;
     RECT  7.2 31.381 8.232 32.195 ;
     RECT  14.976 31.813 15 32.195 ;
     RECT  16.608 31.811 17.544 32.195 ;
     RECT  82.08 31.669 82.104 32.293 ;
     RECT  83.4 30.037 83.976 32.293 ;
     RECT  7.2 32.195 8.112 32.437 ;
     RECT  13.2 27.635 13.512 32.437 ;
     RECT  82.08 32.293 83.976 32.483 ;
     RECT  74.064 31.763 74.088 32.531 ;
     RECT  53.232 29.795 53.256 32.725 ;
     RECT  50.448 31.907 51.96 32.771 ;
     RECT  79.632 31.621 80.328 32.771 ;
     RECT  82.08 32.483 83.712 32.771 ;
     RECT  67.2 26.099 67.512 32.965 ;
     RECT  79.776 32.771 80.328 33.013 ;
     RECT  64.704 29.795 64.728 33.061 ;
     RECT  0.192 16.931 0.216 33.107 ;
     RECT  64.416 33.061 64.728 33.107 ;
     RECT  26.064 30.851 26.088 33.301 ;
     RECT  25.872 33.301 26.088 33.347 ;
     RECT  61.8 30.853 62.76 33.397 ;
     RECT  22.992 31.379 24.312 33.589 ;
     RECT  61.152 33.397 62.76 33.683 ;
     RECT  6.768 32.437 8.112 33.779 ;
     RECT  13.2 32.437 13.608 33.779 ;
     RECT  54.576 29.029 56.712 33.827 ;
     RECT  61.152 33.683 62.712 33.827 ;
     RECT  52.944 32.725 53.256 33.829 ;
     RECT  16.608 32.195 16.632 34.021 ;
     RECT  16.608 34.021 17.064 34.067 ;
     RECT  82.416 32.771 83.712 34.069 ;
     RECT  52.944 33.829 53.304 34.115 ;
     RECT  2.4 27.971 2.712 34.117 ;
     RECT  72.6 31.763 72.912 34.117 ;
     RECT  67.104 32.965 67.512 34.165 ;
     RECT  66.384 34.165 67.512 34.357 ;
     RECT  22.992 33.589 24.408 34.501 ;
     RECT  25.872 33.347 25.896 34.501 ;
     RECT  43.392 31.667 43.416 34.549 ;
     RECT  44.496 31.667 44.52 34.549 ;
     RECT  43.392 34.549 44.52 34.595 ;
     RECT  72.6 34.117 73.848 34.595 ;
     RECT  7.44 33.779 8.112 34.787 ;
     RECT  86.928 33.781 86.952 34.835 ;
     RECT  61.536 33.827 62.712 34.979 ;
     RECT  54.72 33.827 56.712 35.173 ;
     RECT  45.6 29.891 45.912 35.317 ;
     RECT  72.6 34.595 73.224 35.317 ;
     RECT  11.808 34.741 11.832 35.363 ;
     RECT  75.264 34.549 75.288 35.363 ;
     RECT  54.72 35.173 56.808 35.459 ;
     RECT  43.536 34.595 44.52 35.507 ;
     RECT  51 32.771 51.312 35.557 ;
     RECT  66.384 34.357 68.376 35.699 ;
     RECT  13.2 33.779 13.512 35.701 ;
     RECT  38.16 32.051 38.184 35.701 ;
     RECT  52.992 34.115 53.304 35.747 ;
     RECT  78 29.797 78.408 35.845 ;
     RECT  79.776 33.013 80.376 35.941 ;
     RECT  79.776 35.941 81.336 35.987 ;
     RECT  44.496 35.507 44.52 35.989 ;
     RECT  45.6 35.317 46.008 35.989 ;
     RECT  44.496 35.989 46.008 36.035 ;
     RECT  18.6 16.691 18.912 36.181 ;
     RECT  19.92 33.541 19.944 36.181 ;
     RECT  22.992 34.501 25.896 36.181 ;
     RECT  18.6 36.181 19.944 36.227 ;
     RECT  22.992 36.181 26.184 36.227 ;
     RECT  70.752 35.317 70.776 36.275 ;
     RECT  29.4 31.427 29.712 36.325 ;
     RECT  31.008 31.331 31.08 36.325 ;
     RECT  53.28 35.747 53.304 36.325 ;
     RECT  54.72 35.459 55.368 36.325 ;
     RECT  50.592 35.557 51.312 36.371 ;
     RECT  64.416 33.107 64.44 36.373 ;
     RECT  72.336 35.317 73.224 36.421 ;
     RECT  25.872 36.227 26.184 36.515 ;
     RECT  43.2 35.989 43.224 36.515 ;
     RECT  61.8 34.979 62.712 36.515 ;
     RECT  82.416 34.069 83.928 36.515 ;
     RECT  17.04 34.067 17.064 36.563 ;
     RECT  13.2 35.701 14.232 36.611 ;
     RECT  11.424 35.845 11.448 36.803 ;
     RECT  72.288 36.421 73.224 36.803 ;
     RECT  34.464 32.051 37.032 36.805 ;
     RECT  56.4 35.459 56.808 36.997 ;
     RECT  78 35.845 78.504 37.091 ;
     RECT  80.352 35.987 81.336 37.091 ;
     RECT  38.16 35.701 39.144 37.189 ;
     RECT  40.2 30.899 40.512 37.189 ;
     RECT  64.032 36.373 64.44 37.283 ;
     RECT  44.496 36.035 45.912 37.573 ;
     RECT  48.72 33.541 48.744 37.573 ;
     RECT  53.28 36.325 55.368 37.573 ;
     RECT  56.4 36.997 56.856 37.573 ;
     RECT  76.464 37.093 76.488 37.573 ;
     RECT  48.72 37.573 48.888 37.619 ;
     RECT  38.16 37.189 40.512 37.667 ;
     RECT  34.464 36.805 37.128 37.859 ;
     RECT  32.208 26.771 32.232 37.909 ;
     RECT  33.36 28.499 33.432 37.909 ;
     RECT  53.28 37.573 56.856 38.147 ;
     RECT  32.208 37.909 33.432 38.243 ;
     RECT  82.416 36.515 83.712 38.435 ;
     RECT  58.128 36.805 58.152 38.483 ;
     RECT  55.152 38.147 56.856 38.485 ;
     RECT  29.4 36.325 31.08 38.581 ;
     RECT  81.312 37.091 81.336 38.627 ;
     RECT  64.416 37.283 64.44 38.725 ;
     RECT  55.152 38.485 57 38.819 ;
     RECT  72.288 36.803 72.912 38.915 ;
     RECT  44.448 37.573 45.912 39.011 ;
     RECT  61.8 36.515 62.112 39.013 ;
     RECT  55.2 38.819 57 39.251 ;
     RECT  80.4 39.061 80.424 39.253 ;
     RECT  43.296 37.573 43.32 39.301 ;
     RECT  45.6 39.011 45.912 39.301 ;
     RECT  42 37.429 42.024 39.395 ;
     RECT  53.28 38.147 53.304 39.395 ;
     RECT  18.6 36.227 19.8 39.539 ;
     RECT  56.4 39.251 57 39.589 ;
     RECT  80.256 39.253 80.424 39.589 ;
     RECT  61.68 39.013 62.112 39.685 ;
     RECT  29.4 38.581 31.224 39.779 ;
     RECT  64.08 38.725 64.44 39.779 ;
     RECT  55.2 39.251 55.224 39.877 ;
     RECT  61.584 39.685 62.112 39.877 ;
     RECT  30.912 39.779 31.224 40.019 ;
     RECT  79.584 39.589 80.424 40.067 ;
     RECT  79.584 40.067 79.608 40.307 ;
     RECT  66.624 35.699 67.512 40.309 ;
     RECT  75.456 39.829 75.48 40.355 ;
     RECT  69.12 39.877 69.144 40.403 ;
     RECT  4.848 38.677 4.872 40.499 ;
     RECT  45.6 39.301 46.2 40.499 ;
     RECT  70.848 38.677 70.872 40.547 ;
     RECT  51 36.371 51.312 40.693 ;
     RECT  54.24 39.877 55.224 40.739 ;
     RECT  43.248 39.301 43.32 40.835 ;
     RECT  2.4 34.117 3.096 40.981 ;
     RECT  44.448 39.011 44.472 41.075 ;
     RECT  7.8 34.787 8.112 41.077 ;
     RECT  72.336 38.915 72.912 41.077 ;
     RECT  76.464 37.573 76.92 41.269 ;
     RECT  72.336 41.077 73.032 41.411 ;
     RECT  30.912 40.019 31.176 41.605 ;
     RECT  30.864 41.605 31.176 41.651 ;
     RECT  38.16 37.667 39.048 41.651 ;
     RECT  56.4 39.589 57.048 41.651 ;
     RECT  40.2 37.667 40.512 41.749 ;
     RECT  51 40.693 52.056 41.939 ;
     RECT  61.008 39.877 62.112 41.987 ;
     RECT  63.168 40.021 63.192 41.989 ;
     RECT  64.416 39.779 64.44 41.989 ;
     RECT  63.168 41.989 64.44 42.035 ;
     RECT  18.6 39.539 18.912 42.085 ;
     RECT  45.6 40.499 45.912 42.133 ;
     RECT  20.496 40.405 20.52 42.181 ;
     RECT  55.2 40.739 55.224 42.325 ;
     RECT  13.2 36.611 13.512 42.421 ;
     RECT  61.584 41.987 62.112 42.515 ;
     RECT  20.496 42.181 20.712 42.659 ;
     RECT  54.72 42.325 55.224 42.707 ;
     RECT  29.4 39.779 29.712 42.709 ;
     RECT  30.864 41.651 31.032 42.709 ;
     RECT  85.728 35.413 85.752 42.709 ;
     RECT  20.688 42.659 20.712 42.757 ;
     RECT  25.872 36.515 25.896 42.757 ;
     RECT  39.984 41.749 40.512 42.757 ;
     RECT  2.4 40.981 3.96 42.803 ;
     RECT  25.872 42.757 25.992 42.803 ;
     RECT  18.144 42.085 18.912 42.995 ;
     RECT  20.688 42.757 21.48 43.043 ;
     RECT  45.6 42.133 46.344 43.139 ;
     RECT  76.08 41.269 76.92 43.141 ;
     RECT  78 37.091 78.312 43.141 ;
     RECT  76.08 43.141 78.312 43.285 ;
     RECT  3.792 42.803 3.96 43.763 ;
     RECT  41.616 42.709 41.64 43.811 ;
     RECT  39.888 42.757 40.512 43.813 ;
     RECT  66.144 40.309 67.512 43.859 ;
     RECT  22.992 36.227 24.312 43.861 ;
     RECT  6.864 41.077 8.112 43.955 ;
     RECT  85.728 42.709 86.472 43.955 ;
     RECT  7.488 43.955 8.112 44.003 ;
     RECT  21.456 43.043 21.48 44.099 ;
     RECT  63.696 42.035 64.44 44.099 ;
     RECT  75.888 43.285 78.312 44.099 ;
     RECT  86.448 43.955 86.472 44.099 ;
     RECT  27.936 36.421 27.96 44.195 ;
     RECT  13.2 42.421 13.608 44.341 ;
     RECT  18.6 42.995 18.912 44.389 ;
     RECT  39.408 43.813 40.512 44.389 ;
     RECT  43.296 40.835 43.32 44.437 ;
     RECT  61.8 42.515 62.112 44.437 ;
     RECT  43.056 44.437 43.32 44.483 ;
     RECT  18.192 44.389 18.912 44.629 ;
     RECT  16.128 42.517 16.152 44.677 ;
     RECT  15.408 44.677 16.152 44.723 ;
     RECT  61.68 44.437 62.112 44.725 ;
     RECT  3.792 43.763 3.816 44.867 ;
     RECT  33.36 38.243 33.432 44.917 ;
     RECT  34.464 37.859 37.032 44.917 ;
     RECT  13.104 44.341 13.608 44.965 ;
     RECT  25.968 42.803 25.992 44.965 ;
     RECT  29.4 42.709 31.032 44.965 ;
     RECT  66.288 43.859 67.512 45.107 ;
     RECT  38.16 41.651 38.184 45.443 ;
     RECT  9.456 43.285 9.48 45.539 ;
     RECT  48.864 37.619 48.888 45.589 ;
     RECT  48.864 45.589 48.984 45.635 ;
     RECT  76.896 44.099 78.312 45.635 ;
     RECT  39.408 44.389 40.872 45.683 ;
     RECT  22.992 43.861 24.408 45.731 ;
     RECT  25.968 44.965 26.808 45.971 ;
     RECT  61.68 44.725 62.232 46.019 ;
     RECT  56.4 41.651 56.712 46.117 ;
     RECT  13.104 44.965 14.232 46.211 ;
     RECT  64.416 44.099 64.44 46.211 ;
     RECT  18.192 44.629 19.032 46.213 ;
     RECT  15.408 44.723 15.432 46.259 ;
     RECT  25.968 45.971 25.992 46.259 ;
     RECT  29.28 44.965 31.032 46.355 ;
     RECT  59.232 45.973 59.256 46.453 ;
     RECT  60.384 42.469 60.408 46.453 ;
     RECT  42.048 46.501 42.072 46.787 ;
     RECT  81.408 45.589 81.432 46.787 ;
     RECT  84.96 45.589 84.984 46.787 ;
     RECT  22.992 45.731 24.312 46.789 ;
     RECT  52.56 44.293 52.584 46.835 ;
     RECT  70.128 45.301 70.152 46.835 ;
     RECT  55.2 42.707 55.224 47.027 ;
     RECT  59.232 46.453 60.408 47.029 ;
     RECT  15.456 46.693 15.48 47.123 ;
     RECT  33.36 44.917 37.032 47.363 ;
     RECT  13.104 46.211 14.088 47.413 ;
     RECT  59.232 47.029 60.696 47.555 ;
     RECT  66.672 45.107 67.512 47.891 ;
     RECT  17.904 46.213 19.032 47.939 ;
     RECT  56.4 46.117 57.096 47.939 ;
     RECT  61.68 46.019 62.112 48.083 ;
     RECT  59.616 47.555 60.696 48.131 ;
     RECT  59.856 48.131 60.696 48.227 ;
     RECT  43.056 44.483 43.08 48.421 ;
     RECT  63.888 47.845 63.912 48.515 ;
     RECT  39.408 45.683 40.512 48.659 ;
     RECT  22.992 46.789 24.936 48.707 ;
     RECT  29.28 46.355 29.712 48.707 ;
     RECT  29.4 48.707 29.712 48.901 ;
     RECT  13.104 47.413 14.184 48.995 ;
     RECT  67.2 47.891 67.512 48.997 ;
     RECT  42.144 48.421 43.08 49.043 ;
     RECT  16.512 47.077 16.536 49.477 ;
     RECT  17.904 47.939 18.912 49.477 ;
     RECT  56.4 47.939 56.808 49.477 ;
     RECT  43.056 49.043 43.08 49.525 ;
     RECT  76.896 45.635 76.92 49.571 ;
     RECT  43.056 49.525 43.32 50.195 ;
     RECT  48.96 45.635 48.984 50.195 ;
     RECT  29.4 48.901 29.976 50.245 ;
     RECT  13.104 48.995 13.608 50.435 ;
     RECT  33.36 47.363 33.432 50.533 ;
     RECT  34.464 47.363 37.032 50.533 ;
     RECT  29.136 50.245 29.976 50.629 ;
     RECT  31.008 46.355 31.032 50.629 ;
     RECT  33.36 50.533 37.032 50.675 ;
     RECT  56.4 49.477 57.576 50.771 ;
     RECT  60.672 48.227 60.696 50.771 ;
     RECT  66.72 48.997 67.512 50.867 ;
     RECT  34.464 50.675 37.032 51.061 ;
     RECT  10.272 50.629 10.296 51.203 ;
     RECT  29.136 50.629 31.032 51.203 ;
     RECT  13.104 50.435 13.512 51.347 ;
     RECT  26.496 50.245 26.52 51.347 ;
     RECT  11.808 51.157 11.832 51.349 ;
     RECT  13.2 51.347 13.512 51.445 ;
     RECT  45.6 43.139 45.912 51.589 ;
     RECT  29.4 51.203 31.032 51.635 ;
     RECT  11.232 51.349 11.832 51.733 ;
     RECT  72.6 41.411 72.912 51.733 ;
     RECT  69.84 51.301 69.864 51.829 ;
     RECT  14.784 51.205 14.808 51.877 ;
     RECT  16.512 49.477 18.912 51.923 ;
     RECT  22.992 48.707 24.408 52.021 ;
     RECT  61.8 48.083 62.112 52.165 ;
     RECT  63.168 51.493 63.192 52.165 ;
     RECT  43.488 50.821 43.512 52.211 ;
     RECT  67.2 50.867 67.512 52.213 ;
     RECT  75.888 44.099 75.912 52.213 ;
     RECT  17.28 51.923 18.912 52.259 ;
     RECT  14.784 51.877 15.432 52.451 ;
     RECT  61.8 52.165 63.192 52.451 ;
     RECT  85.968 47.845 85.992 52.453 ;
     RECT  28.08 51.733 28.104 52.499 ;
     RECT  45.6 51.589 46.824 52.499 ;
     RECT  85.296 52.453 85.992 52.499 ;
     RECT  14.784 52.451 14.808 52.547 ;
     RECT  33.36 50.675 33.432 52.693 ;
     RECT  34.464 51.061 37.32 52.693 ;
     RECT  13.2 51.445 13.608 52.739 ;
     RECT  69.216 51.829 69.864 52.739 ;
     RECT  67.2 52.213 68.088 52.835 ;
     RECT  22.8 52.021 24.408 52.981 ;
     RECT  56.4 50.771 57.144 52.981 ;
     RECT  45.6 52.499 46.344 53.219 ;
     RECT  22.224 52.981 24.408 53.365 ;
     RECT  41.856 52.837 41.976 53.365 ;
     RECT  41.616 53.365 41.976 53.411 ;
     RECT  4.704 51.781 4.728 53.509 ;
     RECT  4.416 53.509 4.728 53.555 ;
     RECT  2.4 42.803 2.712 53.557 ;
     RECT  31.008 51.635 31.032 53.557 ;
     RECT  61.8 52.451 63.096 53.557 ;
     RECT  74.256 52.693 74.28 53.557 ;
     RECT  75.408 52.213 75.912 53.557 ;
     RECT  78 45.635 78.312 53.557 ;
     RECT  74.256 53.557 75.912 53.603 ;
     RECT  33.36 52.693 37.32 53.795 ;
     RECT  43.776 53.749 43.8 53.891 ;
     RECT  72.48 51.733 72.912 54.035 ;
     RECT  32.208 38.243 32.232 54.085 ;
     RECT  33.36 53.795 33.432 54.085 ;
     RECT  51 41.939 51.312 54.085 ;
     RECT  52.464 52.981 52.488 54.085 ;
     RECT  29.4 51.635 29.712 54.133 ;
     RECT  22.224 53.365 24.504 54.179 ;
     RECT  4.416 53.555 4.44 54.323 ;
     RECT  77.472 53.557 78.312 54.371 ;
     RECT  31.008 53.557 31.176 54.373 ;
     RECT  30.96 54.373 31.176 54.419 ;
     RECT  34.464 53.795 37.32 54.421 ;
     RECT  65.856 53.557 65.88 54.563 ;
     RECT  22.224 54.179 24.312 54.659 ;
     RECT  61.8 53.557 63.576 54.659 ;
     RECT  18 52.259 18.912 54.661 ;
     RECT  2.304 53.557 2.712 54.755 ;
     RECT  27.12 54.133 27.144 54.755 ;
     RECT  55.968 52.981 57.144 54.755 ;
     RECT  85.296 52.499 85.32 54.755 ;
     RECT  22.464 54.659 24.312 54.851 ;
     RECT  80.832 54.709 80.856 54.947 ;
     RECT  32.208 54.085 33.432 55.187 ;
     RECT  11.232 51.733 11.928 55.237 ;
     RECT  18 54.661 19.656 55.237 ;
     RECT  51 54.085 52.488 55.331 ;
     RECT  82.128 52.981 82.152 55.331 ;
     RECT  29.28 54.133 29.712 55.381 ;
     RECT  34.464 54.421 37.416 55.619 ;
     RECT  74.256 53.603 75.432 55.667 ;
     RECT  33.36 55.187 33.432 55.669 ;
     RECT  34.464 55.619 37.272 55.669 ;
     RECT  17.664 55.237 19.656 55.715 ;
     RECT  75.408 55.667 75.432 55.715 ;
     RECT  4.32 55.237 4.344 55.763 ;
     RECT  22.992 54.851 24.312 55.813 ;
     RECT  17.664 55.715 19.416 55.955 ;
     RECT  78 54.371 78.312 56.005 ;
     RECT  38.784 55.189 38.808 56.341 ;
     RECT  56.4 54.755 57.144 56.341 ;
     RECT  38.784 56.341 38.904 56.389 ;
     RECT  39.984 48.659 40.512 56.389 ;
     RECT  61.8 54.659 63.096 56.389 ;
     RECT  18.6 55.955 19.416 56.435 ;
     RECT  30.96 54.419 31.032 56.483 ;
     RECT  38.784 56.389 40.512 56.483 ;
     RECT  69.216 52.739 69.24 56.483 ;
     RECT  71.136 55.717 71.16 56.483 ;
     RECT  22.368 55.813 24.312 56.485 ;
     RECT  29.184 55.381 29.712 56.531 ;
     RECT  51 55.331 52.248 56.531 ;
     RECT  41.616 53.411 41.64 56.533 ;
     RECT  33.36 55.669 37.272 56.579 ;
     RECT  32.208 55.187 32.232 56.677 ;
     RECT  33.36 56.579 37.032 56.677 ;
     RECT  32.208 56.677 37.032 56.723 ;
     RECT  31.008 56.483 31.032 56.867 ;
     RECT  55.872 56.341 57.144 56.867 ;
     RECT  67.2 52.835 67.512 56.869 ;
     RECT  60.912 56.389 63.096 57.013 ;
     RECT  51 56.531 52.008 57.059 ;
     RECT  60.768 57.013 63.096 57.059 ;
     RECT  47.904 56.005 47.928 57.107 ;
     RECT  56.4 56.867 57.144 57.155 ;
     RECT  60.768 57.059 62.232 57.155 ;
     RECT  74.256 55.667 74.28 57.155 ;
     RECT  51 57.059 51.912 57.301 ;
     RECT  50.496 57.301 51.912 57.347 ;
     RECT  41.616 56.533 41.88 57.443 ;
     RECT  67.2 56.869 68.088 57.539 ;
     RECT  29.28 56.531 29.712 57.589 ;
     RECT  45.6 53.219 45.912 57.589 ;
     RECT  10.464 55.237 11.928 57.635 ;
     RECT  18.6 56.435 19.032 57.635 ;
     RECT  22.368 56.485 24.6 57.635 ;
     RECT  56.4 57.155 57.048 57.635 ;
     RECT  60.768 57.155 62.112 57.635 ;
     RECT  69.6 57.061 69.624 57.635 ;
     RECT  9.12 57.541 9.144 57.877 ;
     RECT  10.464 57.635 11.784 57.877 ;
     RECT  22.992 57.635 24.6 58.115 ;
     RECT  34.8 56.723 37.032 58.117 ;
     RECT  38.88 56.483 40.512 58.163 ;
     RECT  9.12 57.877 11.784 58.355 ;
     RECT  28.56 57.589 29.712 58.547 ;
     RECT  4.32 58.549 4.344 58.645 ;
     RECT  85.728 57.445 85.752 58.645 ;
     RECT  5.952 56.869 5.976 58.691 ;
     RECT  39.312 58.163 40.512 58.691 ;
     RECT  85.632 58.645 85.752 58.691 ;
     RECT  22.992 58.115 24.312 58.739 ;
     RECT  67.2 57.539 67.848 58.741 ;
     RECT  27.36 58.645 27.384 58.835 ;
     RECT  9.648 58.355 11.784 58.883 ;
     RECT  29.28 58.547 29.712 58.883 ;
     RECT  71.472 56.677 71.496 58.883 ;
     RECT  67.2 58.741 67.896 58.979 ;
     RECT  24 58.739 24.312 59.173 ;
     RECT  3.984 58.645 4.344 59.219 ;
     RECT  10.032 58.883 11.784 59.221 ;
     RECT  3.984 59.219 4.008 59.267 ;
     RECT  32.208 56.723 33.432 59.315 ;
     RECT  34.8 58.117 37.464 59.315 ;
     RECT  82.176 55.813 82.2 59.315 ;
     RECT  85.632 58.691 85.656 59.315 ;
     RECT  63.456 58.117 63.48 59.507 ;
     RECT  21.552 58.645 21.576 59.651 ;
     RECT  17.04 58.117 17.064 59.699 ;
     RECT  24 59.173 24.408 59.701 ;
     RECT  36.528 59.315 37.464 59.749 ;
     RECT  10.032 59.221 12.072 59.891 ;
     RECT  36.528 59.749 37.608 59.891 ;
     RECT  34.8 59.315 35.544 60.083 ;
     RECT  41.856 57.443 41.88 60.083 ;
     RECT  45.6 57.589 46.008 60.131 ;
     RECT  67.2 58.979 67.848 60.179 ;
     RECT  22.992 58.739 23.016 60.325 ;
     RECT  24 59.701 25.368 60.325 ;
     RECT  20.544 56.389 20.568 60.467 ;
     RECT  22.992 60.325 25.368 60.467 ;
     RECT  32.208 59.315 33.048 60.467 ;
     RECT  50.496 57.347 51.312 60.467 ;
     RECT  72.6 54.035 72.912 60.613 ;
     RECT  16.512 60.421 16.536 60.707 ;
     RECT  83.4 38.435 83.712 60.709 ;
     RECT  72.096 60.613 72.912 60.755 ;
     RECT  58.656 60.421 58.68 60.997 ;
     RECT  58.128 60.997 58.68 61.043 ;
     RECT  60.768 57.635 60.792 61.043 ;
     RECT  34.8 60.083 35.112 61.045 ;
     RECT  23.904 60.467 25.368 61.093 ;
     RECT  7.8 44.003 8.112 61.189 ;
     RECT  10.224 59.891 11.304 61.381 ;
     RECT  32.256 60.467 32.712 61.477 ;
     RECT  39.84 58.691 40.512 61.525 ;
     RECT  58.128 61.043 58.152 61.763 ;
     RECT  23.904 61.093 26.136 61.861 ;
     RECT  4.128 61.381 4.152 61.907 ;
     RECT  32.064 61.477 32.712 61.957 ;
     RECT  7.8 61.189 9.048 62.149 ;
     RECT  10.176 61.381 11.304 62.149 ;
     RECT  13.2 52.739 13.512 62.149 ;
     RECT  18.6 57.635 18.912 62.149 ;
     RECT  29.4 58.883 29.712 62.149 ;
     RECT  32.064 61.957 32.856 62.149 ;
     RECT  34.8 61.045 35.832 62.149 ;
     RECT  36.816 59.891 37.608 62.149 ;
     RECT  39.744 61.525 40.512 62.149 ;
     RECT  34.464 62.149 41.112 62.195 ;
     RECT  16.032 62.149 16.056 62.197 ;
     RECT  18.432 62.149 19.128 62.197 ;
     RECT  29.4 62.149 32.856 62.197 ;
     RECT  12.768 62.149 14.616 62.293 ;
     RECT  17.376 62.149 17.4 62.293 ;
     RECT  18.432 62.197 19.224 62.293 ;
     RECT  12.672 62.293 14.712 62.389 ;
     RECT  53.568 61.573 53.592 62.435 ;
     RECT  77.808 56.005 78.312 62.483 ;
     RECT  83.4 60.709 84.36 62.483 ;
     RECT  12.672 62.389 14.808 62.581 ;
     RECT  7.8 62.149 11.304 62.629 ;
     RECT  12.48 62.581 14.808 62.629 ;
     RECT  16.032 62.197 16.152 62.629 ;
     RECT  27.744 62.245 27.768 62.629 ;
     RECT  34.464 62.195 37.08 62.629 ;
     RECT  2.4 54.755 2.712 62.649 ;
     RECT  45.6 60.131 45.912 62.649 ;
     RECT  51 60.467 51.312 62.649 ;
     RECT  56.4 57.635 56.712 62.649 ;
     RECT  61.8 57.635 62.112 62.649 ;
     RECT  67.2 60.179 67.512 62.649 ;
     RECT  72.6 60.755 72.912 62.649 ;
     RECT  78 62.483 78.312 62.649 ;
     RECT  83.4 62.483 83.712 62.649 ;
     RECT  2.4 62.649 2.52 62.663 ;
     RECT  7.2 62.629 11.304 62.663 ;
     RECT  12.384 62.629 14.808 62.663 ;
     RECT  28.8 62.197 32.856 62.663 ;
     RECT  45.6 62.649 45.72 62.663 ;
     RECT  51 62.649 51.12 62.663 ;
     RECT  56.4 62.649 56.52 62.663 ;
     RECT  61.8 62.649 61.92 62.663 ;
     RECT  67.2 62.649 67.32 62.663 ;
     RECT  72.6 62.649 72.72 62.663 ;
     RECT  78 62.649 78.12 62.663 ;
     RECT  83.4 62.649 83.52 62.663 ;
     RECT  34.176 62.629 37.08 62.677 ;
     RECT  21.408 62.341 21.432 63.205 ;
     RECT  23.808 61.861 26.136 63.253 ;
     RECT  4.848 62.581 4.872 63.829 ;
     RECT  17.376 62.293 19.224 63.829 ;
     RECT  27.648 62.629 27.768 63.829 ;
     RECT  23.712 63.253 26.136 64.501 ;
     RECT  23.712 64.501 26.52 64.597 ;
     RECT  27.552 63.829 27.768 64.597 ;
     RECT  30.048 62.663 32.856 64.597 ;
     RECT  4.032 63.829 4.872 64.645 ;
     RECT  5.904 62.581 5.928 64.645 ;
     RECT  8.352 62.663 11.304 64.645 ;
     RECT  23.616 64.597 27.768 64.645 ;
     RECT  4.032 64.645 6.168 64.691 ;
     RECT  17.184 63.829 19.224 64.691 ;
     RECT  7.2 62.663 7.32 64.784 ;
     RECT  8.352 64.645 11.352 64.784 ;
     RECT  12.384 62.663 13.08 64.784 ;
     RECT  14.112 62.663 14.808 64.784 ;
     RECT  15.84 62.629 16.152 64.784 ;
     RECT  17.184 64.691 17.496 64.784 ;
     RECT  18.528 64.691 19.224 64.784 ;
     RECT  21.312 63.205 21.432 64.784 ;
     RECT  23.52 64.645 27.768 64.784 ;
     RECT  28.8 62.663 29.016 64.784 ;
     RECT  30.048 64.597 33.048 64.784 ;
     RECT  34.08 62.677 37.08 64.784 ;
     RECT  38.112 62.195 41.112 64.784 ;
     RECT  26.592 64.784 26.616 64.787 ;
     RECT  7.08 0.016 8.016 0.132 ;
     RECT  11.112 0.016 12.048 0.085 ;
     RECT  15.144 0.016 16.08 0.132 ;
     RECT  7.032 0.132 8.064 0.181 ;
     RECT  15.096 0.132 16.128 0.181 ;
     RECT  7.08 0.181 8.064 0.277 ;
     RECT  4.032 1.763 4.224 2.137 ;
     RECT  2.52 2.137 4.224 2.151 ;
     RECT  2.712 2.151 4.224 2.245 ;
     RECT  3 2.245 4.224 2.867 ;
     RECT  4.248 2.291 5.76 2.867 ;
     RECT  23.016 2.485 24 2.581 ;
     RECT  24.312 2.485 25.392 3.731 ;
     RECT  3 2.867 5.76 3.925 ;
     RECT  54.984 3.061 56.4 3.395 ;
     RECT  42.456 3.301 43.776 3.443 ;
     RECT  3 3.925 5.472 4.357 ;
     RECT  47.736 3.925 48.768 5.747 ;
     RECT  3 4.357 4.224 5.557 ;
     RECT  4.248 4.357 5.472 4.981 ;
     RECT  72.912 4.501 74.064 5.171 ;
     RECT  5.496 4.835 6.768 5.219 ;
     RECT  33.624 5.077 34.8 5.509 ;
     RECT  84.216 5.077 85.392 5.747 ;
     RECT  5.496 5.219 7.44 5.747 ;
     RECT  40.512 5.269 41.712 5.603 ;
     RECT  31.944 5.557 33.072 7.619 ;
     RECT  35.208 5.653 36.672 6.947 ;
     RECT  5.496 5.747 7.536 5.795 ;
     RECT  27 5.747 27.816 6.709 ;
     RECT  5.496 5.795 7.8 6.277 ;
     RECT  14.952 5.891 15.936 6.323 ;
     RECT  29.712 6.085 31.008 14.197 ;
     RECT  5.784 6.277 7.8 6.709 ;
     RECT  9.384 6.323 10.464 6.371 ;
     RECT  10.68 6.323 11.664 6.899 ;
     RECT  14.952 6.323 15 6.853 ;
     RECT  6.648 6.709 7.8 8.773 ;
     RECT  27 6.709 28.08 7.669 ;
     RECT  28.104 6.709 29.4 8.821 ;
     RECT  10.464 6.899 10.656 7.957 ;
     RECT  13.056 6.899 13.104 7.139 ;
     RECT  13.056 7.139 13.2 8.197 ;
     RECT  33.384 7.187 34.464 15.925 ;
     RECT  5.496 7.379 6.624 9.541 ;
     RECT  45.912 7.381 46.944 8.963 ;
     RECT  13.512 7.475 14.88 8.003 ;
     RECT  2.712 7.619 3.888 8.677 ;
     RECT  31.944 7.619 33.36 8.629 ;
     RECT  84.696 7.909 86.016 8.003 ;
     RECT  13.512 8.003 14.976 8.147 ;
     RECT  9.144 8.005 10.368 10.597 ;
     RECT  31.944 8.629 33.072 8.965 ;
     RECT  2.856 8.677 3.888 8.869 ;
     RECT  28.248 8.821 29.4 9.731 ;
     RECT  45.912 8.963 46.968 9.781 ;
     RECT  27.96 9.731 29.4 11.459 ;
     RECT  10.392 9.779 10.68 9.877 ;
     RECT  45.912 9.781 47.328 11.987 ;
     RECT  26.976 9.827 27.216 10.213 ;
     RECT  6.648 9.875 7.68 11.221 ;
     RECT  10.392 9.877 12.144 10.165 ;
     RECT  12.168 9.877 13.2 11.365 ;
     RECT  19.8 10.117 21.072 11.459 ;
     RECT  10.392 10.165 12.048 11.077 ;
     RECT  24.312 10.211 24.648 10.213 ;
     RECT  24.312 10.213 25.824 10.981 ;
     RECT  25.848 10.213 27.216 11.027 ;
     RECT  13.512 10.931 13.608 11.941 ;
     RECT  24.312 10.981 25.728 12.035 ;
     RECT  25.752 11.027 27.216 12.035 ;
     RECT  10.92 11.077 12.048 11.365 ;
     RECT  27.912 11.459 29.4 11.941 ;
     RECT  39.048 11.797 40.2 13.091 ;
     RECT  14.424 11.941 15.6 12.275 ;
     RECT  27.912 11.941 29.04 12.421 ;
     RECT  40.512 11.941 41.616 13.091 ;
     RECT  45.912 11.987 47.376 15.443 ;
     RECT  6.744 12.035 7.8 14.197 ;
     RECT  32.184 12.035 33.36 14.291 ;
     RECT  37.992 12.037 39.024 13.091 ;
     RECT  14.424 12.275 15.624 12.613 ;
     RECT  14.424 12.613 15.936 12.805 ;
     RECT  14.568 12.805 15.936 13.667 ;
     RECT  18.912 12.997 20.016 13.667 ;
     RECT  41.64 13.045 43.152 13.091 ;
     RECT  73.512 13.525 74.592 13.907 ;
     RECT  18.912 13.667 19.656 14.197 ;
     RECT  8.232 14.195 8.52 14.435 ;
     RECT  29.832 14.197 31.008 15.301 ;
     RECT  12.528 14.387 12.768 15.637 ;
     RECT  8.112 14.435 8.52 15.397 ;
     RECT  11.496 15.637 12.768 15.779 ;
     RECT  29.832 15.827 31.008 16.307 ;
     RECT  62.232 15.925 63.312 17.699 ;
     RECT  71.208 15.973 72.48 16.405 ;
     RECT  8.112 16.067 8.616 16.981 ;
     RECT  6.36 16.307 7.344 16.403 ;
     RECT  29.712 16.307 31.008 21.013 ;
     RECT  37.032 16.307 38.064 17.893 ;
     RECT  6.36 16.403 7.8 20.003 ;
     RECT  31.896 16.501 33.36 17.123 ;
     RECT  5.016 16.595 6.336 19.381 ;
     RECT  8.112 16.981 9.12 17.123 ;
     RECT  9.144 16.981 10.512 17.075 ;
     RECT  28.104 17.123 29.4 24.085 ;
     RECT  31.032 17.123 33.36 18.133 ;
     RECT  51.312 17.123 51.768 18.229 ;
     RECT  2.712 17.171 3.792 18.851 ;
     RECT  33.384 17.891 34.464 22.165 ;
     RECT  31.848 18.133 33.36 20.579 ;
     RECT  66.12 18.709 67.2 19.427 ;
     RECT  2.712 18.851 4.128 20.003 ;
     RECT  82.056 19.333 83.4 23.315 ;
     RECT  5.112 19.381 6.336 20.003 ;
     RECT  24.312 19.909 25.632 21.443 ;
     RECT  5.112 20.003 5.304 20.291 ;
     RECT  27.216 20.003 28.08 20.869 ;
     RECT  5.28 20.291 5.304 20.677 ;
     RECT  25.656 20.869 26.784 21.443 ;
     RECT  26.808 20.869 28.08 22.211 ;
     RECT  8.112 20.965 9.36 21.107 ;
     RECT  35.112 21.061 36.096 22.453 ;
     RECT  8.112 21.107 9.288 22.165 ;
     RECT  11.4 21.637 12.768 22.451 ;
     RECT  37.656 21.683 38.64 21.779 ;
     RECT  8.112 22.165 9.264 23.171 ;
     RECT  60.456 22.165 61.8 23.363 ;
     RECT  56.712 22.259 58.128 24.659 ;
     RECT  33.384 23.123 34.464 24.709 ;
     RECT  83.232 23.315 83.4 23.317 ;
     RECT  6.456 23.317 7.44 23.699 ;
     RECT  6.456 23.699 7.8 28.117 ;
     RECT  5.064 23.845 6.432 24.899 ;
     RECT  29.928 24.323 31.008 29.845 ;
     RECT  56.112 24.563 56.4 24.613 ;
     RECT  55.176 24.613 56.4 25.621 ;
     RECT  33.432 24.709 34.464 27.445 ;
     RECT  31.032 25.285 32.208 26.197 ;
     RECT  32.232 25.285 33.36 37.909 ;
     RECT  55.32 25.621 56.4 29.029 ;
     RECT  67.512 26.099 68.088 27.301 ;
     RECT  42.456 26.101 43.92 26.867 ;
     RECT  56.712 26.197 58.128 26.771 ;
     RECT  46.584 26.485 47.856 27.299 ;
     RECT  31.032 26.771 32.208 28.789 ;
     RECT  85.512 26.821 86.592 27.395 ;
     RECT  45.912 27.299 47.856 27.395 ;
     RECT  67.512 27.301 68.928 27.971 ;
     RECT  45.912 27.395 47.88 28.453 ;
     RECT  82.296 27.973 83.4 28.211 ;
     RECT  78.312 28.163 78.792 29.029 ;
     RECT  46.776 28.453 47.88 28.501 ;
     RECT  73.8 28.453 75.216 31.331 ;
     RECT  33.432 28.499 34.464 44.917 ;
     RECT  46.776 28.501 48.288 29.075 ;
     RECT  83.712 28.547 83.976 30.037 ;
     RECT  53.496 28.693 54.576 29.795 ;
     RECT  31.08 28.789 32.208 38.581 ;
     RECT  78.312 29.029 79.776 29.797 ;
     RECT  45.504 29.795 45.6 30.853 ;
     RECT  53.256 29.795 54.576 33.827 ;
     RECT  78.408 29.797 79.776 30.229 ;
     RECT  29.928 29.845 30.96 31.331 ;
     RECT  78.408 30.229 79.632 32.771 ;
     RECT  79.656 30.275 79.8 31.621 ;
     RECT  75.24 30.613 76.704 31.139 ;
     RECT  76.728 30.613 78 31.139 ;
     RECT  37.032 30.709 38.16 31.429 ;
     RECT  51.96 30.709 53.232 32.725 ;
     RECT  44.52 30.853 45.6 35.989 ;
     RECT  12.072 30.949 13.2 31.907 ;
     RECT  75.24 31.139 78 31.237 ;
     RECT  75.24 31.237 76.464 31.331 ;
     RECT  76.488 31.237 78 31.715 ;
     RECT  29.928 31.331 31.008 31.427 ;
     RECT  73.8 31.331 74.088 31.717 ;
     RECT  17.544 31.333 18.6 32.195 ;
     RECT  29.712 31.427 31.008 36.325 ;
     RECT  71.496 31.477 72.6 31.811 ;
     RECT  43.416 31.667 44.496 34.549 ;
     RECT  82.104 31.669 83.4 32.293 ;
     RECT  72.912 31.763 74.064 32.531 ;
     RECT  13.512 31.813 14.976 32.195 ;
     RECT  37.032 32.051 38.16 36.805 ;
     RECT  13.512 32.195 13.608 32.437 ;
     RECT  51.96 32.725 52.944 32.771 ;
     RECT  78.408 32.771 79.776 35.845 ;
     RECT  18.912 33.541 19.92 36.181 ;
     RECT  24.408 33.589 25.872 34.501 ;
     RECT  53.256 33.827 54.72 33.829 ;
     RECT  53.304 33.829 54.72 36.325 ;
     RECT  73.848 34.549 75.264 34.595 ;
     RECT  43.392 34.595 43.536 35.507 ;
     RECT  11.832 34.741 13.2 35.363 ;
     RECT  55.368 35.459 56.4 37.573 ;
     RECT  43.392 35.507 44.496 35.989 ;
     RECT  39.144 35.701 40.2 37.189 ;
     RECT  78.504 35.845 79.776 35.987 ;
     RECT  81.336 35.941 82.416 38.435 ;
     RECT  43.224 35.989 44.496 36.515 ;
     RECT  62.712 36.373 64.032 36.515 ;
     RECT  27.96 36.421 29.4 44.195 ;
     RECT  43.2 36.515 44.496 37.429 ;
     RECT  37.128 36.805 38.16 37.859 ;
     RECT  56.808 36.805 58.128 36.997 ;
     RECT  56.856 36.997 58.128 38.483 ;
     RECT  76.488 37.093 78 37.573 ;
     RECT  64.08 37.283 64.416 38.725 ;
     RECT  40.512 37.429 42 39.395 ;
     RECT  42.024 37.429 44.496 37.573 ;
     RECT  42.024 37.573 43.296 39.301 ;
     RECT  43.32 37.573 44.448 41.075 ;
     RECT  76.92 37.573 78 43.141 ;
     RECT  39.048 37.667 40.2 41.651 ;
     RECT  37.032 37.859 38.16 45.443 ;
     RECT  32.232 38.243 33.36 54.085 ;
     RECT  56.856 38.483 57.048 38.485 ;
     RECT  57 38.485 57.048 39.589 ;
     RECT  31.224 38.581 32.208 40.019 ;
     RECT  70.872 38.677 72.288 38.915 ;
     RECT  55.152 38.819 55.2 39.877 ;
     RECT  70.872 38.915 72.336 40.547 ;
     RECT  44.472 39.011 45.6 41.075 ;
     RECT  55.224 39.251 56.4 47.027 ;
     RECT  42.024 39.301 43.248 39.395 ;
     RECT  78.312 39.589 79.584 40.307 ;
     RECT  29.712 39.779 30.912 41.605 ;
     RECT  64.08 39.779 64.416 40.021 ;
     RECT  75.48 39.829 76.464 40.355 ;
     RECT  31.176 40.019 32.208 41.651 ;
     RECT  62.112 40.021 63.168 42.035 ;
     RECT  63.192 40.021 64.416 41.989 ;
     RECT  76.08 40.355 76.464 41.269 ;
     RECT  29.712 41.605 30.864 42.709 ;
     RECT  31.032 41.651 32.208 53.557 ;
     RECT  39.888 41.651 40.2 41.749 ;
     RECT  39.888 41.749 39.984 42.757 ;
     RECT  61.008 41.987 61.584 42.469 ;
     RECT  60.408 42.469 61.584 42.515 ;
     RECT  60.408 42.515 61.8 44.437 ;
     RECT  40.512 42.709 41.616 43.811 ;
     RECT  21.48 42.757 22.992 44.099 ;
     RECT  2.712 42.803 3.792 44.867 ;
     RECT  18.192 42.995 18.6 44.389 ;
     RECT  8.112 43.285 9.456 45.539 ;
     RECT  40.512 43.811 40.872 44.389 ;
     RECT  38.184 43.813 39.408 45.443 ;
     RECT  75.912 44.099 76.896 49.571 ;
     RECT  29.28 44.195 29.4 44.965 ;
     RECT  51.312 44.293 52.56 46.835 ;
     RECT  60.408 44.437 61.68 47.029 ;
     RECT  14.232 44.965 15.408 46.211 ;
     RECT  83.712 45.589 84.96 46.787 ;
     RECT  76.92 45.635 78 49.571 ;
     RECT  24.312 45.731 24.408 46.789 ;
     RECT  59.256 45.973 60.384 46.453 ;
     RECT  14.088 46.211 15.408 46.259 ;
     RECT  14.088 46.259 15.432 46.693 ;
     RECT  29.712 46.355 31.008 48.901 ;
     RECT  42.072 46.501 43.056 46.787 ;
     RECT  14.088 46.693 15.456 47.123 ;
     RECT  60.696 47.029 61.68 48.083 ;
     RECT  15.48 47.077 16.512 47.123 ;
     RECT  16.536 47.077 17.904 49.477 ;
     RECT  14.088 47.123 14.184 47.413 ;
     RECT  33.432 47.363 34.464 50.533 ;
     RECT  66.72 47.891 67.2 48.997 ;
     RECT  60.696 48.083 61.8 50.771 ;
     RECT  29.976 48.901 31.008 50.629 ;
     RECT  13.512 50.435 13.608 51.205 ;
     RECT  33.432 50.675 34.464 52.693 ;
     RECT  10.296 51.157 11.808 51.203 ;
     RECT  11.832 51.157 13.104 51.347 ;
     RECT  11.232 51.203 11.808 51.349 ;
     RECT  29.136 51.203 29.4 51.733 ;
     RECT  13.512 51.205 14.784 51.445 ;
     RECT  11.832 51.347 13.2 51.733 ;
     RECT  13.608 51.445 14.784 52.547 ;
     RECT  62.112 51.493 63.168 52.165 ;
     RECT  29.712 51.635 31.008 54.373 ;
     RECT  11.928 51.733 13.2 57.635 ;
     RECT  28.104 51.733 29.4 52.499 ;
     RECT  15.432 51.877 16.512 51.923 ;
     RECT  68.088 52.213 69.216 52.835 ;
     RECT  63.096 52.451 63.192 53.557 ;
     RECT  72.912 52.693 74.256 57.155 ;
     RECT  74.28 52.693 75.408 53.557 ;
     RECT  40.512 52.837 41.856 53.365 ;
     RECT  51.312 52.981 52.464 54.085 ;
     RECT  82.152 52.981 83.4 55.331 ;
     RECT  40.512 53.365 41.616 57.443 ;
     RECT  31.176 53.557 32.208 54.419 ;
     RECT  65.88 53.557 67.2 54.563 ;
     RECT  33.432 53.795 34.464 55.669 ;
     RECT  29.712 54.373 30.96 56.483 ;
     RECT  31.032 54.419 32.208 56.867 ;
     RECT  22.368 54.659 22.464 54.851 ;
     RECT  80.856 54.709 82.128 54.947 ;
     RECT  22.368 54.851 22.992 55.813 ;
     RECT  32.232 55.187 33.36 56.677 ;
     RECT  37.416 55.189 38.784 55.619 ;
     RECT  38.808 55.189 39.984 56.341 ;
     RECT  82.176 55.331 83.4 55.813 ;
     RECT  37.272 55.619 38.784 56.483 ;
     RECT  74.28 55.667 75.408 55.715 ;
     RECT  19.416 55.715 19.656 56.389 ;
     RECT  71.16 55.717 72.6 56.483 ;
     RECT  82.2 55.813 83.4 59.315 ;
     RECT  38.904 56.341 39.984 56.389 ;
     RECT  19.416 56.389 20.544 56.435 ;
     RECT  19.032 56.435 20.544 57.635 ;
     RECT  29.712 56.483 31.008 56.867 ;
     RECT  69.216 56.483 69.24 56.869 ;
     RECT  71.472 56.483 72.6 56.677 ;
     RECT  29.184 56.531 29.28 57.589 ;
     RECT  71.496 56.677 72.6 58.883 ;
     RECT  33.432 56.723 34.8 59.315 ;
     RECT  68.088 56.869 69.24 57.061 ;
     RECT  62.232 57.059 63.096 57.155 ;
     RECT  68.088 57.061 69.6 57.539 ;
     RECT  62.112 57.155 63.096 58.117 ;
     RECT  40.512 57.443 41.856 60.083 ;
     RECT  67.848 57.539 67.896 58.741 ;
     RECT  8.112 57.541 9.12 58.355 ;
     RECT  9.144 57.541 10.464 57.877 ;
     RECT  11.784 57.635 13.2 59.221 ;
     RECT  22.368 57.635 22.992 58.645 ;
     RECT  60.792 57.635 61.8 61.043 ;
     RECT  24.312 58.115 24.408 59.173 ;
     RECT  37.464 58.117 38.88 58.163 ;
     RECT  62.112 58.117 63.456 59.507 ;
     RECT  2.712 58.645 3.984 59.267 ;
     RECT  20.568 58.645 21.552 59.651 ;
     RECT  21.576 58.645 22.992 59.651 ;
     RECT  23.016 58.739 24 60.325 ;
     RECT  12.072 59.221 13.2 59.891 ;
     RECT  35.544 59.315 36.528 59.891 ;
     RECT  10.032 59.891 10.224 61.189 ;
     RECT  35.544 59.891 36.816 60.083 ;
     RECT  35.112 60.083 36.816 61.045 ;
     RECT  23.808 60.467 23.904 61.861 ;
     RECT  32.208 60.467 32.256 61.477 ;
     RECT  32.712 60.467 32.856 61.957 ;
     RECT  16.512 60.707 16.536 62.149 ;
     RECT  56.712 60.997 58.128 61.763 ;
     RECT  35.832 61.045 36.816 62.149 ;
     RECT  9.048 61.189 10.224 61.381 ;
     RECT  2.712 61.381 4.128 61.907 ;
     RECT  9.048 61.381 10.176 62.149 ;
     RECT  11.304 62.149 12.768 62.293 ;
     RECT  14.616 62.149 16.032 62.293 ;
     RECT  16.056 62.149 17.376 62.197 ;
     RECT  17.4 62.149 18.432 62.293 ;
     RECT  37.08 62.195 38.112 64.668 ;
     RECT  16.152 62.197 17.376 63.829 ;
     RECT  27.768 62.245 28.8 64.668 ;
     RECT  11.304 62.293 12.672 62.581 ;
     RECT  14.712 62.293 16.032 62.389 ;
     RECT  14.808 62.389 16.032 62.629 ;
     RECT  4.872 62.581 5.904 64.643 ;
     RECT  11.304 62.581 12.48 62.629 ;
     RECT  5.928 62.629 7.2 64.643 ;
     RECT  11.304 62.629 12.384 64.645 ;
     RECT  14.808 62.629 15.84 64.668 ;
     RECT  26.136 62.629 27.648 63.829 ;
     RECT  32.856 62.629 34.176 62.677 ;
     RECT  7.32 62.663 8.352 64.668 ;
     RECT  13.08 62.663 14.112 64.668 ;
     RECT  29.016 62.663 30.048 64.668 ;
     RECT  32.856 62.677 34.08 64.597 ;
     RECT  16.152 63.829 17.184 64.668 ;
     RECT  26.136 63.829 27.552 64.501 ;
     RECT  26.52 64.501 27.552 64.597 ;
     RECT  33.048 64.597 34.08 64.668 ;
     RECT  4.872 64.643 5.04 64.645 ;
     RECT  5.16 64.643 5.904 64.645 ;
     RECT  5.928 64.643 6.096 64.645 ;
     RECT  6.216 64.643 7.2 64.668 ;
     RECT  11.352 64.645 12.384 64.668 ;
     RECT  6.216 64.668 7.152 64.691 ;
     RECT  7.368 64.668 8.304 64.784 ;
     RECT  11.4 64.668 12.336 64.784 ;
     RECT  13.128 64.668 14.064 64.784 ;
     RECT  14.856 64.668 15.792 64.784 ;
     RECT  16.2 64.668 17.136 64.784 ;
     RECT  27.816 64.668 28.752 64.784 ;
     RECT  29.064 64.668 30 64.784 ;
     RECT  33.096 64.668 34.032 64.784 ;
     RECT  37.128 64.668 38.064 64.784 ;
     RECT  17.544 64.691 18.48 64.784 ;
  END
END ot_s81_engram_mix_control
END LIBRARY
